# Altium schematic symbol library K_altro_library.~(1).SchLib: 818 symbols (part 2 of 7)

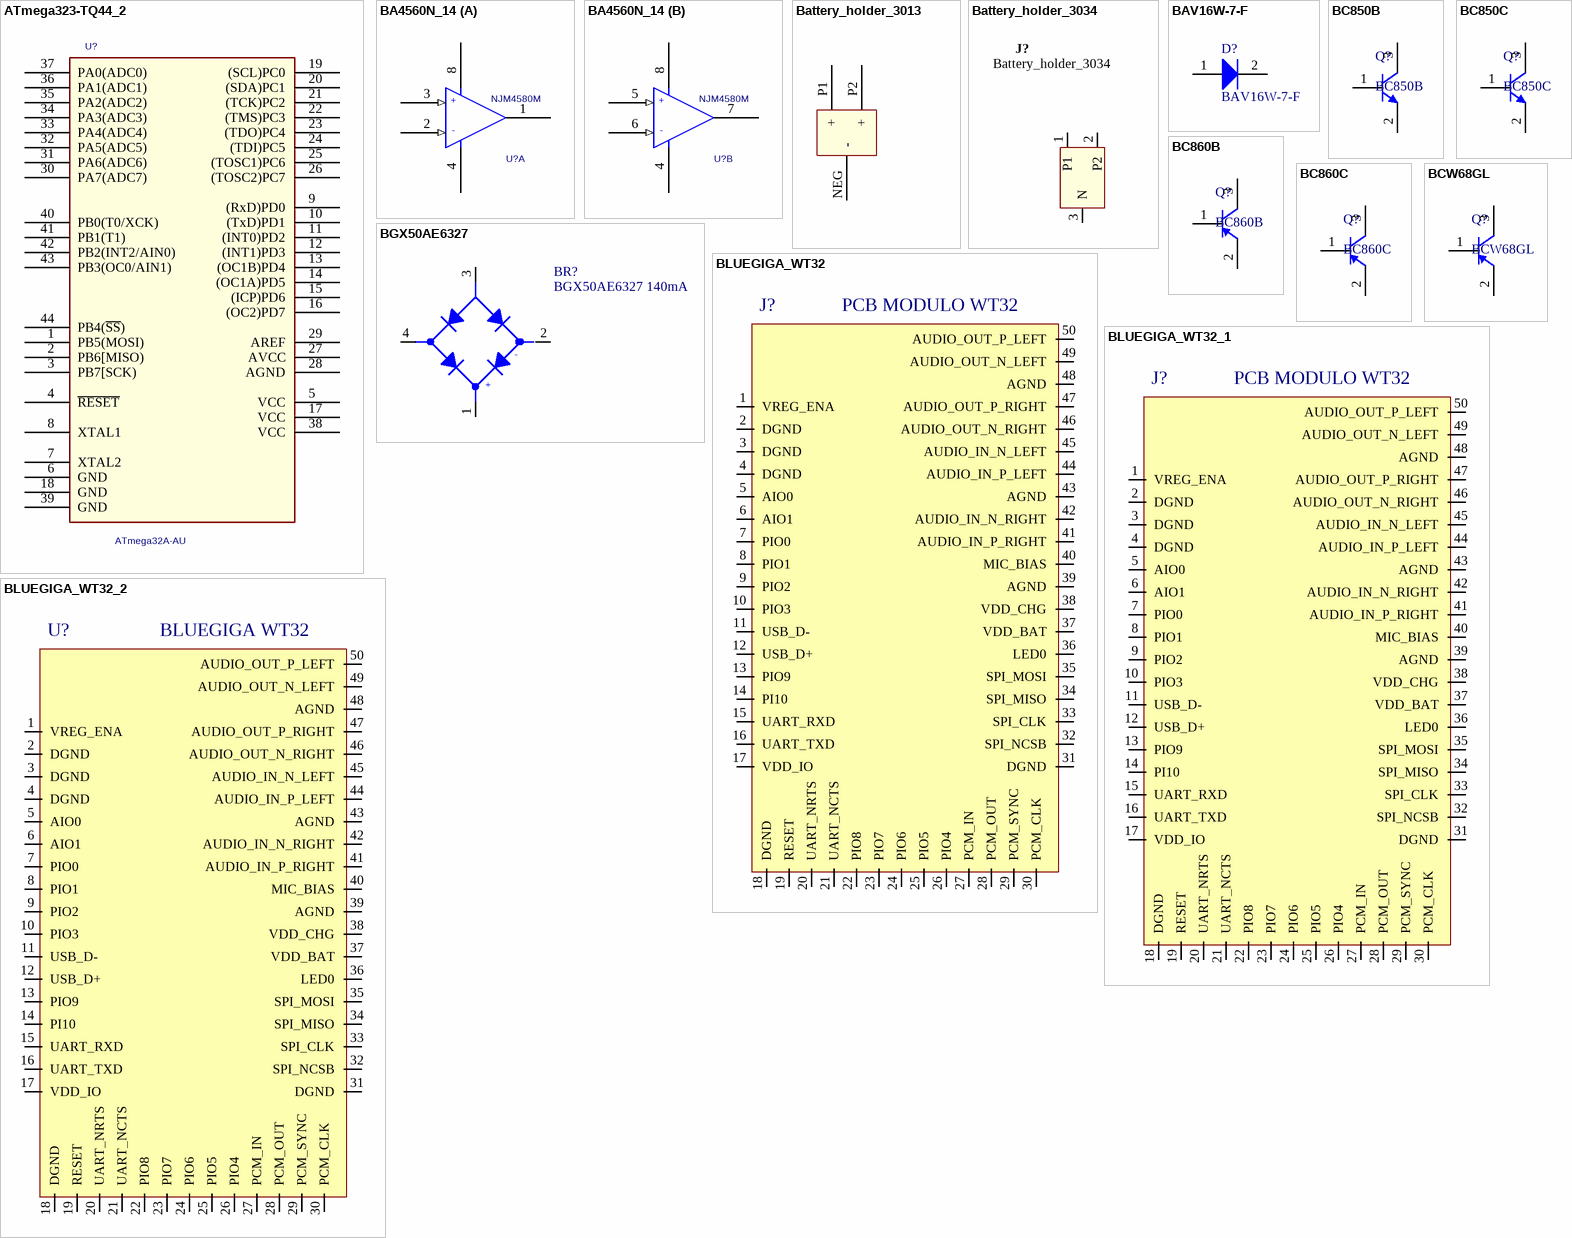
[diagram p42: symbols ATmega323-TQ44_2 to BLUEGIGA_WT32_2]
## Battery_holder_3034
designator J?
Aggiornato: s; Costo: 0,51; ContoLavoro: 0
footprint Battery_holder_Keystone_3034
pins: 1 P1, 2 P2, 3 N

## BAV16W-7-F
designator D?
Fast rectifier 100V, 300mA; Aggiornato: s; Costo: 0,178; ContoLavoro: 0
footprint SOD123
pins: 1 A, 2 k

## BC850B
designator Q?
BC850B General Purpose Transistor, NPN Silicon, 3-Pin SOT-23; MPN: BC850BLT1G; Costo: 0,037; Aggiornato: S; ContoLavoro: 0
footprint SOT-23_UP
simulation model QBC850B (BC850B)
pins: 1 B, 2 E, 3 C

## BC850C
designator Q?
BC850C General Purpose Transistor, NPN Silicon, 3-Pin SOT-23; Costo: 0,022; Aggiornato: S; ContoLavoro: 0
footprint SOT-23_UP
simulation model QBC850C (BC850C)
pins: 1 B, 2 E, 3 C

## BC860B
designator Q?
BC860B General Purpose Transistor, PNP Silicon, 3-Pin SOT-23; Costo: 0,016; Detail: (RS per >300pz); Aggiornato: S; ContoLavoro: 0
footprint SOT-23_UP
simulation model BC860B
pins: 1 B, 2 E, 3 C

## BC860C
designator Q?
BC860C General Purpose Transistor, PNP Silicon, 3-Pin SOT-23; Costo: 0,022; Aggiornato: S; ContoLavoro: 0
footprint SOT-23_UP
simulation model QBC860C (BC860C)
pins: 1 B, 2 E, 3 C

## BCW68GL
designator Q?
BCW68GL General Purpose Transistor, PNP Silicon, 3-Pin SOT-23; Costo: 0,037 €; Detail: 0,037 € 1000 pz MOUSER; Aggiornato: S; ContoLavoro: 0
footprint SOT23 -BCW68GL ((CASE-318 STYLE-6))
pins: 1 B, 2 E, 3 C

## BGX50AE6327
designator BR?, comment BGX50AE6327 140mA
BRIDGE DIODE 70V 140mA SOT143; Costo: 0,13772; Aggiornato: s; ContoLavoro: 0
footprint SOT143 - BGX50AE6327
pins: 1 AC1, 2 -DC, 3 AC2, 4 +DC

## BLUEGIGA_WT32
designator J?, comment PCB MODULO WT32
Aggiornato: NO; Costo: 0
footprint MODULO WT32
pins: 1 VREG_ENA, 2 DGND, 3 DGND, 4 DGND, 5 AIO0, 6 AIO1, 7 PIO0, 8 PIO1, 9 PIO2, 10 PIO3, 11 USB_D-, 12 USB_D+, 13 PIO9, 14 PI10, 15 UART_RXD, 16 UART_TXD, 17 VDD_IO, 18 DGND, 19 RESET, 20 UART_NRTS, 21 UART_NCTS, 22 PIO8, 23 PIO7, 24 PIO6, 25 PIO5, 26 PIO4, 27 PCM_IN, 28 PCM_OUT, 29 PCM_SYNC, 30 PCM_CLK, 31 DGND, 32 SPI_NCSB, 33 SPI_CLK, 34 SPI_MISO, 35 SPI_MOSI, 36 LED0, 37 VDD_BAT, 38 VDD_CHG, 39 AGND, 40 MIC_BIAS, 41 AUDIO_IN_P_RIGHT, 42 AUDIO_IN_N_RIGHT, 43 AGND, 44 AUDIO_IN_P_LEFT, 45 AUDIO_IN_N_LEFT, 46 AUDIO_OUT_N_RIGHT, 47 AUDIO_OUT_P_RIGHT, 48 AGND, 49 AUDIO_OUT_N_LEFT, 50 AUDIO_OUT_P_LEFT

## BLUEGIGA_WT32_1
designator J?, comment PCB MODULO WT32
Aggiornato: NO; Costo: 0
footprint MODULO WT32_MALE
pins: 1 VREG_ENA, 2 DGND, 3 DGND, 4 DGND, 5 AIO0, 6 AIO1, 7 PIO0, 8 PIO1, 9 PIO2, 10 PIO3, 11 USB_D-, 12 USB_D+, 13 PIO9, 14 PI10, 15 UART_RXD, 16 UART_TXD, 17 VDD_IO, 18 DGND, 19 RESET, 20 UART_NRTS, 21 UART_NCTS, 22 PIO8, 23 PIO7, 24 PIO6, 25 PIO5, 26 PIO4, 27 PCM_IN, 28 PCM_OUT, 29 PCM_SYNC, 30 PCM_CLK, 31 DGND, 32 SPI_NCSB, 33 SPI_CLK, 34 SPI_MISO, 35 SPI_MOSI, 36 LED0, 37 VDD_BAT, 38 VDD_CHG, 39 AGND, 40 MIC_BIAS, 41 AUDIO_IN_P_RIGHT, 42 AUDIO_IN_N_RIGHT, 43 AGND, 44 AUDIO_IN_P_LEFT, 45 AUDIO_IN_N_LEFT, 46 AUDIO_OUT_N_RIGHT, 47 AUDIO_OUT_P_RIGHT, 48 AGND, 49 AUDIO_OUT_N_LEFT, 50 AUDIO_OUT_P_LEFT

## BLUEGIGA_WT32_2
designator U?, comment BLUEGIGA WT32
Aggiornato: NO; Costo: 0
footprint BLUEGIGA_WT32
pins: 1 VREG_ENA, 2 DGND, 3 DGND, 4 DGND, 5 AIO0, 6 AIO1, 7 PIO0, 8 PIO1, 9 PIO2, 10 PIO3, 11 USB_D-, 12 USB_D+, 13 PIO9, 14 PI10, 15 UART_RXD, 16 UART_TXD, 17 VDD_IO, 18 DGND, 19 RESET, 20 UART_NRTS, 21 UART_NCTS, 22 PIO8, 23 PIO7, 24 PIO6, 25 PIO5, 26 PIO4, 27 PCM_IN, 28 PCM_OUT, 29 PCM_SYNC, 30 PCM_CLK, 31 DGND, 32 SPI_NCSB, 33 SPI_CLK, 34 SPI_MISO, 35 SPI_MOSI, 36 LED0, 37 VDD_BAT, 38 VDD_CHG, 39 AGND, 40 MIC_BIAS, 41 AUDIO_IN_P_RIGHT, 42 AUDIO_IN_N_RIGHT, 43 AGND, 44 AUDIO_IN_P_LEFT, 45 AUDIO_IN_N_LEFT, 46 AUDIO_OUT_N_RIGHT, 47 AUDIO_OUT_P_RIGHT, 48 AGND, 49 AUDIO_OUT_N_LEFT, 50 AUDIO_OUT_P_LEFT


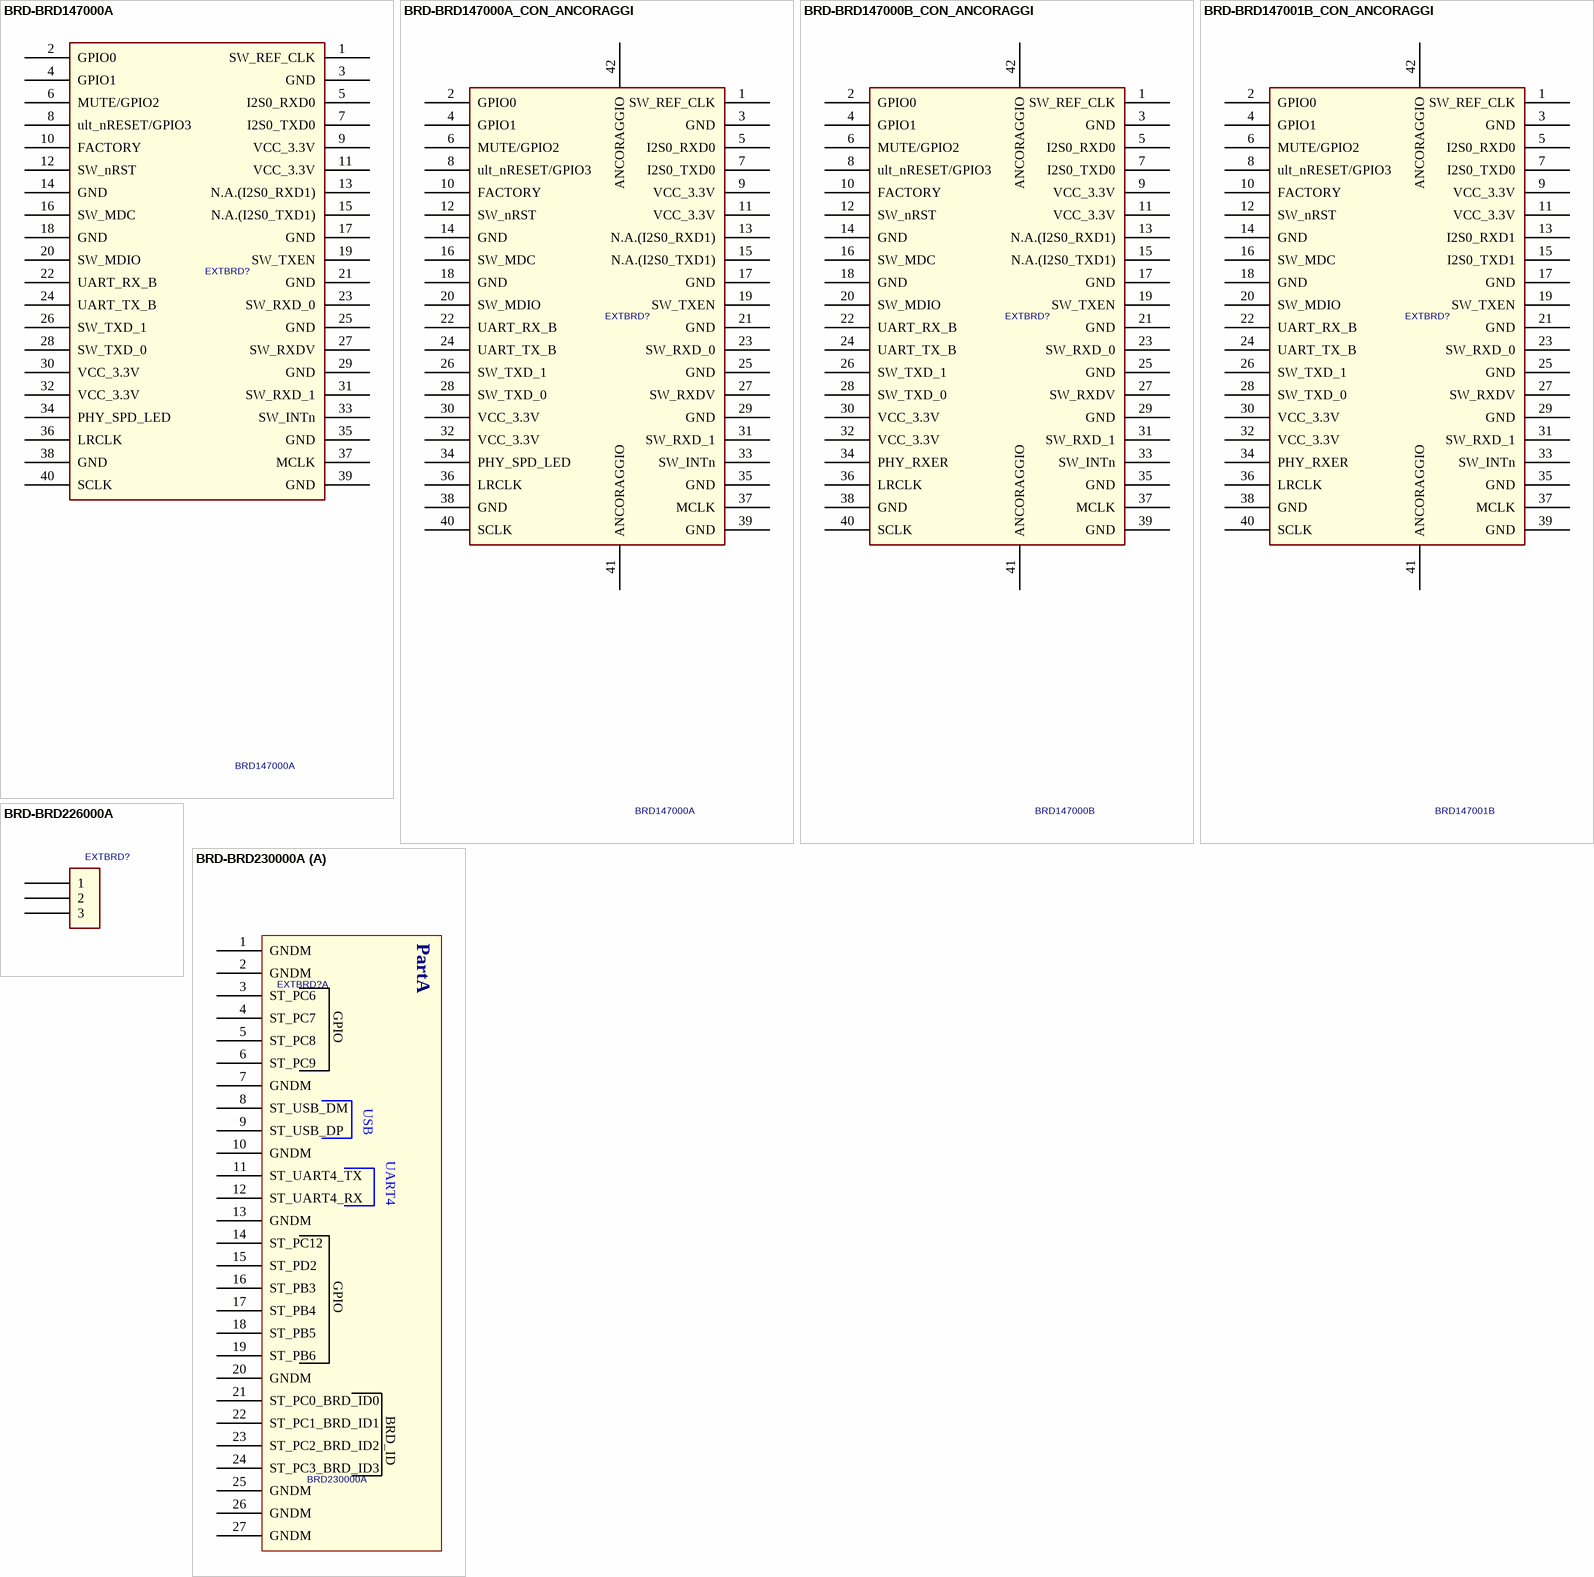
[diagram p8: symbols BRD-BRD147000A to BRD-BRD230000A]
## BRD-BRD147000A
designator EXTBRD?, comment BRD147000A  (no BOM)
BRD147000A Ultimo 2x2 module; Aggiornato: NO; Costo: 0
footprint BRD147000A_WITH_CONNECTOR (BRD147000A_Ultimo_2x2_module_vert)
pins: 1 SW_REF_CLK, 2 GPIO0, 3 GND, 4 GPIO1, 5 I2S0_RXD0, 6 MUTE/GPIO2, 7 I2S0_TXD0, 8 ult_nRESET/GPIO3, 9 VCC_3.3V, 10 FACTORY, 11 VCC_3.3V, 12 SW_nRST, 13 N.A.(I2S0_RXD1), 14 GND, 15 N.A.(I2S0_TXD1), 16 SW_MDC, 17 GND, 18 GND, 19 SW_TXEN, 20 SW_MDIO, 21 GND, 22 UART_RX_B, 23 SW_RXD_0, 24 UART_TX_B, 25 GND, 26 SW_TXD_1, 27 SW_RXDV, 28 SW_TXD_0, 29 GND, 30 VCC_3.3V, 31 SW_RXD_1, 32 VCC_3.3V, 33 SW_INTn, 34 PHY_SPD_LED, 35 GND, 36 LRCLK, 37 MCLK, 38 GND, 39 GND, 40 SCLK

## BRD-BRD147000A_CON_ANCORAGGI
designator EXTBRD?, comment BRD147000A  (no BOM)
BRD147000A Ultimo 2x2 module; Aggiornato: NO; Costo: 0
footprint BRD147000A_IBRID_CONN_VERT-CON_ANCORAGGI (BRD147000A_Ultimo_2x2_module_vert CON_ANCORAGGI)
pins: 1 SW_REF_CLK, 2 GPIO0, 3 GND, 4 GPIO1, 5 I2S0_RXD0, 6 MUTE/GPIO2, 7 I2S0_TXD0, 8 ult_nRESET/GPIO3, 9 VCC_3.3V, 10 FACTORY, 11 VCC_3.3V, 12 SW_nRST, 13 N.A.(I2S0_RXD1), 14 GND, 15 N.A.(I2S0_TXD1), 16 SW_MDC, 17 GND, 18 GND, 19 SW_TXEN, 20 SW_MDIO, 21 GND, 22 UART_RX_B, 23 SW_RXD_0, 24 UART_TX_B, 25 GND, 26 SW_TXD_1, 27 SW_RXDV, 28 SW_TXD_0, 29 GND, 30 VCC_3.3V, 31 SW_RXD_1, 32 VCC_3.3V, 33 SW_INTn, 34 PHY_SPD_LED, 35 GND, 36 LRCLK, 37 MCLK, 38 GND, 39 GND, 40 SCLK, 41 ANCORAGGIO, 42 ANCORAGGIO

## BRD-BRD147000B_CON_ANCORAGGI
designator EXTBRD?, comment BRD147000B  (no BOM)
BRD147000B Ultimo 2x2 module; Aggiornato: NO; Costo: 0
footprint BRD147000A_IBRID_CONN_VERT-CON_ANCORAGGI (BRD147000A_Ultimo_2x2_module_vert CON_ANCORAGGI)
pins: 1 SW_REF_CLK, 2 GPIO0, 3 GND, 4 GPIO1, 5 I2S0_RXD0, 6 MUTE/GPIO2, 7 I2S0_TXD0, 8 ult_nRESET/GPIO3, 9 VCC_3.3V, 10 FACTORY, 11 VCC_3.3V, 12 SW_nRST, 13 N.A.(I2S0_RXD1), 14 GND, 15 N.A.(I2S0_TXD1), 16 SW_MDC, 17 GND, 18 GND, 19 SW_TXEN, 20 SW_MDIO, 21 GND, 22 UART_RX_B, 23 SW_RXD_0, 24 UART_TX_B, 25 GND, 26 SW_TXD_1, 27 SW_RXDV, 28 SW_TXD_0, 29 GND, 30 VCC_3.3V, 31 SW_RXD_1, 32 VCC_3.3V, 33 SW_INTn, 34 PHY_RXER, 35 GND, 36 LRCLK, 37 MCLK, 38 GND, 39 GND, 40 SCLK, 41 ANCORAGGIO, 42 ANCORAGGIO

## BRD-BRD147001B_CON_ANCORAGGI
designator EXTBRD?, comment BRD147001B  (no BOM)
BRD147001B Ultimo 4x4 module; Aggiornato: NO; Costo: 0
footprint BRD147000A_IBRID_CONN_VERT-CON_ANCORAGGI (BRD147000A_Ultimo_2x2_module_vert CON_ANCORAGGI)
pins: 1 SW_REF_CLK, 2 GPIO0, 3 GND, 4 GPIO1, 5 I2S0_RXD0, 6 MUTE/GPIO2, 7 I2S0_TXD0, 8 ult_nRESET/GPIO3, 9 VCC_3.3V, 10 FACTORY, 11 VCC_3.3V, 12 SW_nRST, 13 I2S0_RXD1, 14 GND, 15 I2S0_TXD1, 16 SW_MDC, 17 GND, 18 GND, 19 SW_TXEN, 20 SW_MDIO, 21 GND, 22 UART_RX_B, 23 SW_RXD_0, 24 UART_TX_B, 25 GND, 26 SW_TXD_1, 27 SW_RXDV, 28 SW_TXD_0, 29 GND, 30 VCC_3.3V, 31 SW_RXD_1, 32 VCC_3.3V, 33 SW_INTn, 34 PHY_RXER, 35 GND, 36 LRCLK, 37 MCLK, 38 GND, 39 GND, 40 SCLK, 41 ANCORAGGIO, 42 ANCORAGGIO

## BRD-BRD226000A
designator EXTBRD?, comment BRD226000A  (no BOM)
Aggiornato: NO; Costo: 0
footprint BRD226000A (BRD147000A_Ultimo_2x2_module_vert)
pins: 1, 2, 3


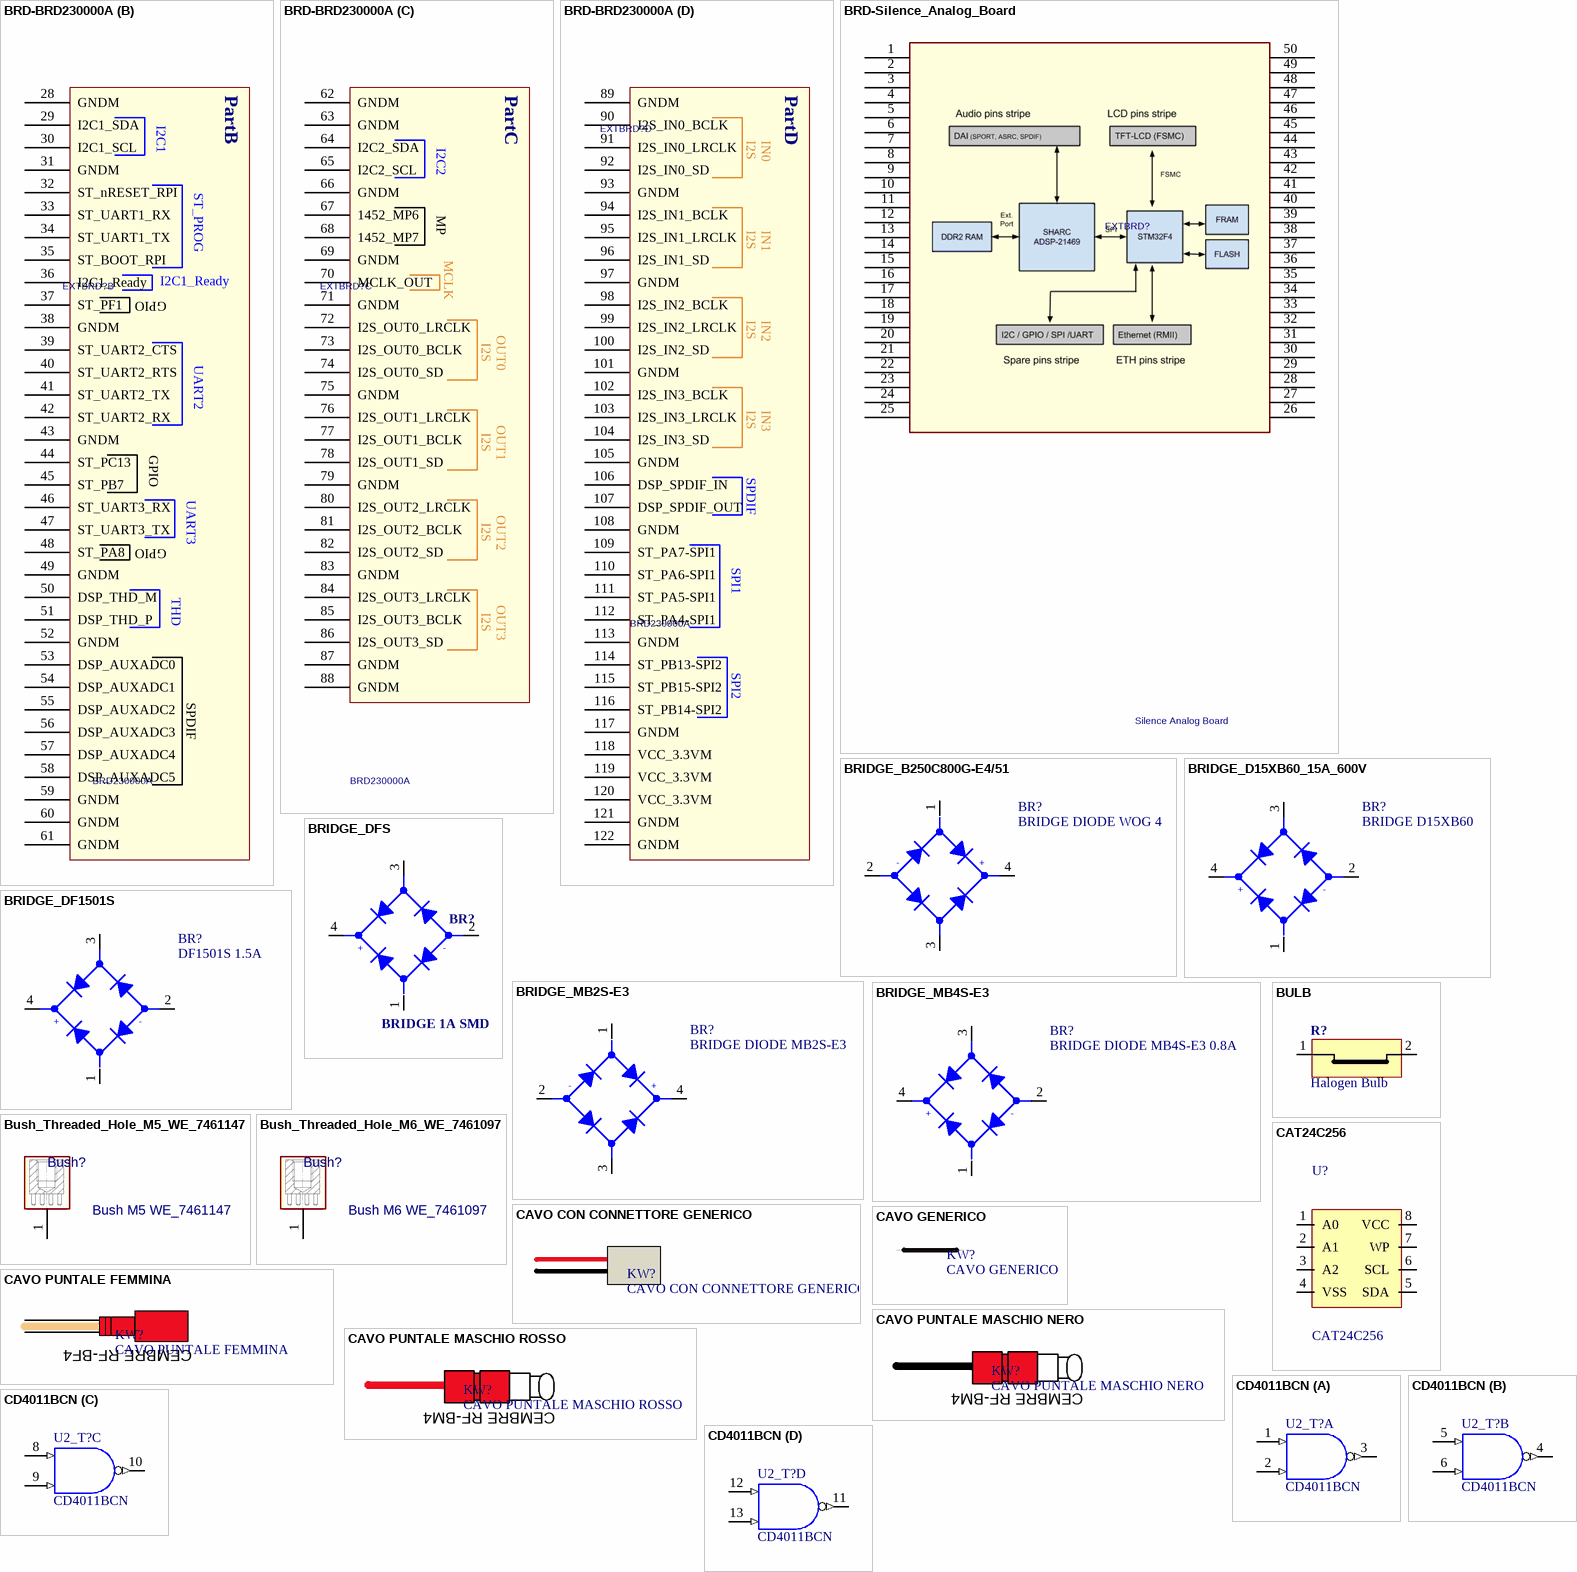
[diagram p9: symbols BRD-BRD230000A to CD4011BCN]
## BRD-BRD230000A
designator EXTBRD?, comment BRD230000A  (no BOM)
Aggiornato: NO; Costo: 0
footprint BRD230000A (Footprint not found)
footprint BRD230000A_with_RB_reference (BRD230000A with RB reference)
part A pins: 1 GNDM, 2 GNDM, 3 ST_PC6, 4 ST_PC7, 5 ST_PC8, 6 ST_PC9, 7 GNDM, 8 ST_USB_DM, 9 ST_USB_DP, 10 GNDM, 11 ST_UART4_TX, 12 ST_UART4_RX, 13 GNDM, 14 ST_PC12, 15 ST_PD2, 16 ST_PB3, 17 ST_PB4, 18 ST_PB5, 19 ST_PB6, 20 GNDM, 21 ST_PC0_BRD_ID0, 22 ST_PC1_BRD_ID1, 23 ST_PC2_BRD_ID2, 24 ST_PC3_BRD_ID3, 25 GNDM, 26 GNDM, 27 GNDM
part B pins: 28 GNDM, 29 I2C1_SDA, 30 I2C1_SCL, 31 GNDM, 32 ST_nRESET_RPI, 33 ST_UART1_RX, 34 ST_UART1_TX, 35 ST_BOOT_RPI, 36 I2C1_Ready, 37 ST_PF1, 38 GNDM, 39 ST_UART2_CTS, 40 ST_UART2_RTS, 41 ST_UART2_TX, 42 ST_UART2_RX, 43 GNDM, 44 ST_PC13, 45 ST_PB7, 46 ST_UART3_RX, 47 ST_UART3_TX, 48 ST_PA8, 49 GNDM, 50 DSP_THD_M, 51 DSP_THD_P, 52 GNDM, 53 DSP_AUXADC0, 54 DSP_AUXADC1, 55 DSP_AUXADC2, 56 DSP_AUXADC3, 57 DSP_AUXADC4, 58 DSP_AUXADC5, 59 GNDM, 60 GNDM, 61 GNDM
part C pins: 62 GNDM, 63 GNDM, 64 I2C2_SDA, 65 I2C2_SCL, 66 GNDM, 67 1452_MP6, 68 1452_MP7, 69 GNDM, 70 MCLK_OUT, 71 GNDM, 72 I2S_OUT0_LRCLK, 73 I2S_OUT0_BCLK, 74 I2S_OUT0_SD, 75 GNDM, 76 I2S_OUT1_LRCLK, 77 I2S_OUT1_BCLK, 78 I2S_OUT1_SD, 79 GNDM, 80 I2S_OUT2_LRCLK, 81 I2S_OUT2_BCLK, 82 I2S_OUT2_SD, 83 GNDM, 84 I2S_OUT3_LRCLK, 85 I2S_OUT3_BCLK, 86 I2S_OUT3_SD, 87 GNDM, 88 GNDM
part D pins: 89 GNDM, 90 I2S_IN0_BCLK, 91 I2S_IN0_LRCLK, 92 I2S_IN0_SD, 93 GNDM, 94 I2S_IN1_BCLK, 95 I2S_IN1_LRCLK, 96 I2S_IN1_SD, 97 GNDM, 98 I2S_IN2_BCLK, 99 I2S_IN2_LRCLK, 100 I2S_IN2_SD, 101 GNDM, 102 I2S_IN3_BCLK, 103 I2S_IN3_LRCLK, 104 I2S_IN3_SD, 105 GNDM, 106 DSP_SPDIF_IN, 107 DSP_SPDIF_OUT, 108 GNDM, 109 ST_PA7-SPI1, 110 ST_PA6-SPI1, 111 ST_PA5-SPI1, 112 ST_PA4-SPI1, 113 GNDM, 114 ST_PB13-SPI2, 115 ST_PB15-SPI2, 116 ST_PB14-SPI2, 117 GNDM, 118 VCC_3.3VM, 119 VCC_3.3VM, 120 VCC_3.3VM, 121 GNDM, 122 GNDM

## BRD-Silence_Analog_Board
designator EXTBRD?, comment Silence Analog Board
Aggiornato: NO; Costo: 0
footprint BRD_SILENCE_ANALOG_BOARD_SOCKET
pins: 1, 2, 3, 4, 5, 6, 7, 8, 9, 10, 11, 12, 13, 14, 15, 16, 17, 18, 19, 20, 21, 22, 23, 24, 25, 26, 27, 28, 29, 30, 31, 32, 33, 34, 35, 36, 37, 38, 39, 40, 41, 42, 43, 44, 45, 46, 47, 48, 49, 50

## BRIDGE_B250C800G-E4/51
designator BR?, comment BRIDGE DIODE WOG 4
MPN: B250C800G-E4/51; Costo: 0,434; Aggiornato: NO; ContoLavoro: 0
footprint TO-269AA
footprint BRIDGE AM106
pins: 1 AC1, 2 -DC, 3 AC2, 4 +DC

## BRIDGE_D15XB60_15A_600V
designator BR?, comment BRIDGE D15XB60
BRIDGE D15XB60 15A 600V; Costo: 0; Aggiornato: NO
pins: 1 AC1, 2 -DC, 3 AC2, 4 +DC

## BRIDGE_DF1501S
designator BR?, comment DF1501S 1.5A
BRIDGE DIODE DF1501S 100V 1.5A; MPN: DF1501S-E3/77; Costo: 0,3; Aggiornato: s; ContoLavoro: 0
footprint DFS_BRIDGE
pins: 1 AC1, 2 -DC, 3 AC2, 4 +DC

## BRIDGE_DFS
designator BR?, comment BRIDGE 1A SMD
Full Wave Diode Bridge; Aggiornato: NO; Costo: 0
footprint DFS_BRIDGE
pins: 1 AC1, 2 -DC, 3 AC2, 4 +DC

## BRIDGE_MB2S-E3
designator BR?, comment BRIDGE DIODE MB2S-E3
Aggiornato: NO; Costo: 0
footprint TO-269AA
pins: 1 AC1, 2 -DC, 3 AC2, 4 +DC

## BRIDGE_MB4S-E3
designator BR?, comment BRIDGE DIODE MB4S-E3 0.8A
Costo: 0,366; Aggiornato: NO; ContoLavoro: 0
footprint TO-269AA
pins: 1 AC1, 2 -DC, 3 AC2, 4 +DC

## BULB
designator R?, comment Halogen Bulb
Hpcode: HALOGENBULB01; Aggiornato: NO; Costo: 0
footprint Halogen Bulb SETCROSSOVER ZHAL_V2
footprint Halogen Bulb SETCROSSOVER ZHAL_V2
footprint Halogen Bulb SETCROSSOVER ZHAL_V3
footprint Halogen Bulb SETCROSSOVER ZHAL_V1
pins: 1 VSS, 2 VSS

## Bush_Threaded_Hole_M5_WE_7461147
designator Bush?, comment Bush M5 WE_7461147
Bush_Threaded_Hole_M5_WE_7461147; Detail: Costo da verificare.; Costo: 3€; Aggiornato: NO; ContoLavoro: 0
footprint WE-7461147
pins: 1 Bush

## Bush_Threaded_Hole_M6_WE_7461097
designator Bush?, comment Bush M6 WE_7461097
Bush_Threaded_Hole_M6_WE_7461097; Detail: Costo da verificare.; Costo: 3€; Aggiornato: NO; ContoLavoro: 0
footprint WE-7461097
pins: 1 Bush

## CAT24C256
designator U?
CAT24C256 Serial  EEPROM 256K; Costo: 0,29; Aggiornato: S; ContoLavoro: 0
footprint SO8
footprint SOIC150-8N
pins: 1 A0, 2 A1, 3 A2, 4 VSS, 5 SDA, 6 SCL, 7 WP, 8 VCC

## CAVO CON CONNETTORE GENERICO
designator KW?  (mechanical)
Aggiornato: SI; Costo: 0; ContoLavoro: 1

## CAVO GENERICO
designator KW?  (mechanical)
Aggiornato: SI; Costo: 0; ContoLavoro: 1

## CAVO PUNTALE FEMMINA
designator KW?
Aggiornato: SI; Costo: 0; ContoLavoro: 1

## CAVO PUNTALE MASCHIO NERO
designator KW?
Aggiornato: SI; Costo: 0; ContoLavoro: 1

## CAVO PUNTALE MASCHIO ROSSO
designator KW?
Aggiornato: SI; Costo: 0; ContoLavoro: 1

## CD4011BCN
designator U2_T?
Quad 2-Input NAND Buffered B series Gate, 14-Pin PDIP; Aggiornato: NO; Costo: 0
footprint N14A (DIP, 14-Leads, Row Spacing 7.62mm, Pitch 2.54mm, Body 19.18x6.35mm)
3D model N14A (DIP, 14-Pin, Row Spacing 7.62 mm, Pitch 2.54 mm)
simulation model FSC_4011 (SIMCODE)
pins on every part: 7 GND_T (power) hidden to GND, 14 +12V_T (power) hidden to VDD
part A pins: 1 A (in), 2 B (in), 3 J (out)
part B pins: 4 J (out), 5 A (in), 6 B (in)
part C pins: 8 A (in), 9 F (in), 10 J (out)
part D pins: 11 J (out), 12 A (in), 13 B (in)


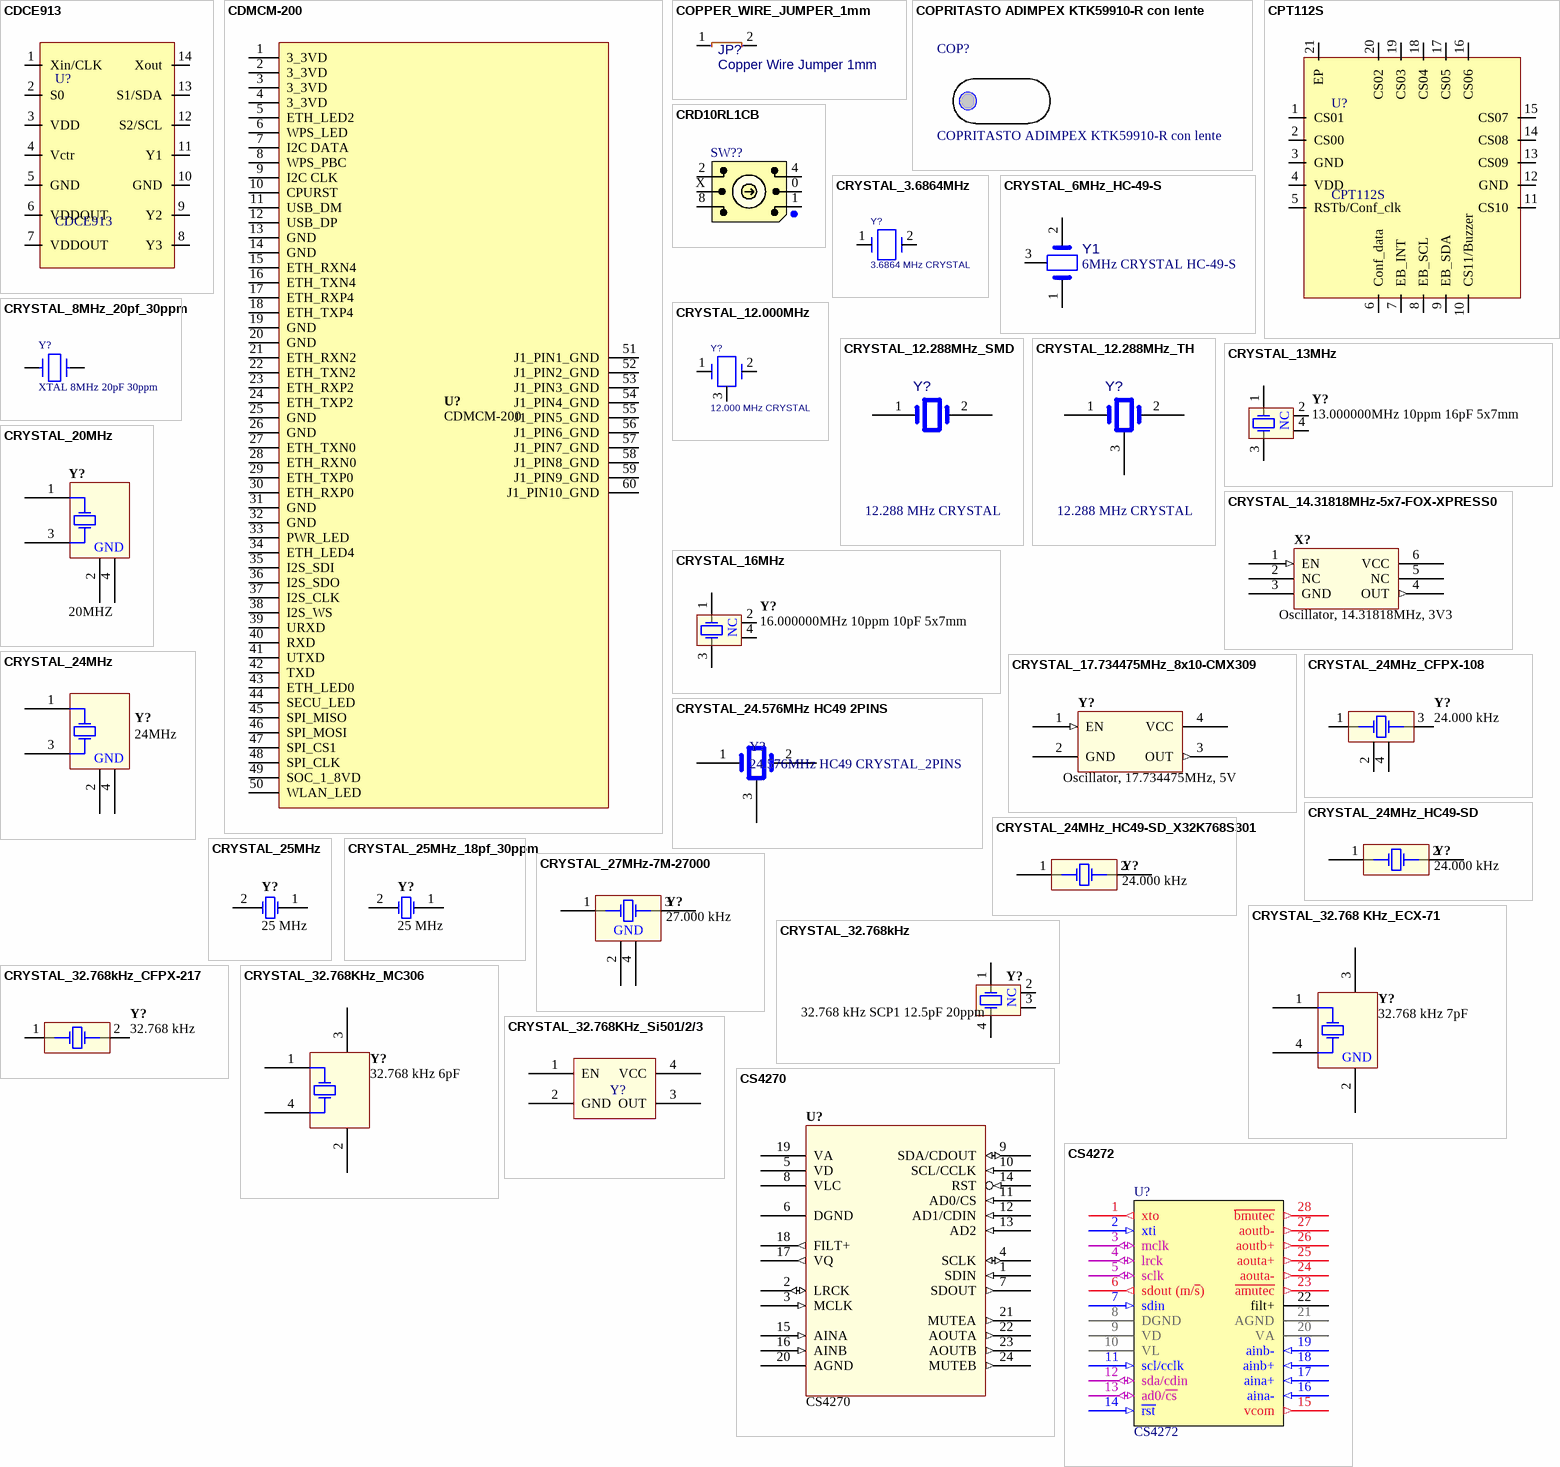
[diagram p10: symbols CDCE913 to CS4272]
## CDCE913
designator U?
Detail: 2,21€ >250pz Mouser 595-CDCE913PWR; Costo: 2,21€; Aggiornato: S; ContoLavoro: 0
footprint TSSOP14
pins: 1 Xin/CLK, 2 S0, 3 VDD, 4 Vctr, 5 GND, 6 VDDOUT, 7 VDDOUT, 8 Y3, 9 Y2, 10 GND, 11 Y1, 12 S2/SCL, 13 S1/SDA, 14 Xout

## CDMCM-200
designator U?
CDMCM-200 WI-FI Audio Module; Aggiornato: NO; Costo: 0
footprint CDMCM-200 (Footprint not found)
pins: 1 3_3VD, 2 3_3VD, 3 3_3VD, 4 3_3VD, 5 ETH_LED2, 6 WPS_LED, 7 I2C DATA, 8 WPS_PBC, 9 I2C CLK, 10 CPURST, 11 USB_DM, 12 USB_DP, 13 GND, 14 GND, 15 ETH_RXN4, 16 ETH_TXN4, 17 ETH_RXP4, 18 ETH_TXP4, 19 GND, 20 GND, 21 ETH_RXN2, 22 ETH_TXN2, 23 ETH_RXP2, 24 ETH_TXP2, 25 GND, 26 GND, 27 ETH_TXN0, 28 ETH_RXN0, 29 ETH_TXP0, 30 ETH_RXP0, 31 GND, 32 GND, 33 PWR_LED, 34 ETH_LED4, 35 I2S_SDI, 36 I2S_SDO, 37 I2S_CLK, 38 I2S_WS, 39 URXD, 40 RXD, 41 UTXD, 42 TXD, 43 ETH_LED0, 44 SECU_LED, 45 SPI_MISO, 46 SPI_MOSI, 47 SPI_CS1, 48 SPI_CLK, 49 SOC_1_8VD, 50 WLAN_LED, 51 J1_PIN1_GND, 52 J1_PIN2_GND, 53 J1_PIN3_GND, 54 J1_PIN4_GND, 55 J1_PIN5_GND, 56 J1_PIN6_GND, 57 J1_PIN7_GND, 58 J1_PIN8_GND, 59 J1_PIN9_GND, 60 J1_PIN10_GND

## COPPER_WIRE_JUMPER_1mm
designator JP?, comment Copper Wire Jumper 1mm
Copper Wire Jumper D=1mm; Hpcode: MMBLC061; Costo: 0,1; Value: 0; Aggiornato: S
footprint HARWIN_D3080-05 (HARWIN D3080-05)
simulation model Resistor
pins: 1, 2

## COPRITASTO ADIMPEX KTK59910-R con lente
designator COP?  (mechanical)
Costo: 0; Aggiornato: NO; Detail: 0,06€ 1000pz WE offerta A18IT013140.pdf
pins: 1 hidden
1 alternate drawing of the same symbol

## CPT112S
designator U?
Capacitive touch controller via I2C; Hpcode: ICCPT112S; Costo: 0; Aggiornato: n; ContoLavoro: 1
footprint QFN20_EP_CPT112S
pins: 1 CS01, 2 CS00, 3 GND, 4 VDD, 5 RSTb/Conf_clk, 6 Conf_data, 7 EB_INT, 8 EB_SCL, 9 EB_SDA, 10 CS11/Buzzer, 11 CS10, 12 GND, 13 CS09, 14 CS08, 15 CS07, 16 CS06, 17 CS05, 18 CS04, 19 CS03, 20 CS02, 21 EP

## CRD10RL1CB
designator SW??, comment 0.4VA  (value not drawn)
DIP-Coded Rotary Switch 10-Position BCD 0.4VA, DC20V Body (10x10)mm CRD Series; Voltage: 20V; Aggiornato: NO; Costo: 0
footprint CRD10R_itt-cannon
pins: 0, 1, 2, 4, 8, X
1 alternate drawing of the same symbol

## CRYSTAL_3.6864MHz
designator Y?, comment 3.6864 MHz CRYSTAL
Aggiornato: NO; Costo: 0
footprint CRYSTAL
pins: 1, 2

## CRYSTAL_6MHz_HC-49-S
designator Y1, comment 6MHz CRYSTAL HC-49-S
Crystal 6MHz HC-49-S; Detail: (RS per >500pz); Costo: 0,23; Aggiornato: s; ContoLavoro: 0
footprint CRYSTAL_3PINS
pins: 1, 2, 3

## CRYSTAL_8MHz_20pf_30ppm
designator Y?, comment XTAL 8MHz 20pF 30ppm
8MHz 20pF 30ppm; Aggiornato: Si; Costo: 0,2065; ContoLavoro: 0
footprint qz_sx_smd_hc49
pins: 1, 2
2 alternate drawings of the same symbol

## CRYSTAL_12.000MHz
designator Y?, comment 12.000 MHz CRYSTAL
Detail: ADIMPEX LQS12.000; Aggiornato: NO; Costo: 0
footprint CRISTAL
pins: 1, 2, 3

## CRYSTAL_12.288MHz_SMD
designator Y?, comment 12.288 MHz CRYSTAL
Costo: 0,3; Aggiornato: S; ContoLavoro: 0
footprint qz_sx_smd_hc49
pins: 1, 2

## CRYSTAL_12.288MHz_TH
designator Y?, comment 12.288 MHz CRYSTAL
Detail: Disrelec > 100pz; Costo: 0,58; Aggiornato: NO; ContoLavoro: 0
footprint CRYSTAL_3PINS
pins: 1, 2, 3

## CRYSTAL_13MHz
designator Y?, comment 13.000000MHz 10ppm 16pF 5x7mm
Crystal, 13.000000MHz, 5x7mm, 10ppm 10ppm 16pF; Nominal Fequency: 13 MHz; Nominal Operational Voltage: mV; Aggiornato: NO; Costo: 0
footprint XTAL-7X5
pins: 1 X1, 2 NC, 3 X2, 4 NC

## CRYSTAL_14.31818MHz-5x7-FOX-XPRESS0
designator X?, comment Oscillator, 14.31818MHz, 3V3
Crystal Oscillator, 14.31818MHz, 3V3, 5x7mm, 50ppm, Fox, FXO-HC735R-14.31818; Aggiornato: NO; Costo: 0
footprint OSCILLATOR-5x7-FOX-XPRESS0
pins: 1 EN (in), 2 NC, 3 GND (power), 4 OUT (out), 5 NC, 6 VCC (power)

## CRYSTAL_16MHz
designator Y?, comment 16.000000MHz 10ppm 10pF 5x7mm
Crystal, 16.000000MHz, 5x7mm, 10ppm 10ppm 10pF; Nominal Fequency: 16 MHz; Nominal Operational Voltage: mV; Aggiornato: NO; Costo: 0
footprint XTAL-7X5
pins: 1 X1, 2 NC, 3 X2, 4 NC

## CRYSTAL_17.734475MHz_8x10-CMX309
designator Y?, comment Oscillator, 17.734475MHz, 5V
Crystal Oscillator, 17.734475MHz, 50ppm, 5V, 8x10mm, SMD; Aggiornato: NO; Costo: 0
footprint OSCILLATOR-8x10-CMX309
pins: 1 EN (in), 2 GND (power), 3 OUT (out), 4 VCC (power)

## CRYSTAL_20MHz
designator Y?, comment 20MHZ
Crystal, SMD, 20.000000MHz Stab=30ppm 20.0pF; Frequency Stability: 30 ppm; Load Capacitance: 20 pF; Nominal Operational Voltage: mV; Aggiornato: NO; Costo: 0
footprint XTAL-200X126-4
pins: 1 X1, 2 GND, 3 X2, 4 GND

## CRYSTAL_24.576MHz HC49 2PINS
designator Y?, comment 24.576MHz HC49 CRYSTAL_2PINS
Detail: prezzo RS >500pz; Costo: 0,32; ContoLavoro: 0
footprint CRYSTAL_3PINS
pins: 1, 2, 3

## CRYSTAL_24MHz
designator Y?, comment 24MHz
Crystal, SMD, 24.000000MHz Stab=30ppm 20.0pF; Frequency Stability: 30 ppm; Load Capacitance: 20 pF; Nominal Operational Voltage: mV; Aggiornato: NO; Costo: 0
footprint XTAL-200X126-4
pins: 1 X1, 2 GND, 3 X2, 4 GND

## CRYSTAL_24MHz_CFPX-108
designator Y?, comment 24.000 kHz
Crystal, 24MHz CFPX-108; Aggiornato: s; Costo: 0,26; Detail: Offerta WE A21IT006030 0,26€ per1000pz 0,16 per 3000pz; ContoLavoro: 0
footprint CFPX-108 (Footprint not found)
pins: 1 X1, 2 GND, 3 X2, 4 GND

## CRYSTAL_24MHz_HC49-SD
designator Y?, comment 24.000 kHz
Crystal, 24MHz HC49-SD; Aggiornato: n; Costo: 0
footprint HC49-SD (Footprint not found)
pins: 1 X1, 2 X2

## CRYSTAL_24MHz_HC49-SD_X32K768S301
designator Y?, comment 24.000 kHz
Crystal, 24MHz HC49-SD; Aggiornato: n; Costo: 0
footprint HC49-SD (Footprint not found)
pins: 1 X1, 2 X2

## CRYSTAL_25MHz
designator Y?, comment 25 MHz
Crystal, 25 MHz  +/-30ppm 20pf HC49SMD; Frequency Stability: 30 ppm; Nominal Operational Voltage: mV; Aggiornato: NO; Costo: 0
footprint XTAL_HC49SMD
pins: 1 OSC1, 2 OSC2

## CRYSTAL_25MHz_18pf_30ppm
designator Y?, comment 25 MHz
CRYSTAL_25MHz_18pf_30ppm; Aggiornato: s; Costo: 0,40; ContoLavoro: 0
footprint qz_sx_smd_hc49
pins: 1 OSC1, 2 OSC2

## CRYSTAL_27MHz-7M-27000
designator Y?, comment 27.000 kHz
Crystal, 27MHz 7M-27.000 MEEQ-T; Aggiornato: s; Costo: 1,08; HPcode: QUARZ27MHZ; ContoLavoro: 1
footprint QZ_SMALL_SMD
pins: 1 X1, 2 GND, 3 X2, 4 GND

## CRYSTAL_32.768 KHz_ECX-71
designator Y?, comment 32.768 kHz 7pF
Crystal, 32.768 KHz Surface Mount; Aggiornato: NO; Costo: 0
footprint ECS-71
pins: 1 X1, 2 GND, 3 X2, 4 GND

## CRYSTAL_32.768kHz
designator Y?, comment 32.768 kHz SCP1 12.5pF 20ppm
Crystal, 32.768 kHz, Surface Mount SCP1, 12.5pF, 20ppm; Frequency Stability: parabolic ppm; Nominal Operational Voltage: mV; Aggiornato: NO; Costo: 0
footprint XTAL-SCP1
pins: 1 X1, 2 NC, 3 NC, 4 X2

## CRYSTAL_32.768kHz_CFPX-217
designator Y?, comment 32.768 kHz
Crystal 32.768 kHz CFPX-217; Aggiornato: s; Costo: 0,285; Detail: Offerta WE A21IT006030 0,285 € per 1000pz 0,175€ per 3000pz; ContoLavoro: 0
footprint CFPX-217 (Footprint not found)
pins: 1 X1, 2 X2

## CRYSTAL_32.768KHz_MC306
designator Y?, comment 32.768 kHz 6pF
Crystal, 32.768KHz MC306; Aggiornato: s; Costo: 1; ContoLavoro: 0
footprint QZ_MC306
pins: 1, 2, 3, 4

## CRYSTAL_32.768KHz_Si501/2/3
designator Y?
32.768kHz Oscillator (EPSON  X1B0002110001 SG-3030CM); Costo: 0; Aggiornato: N
footprint CRYSTAL_3.2X1.5MM_4P_SMD
pins: 1 EN, 2 GND, 3 OUT, 4 VCC

## CS4270
designator U?
CS4270; 24-Bit, 192 kHz Stereo Audio CODEC; Supply Voltage: mV; Aggiornato: NO; Costo: 0
footprint TSSOP-24
pins: 1 SDIN (in), 2 LRCK (io), 3 MCLK (in), 4 SCLK (io), 5 VD (power), 6 DGND (power), 7 SDOUT (out), 8 VLC (power), 9 SDA/CDOUT (io), 10 SCL/CCLK (in), 11 AD0/CS (in), 12 AD1/CDIN (in), 13 AD2 (in), 14 RST (in), 15 AINA (in), 16 AINB (in), 17 VQ (out), 18 FILT+ (out), 19 VA (power), 20 AGND (power), 21 MUTEA (out), 22 AOUTA (out), 23 AOUTB (out), 24 MUTEB (out)

## CS4272
designator U?
CODEC AUDIO CS4272; Costo: 2,62; Hpcode: ICCIRCS4272-CZZ; Aggiornato: S; ContoLavoro: 0
footprint SSOP_28
pins: 1 xto (out), 2 xti (in), 3 mclk (io), 4 lrck (io), 5 sclk (io), 6 sdout (m/~{s}) (out), 7 sdin (in), 8 DGND (power), 9 VD (power), 10 VL (power), 11 scl/cclk (in), 12 sda/cdin (io), 13 ad0/~{cs} (io), 14 ~{rst} (in), 15 vcom (out), 16 aina- (in), 17 aina+ (in), 18 ainb+ (in), 19 ainb- (in), 20 VA (power), 21 AGND (power), 22 filt+, 23 ~{amutec} (out), 24 aouta- (out), 25 aouta+ (out), 26 aoutb+ (out), 27 aoutb- (out), 28 ~{bmutec} (out)


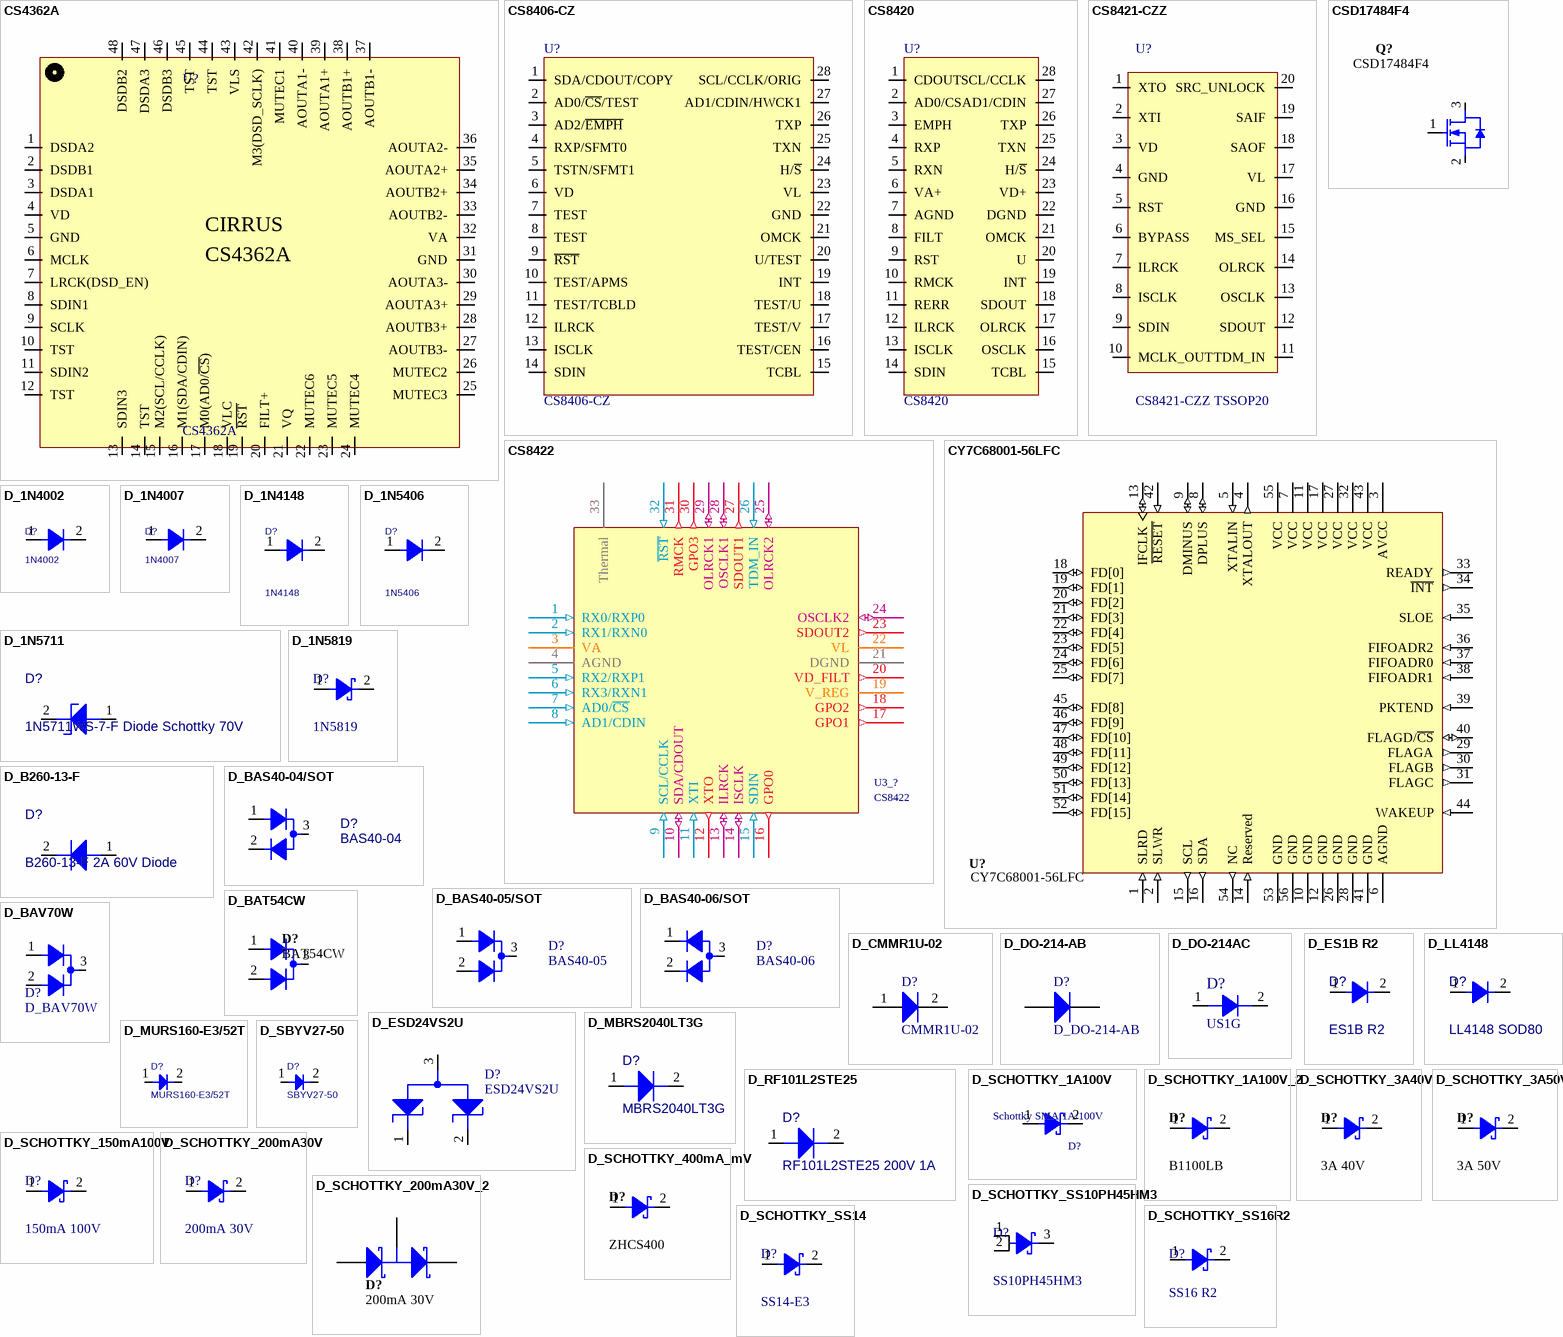
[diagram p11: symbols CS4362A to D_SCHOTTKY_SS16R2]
## CS4362A
designator U?
Costo: 2,8; Aggiornato: S; ContoLavoro: 0
footprint LQFP-48
pins: 1 DSDA2, 2 DSDB1, 3 DSDA1, 4 VD, 5 GND, 6 MCLK, 7 LRCK(DSD_EN), 8 SDIN1, 9 SCLK, 10 TST, 11 SDIN2, 12 TST, 13 SDIN3, 14 TST, 15 M2(SCL/CCLK), 16 M1(SDA/CDIN), 17 M0(AD0/~{CS}), 18 VLC, 19 ~{RST}, 20 FILT+, 21 VQ, 22 MUTEC6, 23 MUTEC5, 24 MUTEC4, 25 MUTEC3, 26 MUTEC2, 27 AOUTB3-, 28 AOUTB3+, 29 AOUTA3+, 30 AOUTA3-, 31 GND, 32 VA, 33 AOUTB2-, 34 AOUTB2+, 35 AOUTA2+, 36 AOUTA2-, 37 AOUTB1-, 38 AOUTB1+, 39 AOUTA1+, 40 AOUTA1-, 41 MUTEC1, 42 M3(DSD_SCLK), 43 VLS, 44 TST, 45 TST, 46 DSDB3, 47 DSDA3, 48 DSDB2

## CS8406-CZ
designator U?
Costo: 4; Aggiornato: s; ContoLavoro: 0
footprint tssop28_n (TSOP, 28-Leads, Body 9.7x4.4mm, Pitch 0.65mm, IPC Medium Density)
pins: 1 SDA/CDOUT/COPY, 2 AD0/~{CS}/TEST, 3 AD2/~{EMPH}, 4 RXP/SFMT0, 5 TSTN/SFMT1, 6 VD, 7 TEST, 8 TEST, 9 ~{RST}, 10 TEST/APMS, 11 TEST/TCBLD, 12 ILRCK, 13 ISCLK, 14 SDIN, 15 TCBL, 16 TEST/CEN, 17 TEST/V, 18 TEST/U, 19 INT, 20 U/TEST, 21 OMCK, 22 GND, 23 VL, 24 H/~{S}, 25 TXN, 26 TXP, 27 AD1/CDIN/HWCK1, 28 SCL/CCLK/ORIG

## CS8420
designator U?
Costo: 0; Aggiornato: NO
footprint SOJ.050/28/WB.300/L.700
pins: 1 CDOUT, 2 AD0/CS, 3 EMPH, 4 RXP, 5 RXN, 6 VA+, 7 AGND, 8 FILT, 9 RST, 10 RMCK, 11 RERR, 12 ILRCK, 13 ISCLK, 14 SDIN, 15 TCBL, 16 OSCLK, 17 OLRCK, 18 SDOUT, 19 INT, 20 U, 21 OMCK, 22 DGND, 23 VD+, 24 H/~{S}, 25 TXN, 26 TXP, 27 AD1/CDIN, 28 SCL/CCLK

## CS8421-CZZ
designator U?, comment CS8421-CZZ TSSOP20
Costo: 9,01; Aggiornato: SI; ContoLavoro: 0
footprint TSSOP20
pins: 1 XTO, 2 XTI, 3 VD, 4 GND, 5 RST, 6 BYPASS, 7 ILRCK, 8 ISCLK, 9 SDIN, 10 MCLK_OUT, 11 TDM_IN, 12 SDOUT, 13 OSCLK, 14 OLRCK, 15 MS_SEL, 16 GND, 17 VL, 18 SAOF, 19 SAIF, 20 SRC_UNLOCK

## CS8422
designator U3_?
24-bit, 192-kHz, Asynchronous Sample Rate Converter with  Integrated Digital Audio Interface Receiver; Aggiornato: NO; Costo: 0
footprint QFN32V4M (QFN, 32-Leads, Body 5x5mm, Pitch 0.5mm, IPC Low Density)
pins: 1 RX0/RXP0 (in), 2 RX1/RXN0 (in), 3 VA, 4 AGND, 5 RX2/RXP1 (in), 6 RX3/RXN1 (in), 7 AD0/~{CS} (in), 8 AD1/CDIN (in), 9 SCL/CCLK (in), 10 SDA/CDOUT (io), 11 XTI (in), 12 XTO (out), 13 ILRCK (io), 14 ISCLK (io), 15 SDIN (in), 16 GPO0 (out), 17 GPO1 (out), 18 GPO2 (out), 19 V_REG, 20 VD_FILT (out), 21 DGND, 22 VL, 23 SDOUT2 (out), 24 OSCLK2 (io), 25 OLRCK2 (io), 26 TDM_IN (in), 27 SDOUT1 (out), 28 OSCLK1 (io), 29 OLRCK1 (io), 30 GPO3 (out), 31 RMCK (out), 32 ~{RST} (in), 33 Thermal

## CSD17484F4
designator Q?
N-Channel FemtoFET 99-mΩ, 30-V Digi-Key Part Number (296-47319-2-ND - Tape & Reel) (296-47319-1-ND - Cut Tape) (296-47319-6-ND - Digi-Reel); Aggiornato: S; Costo: 0,124; ContoLavoro: 0
footprint 3-XFDFN-CSD17484F4
pins: 1 G, 2 S, 3 D

## CY7C68001-56LFC
designator U?
CY7C68001-56LFC, EZ-USB SX2 High-Speed USB Interface; Aggiornato: NO; Costo: 0
footprint QFN50P800X800_HS-57
pins: 1 SLRD (in), 2 SLWR (in), 3 AVCC (power), 4 XTALOUT (out), 5 XTALIN (in), 6 AGND (power), 7 VCC (power), 8 DPLUS (io), 9 DMINUS (io), 10 GND (power), 11 VCC (power), 12 GND (power), 13 IFCLK (io), 14 Reserved (in), 15 SCL (out), 16 SDA (out), 17 VCC (power), 18 FD[0] (io), 19 FD[1] (io), 20 FD[2] (io), 21 FD[3] (io), 22 FD[4] (io), 23 FD[5] (io), 24 FD[6] (io), 25 FD[7] (io), 26 GND (power), 27 VCC (power), 28 GND (power), 29 FLAGA (out), 30 FLAGB (out), 31 FLAGC (out), 32 VCC (power), 33 READY (out), 34 ~{INT} (out), 35 SLOE (in), 36 FIFOADR2 (in), 37 FIFOADR0 (in), 38 FIFOADR1 (in), 39 PKTEND (in), 40 FLAGD/~{CS} (io), 41 GND (power), 42 ~{RESET} (in), 43 VCC (power), 44 WAKEUP (in), 45 FD[8] (io), 46 FD[9] (io), 47 FD[10] (io), 48 FD[11] (io), 49 FD[12] (io), 50 FD[13] (io), 51 FD[14] (io), 52 FD[15] (io), 53 GND (power), 54 NC (out), 55 VCC (power), 56 GND (power)

## D_1N4002
designator D?, comment 1N4002
Hpcode: DID1N4002; Detail: ADIMPEX YBA10020; Costo: 0; Aggiornato: NO
footprint DIODO 1N4007
pins: 1, 2

## D_1N4007
designator D?, comment 1N4007
Costo: 0; Aggiornato: NO
footprint DIODO 1N4007
pins: 1, 2

## D_1N4148
designator D?, comment 1N4148
Detail: ADIMPEX YE200010; Hpcode: DID1N4148; Aggiornato: NO; Costo: 0
footprint DIODE 1N4148 (12)
simulation model 1n4148
pins: 1, 2

## D_1N5406
designator D?, comment 1N5406
1N5406 DIODE 3A 600V; Detail: ADIMPEX YE200010; Aggiornato: NO; Costo: 0
footprint DIODE 1N4148 (12)
pins: 1, 2

## D_1N5711
designator D?, comment 1N5711WS-7-F Diode Schottky 70V
Aggiornato: NO; Costo: 0,44; ContoLavoro: 0
footprint SOD_323
pins: 1 ANODE, 2 CATHODE

## D_1N5819
designator D?, comment 1N5819
Aggiornato: S; Costo: 0,05; ContoLavoro: 0
footprint DO41 (Footprint not found)
pins: 1, 2

## D_B260-13-F
designator D?, comment B260-13-F 2A 60V Diode
Aggiornato: SI; Costo: 0,085; ContoLavoro: 0
footprint DO214AA_21
pins: 1 ANODE, 2 CATHODE

## D_BAS40-04/SOT
designator D?, comment BAS40-04
Aggiornato: S; Costo: 0,037; ContoLavoro: 0
footprint SOT-23_UP
simulation model BAS40-04
footprint SOT-23_MINIMAL
pins: 1, 2, 3

## D_BAS40-05/SOT
designator D?, comment BAS40-05
Costo: 0,04; Aggiornato: S; ContoLavoro: 0
footprint SOT-23_UP
pins: 1, 2, 3

## D_BAS40-06/SOT
designator D?, comment BAS40-06
Costo: 0,033; Aggiornato: S; ContoLavoro: 0
footprint SOT-23_UP
pins: 1, 2, 3

## D_BAT54CW
designator D?, comment BAT54CW
BAT54CW, SOT-323 Plastic-Encapsulated Diode; Max Forward Current: 200mA; Rated Voltage: 30V; Aggiornato: s; Costo: 0,06; ContoLavoro: 0
footprint SOT-323
pins: 1, 2, 3

## D_BAV70W
designator D?
Silicon Switching Diode Array with Common Cathode for High-Speed Switching; Aggiornato: NO; Costo: 0
footprint SOT-323
pins: 1, 2, 3

## D_CMMR1U-02
designator D?, comment CMMR1U-02
ULTRA FAST RECTIFIER CMMR1U-02; Aggiornato: s; Costo: 0,33; ContoLavoro: 0
footprint SOD123
pins: 1 A, 2 k

## D_DO-214-AB
designator D?
Default Diode; Aggiornato: NO; Costo: 0
footprint SMC (DO-214-AB/SMC; 2 C-Bend Leads; Body 7.9 x 5.9 mm, inc. leads (LxW))
simulation model DIODE (Diode)
signal-integrity model Diode
pins: 1 A, 2 K

## D_DO-214AC
designator D?, comment US1G
Aggiornato: NO; Costo: 0
footprint DO214AC_21
pins: 1 A "1", 2 K "2"

## D_ES1B R2
designator D?, comment ES1B R2
Costo: 0,082; Aggiornato: S; ContoLavoro: 0
footprint SMA_D0214AC
footprint DO214AC_21
pins: 1, 2

## D_ESD24VS2U
designator D?, comment ESD24VS2U
ESD24VS2U CAN and LIN bus protection; Detail: 0,107€ RS>25pz; Costo: 0,107; Aggiornato: S; ContoLavoro: 0
footprint SOT-23_UP
pins: 1, 2, 3

## D_LL4148
designator D?, comment LL4148 SOD80
Costo: 0,00945; Aggiornato: SI; ContoLavoro: 0
footprint SOD80_UP
simulation model 1N4148
footprint SOD80_UP-MINIMAL
pins: 1, 2

## D_MBRS2040LT3G
designator D?, comment MBRS2040LT3G
Hpcode: DIDMBRS2040LT3G; Costo: 0,082; Aggiornato: S; ContoLavoro: 0
footprint DO214AA_21
pins: 1 ANODE, 2 CATHODE

## D_MURS160-E3/52T
designator D?, comment MURS160-E3/52T
Costo: 0; Aggiornato: NO
footprint DIODO_SMB
pins: 1 ANODE, 2 CATHODE

## D_RF101L2STE25
designator D?, comment RF101L2STE25 200V 1A
Aggiornato: NO; Costo: 0
footprint SOD106
pins: 1 ANODE, 2 CATHODE

## D_SBYV27-50
designator D?, comment SBYV27-50
Hpcode: DIDSBYV27-50; Costo: 0; Aggiornato: NO
footprint DIODO 1N4007
pins: 1 ANODE, 2 CATHODE

## D_SCHOTTKY_1A100V
designator D?, comment Schottky SMA 1A/100V
Costo: 0; Aggiornato: NO
footprint DIODE_SMA
footprint DIODE_SMB
footprint DIODE_SMC
footprint DO214AA
pins: 1, 2

## D_SCHOTTKY_1A100V_2
designator D?, comment B1100LB
Schottky Diode, 1A, 100V, SMB, B1100LB; Aggiornato: NO; Costo: 0
footprint DIOM8059
pins: 1, 2

## D_SCHOTTKY_3A40V
designator D?, comment 3A 40V
Schottky Diode, 3A 40V; Aggiornato: NO; Costo: 0
footprint DO214AA_21
pins: 1, 2

## D_SCHOTTKY_3A50V
designator D?, comment 3A 50V
Schottky Diode, 3A 50V / B350-13-F; Aggiornato: S; Costo: 0
footprint SM/DO214AB_21
pins: 1, 2

## D_SCHOTTKY_150mA100V
designator D?, comment 150mA 100V
Schottky Diode, BAT46W 100V 150mA; Aggiornato: s; Costo: 0,1; ContoLavoro: 0
footprint SOD123
pins: 1, 2

## D_SCHOTTKY_200mA30V
designator D?, comment 200mA 30V
Schottky Diode, BAT54 30V 200mA 30V SOT-23; Rated Voltage: 30 mV; Aggiornato: NO; Costo: 0
footprint SOT95P230-3C
pins: 1, 2 hidden, 2

## D_SCHOTTKY_200mA30V_2
designator D?, comment 200mA 30V
Schottky Diode, Dual-Serial, BAT54S 30V 200mA; Aggiornato: NO; Costo: 0
footprint SOT95P230-3C
pins: 1 A, 2 K, 3 C

## D_SCHOTTKY_400mA_mV
designator D?, comment ZHCS400
Schottky Diode, 400mA; Rated Voltage: mV; Aggiornato: NO; Costo: 0
footprint SOD323
pins: 1, 2

## D_SCHOTTKY_SS10PH45HM3
designator D?, comment SS10PH45HM3
Diode Schottky 45 V 10A Surface Mount TO-277A (SMPC); Aggiornato: S; Costo: 0,41610; ContoLavoro: 0
footprint TO-277A / SS10
pins: 1, 2, 3

## D_SCHOTTKY_SS14
designator D?, comment SS14-E3
Aggiornato: S; Costo: 0,05; ContoLavoro: 0
footprint DO214AC_21
footprint SMA_D0214AC
pins: 1, 2

## D_SCHOTTKY_SS16R2
designator D?, comment SS16 R2
Costo: 0,029; Detail: € RS>100; Aggiornato: S; ContoLavoro: 0
footprint DO214AC_21
footprint SMA_D0214AC
pins: 1, 2


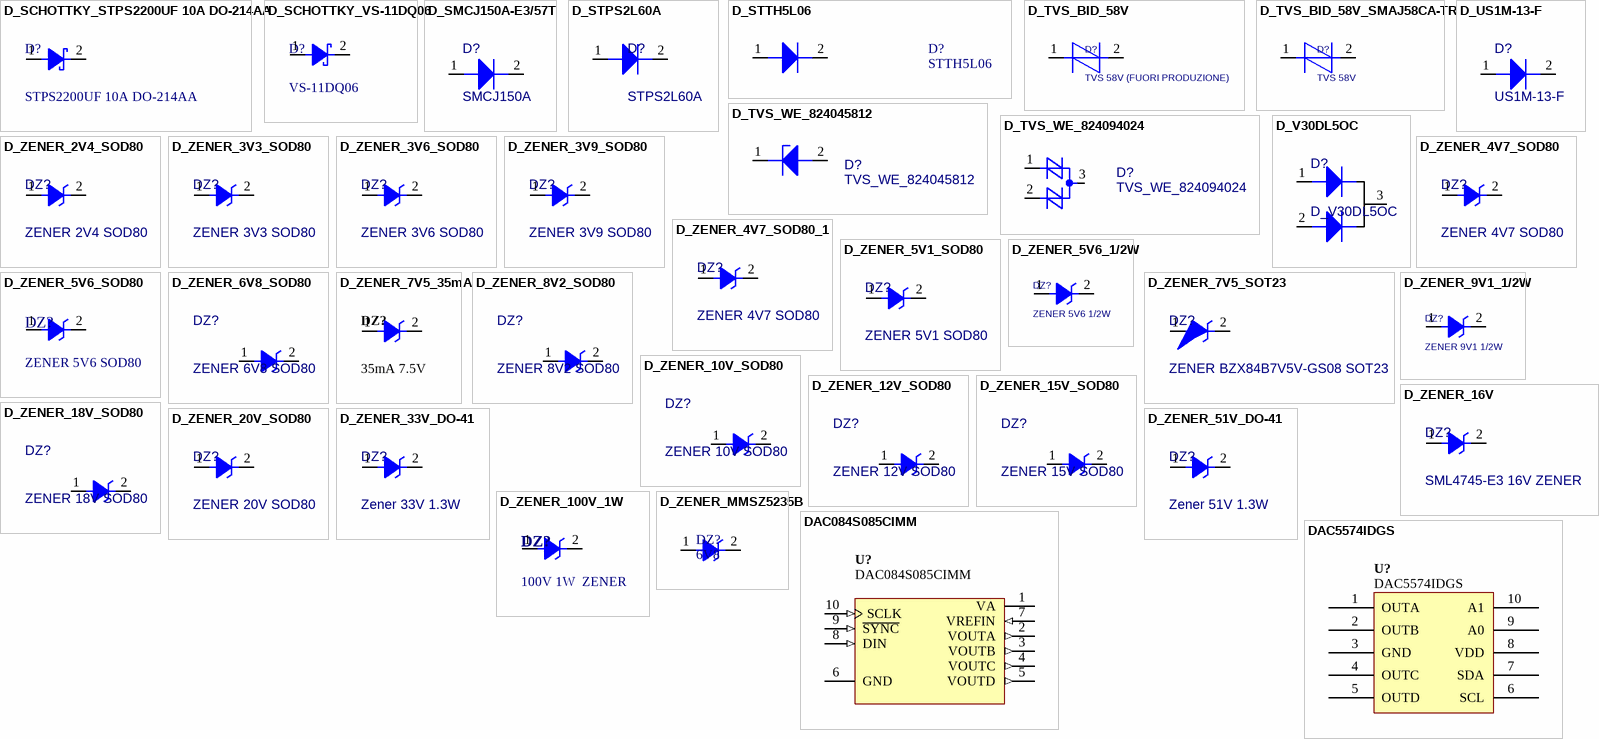
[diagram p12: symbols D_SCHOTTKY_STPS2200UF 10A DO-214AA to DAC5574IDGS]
## D_SCHOTTKY_STPS2200UF 10A DO-214AA
designator D?, comment STPS2200UF 10A DO-214AA
Detail: RS per >250pz; Aggiornato: SI; Costo: 0,51; ContoLavoro: 0
footprint DO214AA_21
footprint SMA_D0214AC
pins: 1, 2

## D_SCHOTTKY_VS-11DQ06
designator D?, comment VS-11DQ06
Costo: 0,222; Aggiornato: NO; ContoLavoro: 0
footprint DO15
pins: 1, 2

## D_SMCJ150A-E3/57T
designator D?, comment SMCJ150A
Aggiornato: NO; Costo: 0
footprint SM/DO214AB_21
pins: 1 ANODE, 2 CATHODE

## D_STPS2L60A
designator D?, comment STPS2L60A
Hpcode: DIDSTPS2L60A; Costo: 0,295; Aggiornato: NO; ContoLavoro: 0
footprint DO214AA_21
pins: 1 ANODE, 2 CATHODE

## D_STTH5L06
designator D?, comment STTH5L06
STTH5L06 5A 600V High voltage ultrafast rectifier; Costo: 0; Aggiornato: NO
pins: 1 ANODE, 2 CATHODE

## D_TVS_BID_58V
designator D?, comment TVS 58V (FUORI PRODUZIONE)
BIDIRECTIONAL THYRISTOR OVERVOLTAGE PROTECTOR 58V; Detail: (FUORI PRODUZIONE) nuovo codice SMAJ58CA-TR codice RS: 714-7121.; Costo: 0,25; Aggiornato: s; ContoLavoro: 0
footprint DO214AA_21
pins: 1 ANODE, 2 CATHODE

## D_TVS_BID_58V_SMAJ58CA-TR
designator D?, comment TVS 58V
BIDIRECTIONAL THYRISTOR OVERVOLTAGE PROTECTOR 58V; Detail: € RS<25; Costo: 0,10; Aggiornato: s; ContoLavoro: 0
footprint DO214AA_21
pins: 1 ANODE, 2 CATHODE

## D_TVS_WE_824045812
designator D?, comment TVS_WE_824045812
Detail: da quotare WE; Aggiornato: S; Costo: da quotare; ContoLavoro: 0
footprint WE-TVS_DFN1610-2L (TVS Diode, package DFN1610-2L)
pins: 1 VCC, 2 GND

## D_TVS_WE_824094024
designator D?, comment TVS_WE_824094024
Detail: da quotare WE; Aggiornato: S; Costo: da quotare; ContoLavoro: 0
footprint SOT-23_UP
footprint SOT-23_MINIMAL
pins: 1, 2, 3

## D_US1M-13-F
designator D?, comment US1M-13-F
Costo: 0,081; Aggiornato: NO; ContoLavoro: 0
footprint DO214AC_21
pins: 1 ANODE, 2 CATHODE

## D_V30DL5OC
designator D?
V30DL5OC; Detail: Costo RS <100; Costo: 0,596; Aggiornato: s; ContoLavoro: 0
footprint TO263AC
pins: 1 ANODE1, 2 ANODE2, 3 KATODE

## D_ZENER_2V4_SOD80
designator DZ?, comment ZENER 2V4 SOD80
ZENER 2V4 SOD80 BZT55C2V4; Costo: 0,024; Aggiornato: si; ContoLavoro: 0
footprint SOD80_UP
simulation model DI_BZT52C2V4
footprint SOD80_UP-MINIMAL
pins: 1, 2

## D_ZENER_3V3_SOD80
designator DZ?, comment ZENER 3V3 SOD80
Costo: 0,0154; Aggiornato: NO; ContoLavoro: 0
footprint SOD80_UP
pins: 1, 2

## D_ZENER_3V6_SOD80
designator DZ?, comment ZENER 3V6 SOD80
Costo: 0,024; Aggiornato: no; ContoLavoro: 0
footprint SOD80_UP
pins: 1, 2

## D_ZENER_3V9_SOD80
designator DZ?, comment ZENER 3V9 SOD80
Costo: 0; Aggiornato: no
footprint SOD80_UP
pins: 1, 2

## D_ZENER_4V7_SOD80
designator DZ?, comment ZENER 4V7 SOD80
Costo: 0,143; Aggiornato: si; ContoLavoro: 0
footprint SOD80_UP
footprint SOD80_UP-MINIMAL
pins: 1, 2

## D_ZENER_4V7_SOD80_1
designator DZ?, comment ZENER 4V7 SOD80
Costo: 0,143; Aggiornato: si; ContoLavoro: 0
footprint SOD80_UP
footprint SOD80_UP-MINIMAL
pins: 1, 2

## D_ZENER_5V1_SOD80
designator DZ?, comment ZENER 5V1 SOD80
Costo: 0,0154; Aggiornato: si; ContoLavoro: 0
footprint SOD80_UP
footprint SOD80_UP-MINIMAL
pins: 1, 2

## D_ZENER_5V6_1/2W
designator DZ?, comment ZENER 5V6 1/2W
Detail: ADIMPEX YE040056; Hpcode: DIZ5V61/2; Costo: 0; Aggiornato: NO
footprint DIODE 1N4148 (12)
pins: 1, 2

## D_ZENER_5V6_SOD80
designator DZ?, comment ZENER 5V6 SOD80
Detail: (RS per >200pz); Aggiornato: NO; Costo: 0,023; ContoLavoro: 0
footprint SOD80_UP
footprint SOD80_UP-MINIMAL
pins: 1, 2

## D_ZENER_6V8_SOD80
designator DZ?, comment ZENER 6V8 SOD80
Costo: 0,024; Aggiornato: NO; ContoLavoro: 0
footprint SOD80_UP
pins: 1, 2

## D_ZENER_7V5_35mA
designator DZ?, comment 35mA 7.5V
Zener Diode, 7.5V 35mA; Aggiornato: NO; Costo: 0
footprint SOT95P230-3D
pins: 1, 2

## D_ZENER_7V5_SOT23
designator DZ?, comment ZENER BZX84B7V5V-GS08 SOT23
Aggiornato: NO; Costo: 0
footprint SOT-23_UP
pins: 1, 2

## D_ZENER_8V2_SOD80
designator DZ?, comment ZENER 8V2 SOD80
Costo: 0,024; Aggiornato: NO; ContoLavoro: 0
footprint SOD80_UP
simulation model DI_BZT52C8V2
pins: 1, 2

## D_ZENER_9V1_1/2W
designator DZ?, comment ZENER 9V1 1/2W
Hpcode: DIZ9V11/2; Costo: 0; Aggiornato: NO
footprint DIODE 1N4148 (12)
pins: 1, 2

## D_ZENER_10V_SOD80
designator DZ?, comment ZENER 10V SOD80
Costo: 0,024; Aggiornato: NO; ContoLavoro: 0
footprint SOD80_UP
pins: 1, 2

## D_ZENER_12V_SOD80
designator DZ?, comment ZENER 12V SOD80
Hpcode: DIZ12SOD80; Detail: ADIMPEX; Aggiornato: SI; Costo: 0,053; ContoLavoro: 0
footprint SOD80_UP
pins: 1, 2

## D_ZENER_15V_SOD80
designator DZ?, comment ZENER 15V SOD80
Aggiornato: SI; Costo: 0,115; ContoLavoro: 0
footprint SOD80_UP
pins: 1, 2

## D_ZENER_16V
designator DZ?, comment SML4745-E3 16V ZENER
Aggiornato: si; Costo: 0,2; ContoLavoro: 0
footprint DO214AC_21
pins: 1, 2

## D_ZENER_18V_SOD80
designator DZ?, comment ZENER 18V SOD80
Detail: 62,10€ per 2500pz; Aggiornato: SI; Costo: 0,053; ContoLavoro: 0
footprint SOD80_UP
pins: 1, 2

## D_ZENER_20V_SOD80
designator DZ?, comment ZENER 20V SOD80
DIO_ZENER_20V_SOD80; Detail: RS>500pz; Aggiornato: SI; Costo: 0,053; ContoLavoro: 0
footprint SOD80_UP
pins: 1, 2

## D_ZENER_33V_DO-41
designator DZ?, comment Zener 33V 1.3W
Zener Diode 33V 1.3W; Aggiornato: s; Costo: 0,04; ContoLavoro: 0
footprint DO41
pins: 1, 2

## D_ZENER_51V_DO-41
designator DZ?, comment Zener 51V 1.3W
Zener Diode 51V 1.3W; Aggiornato: s; Costo: 0,04; ContoLavoro: 0
footprint DO41
pins: 1, 2

## D_ZENER_100V_1W
designator DZ?, comment 100V 1W  ZENER
Aggiornato: NO; Costo: 0
footprint ZENER_1W
pins: 1, 2

## D_ZENER_MMSZ5235B
designator DZ?, comment 6V8
6.8 VZ MMSZ5235B SOD123; Pd: 0W5; Aggiornato: NO; Costo: 0
footprint SOD-123_diodes (SOD-123 Body (Bx H max) 1.7 x 2.85mm  Height=1.35 max)
pins: 1, 2
1 alternate drawing of the same symbol

## DAC084S085CIMM
designator U?
DAC084S085CIMM, Quad 8-bit, Single 2.7V to 5.5V rail-to-rail output; Bit Width: 8 Bits; Digital Interface: SPI; Max Sample Frequency: 3 us Settling Time Hz; Supply Voltage: 2.7V to 5.5V mV; Aggiornato: NO; Costo: 0
footprint TSSOP50P490-10AN
pins: 1 VA (power), 2 VOUTA (out), 3 VOUTB (out), 4 VOUTC (out), 5 VOUTD (out), 6 GND (power), 7 VREFIN (in), 8 DIN (in), 9 ~{SYNC} (in), 10 SCLK (in)

## DAC5574IDGS
designator U?
DAC5574, 8-Bit, Quad Digital-to-Analog Converter, I2C interface; Supply Voltage: 2.7 - 5.5; Aggiornato: SI; Costo: 0
footprint VSSOP10
pins: 1 OUTA "DAC Output", 2 OUTB "DAC Output", 3 GND, 4 OUTC "DAC Output", 5 OUTD "DAC Output", 6 SCL "I2C Clock", 7 SDA "I2C Data", 8 VDD "Positive Supply 2.7V to 5.5V", 9 A0 "Address", 10 A1 "Address"


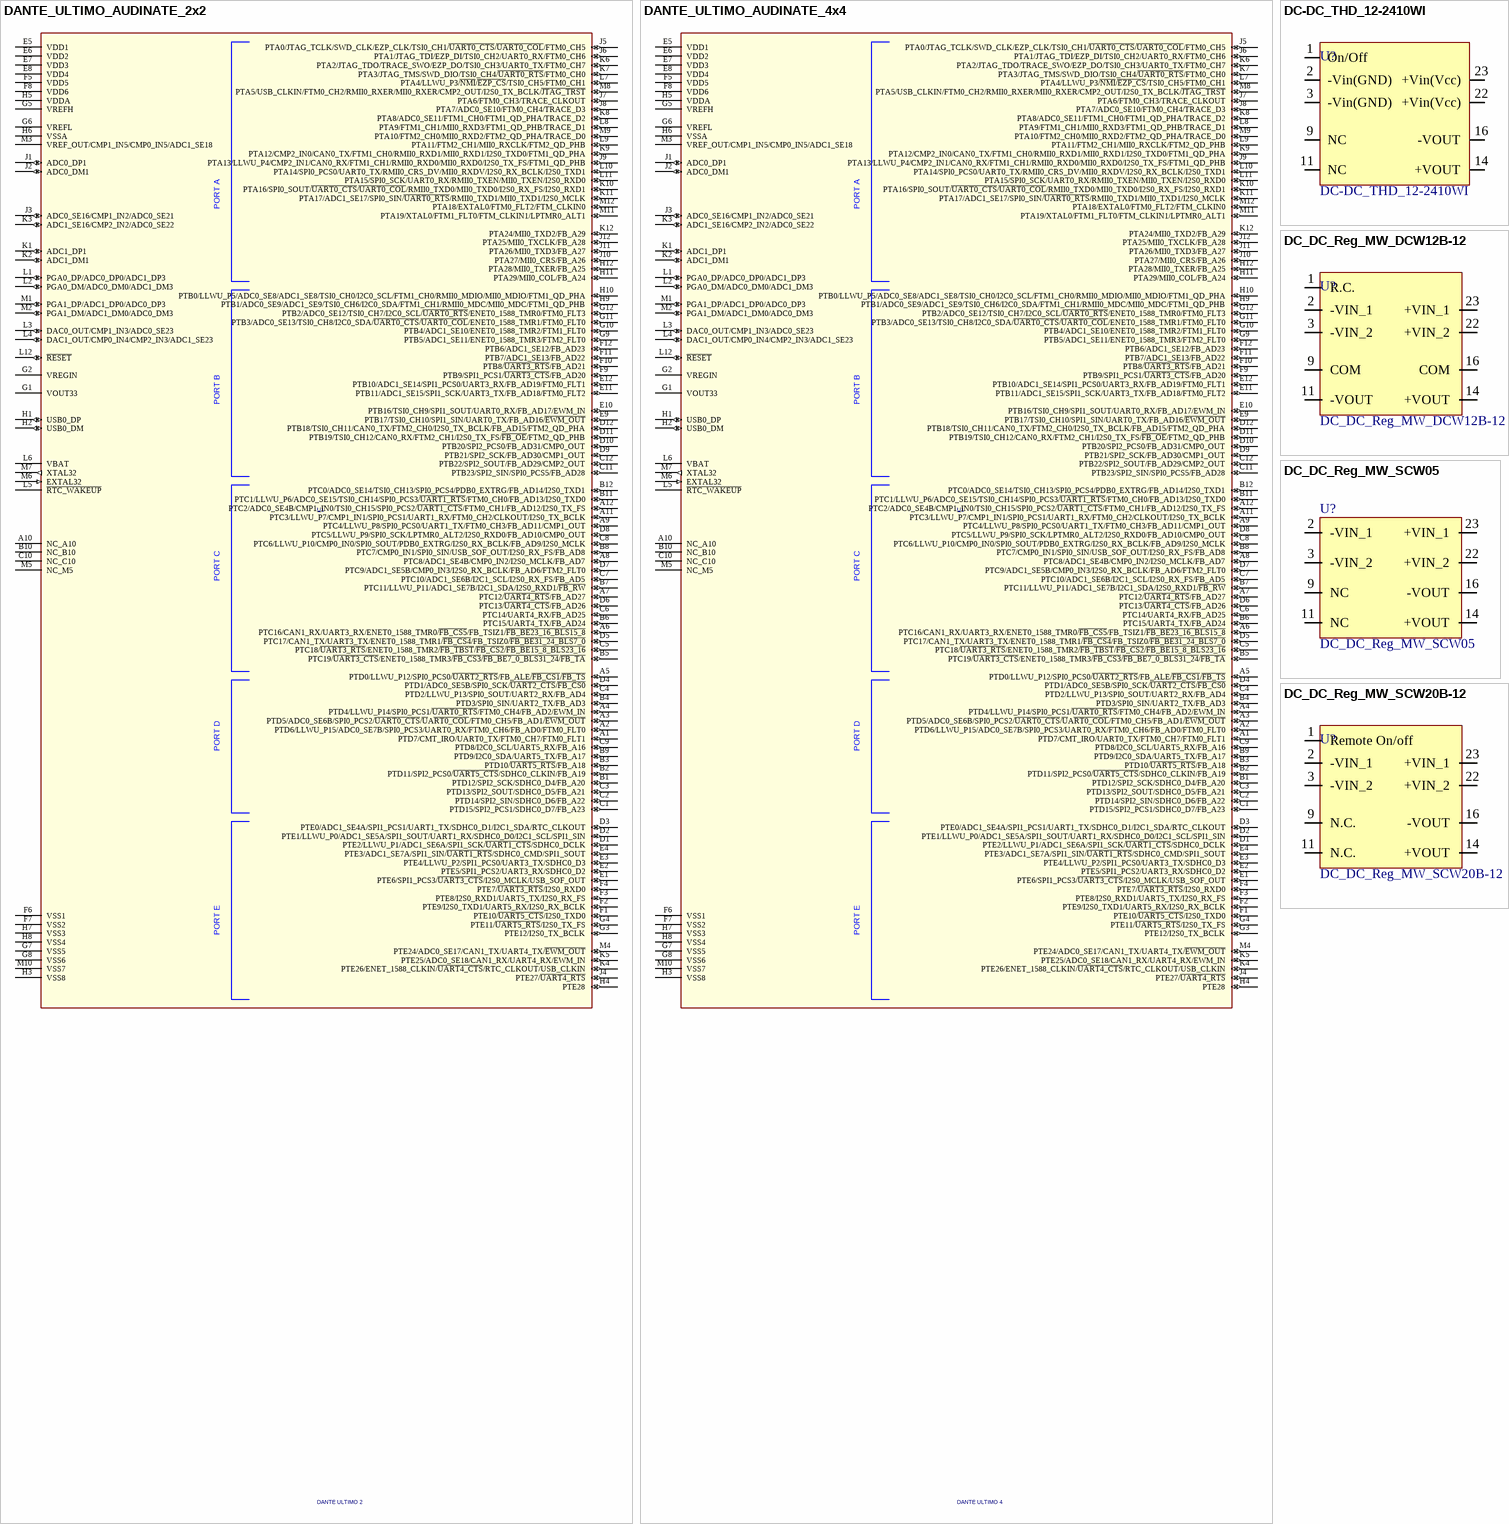
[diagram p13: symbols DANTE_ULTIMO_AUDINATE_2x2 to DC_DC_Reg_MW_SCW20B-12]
## DANTE_ULTIMO_AUDINATE_2x2
designator U1, comment DANTE ULTIMO 2
AUDINATE DANTE ULTIMO 2; Costo: 16; HPcode: 'ICULTIMO2x2; Aggiornato: S; ContoLavoro: 1
footprint FBGA144_mod (144-Ball FineLine Ball Grid Array (FBGA144))
pins: A1 PTD7/CMT_IRO/UART0_TX/FTM0_CH7/FTM0_FLT1 (io), A2 PTD6/LLWU_P15/ADC0_SE7B/SPI0_PCS3/UART0_RX/FTM0_CH6/FB_AD0/FTM0_FLT0 (io), A3 PTD5/ADC0_SE6B/SPI0_PCS2/~{UART0_CTS}/~{U}A~{RT0_COL}/FTM0_CH5/FB_AD1/~{EWM_OUT} (io), A4 PTD4/LLWU_P14/SPI0_PCS1/~{UART0_RTS}/FTM0_CH4/FB_AD2/EWM_IN (io), A5 PTD0/LLWU_P12/SPI0_PCS0/~{UART2_RTS}/FB_ALE/~{FB_CS1}/~{FB_TS} (io), A6 PTC16/CAN1_RX/UART3_RX/ENET0_1588_TMR0/~{FB_CS5}/FB_TSIZ1/~{FB_BE23_16_BLS15_8} (io), A7 PTC12/~{UART4_RTS}/FB_AD27 (io), A8 PTC8/ADC1_SE4B/CMP0_IN2/I2S0_MCLK/FB_AD7 (io), A9 PTC4/LLWU_P8/SPI0_PCS0/UART1_TX/FTM0_CH3/FB_AD11/CMP1_OUT (io), A10 NC_A10, A11 PTC3/LLWU_P7/CMP1_IN1/SPI0_PCS1/UART1_RX/FTM0_CH2/CLKOUT/I2S0_TX_BCLK (io), A12 PTC2/ADC0_SE4B/CMP1_IN0/TSI0_CH15/SPI0_PCS2/~{UART1_CTS}/FTM0_CH1/FB_AD12/I2S0_TX_FS (io), B1 PTD12/SPI2_SCK/SDHC0_D4/FB_A20 (io), B2 PTD11/SPI2_PCS0/~{UART5_CTS}/SDHC0_CLKIN/FB_A19 (io), B3 PTD10/~{UART5_RTS}/FB_A18 (io), B4 PTD3/SPI0_SIN/UART2_TX/FB_AD3 (io), B5 PTC19/~{UART3_CTS}/ENET0_1588_TMR3/~{FB_CS3}/~{FB_BE7_0_BLS31_24}/~{FB_TA} (io), B6 PTC15/UART4_TX/FB_AD24 (io), B7 PTC11/LLWU_P11/ADC1_SE7B/I2C1_SDA/I2S0_RXD1/~{FB_RW} (io), B8 PTC7/CMP0_IN1/SPI0_SIN/USB_SOF_OUT/I2S0_RX_FS/FB_AD8 (io), B9 PTD9/I2C0_SDA/UART5_TX/FB_A17 (io), B10 NC_B10, B11 PTC1/LLWU_P6/ADC0_SE15/TSI0_CH14/SPI0_PCS3/~{UART1_RTS}/FTM0_CH0/FB_AD13/I2S0_TXD0 (io), B12 PTC0/ADC0_SE14/TSI0_CH13/SPI0_PCS4/PDB0_EXTRG/FB_AD14/I2S0_TXD1 (io), C1 PTD15/SPI2_PCS1/SDHC0_D7/FB_A23 (io), C2 PTD14/SPI2_SIN/SDHC0_D6/FB_A22 (io), C3 PTD13/SPI2_SOUT/SDHC0_D5/FB_A21 (io), C4 PTD2/LLWU_P13/SPI0_SOUT/UART2_RX/FB_AD4 (io), C5 PTC18/~{UART3_RTS}/ENET0_1588_TMR2/~{FB_TBST}/~{FB_CS2}/~{FB_BE15_8_BLS23_16} (io), C6 PTC14/UART4_RX/FB_AD25 (io), C7 PTC10/ADC1_SE6B/I2C1_SCL/I2S0_RX_FS/FB_AD5 (io), C8 PTC6/LLWU_P10/CMP0_IN0/SPI0_SOUT/PDB0_EXTRG/I2S0_RX_BCLK/FB_AD9/I2S0_MCLK (io), C9 PTD8/I2C0_SCL/UART5_RX/FB_A16 (io), C10 NC_C10, C11 PTB23/SPI2_SIN/SPI0_PCS5/FB_AD28 (io), C12 PTB22/SPI2_SOUT/FB_AD29/CMP2_OUT (io), D1 PTE2/LLWU_P1/ADC1_SE6A/SPI1_SCK/~{UART1_CTS}/SDHC0_DCLK (io), D2 PTE1/LLWU_P0/ADC1_SE5A/SPI1_SOUT/UART1_RX/SDHC0_D0/I2C1_SCL/SPI1_SIN (io), D3 PTE0/ADC1_SE4A/SPI1_PCS1/UART1_TX/SDHC0_D1/I2C1_SDA/RTC_CLKOUT (io), D4 PTD1/ADC0_SE5B/SPI0_SCK/~{UART2_CTS}/~{FB_CS0} (io), D5 PTC17/CAN1_TX/UART3_TX/ENET0_1588_TMR1/~{FB_CS4}/FB_TSIZ0/~{FB_BE31_24_BLS7_0} (io), D6 PTC13/~{UART4_CTS}/FB_AD26 (io), D7 PTC9/ADC1_SE5B/CMP0_IN3/I2S0_RX_BCLK/FB_AD6/FTM2_FLT0 (io), D8 PTC5/LLWU_P9/SPI0_SCK/LPTMR0_ALT2/I2S0_RXD0/FB_AD10/CMP0_OUT (io), D9 PTB21/SPI2_SCK/FB_AD30/CMP1_OUT (io), D10 PTB20/SPI2_PCS0/FB_AD31/CMP0_OUT (io), D11 PTB19/TSI0_CH12/CAN0_RX/FTM2_CH1/I2S0_TX_FS/~{FB_OE}/FTM2_QD_PHB (io), D12 PTB18/TSI0_CH11/CAN0_TX/FTM2_CH0/I2S0_TX_BCLK/FB_AD15/FTM2_QD_PHA (io), E1 PTE6/SPI1_PCS3/~{UART3_CTS}/I2S0_MCLK/USB_SOF_OUT (io), E2 PTE5/SPI1_PCS2/UART3_RX/SDHC0_D2 (io), E3 PTE4/LLWU_P2/SPI1_PCS0/UART3_TX/SDHC0_D3 (io), E4 PTE3/ADC1_SE7A/SPI1_SIN/~{UART1_RTS}/SDHC0_CMD/SPI1_SOUT (io), E5 VDD1 (power), E6 VDD2 (power), E7 VDD3 (power), E8 VDD4 (power), E9 PTB17/TSI0_CH10/SPI1_SIN/UART0_TX/FB_AD16/~{EWM_OUT} (io), E10 PTB16/TSI0_CH9/SPI1_SOUT/UART0_RX/FB_AD17/EWM_IN (io), E11 PTB11/ADC1_SE15/SPI1_SCK/UART3_TX/FB_AD18/FTM0_FLT2 (io), E12 PTB10/ADC1_SE14/SPI1_PCS0/UART3_RX/FB_AD19/FTM0_FLT1 (io), F1 PTE10/~{UART5_CTS}/I2S0_TXD0 (io), F2 PTE9/I2S0_TXD1/UART5_RX/I2S0_RX_BCLK (io), F3 PTE8/I2S0_RXD1/UART5_TX/I2S0_RX_FS (io), F4 PTE7/~{UART3_RTS}/I2S0_RXD0 (io), F5 VDD5 (power), F6 VSS1 (power), F7 VSS2 (power), F8 VDD6 (power), F9 PTB9/SPI1_PCS1/~{UART3_CTS}/FB_AD20 (io), F10 PTB8/~{UART3_RTS}/FB_AD21 (io), F11 PTB7/ADC1_SE13/FB_AD22 (io), F12 PTB6/ADC1_SE12/FB_AD23 (io), G1 VOUT33 (power), G2 VREGIN (power), G3 PTE12/I2S0_TX_BCLK (io), G4 PTE11/~{UART5_RTS}/I2S0_TX_FS (io), G5 VREFH (power), G6 VREFL (power), G7 VSS5 (power), G8 VSS6 (power), G9 PTB5/ADC1_SE11/ENET0_1588_TMR3/FTM2_FLT0 (io), G10 PTB4/ADC1_SE10/ENET0_1588_TMR2/FTM1_FLT0 (io), G11 PTB3/ADC0_SE13/TSI0_CH8/I2C0_SDA/~{UART0_CTS}/~{UART0_COL}/ENET0_1588_TMR1/FTM0_FLT0 (io), G12 PTB2/ADC0_SE12/TSI0_CH7/I2C0_SCL/~{UART0_RTS}/ENET0_1588_TMR0/FTM0_FLT3 (io), H1 USB0_DP (io), H2 USB0_DM (io), H3 VSS8 (power), H4 PTE28 (io), H5 VDDA (power), H6 VSSA (power), H7 VSS3 (power), H8 VSS4 (power), H9 PTB1/ADC0_SE9/ADC1_SE9/TSI0_CH6/I2C0_SDA/FTM1_CH1/RMII0_MDC/MII0_MDC/FTM1_QD_PHB (io), H10 PTB0/LLWU_P5/ADC0_SE8/ADC1_SE8/TSI0_CH0/I2C0_SCL/FTM1_CH0/RMII0_MDIO/MII0_MDIO/FTM1_QD_PHA (io), H11 PTA29/MII0_COL/FB_A24 (io), H12 PTA28/MII0_TXER/FB_A25 (io), J1 ADC0_DP1 (io), J2 ADC0_DM1 (io), J3 ADC0_SE16/CMP1_IN2/ADC0_SE21 (io), J4 PTE27/~{UART4_RTS} (io), J5 PTA0/JTAG_TCLK/SWD_CLK/EZP_CLK/TSI0_CH1/~{UART0_CTS}/~{UART0_COL}/FTM0_CH5 (io), J6 PTA1/JTAG_TDI/EZP_DI/TSI0_CH2/UART0_RX/FTM0_CH6 (io), J7 PTA6/FTM0_CH3/TRACE_CLKOUT (io), J8 PTA7/ADC0_SE10/FTM0_CH4/TRACE_D3 (io), J9 PTA13/LLWU_P4/CMP2_IN1/CAN0_RX/FTM1_CH1/RMII0_RXD0/MII0_RXD0/I2S0_TX_FS/FTM1_QD_PHB (io), J10 PTA27/MII0_CRS/FB_A26 (io), J11 PTA26/MII0_TXD3/FB_A27 (io), J12 PTA25/MII0_TXCLK/FB_A28 (io), K1 ADC1_DP1 (io), K2 ADC1_DM1 (io), K3 ADC1_SE16/CMP2_IN2/ADC0_SE22 (io), K4 PTE26/ENET_1588_CLKIN/~{UART4_CTS}/RTC_CLKOUT/USB_CLKIN (io), K5 PTE25/ADC0_SE18/CAN1_RX/UART4_RX/EWM_IN (io), K6 PTA2/JTAG_TDO/TRACE_SWO/EZP_DO/TSI0_CH3/UART0_TX/FTM0_CH7 (io), K7 PTA3/JTAG_TMS/SWD_DIO/TSI0_CH4/~{UART0_RTS}/FTM0_CH0 (io), K8 PTA8/ADC0_SE11/FTM1_CH0/FTM1_QD_PHA/TRACE_D2 (io), K9 PTA12/CMP2_IN0/CAN0_TX/FTM1_CH0/RMII0_RXD1/MII0_RXD1/I2S0_TXD0/FTM1_QD_PHA (io), K10 PTA16/SPI0_SOUT/~{UART0_CTS}/~{UART0_COL}/RMII0_TXD0/MII0_TXD0/I2S0_RX_FS/I2S0_RXD1 (io), K11 PTA17/ADC1_SE17/SPI0_SIN/~{UART0_RTS}/RMII0_TXD1/MII0_TXD1/I2S0_MCLK (io), K12 PTA24/MII0_TXD2/FB_A29 (io), L1 PGA0_DP/ADC0_DP0/ADC1_DP3 (io), L2 PGA0_DM/ADC0_DM0/ADC1_DM3 (io), L3 DAC0_OUT/CMP1_IN3/ADC0_SE23 (io), L4 DAC1_OUT/CMP0_IN4/CMP2_IN3/ADC1_SE23 (io), L5 ~{RTC_WAKEUP}, L6 VBAT (power), L7 PTA4/LLWU_P3/~{NMI}/~{EZP_CS}/TSI0_CH5/FTM0_CH1 (io), L8 PTA9/FTM1_CH1/MII0_RXD3/FTM1_QD_PHB/TRACE_D1 (io), L9 PTA11/FTM2_CH1/MII0_RXCLK/FTM2_QD_PHB (io), L10 PTA14/SPI0_PCS0/UART0_TX/RMII0_CRS_DV/MII0_RXDV/I2S0_RX_BCLK/I2S0_TXD1 (io), L11 PTA15/SPI0_SCK/UART0_RX/RMII0_TXEN/MII0_TXEN/I2S0_RXD0 (io), L12 ~{RESET} (io), M1 PGA1_DP/ADC1_DP0/ADC0_DP3 (io), M2 PGA1_DM/ADC1_DM0/ADC0_DM3 (io), M3 VREF_OUT/CMP1_IN5/CMP0_IN5/ADC1_SE18 (power), M4 PTE24/ADC0_SE17/CAN1_TX/UART4_TX/~{EWM_OUT} (io), M5 NC_M5, M6 EXTAL32 (in), M7 XTAL32 (out), M8 PTA5/USB_CLKIN/FTM0_CH2/RMII0_RXER/MII0_RXER/CMP2_OUT/I2S0_TX_BCLK/~{JTAG_TRST} (io), M9 PTA10/FTM2_CH0/MII0_RXD2/FTM2_QD_PHA/TRACE_D0 (io), M10 VSS7 (power), M11 PTA19/XTAL0/FTM1_FLT0/FTM_CLKIN1/LPTMR0_ALT1 (io), M12 PTA18/EXTAL0/FTM0_FLT2/FTM_CLKIN0 (io)

## DANTE_ULTIMO_AUDINATE_4x4
designator U1, comment DANTE ULTIMO 4
AUDINATE DANTE ULTIMO 4; Costo: 17; HPcode: 'ICULTIMO4x4 da codificare!; Aggiornato: S; ContoLavoro: 1
footprint FBGA144_mod (144-Ball FineLine Ball Grid Array (FBGA144))
pins: A1 PTD7/CMT_IRO/UART0_TX/FTM0_CH7/FTM0_FLT1 (io), A2 PTD6/LLWU_P15/ADC0_SE7B/SPI0_PCS3/UART0_RX/FTM0_CH6/FB_AD0/FTM0_FLT0 (io), A3 PTD5/ADC0_SE6B/SPI0_PCS2/~{UART0_CTS}/~{U}A~{RT0_COL}/FTM0_CH5/FB_AD1/~{EWM_OUT} (io), A4 PTD4/LLWU_P14/SPI0_PCS1/~{UART0_RTS}/FTM0_CH4/FB_AD2/EWM_IN (io), A5 PTD0/LLWU_P12/SPI0_PCS0/~{UART2_RTS}/FB_ALE/~{FB_CS1}/~{FB_TS} (io), A6 PTC16/CAN1_RX/UART3_RX/ENET0_1588_TMR0/~{FB_CS5}/FB_TSIZ1/~{FB_BE23_16_BLS15_8} (io), A7 PTC12/~{UART4_RTS}/FB_AD27 (io), A8 PTC8/ADC1_SE4B/CMP0_IN2/I2S0_MCLK/FB_AD7 (io), A9 PTC4/LLWU_P8/SPI0_PCS0/UART1_TX/FTM0_CH3/FB_AD11/CMP1_OUT (io), A10 NC_A10, A11 PTC3/LLWU_P7/CMP1_IN1/SPI0_PCS1/UART1_RX/FTM0_CH2/CLKOUT/I2S0_TX_BCLK (io), A12 PTC2/ADC0_SE4B/CMP1_IN0/TSI0_CH15/SPI0_PCS2/~{UART1_CTS}/FTM0_CH1/FB_AD12/I2S0_TX_FS (io), B1 PTD12/SPI2_SCK/SDHC0_D4/FB_A20 (io), B2 PTD11/SPI2_PCS0/~{UART5_CTS}/SDHC0_CLKIN/FB_A19 (io), B3 PTD10/~{UART5_RTS}/FB_A18 (io), B4 PTD3/SPI0_SIN/UART2_TX/FB_AD3 (io), B5 PTC19/~{UART3_CTS}/ENET0_1588_TMR3/~{FB_CS3}/~{FB_BE7_0_BLS31_24}/~{FB_TA} (io), B6 PTC15/UART4_TX/FB_AD24 (io), B7 PTC11/LLWU_P11/ADC1_SE7B/I2C1_SDA/I2S0_RXD1/~{FB_RW} (io), B8 PTC7/CMP0_IN1/SPI0_SIN/USB_SOF_OUT/I2S0_RX_FS/FB_AD8 (io), B9 PTD9/I2C0_SDA/UART5_TX/FB_A17 (io), B10 NC_B10, B11 PTC1/LLWU_P6/ADC0_SE15/TSI0_CH14/SPI0_PCS3/~{UART1_RTS}/FTM0_CH0/FB_AD13/I2S0_TXD0 (io), B12 PTC0/ADC0_SE14/TSI0_CH13/SPI0_PCS4/PDB0_EXTRG/FB_AD14/I2S0_TXD1 (io), C1 PTD15/SPI2_PCS1/SDHC0_D7/FB_A23 (io), C2 PTD14/SPI2_SIN/SDHC0_D6/FB_A22 (io), C3 PTD13/SPI2_SOUT/SDHC0_D5/FB_A21 (io), C4 PTD2/LLWU_P13/SPI0_SOUT/UART2_RX/FB_AD4 (io), C5 PTC18/~{UART3_RTS}/ENET0_1588_TMR2/~{FB_TBST}/~{FB_CS2}/~{FB_BE15_8_BLS23_16} (io), C6 PTC14/UART4_RX/FB_AD25 (io), C7 PTC10/ADC1_SE6B/I2C1_SCL/I2S0_RX_FS/FB_AD5 (io), C8 PTC6/LLWU_P10/CMP0_IN0/SPI0_SOUT/PDB0_EXTRG/I2S0_RX_BCLK/FB_AD9/I2S0_MCLK (io), C9 PTD8/I2C0_SCL/UART5_RX/FB_A16 (io), C10 NC_C10, C11 PTB23/SPI2_SIN/SPI0_PCS5/FB_AD28 (io), C12 PTB22/SPI2_SOUT/FB_AD29/CMP2_OUT (io), D1 PTE2/LLWU_P1/ADC1_SE6A/SPI1_SCK/~{UART1_CTS}/SDHC0_DCLK (io), D2 PTE1/LLWU_P0/ADC1_SE5A/SPI1_SOUT/UART1_RX/SDHC0_D0/I2C1_SCL/SPI1_SIN (io), D3 PTE0/ADC1_SE4A/SPI1_PCS1/UART1_TX/SDHC0_D1/I2C1_SDA/RTC_CLKOUT (io), D4 PTD1/ADC0_SE5B/SPI0_SCK/~{UART2_CTS}/~{FB_CS0} (io), D5 PTC17/CAN1_TX/UART3_TX/ENET0_1588_TMR1/~{FB_CS4}/FB_TSIZ0/~{FB_BE31_24_BLS7_0} (io), D6 PTC13/~{UART4_CTS}/FB_AD26 (io), D7 PTC9/ADC1_SE5B/CMP0_IN3/I2S0_RX_BCLK/FB_AD6/FTM2_FLT0 (io), D8 PTC5/LLWU_P9/SPI0_SCK/LPTMR0_ALT2/I2S0_RXD0/FB_AD10/CMP0_OUT (io), D9 PTB21/SPI2_SCK/FB_AD30/CMP1_OUT (io), D10 PTB20/SPI2_PCS0/FB_AD31/CMP0_OUT (io), D11 PTB19/TSI0_CH12/CAN0_RX/FTM2_CH1/I2S0_TX_FS/~{FB_OE}/FTM2_QD_PHB (io), D12 PTB18/TSI0_CH11/CAN0_TX/FTM2_CH0/I2S0_TX_BCLK/FB_AD15/FTM2_QD_PHA (io), E1 PTE6/SPI1_PCS3/~{UART3_CTS}/I2S0_MCLK/USB_SOF_OUT (io), E2 PTE5/SPI1_PCS2/UART3_RX/SDHC0_D2 (io), E3 PTE4/LLWU_P2/SPI1_PCS0/UART3_TX/SDHC0_D3 (io), E4 PTE3/ADC1_SE7A/SPI1_SIN/~{UART1_RTS}/SDHC0_CMD/SPI1_SOUT (io), E5 VDD1 (power), E6 VDD2 (power), E7 VDD3 (power), E8 VDD4 (power), E9 PTB17/TSI0_CH10/SPI1_SIN/UART0_TX/FB_AD16/~{EWM_OUT} (io), E10 PTB16/TSI0_CH9/SPI1_SOUT/UART0_RX/FB_AD17/EWM_IN (io), E11 PTB11/ADC1_SE15/SPI1_SCK/UART3_TX/FB_AD18/FTM0_FLT2 (io), E12 PTB10/ADC1_SE14/SPI1_PCS0/UART3_RX/FB_AD19/FTM0_FLT1 (io), F1 PTE10/~{UART5_CTS}/I2S0_TXD0 (io), F2 PTE9/I2S0_TXD1/UART5_RX/I2S0_RX_BCLK (io), F3 PTE8/I2S0_RXD1/UART5_TX/I2S0_RX_FS (io), F4 PTE7/~{UART3_RTS}/I2S0_RXD0 (io), F5 VDD5 (power), F6 VSS1 (power), F7 VSS2 (power), F8 VDD6 (power), F9 PTB9/SPI1_PCS1/~{UART3_CTS}/FB_AD20 (io), F10 PTB8/~{UART3_RTS}/FB_AD21 (io), F11 PTB7/ADC1_SE13/FB_AD22 (io), F12 PTB6/ADC1_SE12/FB_AD23 (io), G1 VOUT33 (power), G2 VREGIN (power), G3 PTE12/I2S0_TX_BCLK (io), G4 PTE11/~{UART5_RTS}/I2S0_TX_FS (io), G5 VREFH (power), G6 VREFL (power), G7 VSS5 (power), G8 VSS6 (power), G9 PTB5/ADC1_SE11/ENET0_1588_TMR3/FTM2_FLT0 (io), G10 PTB4/ADC1_SE10/ENET0_1588_TMR2/FTM1_FLT0 (io), G11 PTB3/ADC0_SE13/TSI0_CH8/I2C0_SDA/~{UART0_CTS}/~{UART0_COL}/ENET0_1588_TMR1/FTM0_FLT0 (io), G12 PTB2/ADC0_SE12/TSI0_CH7/I2C0_SCL/~{UART0_RTS}/ENET0_1588_TMR0/FTM0_FLT3 (io), H1 USB0_DP (io), H2 USB0_DM (io), H3 VSS8 (power), H4 PTE28 (io), H5 VDDA (power), H6 VSSA (power), H7 VSS3 (power), H8 VSS4 (power), H9 PTB1/ADC0_SE9/ADC1_SE9/TSI0_CH6/I2C0_SDA/FTM1_CH1/RMII0_MDC/MII0_MDC/FTM1_QD_PHB (io), H10 PTB0/LLWU_P5/ADC0_SE8/ADC1_SE8/TSI0_CH0/I2C0_SCL/FTM1_CH0/RMII0_MDIO/MII0_MDIO/FTM1_QD_PHA (io), H11 PTA29/MII0_COL/FB_A24 (io), H12 PTA28/MII0_TXER/FB_A25 (io), J1 ADC0_DP1 (io), J2 ADC0_DM1 (io), J3 ADC0_SE16/CMP1_IN2/ADC0_SE21 (io), J4 PTE27/~{UART4_RTS} (io), J5 PTA0/JTAG_TCLK/SWD_CLK/EZP_CLK/TSI0_CH1/~{UART0_CTS}/~{UART0_COL}/FTM0_CH5 (io), J6 PTA1/JTAG_TDI/EZP_DI/TSI0_CH2/UART0_RX/FTM0_CH6 (io), J7 PTA6/FTM0_CH3/TRACE_CLKOUT (io), J8 PTA7/ADC0_SE10/FTM0_CH4/TRACE_D3 (io), J9 PTA13/LLWU_P4/CMP2_IN1/CAN0_RX/FTM1_CH1/RMII0_RXD0/MII0_RXD0/I2S0_TX_FS/FTM1_QD_PHB (io), J10 PTA27/MII0_CRS/FB_A26 (io), J11 PTA26/MII0_TXD3/FB_A27 (io), J12 PTA25/MII0_TXCLK/FB_A28 (io), K1 ADC1_DP1 (io), K2 ADC1_DM1 (io), K3 ADC1_SE16/CMP2_IN2/ADC0_SE22 (io), K4 PTE26/ENET_1588_CLKIN/~{UART4_CTS}/RTC_CLKOUT/USB_CLKIN (io), K5 PTE25/ADC0_SE18/CAN1_RX/UART4_RX/EWM_IN (io), K6 PTA2/JTAG_TDO/TRACE_SWO/EZP_DO/TSI0_CH3/UART0_TX/FTM0_CH7 (io), K7 PTA3/JTAG_TMS/SWD_DIO/TSI0_CH4/~{UART0_RTS}/FTM0_CH0 (io), K8 PTA8/ADC0_SE11/FTM1_CH0/FTM1_QD_PHA/TRACE_D2 (io), K9 PTA12/CMP2_IN0/CAN0_TX/FTM1_CH0/RMII0_RXD1/MII0_RXD1/I2S0_TXD0/FTM1_QD_PHA (io), K10 PTA16/SPI0_SOUT/~{UART0_CTS}/~{UART0_COL}/RMII0_TXD0/MII0_TXD0/I2S0_RX_FS/I2S0_RXD1 (io), K11 PTA17/ADC1_SE17/SPI0_SIN/~{UART0_RTS}/RMII0_TXD1/MII0_TXD1/I2S0_MCLK (io), K12 PTA24/MII0_TXD2/FB_A29 (io), L1 PGA0_DP/ADC0_DP0/ADC1_DP3 (io), L2 PGA0_DM/ADC0_DM0/ADC1_DM3 (io), L3 DAC0_OUT/CMP1_IN3/ADC0_SE23 (io), L4 DAC1_OUT/CMP0_IN4/CMP2_IN3/ADC1_SE23 (io), L5 ~{RTC_WAKEUP}, L6 VBAT (power), L7 PTA4/LLWU_P3/~{NMI}/~{EZP_CS}/TSI0_CH5/FTM0_CH1 (io), L8 PTA9/FTM1_CH1/MII0_RXD3/FTM1_QD_PHB/TRACE_D1 (io), L9 PTA11/FTM2_CH1/MII0_RXCLK/FTM2_QD_PHB (io), L10 PTA14/SPI0_PCS0/UART0_TX/RMII0_CRS_DV/MII0_RXDV/I2S0_RX_BCLK/I2S0_TXD1 (io), L11 PTA15/SPI0_SCK/UART0_RX/RMII0_TXEN/MII0_TXEN/I2S0_RXD0 (io), L12 ~{RESET} (io), M1 PGA1_DP/ADC1_DP0/ADC0_DP3 (io), M2 PGA1_DM/ADC1_DM0/ADC0_DM3 (io), M3 VREF_OUT/CMP1_IN5/CMP0_IN5/ADC1_SE18 (power), M4 PTE24/ADC0_SE17/CAN1_TX/UART4_TX/~{EWM_OUT} (io), M5 NC_M5, M6 EXTAL32 (in), M7 XTAL32 (out), M8 PTA5/USB_CLKIN/FTM0_CH2/RMII0_RXER/MII0_RXER/CMP2_OUT/I2S0_TX_BCLK/~{JTAG_TRST} (io), M9 PTA10/FTM2_CH0/MII0_RXD2/FTM2_QD_PHA/TRACE_D0 (io), M10 VSS7 (power), M11 PTA19/XTAL0/FTM1_FLT0/FTM_CLKIN1/LPTMR0_ALT1 (io), M12 PTA18/EXTAL0/FTM0_FLT2/FTM_CLKIN0 (io)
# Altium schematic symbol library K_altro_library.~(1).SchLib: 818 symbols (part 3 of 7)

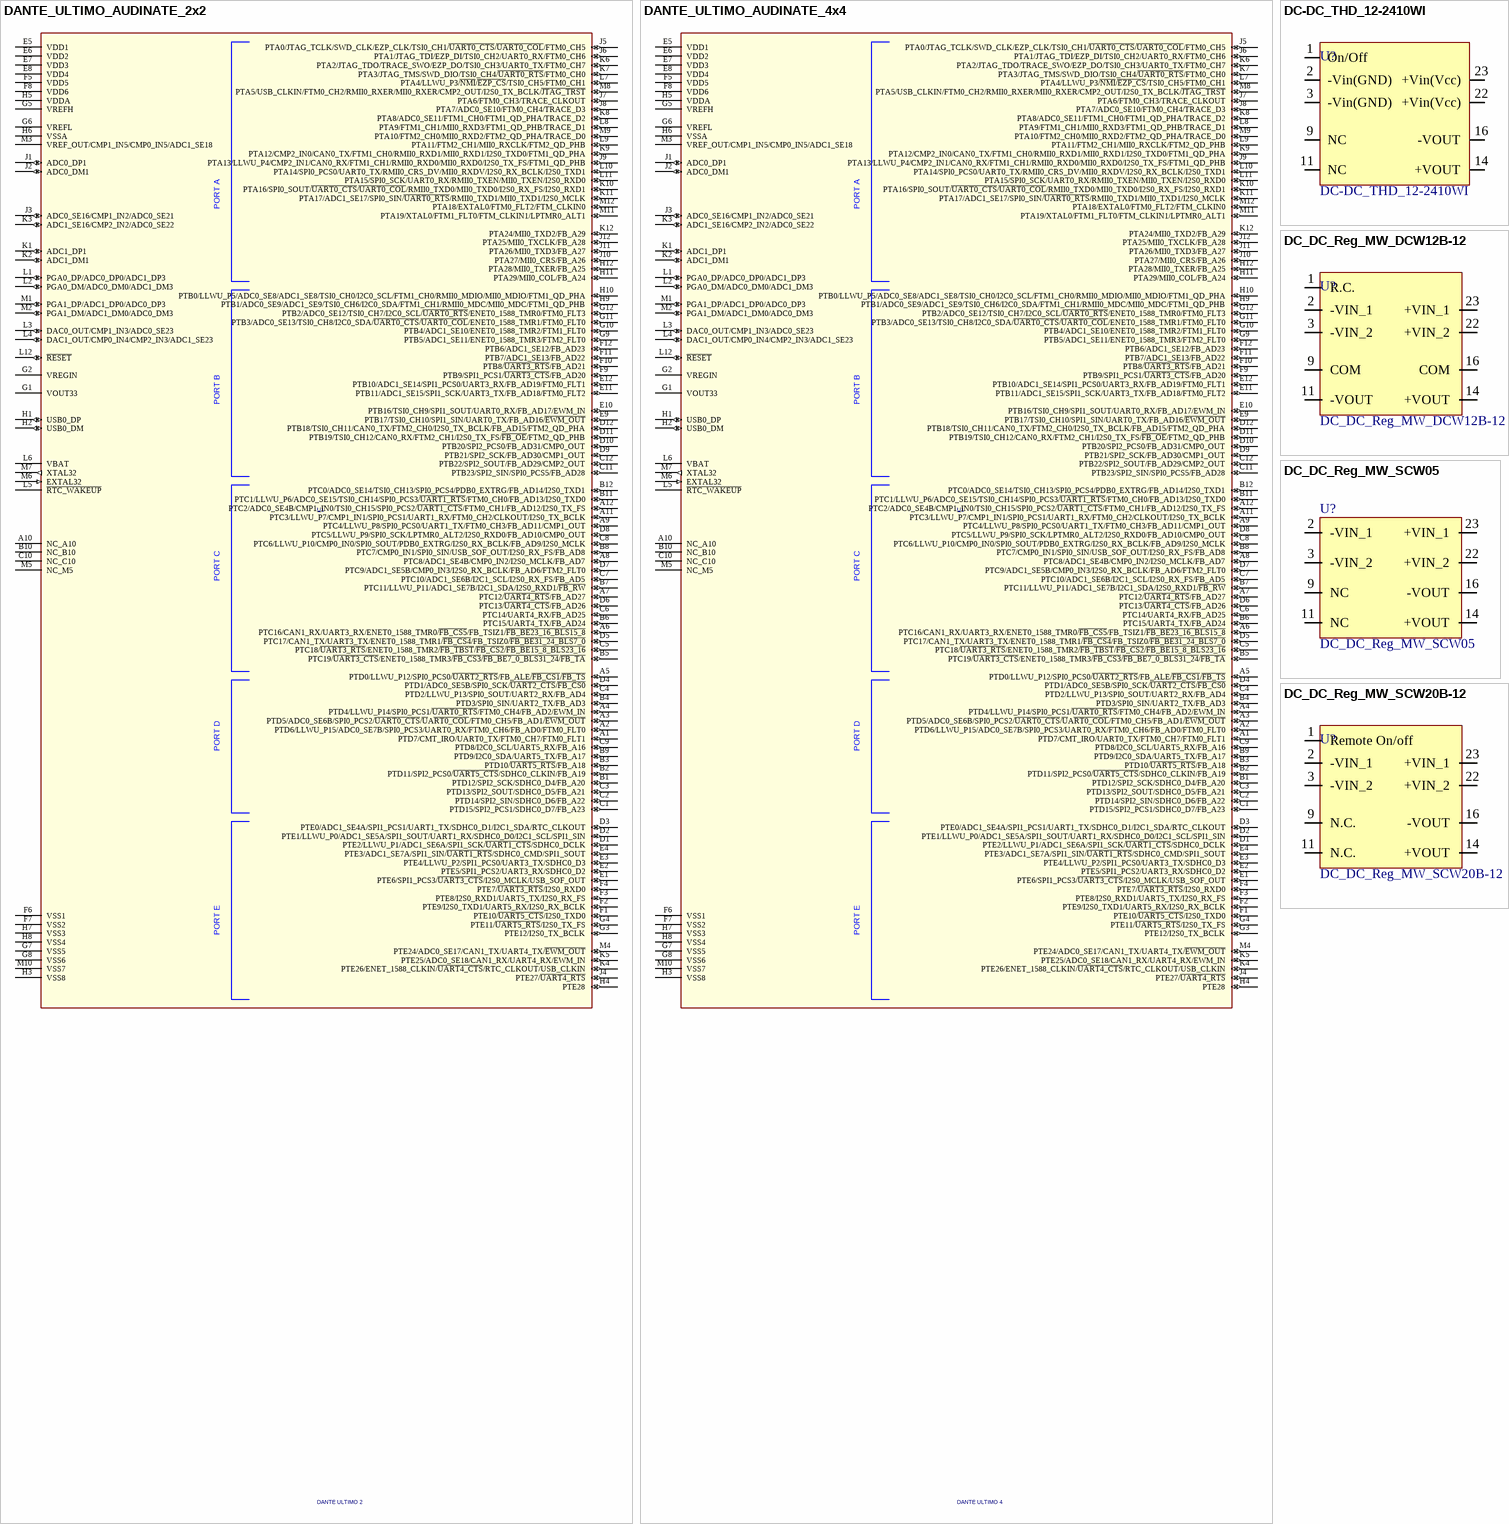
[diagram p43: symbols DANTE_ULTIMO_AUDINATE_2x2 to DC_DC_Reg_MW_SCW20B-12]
## DC-DC_THD_12-2410WI
designator U?
Costo: 0; Aggiornato: NO
footprint DC-DC_THD_12-2410WI (Footprint not found)
pins: 1 On/Off, 2 -Vin(GND), 3 -Vin(GND), 9 NC, 11 NC, 14 +VOUT, 16 -VOUT, 22 +Vin(Vcc), 23 +Vin(Vcc)

## DC_DC_Reg_MW_DCW12B-12
designator U?
Costo: 0; Aggiornato: NO
footprint DC_DC_Reg_MW_SCW20_DCW12
pins: 1 R.C., 2 -VIN_1, 3 -VIN_2, 9 COM, 11 -VOUT, 14 +VOUT, 16 COM, 22 +VIN_2, 23 +VIN_1

## DC_DC_Reg_MW_SCW05
designator U?
HPcode: ALISCW05B12; Costo: 0; Aggiornato: NO
footprint DC_DC_Reg_MW_SCW05
pins: 2 -VIN_1, 3 -VIN_2, 9 NC, 11 NC, 14 +VOUT, 16 -VOUT, 22 +VIN_2, 23 +VIN_1

## DC_DC_Reg_MW_SCW20B-12
designator U?
Costo: 0; Aggiornato: NO
footprint DC_DC_Reg_MW_SCW20_DCW12
pins: 1 Remote On/off, 2 -VIN_1, 3 -VIN_2, 9 N.C., 11 N.C., 14 +VOUT, 16 -VOUT, 22 +VIN_2, 23 +VIN_1


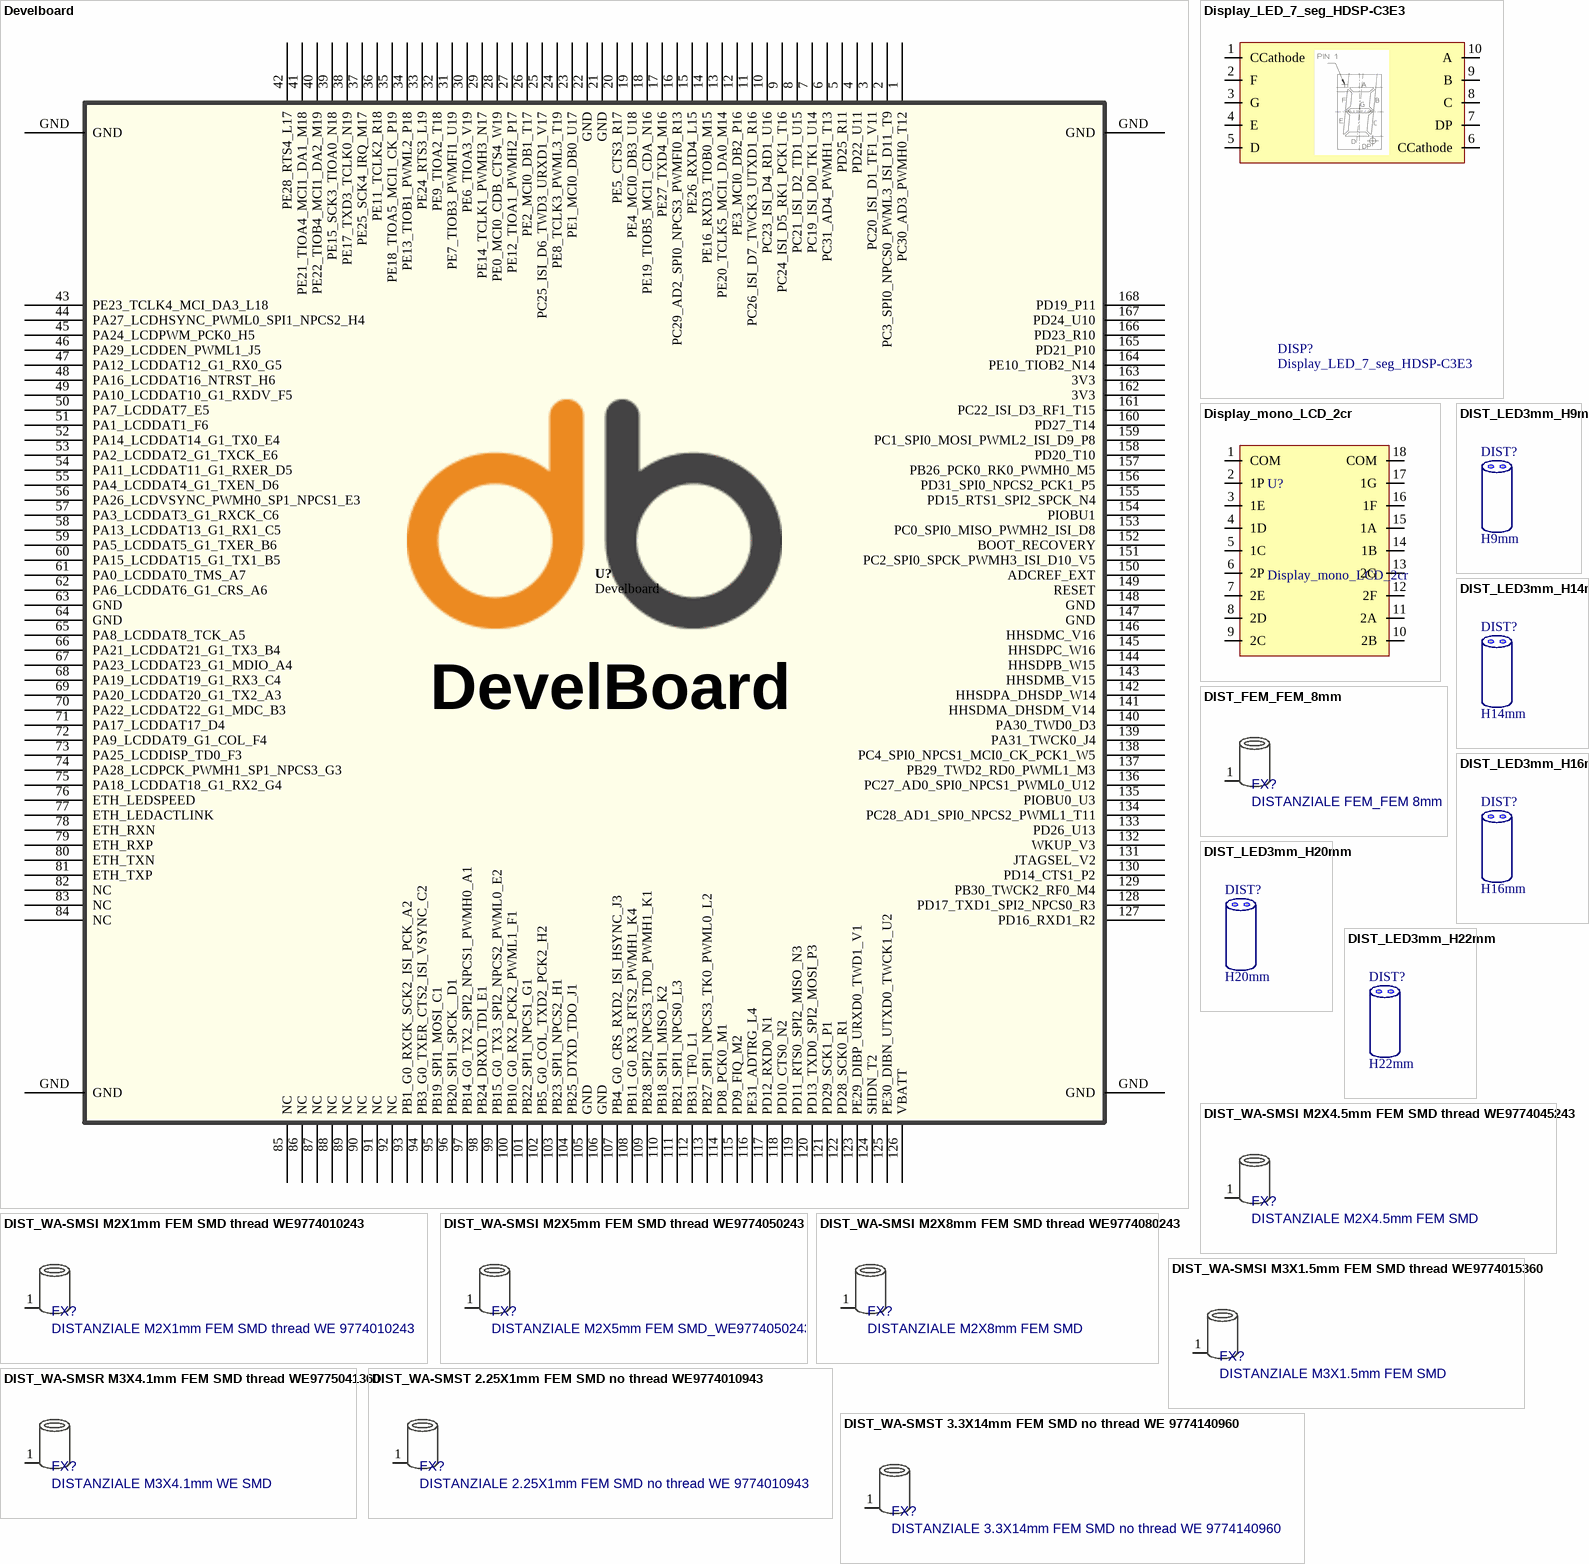
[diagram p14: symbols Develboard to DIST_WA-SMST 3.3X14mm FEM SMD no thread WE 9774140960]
## Develboard
designator U?
Aggiornato: NO; Costo: 0
footprint develboard_footprint
pins: 1 PC30_AD3_PWMH0_T12, 2 PC3_SPI0_NPCS0_PWML3_ISI_D11_T9, 3 PC20_ISI_D1_TF1_V11, 4 PD22_U11, 5 PD25_R11, 6 PC31_AD4_PWMH1_T13, 7 PC19_ISI_D0_TK1_U14, 8 PC21_ISI_D2_TD1_U15, 9 PC24_ISI_D5_RK1_PCK1_T16, 10 PC23_ISI_D4_RD1_U16, 11 PC26_ISI_D7_TWCK3_UTXD1_R16, 12 PE3_MCI0_DB2_P16, 13 PE20_TCLK5_MCI1_DA0_M14, 14 PE16_RXD3_TIOB0_M15, 15 PE26_RXD4_L15, 16 PC29_AD2_SPI0_NPCS3_PWMFI0_R13, 17 PE27_TXD4_M16, 18 PE19_TIOB5_MCI1_CDA_N16, 19 PE4_MCI0_DB3_U18, 20 PE5_CTS3_R17, 21 GND, 22 GND, 23 PE1_MCI0_DB0_U17, 24 PE8_TCLK3_PWML3_T19, 25 PC25_ISI_D6_TWD3_URXD1_V17, 26 PE2_MCI0_DB1_T17, 27 PE12_TIOA1_PWMH2_P17, 28 PE0_MCI0_CDB_CTS4_W19, 29 PE14_TCLK1_PWMH3_N17, 30 PE6_TIOA3_V19, 31 PE7_TIOB3_PWMFI1_U19, 32 PE9_TIOA2_T18, 33 PE24_RTS3_L19, 34 PE13_TIOB1_PWML2_P18, 35 PE18_TIOA5_MCI1_CK_P19, 36 PE11_TCLK2_R18, 37 PE25_SCK4_IRQ_M17, 38 PE17_TXD3_TCLK0_N19, 39 PE15_SCK3_TIOA0_N18, 40 PE22_TIOB4_MCI1_DA2_M19, 41 PE21_TIOA4_MCI1_DA1_M18, 42 PE28_RTS4_L17, 43 PE23_TCLK4_MCI_DA3_L18, 44 PA27_LCDHSYNC_PWML0_SPI1_NPCS2_H4, 45 PA24_LCDPWM_PCK0_H5, 46 PA29_LCDDEN_PWML1_J5, 47 PA12_LCDDAT12_G1_RX0_G5, 48 PA16_LCDDAT16_NTRST_H6, 49 PA10_LCDDAT10_G1_RXDV_F5, 50 PA7_LCDDAT7_E5, 51 PA1_LCDDAT1_F6, 52 PA14_LCDDAT14_G1_TX0_E4, 53 PA2_LCDDAT2_G1_TXCK_E6, 54 PA11_LCDDAT11_G1_RXER_D5, 55 PA4_LCDDAT4_G1_TXEN_D6, 56 PA26_LCDVSYNC_PWMH0_SP1_NPCS1_E3, 57 PA3_LCDDAT3_G1_RXCK_C6, 58 PA13_LCDDAT13_G1_RX1_C5, 59 PA5_LCDDAT5_G1_TXER_B6, 60 PA15_LCDDAT15_G1_TX1_B5, 61 PA0_LCDDAT0_TMS_A7, 62 PA6_LCDDAT6_G1_CRS_A6, 63 GND, 64 GND, 65 PA8_LCDDAT8_TCK_A5, 66 PA21_LCDDAT21_G1_TX3_B4, 67 PA23_LCDDAT23_G1_MDIO_A4, 68 PA19_LCDDAT19_G1_RX3_C4, 69 PA20_LCDDAT20_G1_TX2_A3, 70 PA22_LCDDAT22_G1_MDC_B3, 71 PA17_LCDDAT17_D4, 72 PA9_LCDDAT9_G1_COL_F4, 73 PA25_LCDDISP_TD0_F3, 74 PA28_LCDPCK_PWMH1_SP1_NPCS3_G3, 75 PA18_LCDDAT18_G1_RX2_G4, 76 ETH_LEDSPEED, 77 ETH_LEDACTLINK, 78 ETH_RXN, 79 ETH_RXP, 80 ETH_TXN, 81 ETH_TXP, 82 NC, 83 NC, 84 NC, 85 NC, 86 NC, 87 NC, 88 NC, 89 NC, 90 NC, 91 NC, 92 NC, 93 PB1_G0_RXCK_SCK2_ISI_PCK_A2, 94 PB3_G0_TXER_CTS2_ISI_VSYNC_C2, 95 PB19_SPI1_MOSI_C1, 96 PB20_SPI1_SPCK__D1, 97 PB14_G0_TX2_SPI2_NPCS1_PWMH0_A1, 98 PB24_DRXD_TDI_E1, 99 PB15_G0_TX3_SPI2_NPCS2_PWML0_E2, 100 PB10_G0_RX2_PCK2_PWML1_F1, 101 PB22_SPI1_NPCS1_G1, 102 PB5_G0_COL_TXD2_PCK2_H2, 103 PB23_SPI1_NPCS2_H1, 104 PB25_DTXD_TDO_J1, 105 GND, 106 GND, 107 PB4_G0_CRS_RXD2_ISI_HSYNC_J3, 108 PB11_G0_RX3_RTS2_PWMH1_K4, 109 PB28_SPI2_NPCS3_TD0_PWMH1_K1, 110 PB18_SPI1_MISO_K2, 111 PB21_SPI1_NPCS0_L3, 112 PB31_TF0_L1, 113 PB27_SPI1_NPCS3_TK0_PWML0_L2, 114 PD8_PCK0_M1, 115 PD9_FIQ_M2, 116 PE31_ADTRG_L4, 117 PD12_RXD0_N1, 118 PD10_CTS0_N2, 119 PD11_RTS0_SPI2_MISO_N3, 120 PD13_TXD0_SPI2_MOSI_P3, 121 PD29_SCK1_P1, 122 PD28_SCK0_R1, 123 PE29_DIBP_URXD0_TWD1_V1, 124 SHDN_T2, 125 PE30_DIBN_UTXD0_TWCK1_U2, 126 VBATT, 127 PD16_RXD1_R2, 128 PD17_TXD1_SPI2_NPCS0_R3, 129 PB30_TWCK2_RF0_M4, 130 PD14_CTS1_P2, 131 JTAGSEL_V2, 132 WKUP_V3, 133 PD26_U13, 134 PC28_AD1_SPI0_NPCS2_PWML1_T11, 135 PIOBU0_U3, 136 PC27_AD0_SPI0_NPCS1_PWML0_U12, 137 PB29_TWD2_RD0_PWML1_M3, 138 PC4_SPI0_NPCS1_MCI0_CK_PCK1_W5, 139 PA31_TWCK0_J4, 140 PA30_TWD0_D3, 141 HHSDMA_DHSDM_V14, 142 HHSDPA_DHSDP_W14, 143 HHSDMB_V15, 144 HHSDPB_W15, 145 HHSDPC_W16, 146 HHSDMC_V16, 147 GND, 148 GND, 149 RESET, 150 ADCREF_EXT, 151 PC2_SPI0_SPCK_PWMH3_ISI_D10_V5, 152 BOOT_RECOVERY, 153 PC0_SPI0_MISO_PWMH2_ISI_D8, 154 PIOBU1, 155 PD15_RTS1_SPI2_SPCK_N4, 156 PD31_SPI0_NPCS2_PCK1_P5, 157 PB26_PCK0_RK0_PWMH0_M5, 158 PD20_T10, 159 PC1_SPI0_MOSI_PWML2_ISI_D9_P8, 160 PD27_T14, 161 PC22_ISI_D3_RF1_T15, 162 3V3, 163 3V3, 164 PE10_TIOB2_N14, 165 PD21_P10, 166 PD23_R10, 167 PD24_U10, 168 PD19_P11, GND, GND, GND, GND

## Display_LED_7_seg_HDSP-C3E3
designator DISP?
Aggiornato: n; Costo: 0
footprint Display_LED_7_seg_HDSP-C3E3 (Display_LED_7_seg HDSP-C3E3)
pins: 1 CCathode "Common Cathode", 2 F, 3 G, 4 E, 5 D, 6 CCathode "Common Cathode", 7 DP, 8 C, 9 B, 10 A

## Display_mono_LCD_2cr
designator U?
Costo: 5; Aggiornato: n; ContoLavoro: 0
footprint DISPLAY_LCD_RS215-6442
pins: 1 COM, 2 1P, 3 1E, 4 1D, 5 1C, 6 2P, 7 2E, 8 2D, 9 2C, 10 2B, 11 2A, 12 2F, 13 2G, 14 1B, 15 1A, 16 1F, 17 1G, 18 COM

## DIST_FEM_FEM_8mm
designator FX?, comment DISTANZIALE FEM_FEM 8mm
Hpcode: DISTFFM3H08; Costo: 0,06; Aggiornato: S; ContoLavoro: 1
footprint SCREW_M3_ELECTRIC
pins: 1

## DIST_LED3mm_H9mm
designator DIST?, comment H9mm  (mechanical)
DISTANZIALE PER LED 2PIN 3mm H9mm; Costo: 0,05; Aggiornato: s; Detail: COSTO IPOTIZZATO; ContoLavoro: 0
pins: 1 hidden
1 alternate drawing of the same symbol

## DIST_LED3mm_H14mm
designator DIST?, comment H14mm  (mechanical)
DISTANZIALE PER LED 2PIN 3mm H14mm; Costo: 0,05; Aggiornato: s; Detail: COSTO IPOTIZZATO; ContoLavoro: 0
pins: 1 hidden
1 alternate drawing of the same symbol

## DIST_LED3mm_H16mm
designator DIST?, comment H16mm  (mechanical)
DISTANZIALE PER LED 2PIN 3mm H16mm; Costo: 0,05; Aggiornato: NO; Detail: COSTO IPOTIZZATO; ContoLavoro: 0
pins: 1 hidden
1 alternate drawing of the same symbol

## DIST_LED3mm_H20mm
designator DIST?, comment H20mm  (mechanical)
DISTANZIALE PER LED 2PIN 3mm H20mm; Costo: 0,05; Aggiornato: NO; Detail: COSTO IPOTIZZATO; ContoLavoro: 0
pins: 1 hidden
1 alternate drawing of the same symbol

## DIST_LED3mm_H22mm
designator DIST?, comment H22mm  (mechanical)
DISTANZIALE PER LED 2PIN 3mm H22mm; Costo: 0,05; Aggiornato: NO; Detail: COSTO IPOTIZZATO; ContoLavoro: 0
pins: 1 hidden
1 alternate drawing of the same symbol

## DIST_WA-SMSI M2X1mm FEM SMD thread WE9774010243
designator FX?, comment DISTANZIALE M2X1mm FEM SMD thread WE 9774010243
Detail: 0,06€ 1000pz WE offerta A18IT013140.pdf; Costo: 0,06; Aggiornato: S; ContoLavoro: 0
footprint Distanziale 2.25x1mm WE9774010943
pins: 1

## DIST_WA-SMSI M2X4.5mm FEM SMD thread WE9774045243
designator FX?, comment DISTANZIALE M2X4.5mm FEM SMD
Detail: 0; Aggiornato: NO
footprint Distanziale M2x4.5mm WE9774045243
pins: 1

## DIST_WA-SMSI M2X5mm FEM SMD thread WE9774050243
designator FX?, comment DISTANZIALE M2X5mm FEM SMD_WE9774050243
DISTANZIALE M2X5mm FEM SMD; Detail: € Wurth Pz> 100; Hpcode: DISTF2X5SMD; Costo: 0,15; Aggiornato: S; ContoLavoro: 0
footprint Distanziale M2x5mm WE9774050243
pins: 1

## DIST_WA-SMSI M2X8mm FEM SMD thread WE9774080243
designator FX?, comment DISTANZIALE M2X8mm FEM SMD
Detail: € Wurth Pz> 100; Costo: 0; Aggiornato: N
footprint Distanziale M2x8mm WE9774080243
pins: 1

## DIST_WA-SMSI M3X1.5mm FEM SMD thread WE9774015360
designator FX?, comment DISTANZIALE M3X1.5mm FEM SMD
Detail: 9774015360 0,115€ Wurth Pz3000 , 9774015360R 0,190 Wurth Pz3600; Costo: 0,19; Aggiornato: S; ContoLavoro: 0
footprint Distanziale M3x1.5mm WE9774015360
pins: 1

## DIST_WA-SMSR M3X4.1mm FEM SMD thread WE9775041360
designator FX?, comment DISTANZIALE M3X4.1mm WE SMD
DISTANZIALE SMD M3X4.1mm internal thread WE; Detail: € Wurth Pz> 100; Hpcode: DISTF2X5SMD; Costo: 0,15; Aggiornato: S; ContoLavoro: 0
footprint DISTANZIALE SMD M3x4.1 WE 9775041360
pins: 1

## DIST_WA-SMST 2.25X1mm FEM SMD no thread WE9774010943
designator FX?, comment DISTANZIALE 2.25X1mm FEM SMD no thread WE 9774010943
DISTANZIALE 2.25X1mm FEM SMD; Costo: 0; Aggiornato: N
footprint Distanziale 2.25x1mm WE9774010943
pins: 1

## DIST_WA-SMST 3.3X14mm FEM SMD no thread WE 9774140960
designator FX?, comment DISTANZIALE 3.3X14mm FEM SMD no thread WE 9774140960
DISTANZIALE 3.3X14mm FEM SMD; Detail: da quotare credo 0,195 indicativo; Costo: 0,195; Aggiornato: S; ContoLavoro: 0
footprint Distanziale 3.3x14mm WE9774140960
pins: 1


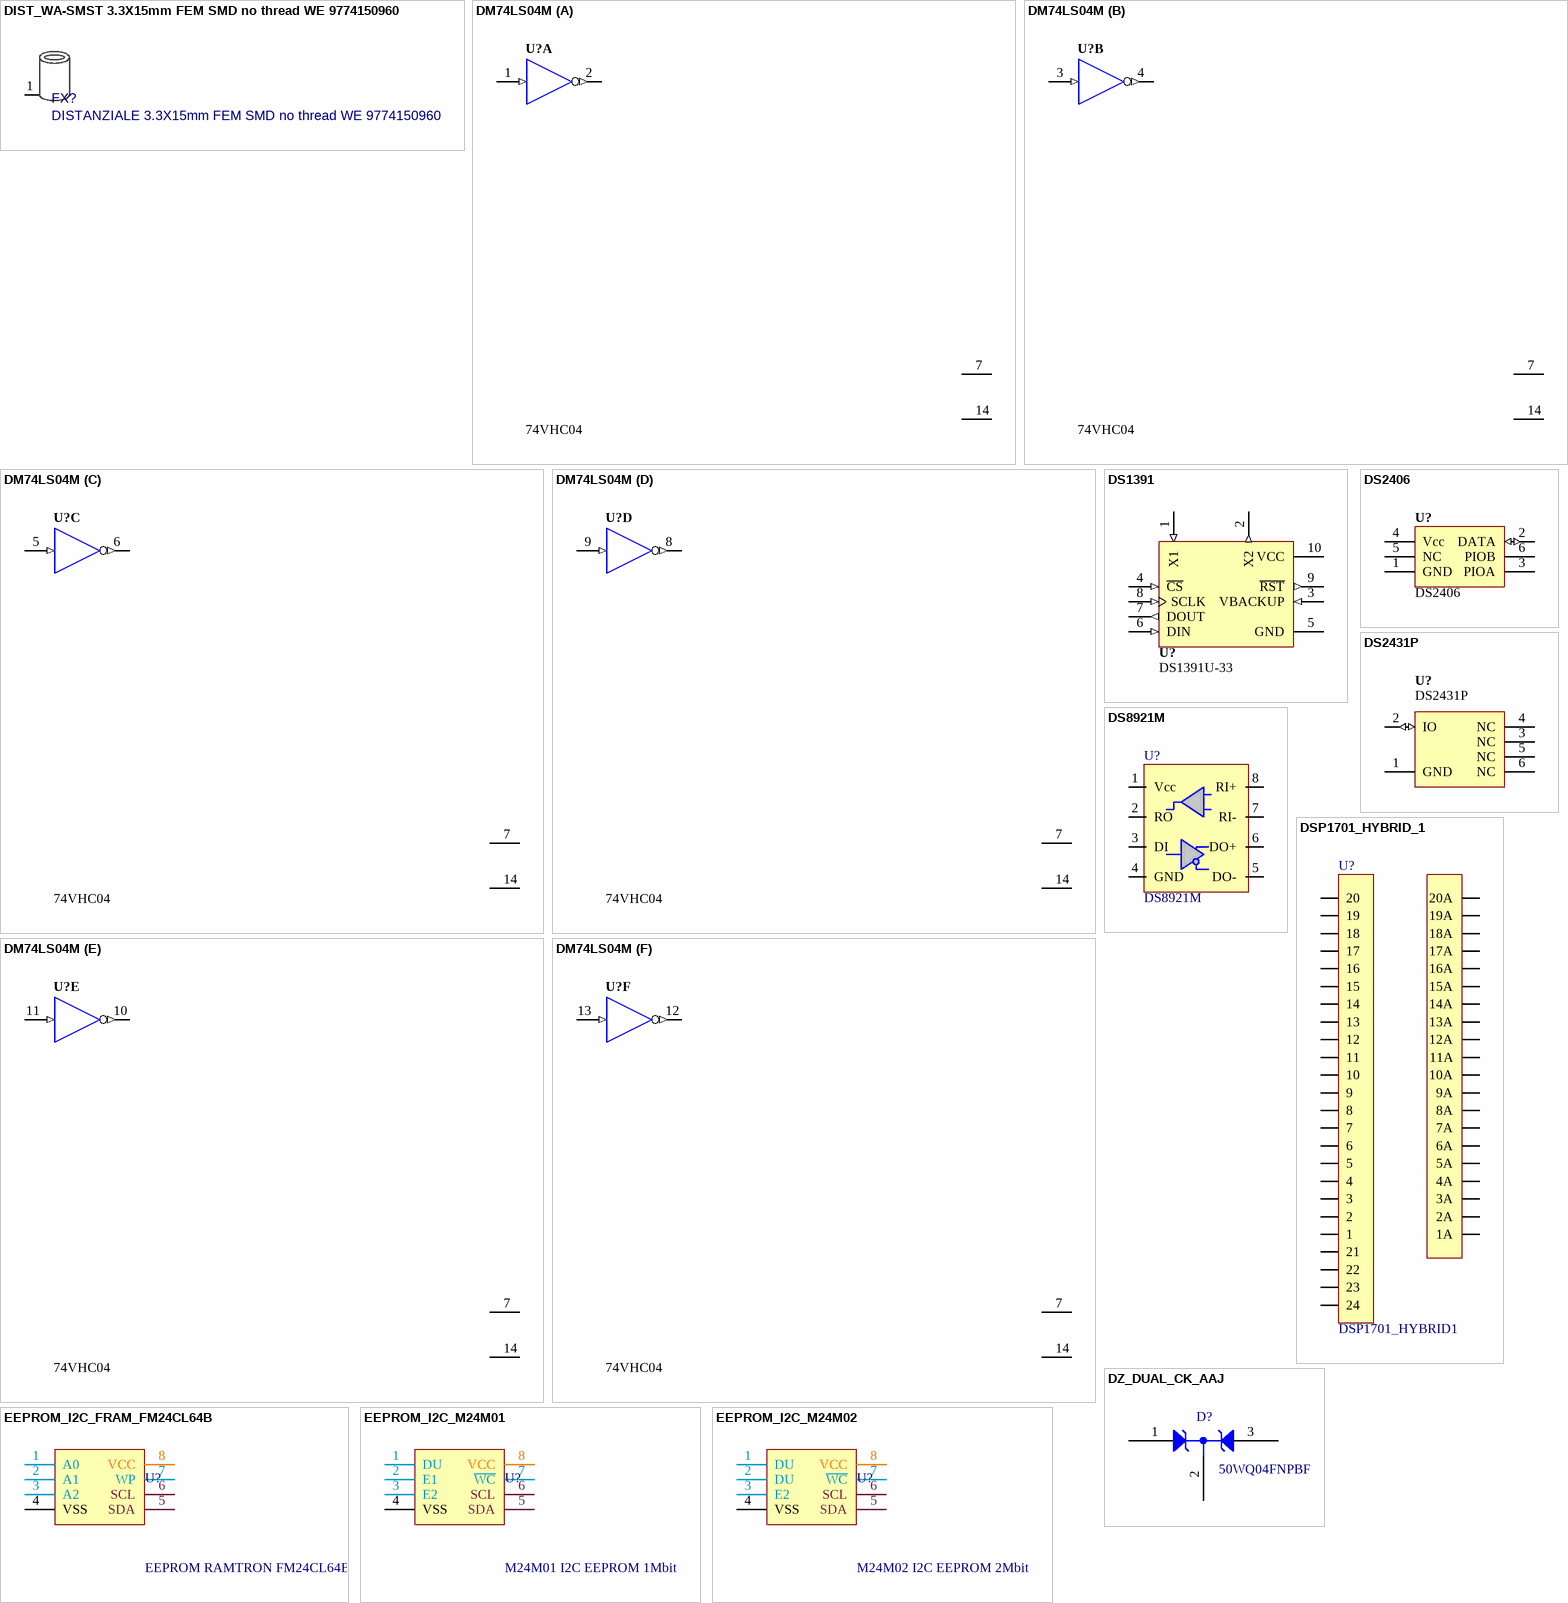
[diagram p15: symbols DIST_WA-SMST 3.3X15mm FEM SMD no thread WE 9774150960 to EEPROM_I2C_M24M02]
## DIST_WA-SMST 3.3X15mm FEM SMD no thread WE 9774150960
designator FX?, comment DISTANZIALE 3.3X15mm FEM SMD no thread WE 9774150960
DISTANZIALE 3.3X15mm FEM SMD; Detail: 0,195€ WE Pz>3000 Offerta A19IT023595; Costo: 0,195; Aggiornato: S; ContoLavoro: 0
footprint Distanziale 3.3x15mm WE9774150960
pins: 1

## DM74LS04M
designator U?, comment 74VHC04
HEX Inverter; Aggiornato: NO; Costo: 0
footprint TSSOP14
pins on every part: 7 GND (power), 14 VCC (power)
part A pins: 1 A (in), 2 Y (out)
part B pins: 3 A (in), 4 Y (out)
part C pins: 5 A (in), 6 Y (out)
part D pins: 8 Y (out), 9 A (in)
part E pins: 10 Y (out), 11 A (in)
part F pins: 12 Y (out), 13 A (in)

## DS1391
designator U?, comment DS1391U-33
DS1391U-33, SPI Real-Time Clock with Trickle Charger, 3.3V, 10-Pin uMax/uSOP; Aggiornato: NO; Costo: 0
footprint SSOP50P490-10
pins: 1 X1 (in) "Internal Oscillator Input. Or connection to external 32.768kHz oscillator.", 2 X2 (out) "Internal Oscillator Output. Float if external oscillator connected to pin X1.", 3 VBACKUP (in) "DC Backup Power Input for Primary Cell.", 4 ~{CS} (in) "SPI Chip-Select Input. Used to select or deselect the device.", 5 GND (power) "Ground", 6 DIN (in) "SPI Data Input. Used to shift address and data into the device.", 7 DOUT (out) "SPI Data Output. Data is output when the device is in read mode.", 8 SCLK (in) "Serial Clock Input. Used to control the timing of data in and out.", 9 ~{RST} (out) "Reset", 10 VCC (power) "DC Power Pin for Primary Power Supply."

## DS2406
designator U?
Dual Addressable Switch Plus 1KB Memory; Bit Width: Bits; Supply Voltage: mV; Aggiornato: NO; Costo: 0
footprint TSOC6
pins: 1 GND (power), 2 DATA (io), 3 PIOA (oc), 4 Vcc, 5 NC, 6 PIOB

## DS2431P
designator U?
EEPROM, 1-wire, 1024-bit, Surface Mount; Bit Width: Bits; Supply Voltage: 2.8 to 5.25V; Aggiornato: NO; Costo: 0
footprint DSO-C6-D4
pins: 1 GND (power), 2 IO (io), 3 NC, 4 NC, 5 NC, 6 NC

## DS8921M
designator U?
Detail: $0,549 >1000pz TI; Costo: 0,7; Aggiornato: S; ContoLavoro: 0
footprint SO8
pins: 1 Vcc, 2 RO, 3 DI, 4 GND, 5 DO-, 6 DO+, 7 RI-, 8 RI+

## DSP1701_HYBRID_1
designator U?, comment DSP1701_HYBRID1
Aggiornato: NO; Costo: 0
footprint DSP1701_HYBRID1 (Footprint not found)
pins: 1, 1A, 2, 2A, 3, 3A, 4, 4A, 5, 5A, 6, 6A, 7, 7A, 8, 8A, 9, 9A, 10, 10A, 11, 11A, 12, 12A, 13, 13A, 14, 14A, 15, 15A, 16, 16A, 17, 17A, 18, 18A, 19, 19A, 20, 20A, 21, 22, 23, 24

## DZ_DUAL_CK_AAJ
designator D?, comment 50WQ04FNPBF
Costo: 0,626; Aggiornato: NO; ContoLavoro: 0
footprint DPACK_TO252
pins: 0 hidden, 1, 2, 3

## EEPROM_I2C_FRAM_FM24CL64B
designator U?, comment EEPROM RAMTRON FM24CL64B
I2C EEPROM 256KBIT 400KHZ  8SOIC; HPcode: ICFM24CL64BG; Aggiornato: S; Costo: 0,59; ContoLavoro: 1
footprint SO8
pins: 1 A0, 2 A1, 3 A2, 4 VSS, 5 SDA, 6 SCL, 7 WP, 8 VCC

## EEPROM_I2C_M24M01
designator U?, comment M24M01 I2C EEPROM 1Mbit
Detail: 0,635€ RS pz>126; HPcode: ICM24M01; Aggiornato: S; Costo: 0,635; ContoLavoro: 0
footprint SO8
pins: 1 DU, 2 E1, 3 E2, 4 VSS, 5 SDA, 6 SCL, 7 ~{WC}, 8 VCC

## EEPROM_I2C_M24M02
designator U?, comment M24M02 I2C EEPROM 2Mbit
Detail: 1,79€ RS pz>500, 0,96€ Avnet pz>2500; HPcode: ICM24M02; Aggiornato: S; Costo: 0,96; ContoLavoro: 1
footprint SO8
pins: 1 DU, 2 DU, 3 E2, 4 VSS, 5 SDA, 6 SCL, 7 ~{WC}, 8 VCC


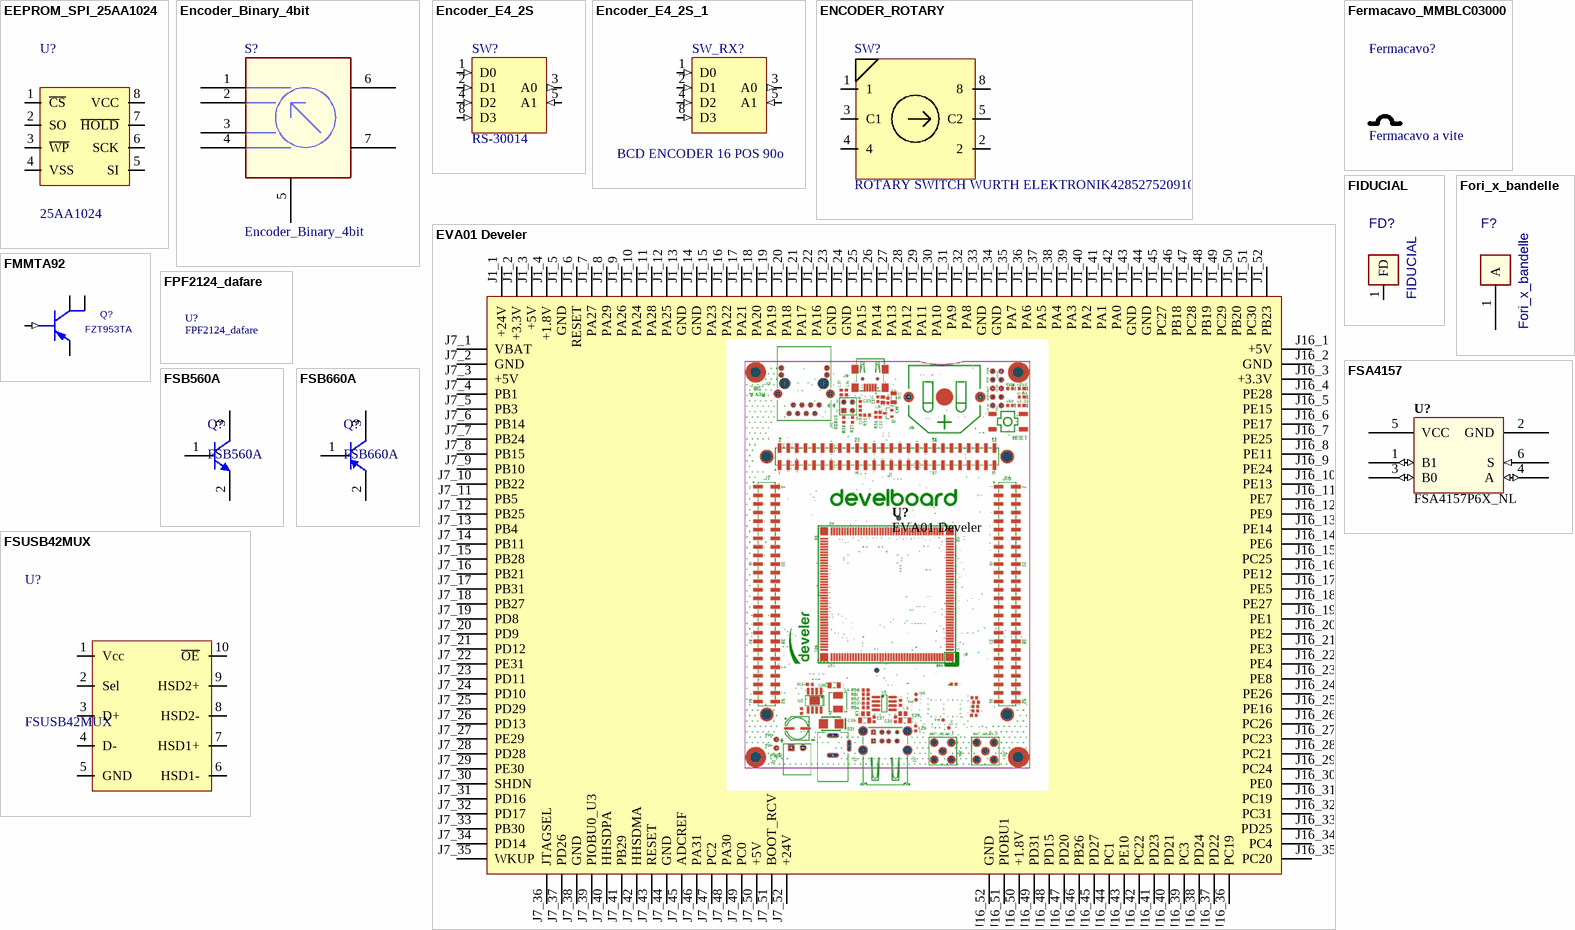
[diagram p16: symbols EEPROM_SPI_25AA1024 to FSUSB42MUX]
## EEPROM_SPI_25AA1024
designator U?, comment 25AA1024
25AA1024 1 Mbit SPI Bus Serial EEPROM; Costo: 0,39; Detail: € RS pz>40; Aggiornato: S; ContoLavoro: 0
footprint SOIJ8_25AA1024_SM
pins: 1 ~{CS}, 2 SO, 3 ~{WP}, 4 VSS, 5 SI, 6 SCK, 7 ~{HOLD}, 8 VCC

## Encoder_Binary_4bit
designator S?
Hpcode: ENCRBIN5CVA20; Aggiornato: NO; Costo: 0
footprint ENCODER REB161PVB_NOBLE
footprint ENCODER4BIT_RE200F
pins: 1, 2, 3 4, 4 8, 5 COM, 6 COM1, 7 COM2

## Encoder_E4_2S
designator SW?, comment RS-30014
4- to 2-Bit Priority Encoder, Single Pin Version; Aggiornato: NO; Costo: 0
footprint ENCODER_RS3XX
pins: 1 D0 (in), 2 D1 (in), 3 A0 (out), 4 D2 (in), 5 A1 (in), 8 D3 (in)

## Encoder_E4_2S_1
designator SW_RX?, comment BCD ENCODER 16 POS 90o
4- to 2-Bit Priority Encoder, Single Pin Version; Aggiornato: NO; Costo: 0
footprint ENCODER_RR3XX
pins: 1 D0 (in), 2 D1 (in), 3 A0 (out), 4 D2 (in), 5 A1 (in), 8 D3 (in)

## ENCODER_ROTARY
designator SW?, comment ROTARY SWITCH WURTH ELEKTRONIK428527520910
Costo: 1,90; Aggiornato: NO; ContoLavoro: 0
footprint ENCODER_RS3XX
pins: 1, 2, 3 C1, 4, 5 C2, 8

## EVA01 Develer
designator U?
Aggiornato: NO; Costo: 0
footprint EVA01_DevelerBoard
pins: J1_1 +24V, J1_2 +3.3V, J1_3 +5V, J1_4 +1.8V, J1_5 GND, J1_6 RESET, J1_7 PA27, J1_8 PA29, J1_9 PA26, J1_10 PA24, J1_11 PA28, J1_12 PA25, J1_13 GND, J1_14 GND, J1_15 PA23, J1_16 PA22, J1_17 PA21, J1_18 PA20, J1_19 PA19, J1_20 PA18, J1_21 PA17, J1_22 PA16, J1_23 GND, J1_24 GND, J1_25 PA15, J1_26 PA14, J1_27 PA13, J1_28 PA12, J1_29 PA11, J1_30 PA10, J1_31 PA9, J1_32 PA8, J1_33 GND, J1_34 GND, J1_35 PA7, J1_36 PA6, J1_37 PA5, J1_38 PA4, J1_39 PA3, J1_40 PA2, J1_41 PA1, J1_42 PA0, J1_43 GND, J1_44 GND, J1_45 PC27, J1_46 PB18, J1_47 PC28, J1_48 PB19, J1_49 PC29, J1_50 PB20, J1_51 PC30, J1_52 PB23, J7_1 VBAT, J7_2 GND, J7_3 +5V, J7_4 PB1, J7_5 PB3, J7_6 PB14, J7_7 PB24, J7_8 PB15, J7_9 PB10, J7_10 PB22, J7_11 PB5, J7_12 PB25, J7_13 PB4, J7_14 PB11, J7_15 PB28, J7_16 PB21, J7_17 PB31, J7_18 PB27, J7_19 PD8, J7_20 PD9, J7_21 PD12, J7_22 PE31, J7_23 PD11, J7_24 PD10, J7_25 PD29, J7_26 PD13, J7_27 PE29, J7_28 PD28, J7_29 PE30, J7_30 SHDN, J7_31 PD16, J7_32 PD17, J7_33 PB30, J7_34 PD14, J7_35 WKUP, J7_36 JTAGSEL, J7_37 PD26, J7_38 GND, J7_39 PIOBU0_U3, J7_40 HHSDPA, J7_41 PB29, J7_42 HHSDMA, J7_43 RESET, J7_44 GND, J7_45 ADCREF, J7_46 PA31, J7_47 PC2, J7_48 PA30, J7_49 PC0, J7_50 +5V, J7_51 BOOT_RCV, J7_52 +24V, J16_1 +5V, J16_2 GND, J16_3 +3.3V, J16_4 PE28, J16_5 PE15, J16_6 PE17, J16_7 PE25, J16_8 PE11, J16_9 PE24, J16_10 PE13, J16_11 PE7, J16_12 PE9, J16_13 PE14, J16_14 PE6, J16_15 PC25, J16_16 PE12, J16_17 PE5, J16_18 PE27, J16_19 PE1, J16_20 PE2, J16_21 PE3, J16_22 PE4, J16_23 PE8, J16_24 PE26, J16_25 PE16, J16_26 PC26, J16_27 PC23, J16_28 PC21, J16_29 PC24, J16_30 PE0, J16_31 PC19, J16_32 PC31, J16_33 PD25, J16_34 PC4, J16_35 PC20, J16_36 PC19, J16_37 PD22, J16_38 PD24, J16_39 PC3, J16_40 PD21, J16_41 PD23, J16_42 PC22, J16_43 PE10, J16_44 PC1, J16_45 PD27, J16_46 PB26, J16_47 PD20, J16_48 PD15, J16_49 PD31, J16_50 +1.8V, J16_51 PIOBU1, J16_52 GND

## Fermacavo_MMBLC03000
designator Fermacavo?, comment Fermacavo a vite  (mechanical)
Fermacavo MMBLC03000; Costo: 0,0666; Aggiornato: s; ContoLavoro: 1
pins: 1 hidden
1 alternate drawing of the same symbol

## FIDUCIAL
designator FD?
FIDUCIAL, REFERENCE POINT; Aggiornato: S; Costo: 0
footprint ZP_FIDUCIAL
footprint ZP_FIDUCIAL_SMALL
footprint fiducial
pins: 1 FD

## FMMTA92
designator Q?, comment FZT953TA
Aggiornato: NO; Costo: 0
footprint SOT223
pins: 1, 2, 3 (in), 4

## Fori_x_bandelle
designator F?  (no BOM)
Aggiornato: NO; Costo: 0
footprint Fori_x_bandelle
pins: 1 A

## FPF2124_dafare
designator U?
Power Load Switch FPF2124; Aggiornato: SI; Costo: 0,162; Detail: (Rs per >1000pz); ContoLavoro: 0
2 alternate drawings of the same symbol

## FSA4157
designator U?, comment FSA4157P6X_NL
Low Voltage 1R  SPDT Analog Switch, SC70-6, 1.65-5.5v; Aggiornato: NO; Costo: 0
footprint SC70_6L
pins: 1 B1 (io), 2 GND (power), 3 B0 (io), 4 A (io), 5 VCC (power), 6 S (in)

## FSB560A
designator Q?
Costo: 0115; Aggiornato: S; ContoLavoro: 0
footprint SOT-23_UP
pins: 1 B, 2 E, 3 C

## FSB660A
designator Q?
Costo: 0,064; Aggiornato: S; ContoLavoro: 0
footprint SOT-23_UP
pins: 1 B, 2 E, 3 C

## FSUSB42MUX
designator U?
Costo: 0,4; Aggiornato: s; ContoLavoro: 0
footprint MSOP_10 (MSOP 10)
pins: 1 Vcc, 2 Sel, 3 D+, 4 D-, 5 GND, 6 HSD1-, 7 HSD1+, 8 HSD2-, 9 HSD2+, 10 ~{OE}


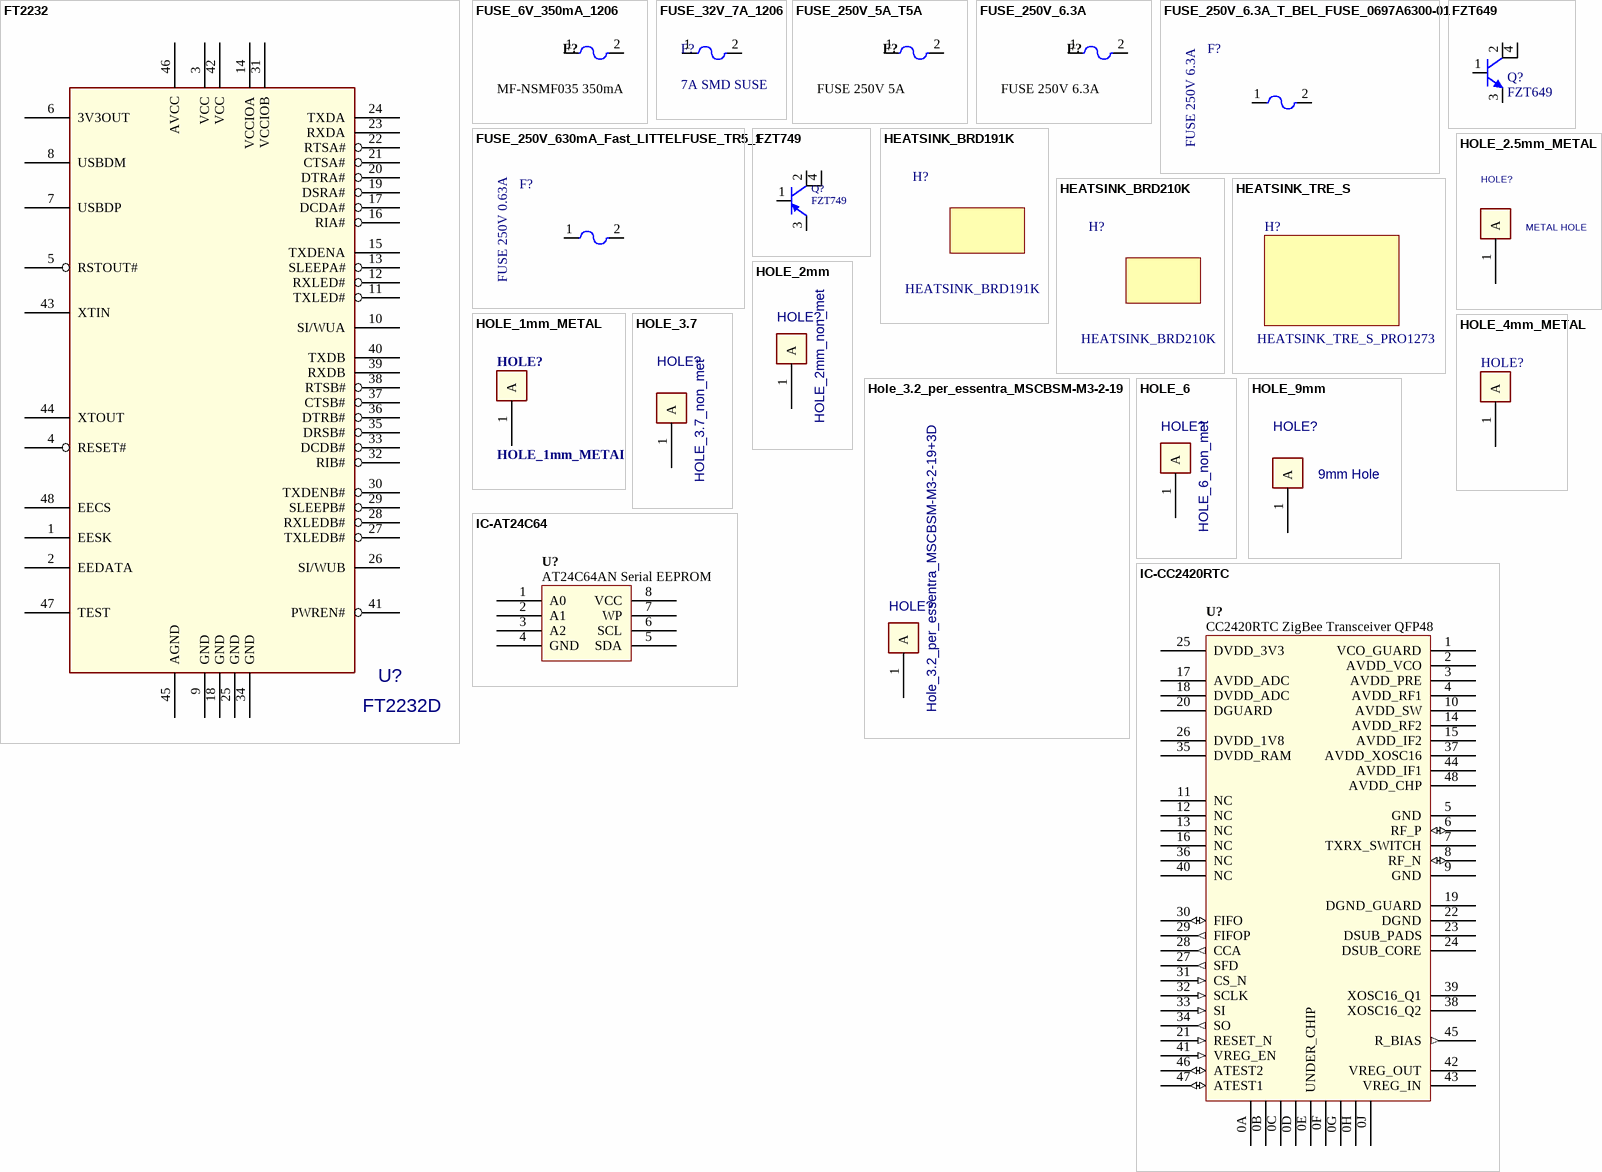
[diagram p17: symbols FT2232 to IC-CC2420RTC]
## FT2232
designator U?, comment FT2232D
Hpcode: ICFT2232D; Costo: 3,5; Aggiornato: s; ContoLavoro: 1
footprint LQFP-48
pins: 1 EESK, 2 EEDATA, 3 VCC, 4 RESET#, 5 RSTOUT#, 6 3V3OUT, 7 USBDP, 8 USBDM, 9 GND, 10 SI/WUA, 11 TXLED#, 12 RXLED#, 13 SLEEPA#, 14 VCCIOA, 15 TXDENA, 16 RIA#, 17 DCDA#, 18 GND, 19 DSRA#, 20 DTRA#, 21 CTSA#, 22 RTSA#, 23 RXDA, 24 TXDA, 25 GND, 26 SI/WUB, 27 TXLEDB#, 28 RXLEDB#, 29 SLEEPB#, 30 TXDENB#, 31 VCCIOB, 32 RIB#, 33 DCDB#, 34 GND, 35 DRSB#, 36 DTRB#, 37 CTSB#, 38 RTSB#, 39 RXDB, 40 TXDB, 41 PWREN#, 42 VCC, 43 XTIN, 44 XTOUT, 45 AGND, 46 AVCC, 47 TEST, 48 EECS

## FUSE_6V_350mA_1206
designator F?, comment MF-NSMF035 350mA
Multifuse, SMD 1206, 350mA; Rated Voltage: 6 V; Aggiornato: NO; Costo: 0
footprint RESC3216
pins: 1, 2

## FUSE_32V_7A_1206
designator F?, comment 7A SMD SUSE
Fuse; Aggiornato: NO; Costo: 0
footprint 1206_UP
pins: 1, 2

## FUSE_250V_5A_T5A
designator F?, comment FUSE 250V 5A
FUSE 250V 5A FUSE T5A TIME DELAY; Costo: 0; Aggiornato: NO
pins: 1, 2

## FUSE_250V_6.3A
designator F?, comment FUSE 250V 6.3A
Costo: 0; Aggiornato: NO
pins: 1, 2

## FUSE_250V_6.3A_T_BEL_FUSE_0697A6300-01
designator F?, comment FUSE 250V 6.3A
FUSE 250Vac 6.3A Time Delay BEL FUSE 0697A6300-01; Costo: 0,26; Aggiornato: S; ContoLavoro: 0
footprint BEL_FUSE_0697A6300-01 (Footprint not found)
pins: 1, 2

## FUSE_250V_630mA_Fast_LITTELFUSE_TR5_1
designator F?, comment FUSE 250V 0.63A
FUSE 250V 0.63A Fast LITTELFUSE TR5; Costo: 0,33; Hpcode: FUSF063A00TE5 da verificare se esiste; Aggiornato: N; ContoLavoro: 0
footprint MICROFUSE 8.5 p5
pins: 1, 2

## FZT649
designator Q?
ZETEX FZT649; Aggiornato: SI; Costo: 0,144; Detail: (Rs per >1000pz); ContoLavoro: 0
simulation model 2N3904 (NPN)
signal-integrity model 2N3904
footprint SOT223
pins: 1 B, 2 C, 3 E, 4 C2

## FZT749
designator Q?
ZETEX FZT749; Aggiornato: SI; Costo: 0,162; Detail: (Rs per >1000pz); ContoLavoro: 0
footprint SOT223
pins: 1 B, 2 C, 3 E, 4 C2
2 alternate drawings of the same symbol

## HEATSINK_BRD191K
designator H?  (mechanical)
Hpcode: MCP115A03ABK; Detail: 1,30€ Costo standard esolver 2018; Aggiornato: S; Costo: 1,30; ContoLavoro: 1
footprint HEATSINK_BRD191K 50x40mm (Footprint not found)

## HEATSINK_BRD210K
designator H?  (mechanical)
Hpcode: MCP123A03; Aggiornato: NO; Costo: 0; ContoLavoro: 1
footprint HEATSINK_BRD210K_MCP123A03_01 (Footprint not found)

## HEATSINK_TRE_S
designator H?, comment HEATSINK_TRE_S_PRO1273
Aggiornato: NO; Costo: 0
footprint HEATSINK_TRES_1273_80mm

## HOLE_1mm_METAL
designator HOLE?  (no BOM)
Aggiornato: NO; Costo: 0
footprint HOLE 1MM
pins: 1 A

## HOLE_2.5mm_METAL
designator HOLE?, comment METAL HOLE
Aggiornato: NO; Costo: 0
footprint HOLE 2.5MM
pins: 1 A

## HOLE_2mm
designator HOLE?, comment HOLE_2mm_non_met  (no BOM)
Aggiornato: NO; Costo: 0
footprint 2MM_HOLE
pins: 1 A

## Hole_3.2_per_essentra_MSCBSM-M3-2-19
designator HOLE?, comment Hole_3.2_per_essentra_MSCBSM-M3-2-19+3D  (no BOM)
Aggiornato: NO; Costo: 0
footprint Hole_3.2_per_essentra_MSCBSM-M3-2-19+3D
footprint Hole_3.2_per_essentra_MSCBSM-M3-2-19
footprint Hole_3.2_per_essentra_MSCBSM-M3-2-19+3D_METALLIZATO
footprint Hole_3.2_per_essentra_MSCBSM-M3-2-19_metallizzato
pins: 1 A

## HOLE_3.7
designator HOLE?, comment HOLE_3.7_non_met  (no BOM)
Aggiornato: NO; Costo: 0
footprint HOLE_3.7_non_met
pins: 1 A

## HOLE_4mm_METAL
designator HOLE?  (no BOM)
Costo: 0; Aggiornato: NO
footprint MTHOLE 4MM
pins: 1 A

## HOLE_6
designator HOLE?, comment HOLE_6_non_met  (no BOM)
Aggiornato: NO; Costo: 0
footprint HOLE_6_non_met
pins: 1 A

## HOLE_9mm
designator HOLE?, comment 9mm Hole  (no BOM)
Aggiornato: NO; Costo: 0
footprint HOLE_9MM
pins: 1 A

## IC-AT24C64
designator U?, comment AT24C64AN Serial EEPROM
AT24C64AN Two-Wire Serial EEPROM 2.7-5.5V SOIC-8 (JEDEC); Bit Width: 1 Bits; Supply Voltage: 2.7 to 5.5 V; Aggiornato: NO; Costo: 0
footprint SOIC8-150-BODY
pins: 1 A0, 2 A1, 3 A2, 4 GND, 5 SDA, 6 SCL, 7 WP, 8 VCC

## IC-CC2420RTC
designator U?, comment CC2420RTC ZigBee Transceiver QFP48
CC2420RTC, 2.45GHz IEEE 802.15.4 (Zigbee) RF Transceiver QFP48; Aggiornato: NO; Costo: 0
footprint SQFP50P700X700-48
pins: 0A, 0B, 0C, 0D, 0E UNDER_CHIP, 0F, 0G, 0H, 0J, 1 VCO_GUARD, 2 AVDD_VCO, 3 AVDD_PRE, 4 AVDD_RF1, 5 GND, 6 RF_P (io), 7 TXRX_SWITCH, 8 RF_N (io), 9 GND, 10 AVDD_SW, 11 NC, 12 NC, 13 NC, 14 AVDD_RF2, 15 AVDD_IF2, 16 NC, 17 AVDD_ADC, 18 DVDD_ADC, 19 DGND_GUARD, 20 DGUARD, 21 RESET_N (in), 22 DGND, 23 DSUB_PADS, 24 DSUB_CORE, 25 DVDD_3V3, 26 DVDD_1V8, 27 SFD (out), 28 CCA (out), 29 FIFOP (out), 30 FIFO (io), 31 CS_N (in), 32 SCLK (in), 33 SI (in), 34 SO (out), 35 DVDD_RAM, 36 NC, 37 AVDD_XOSC16, 38 XOSC16_Q2, 39 XOSC16_Q1, 40 NC, 41 VREG_EN (in), 42 VREG_OUT, 43 VREG_IN, 44 AVDD_IF1, 45 R_BIAS (out), 46 ATEST2 (io), 47 ATEST1 (io), 48 AVDD_CHP


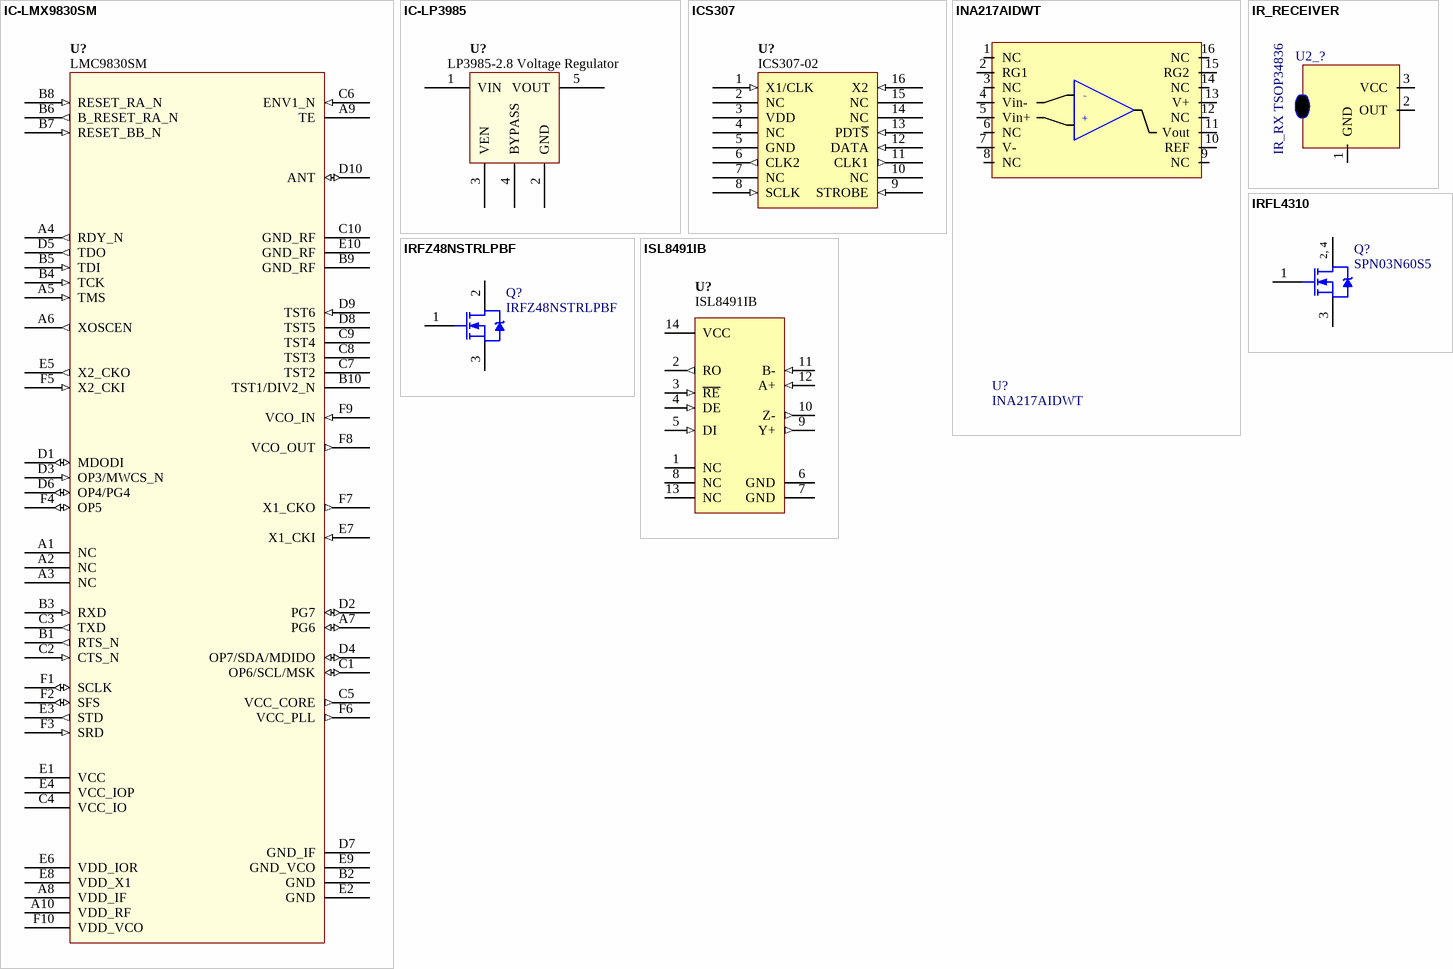
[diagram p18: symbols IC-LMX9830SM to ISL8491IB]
## IC-LMX9830SM
designator U?, comment LMC9830SM
LMC9830SM, 2.45GHz Bluetooth Serial Port Module, BGA60; Aggiornato: NO; Costo: 0
footprint BGA80P9X6-60
pins: A1 NC, A2 NC, A3 NC, A4 RDY_N (out), A5 TMS (in), A6 XOSCEN (out), A7 PG6 (io), A8 VDD_IF, A9 TE, A10 VDD_RF, B1 RTS_N (out), B2 GND (power), B3 RXD (in), B4 TCK (in), B5 TDI (in), B6 B_RESET_RA_N (out), B7 RESET_BB_N (in), B8 RESET_RA_N (in), B9 GND_RF (power), B10 TST1/DIV2_N, C1 OP6/SCL/MSK (io), C2 CTS_N (in), C3 TXD (out), C4 VCC_IO (power), C5 VCC_CORE (out), C6 ENV1_N (in), C7 TST2, C8 TST3, C9 TST4, C10 GND_RF (power), D1 MDODI (io), D2 PG7 (io), D3 OP3/MWCS_N (in), D4 OP7/SDA/MDIDO (io), D5 TDO (out), D6 OP4/PG4 (io), D7 GND_IF (power), D8 TST5, D9 TST6 (in), D10 ANT (io), E1 VCC (power), E2 GND (power), E3 STD (out), E4 VCC_IOP (power), E5 X2_CKO (out), E6 VDD_IOR, E7 X1_CKI (in), E8 VDD_X1, E9 GND_VCO (power), E10 GND_RF (power), F1 SCLK (io), F2 SFS (io), F3 SRD (in), F4 OP5 (io), F5 X2_CKI (in), F6 VCC_PLL (out), F7 X1_CKO (out), F8 VCO_OUT (out), F9 VCO_IN (in), F10 VDD_VCO

## IC-LP3985
designator U?, comment LP3985-2.8 Voltage Regulator
LP3985IM5-2.8, 2V8 Voltage Regulator, Low-Noise Ultra Low-Dropout, 150mA, SOT-23-5; Max Input Voltage: 6 V; Max Output Voltage: 2.803 V; Min Input Voltage: 3.3 V; Min Output Voltage: 2.797 V; Supply Voltage: mV; Aggiornato: NO; Costo: 0
footprint SOT-23-5
pins: 1 VIN, 2 GND, 3 VEN, 4 BYPASS, 5 VOUT

## ICS307
designator U?, comment ICS307-02
ICS307-02, SPI Programmable Clock Generator; Aggiornato: NO; Costo: 0
footprint SOIC127P600-16
pins: 1 X1/CLK (in) "Reference Word Devider Input", 2 NC "Reference Word Devider Input", 3 VDD (power) "Positive Supply, 3V3 or 5V", 4 NC, 5 GND (power), 6 CLK2 (out) "Fixed Clock Ref", 7 NC "Crystal connection", 8 SCLK (in) "Serial Programming Clock", 9 STROBE (in) "Serial Programming Strobe", 10 NC, 11 CLK1 (out) "Variable Clock Output", 12 DATA (in) "Serial Programming Data", 13 PDT~{S} (in) "Low = TriState CLK1 and CLK2 and Power Down", 14 NC, 15 NC, 16 X2 (in) "Crystal Terminal"

## INA217AIDWT
designator U?
Detail: 5,17€ RS >3pz; Aggiornato: s; Costo: 5,17; ContoLavoro: 1
footprint SOIC DW 16
pins: 1 NC, 2 RG1, 3 NC, 4 Vin-, 5 Vin+, 6 NC, 7 V-, 8 NC, 9 NC, 10 REF, 11 Vout, 12 NC, 13 V+, 14 NC, 15 RG2, 16 NC

## IR_RECEIVER
designator U2_?, comment IR_RX TSOP34836
Aggiornato: NO; Costo: 0
footprint IR_RECEIVER_3PIN
pins: 1 GND, 2 OUT, 3 VCC

## IRFL4310
designator Q?, comment SPN03N60S5
HEXFET Power MOSFET; Aggiornato: NO; Costo: 0
footprint SOT-223 (SOT-223/SC-73; 4 Leads; Body 6.7 x 7.3 mm, inc. leads (LxW max))
footprint SOT223
pins: 1 G, 2 D, 3 S, 4 D

## IRFZ48NSTRLPBF
designator Q?
HEXFET MOSFET 55V 64A 14mOhm Codice Mouser: 942-IRFZ48NSTRLPBF; Detail: 1,09 € PER ORDINI MULTIPLI DI 800 PEZZI; Aggiornato: SI; Costo: 1,09 €; ContoLavoro: 0
footprint D2PAK3
pins: 1 G, 2 D, 3 S

## ISL8491IB
designator U?
ISL8491IB, RS-485/RS-422 Transceivers; Aggiornato: NO; Costo: 0
footprint SOIC127P600-14N
pins: 1 NC, 2 RO (out), 3 ~{RE} (in), 4 DE (in), 5 DI (in), 6 GND (power), 7 GND (power), 8 NC, 9 Y+ (out), 10 Z- (out), 11 B- (in), 12 A+ (in), 13 NC, 14 VCC (power)


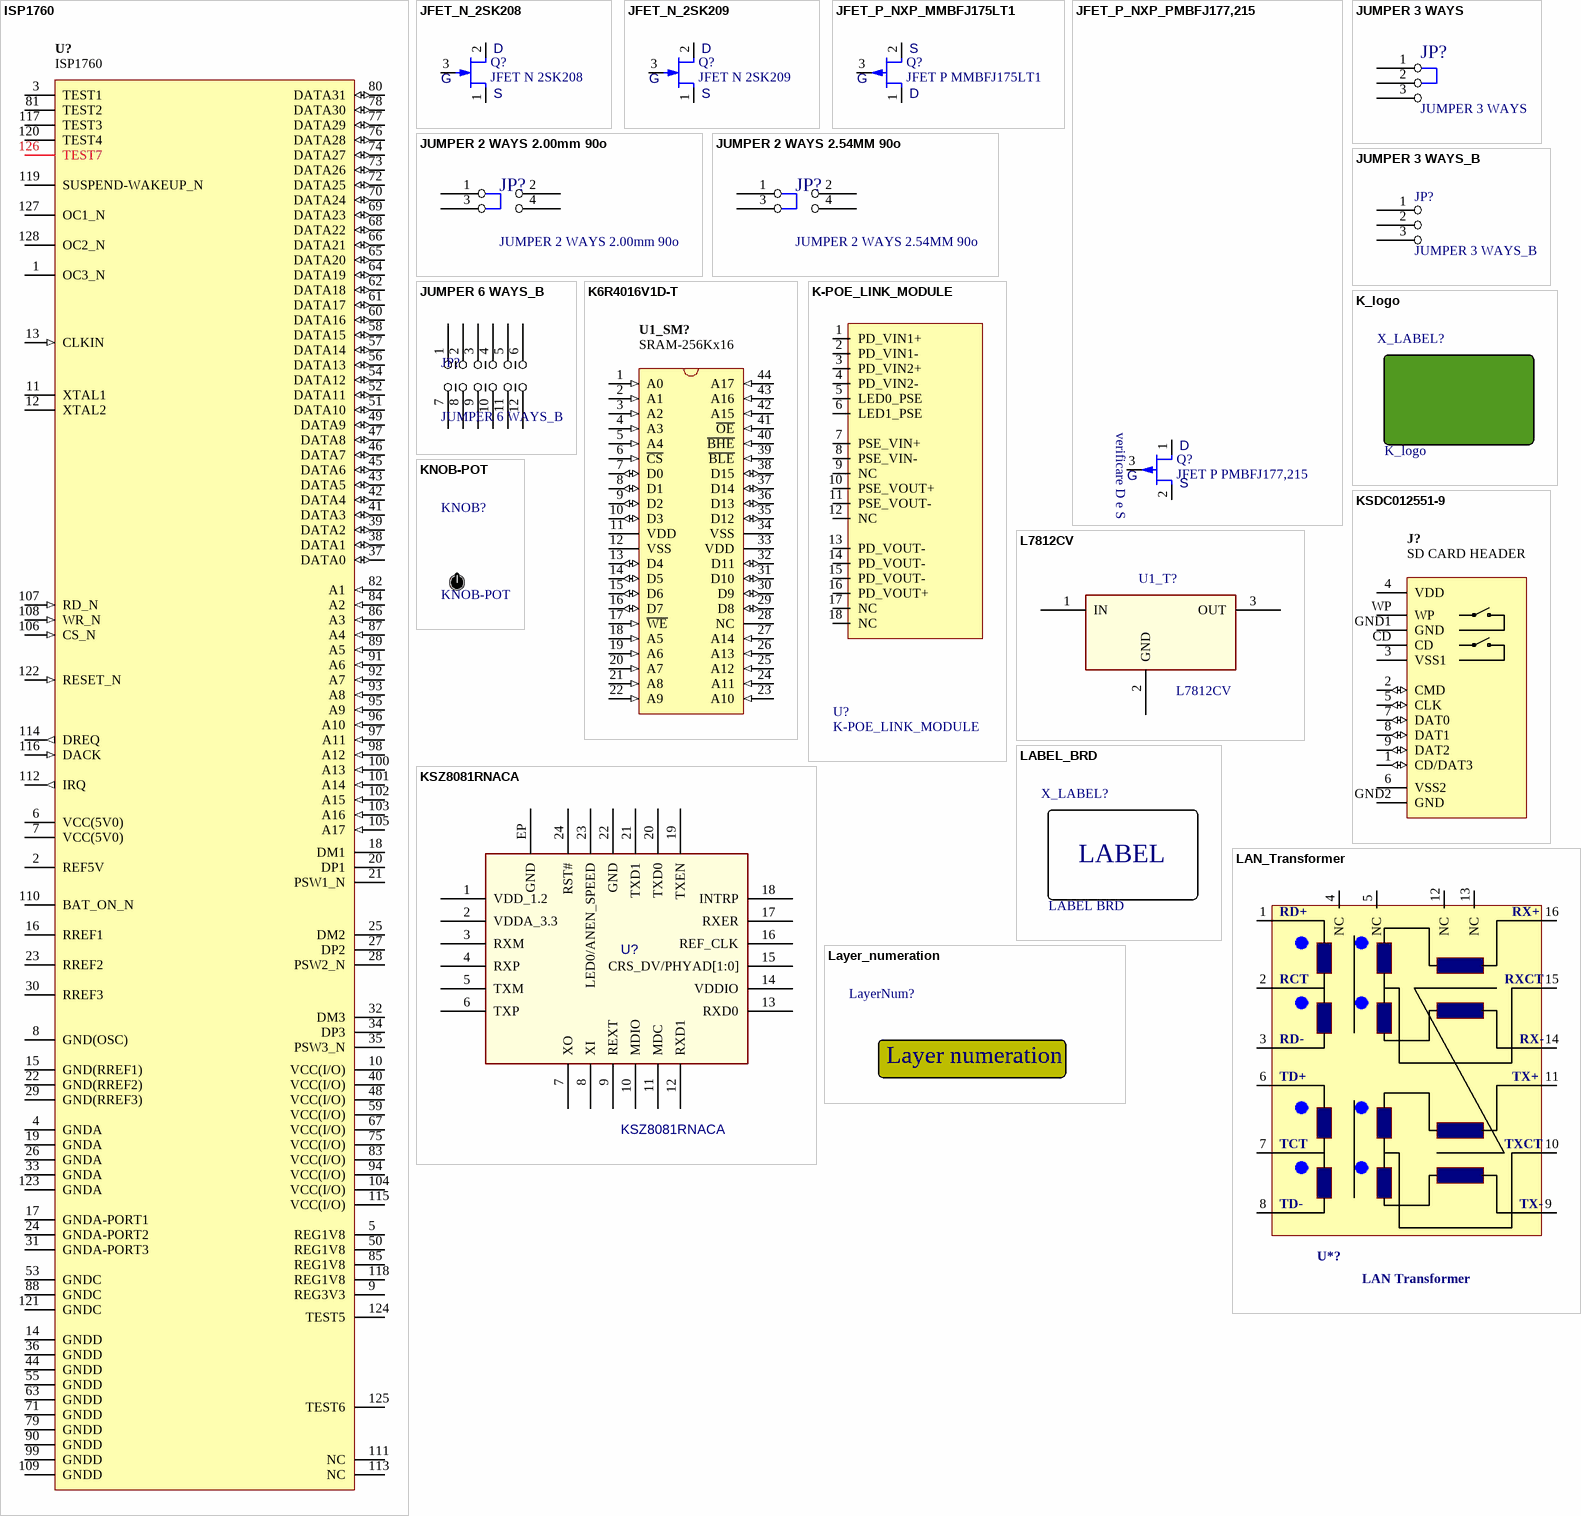
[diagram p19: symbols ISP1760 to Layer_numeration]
## ISP1760
designator U?
Hi-Speed Universal Serial Bus host controller; Aggiornato: NO; Costo: 0
footprint SOT425-1
pins: 1 OC3_N "wake-up input; when not in use, connect this pin to ground through a 10 k resistor; input pad; TTL; 5 V tolerant", 2 REF5V "wake-up input; when not in use, connect this pin to ground through a 10 k resistor; input pad; TTL; 5 V tolerant", 3 TEST1 "wake-up input; when not in use, connect this pin to ground through a 10 k resistor; input pad; TTL; 5 V tolerant", 4 GNDA (power) "digital ground", 5 REG1V8 (power) "supply voltage (3.3 V ?0.3 V); this pin supplies the internal voltage regulator and the analog circuit", 6 VCC(5V0) (power) "supply voltage; used to supply voltage to the I/O pads", 7 VCC(5V0) (power) "supply voltage; used to supply voltage to the I/O pads", 8 GND(OSC) (power) "digital ground", 9 REG3V3 (power) "supply voltage (3.3 V ?0.3 V); this pin supplies the internal voltage regulator and the analog circuit", 10 VCC(I/O) (power) "supply voltage; used to supply voltage to the I/O pads", 11 XTAL1 "wake-up input; when not in use, connect this pin to ground through a 10 k resistor; input pad; TTL; 5 V tolerant", 12 XTAL2 "wake-up input; when not in use, connect this pin to ground through a 10 k resistor; input pad; TTL; 5 V tolerant", 13 CLKIN (in) "DMA write strobe input (programmable polarity); when not in use, connect this pin to VCC(I/O) through a 10 k resistor; TTL; 5 V tolerant", 14 GNDD (power) "digital ground", 15 GND(RREF1) (power) "digital ground", 16 RREF1 "wake-up input; when not in use, connect this pin to ground through a 10 k resistor; input pad; TTL; 5 V tolerant", 17 GNDA-PORT1 (power) "digital ground", 18 DM1, 19 GNDA (power) "digital ground", 20 DP1, 21 PSW1_N "wake-up input; when not in use, connect this pin to ground through a 10 k resistor; input pad; TTL; 5 V tolerant", 22 GND(RREF2) (power) "digital ground", 23 RREF2 "wake-up input; when not in use, connect this pin to ground through a 10 k resistor; input pad; TTL; 5 V tolerant", 24 GNDA-PORT2 (power) "digital ground", 25 DM2, 26 GNDA (power) "digital ground", 27 DP2, 28 PSW2_N "wake-up input; when not in use, connect this pin to ground through a 10 k resistor; input pad; TTL; 5 V tolerant", 29 GND(RREF3) (power) "digital ground", 30 RREF3 "wake-up input; when not in use, connect this pin to ground through a 10 k resistor; input pad; TTL; 5 V tolerant", 31 GNDA-PORT3 (power) "digital ground", 32 DM3, 33 GNDA (power) "digital ground", 34 DP3, 35 PSW3_N "wake-up input; when not in use, connect this pin to ground through a 10 k resistor; input pad; TTL; 5 V tolerant", 36 GNDD (power) "digital ground", 37 DATA0 (io), 38 DATA1 (io), 39 DATA2 (io), 40 VCC(I/O) (power) "regulator output voltage (1.8 V ?0.15 V); decouple this pin using a 0.1 mF capacitor", 41 DATA3 (io), 42 DATA4 (io), 43 DATA5 (io), 44 GNDD (power) "digital ground", 45 DATA6 (io), 46 DATA7 (io), 47 DATA8 (io), 48 VCC(I/O) (power) "regulator output voltage (1.8 V ?0.15 V); decouple this pin using 4.7 mF and 0.1 mF capacitors", 49 DATA9 (io), 50 REG1V8 (power) "supply voltage (3.3 V ?0.3 V); this pin supplies the internal voltage regulator and the analog circuit", 51 DATA10 (io), 52 DATA11 (io), 53 GNDC (power) "digital ground", 54 DATA12 (io), 55 GNDD (power) "digital ground", 56 DATA13 (io), 57 DATA14 (io), 58 DATA15 (io), 59 VCC(I/O) (power) "supply voltage (3.3 V ?0.3 V); this pin supplies the internal voltage regulator and the analog circuit", 60 DATA16 (io), 61 DATA17 (io), 62 DATA18 (io), 63 GNDD (power) "digital ground", 64 DATA19 (io), 65 DATA20 (io), 66 DATA21 (io), 67 VCC(I/O) (power) "supply voltage (3.3 V ?0.3 V); this pin supplies the internal voltage regulator and the analog circuit", 68 DATA22 (io), 69 DATA23 (io), 70 DATA24 (io), 71 GNDD (power) "digital ground", 72 DATA25 (io), 73 DATA26 (io), 74 DATA27 (io), 75 VCC(I/O) (power) "supply voltage; used to supply voltage to the I/O pads", 76 DATA28 (io), 77 DATA29 (io), 78 DATA30 (io), 79 GNDD (power) "digital ground", 80 DATA31 (io), 81 TEST2 "wake-up input; when not in use, connect this pin to ground through a 10 k resistor; input pad; TTL; 5 V tolerant", 82 A1 (in) "bit 0 of the address bus; input pad; TTL; 5 V tolerant", 83 VCC(I/O) (power) "supply voltage; used to supply voltage to the I/O pads", 84 A2 (in) "bit 1 of the address bus; input pad; TTL; 5 V tolerant", 85 REG1V8 (power) "regulator output voltage (1.8 V ?0.15 V); decouple this pin using 4.7 mF and 0.1 mF capacitors", 86 A3 (in) "bit 2 of the address bus; input pad; TTL; 5 V tolerant", 87 A4 (in) "bit 3 of the address bus; input pad; TTL; 5 V tolerant", 88 GNDC (power) "digital ground", 89 A5 (in) "bit 4 of the address bus; input pad; TTL; 5 V tolerant", 90 GNDD (power) "digital ground", 91 A6 (in) "bit 5 of the address bus; input pad; TTL; 5 V tolerant", 92 A7 (in) "bit 6 of the address bus; input pad; TTL; 5 V tolerant", 93 A8 (in) "bit 7 of the address bus; input pad; TTL; 5 V tolerant", 94 VCC(I/O) (power) "supply voltage; used to supply voltage to the I/O pads", 95 A9 (in) "bit 0 of the address bus; input pad; TTL; 5 V tolerant", 96 A10 (in) "bit 1 of the address bus; input pad; TTL; 5 V tolerant", 97 A11 (in) "bit 2 of the address bus; input pad; TTL; 5 V tolerant", 98 A12 (in) "bit 3 of the address bus; input pad; TTL; 5 V tolerant", 99 GNDD (power) "digital ground", 100 A13 (in) "bit 4 of the address bus; input pad; TTL; 5 V tolerant", 101 A14 (in) "bit 5 of the address bus; input pad; TTL; 5 V tolerant", 102 A15 (in) "bit 6 of the address bus; input pad; TTL; 5 V tolerant", 103 A16 (in) "bit 7 of the address bus; input pad; TTL; 5 V tolerant", 104 VCC(I/O) (power) "regulator output voltage (1.8 V ?0.15 V); decouple this pin using a 0.1 mF capacitor", 105 A17 (in) "bit 5 of the address bus; input pad; TTL; 5 V tolerant", 106 CS_N (in) "DMA write strobe input (programmable polarity); when not in use, connect this pin to VCC(I/O) through a 10 k resistor; TTL; 5 V tolerant", 107 RD_N (in) "DMA write strobe input (programmable polarity); when not in use, connect this pin to VCC(I/O) through a 10 k resistor; TTL; 5 V tolerant", 108 WR_N (in) "DMA write strobe input (programmable polarity); when not in use, connect this pin to VCC(I/O) through a 10 k resistor; TTL; 5 V tolerant", 109 GNDD (power) "digital ground", 110 BAT_ON_N "wake-up input; when not in use, connect this pin to ground through a 10 k resistor; input pad; TTL; 5 V tolerant", 111 NC "wake-up input; when not in use, connect this pin to ground through a 10 k resistor; input pad; TTL; 5 V tolerant", 112 IRQ (out) "DMA request (programmable polarity) output; when not in use, connect this pin to ground through a 10 k resistor", 113 NC "wake-up input; when not in use, connect this pin to ground through a 10 k resistor; input pad; TTL; 5 V tolerant", 114 DREQ (out) "DMA request (programmable polarity) output; when not in use, connect this pin to ground through a 10 k resistor", 115 VCC(I/O) (power) "regulator output voltage (1.8 V ?0.15 V); decouple this pin using 4.7 mF and 0.1 mF capacitors", 116 DACK (in) "DMA write strobe input (programmable polarity); when not in use, connect this pin to VCC(I/O) through a 10 k resistor; TTL; 5 V tolerant", 117 TEST3 "wake-up input; when not in use, connect this pin to ground through a 10 k resistor; input pad; TTL; 5 V tolerant", 118 REG1V8 (power) "supply voltage (3.3 V ?0.3 V); this pin supplies the internal voltage regulator and the analog circuit", 119 SUSPEND-WAKEUP_N "wake-up input; when not in use, connect this pin to ground through a 10 k resistor; input pad; TTL; 5 V tolerant", 120 TEST4 "wake-up input; when not in use, connect this pin to ground through a 10 k resistor; input pad; TTL; 5 V tolerant", 121 GNDC (power) "digital ground", 122 RESET_N (in) "DMA write strobe input (programmable polarity); when not in use, connect this pin to VCC(I/O) through a 10 k resistor; TTL; 5 V tolerant", 123 GNDA (power) "digital ground", 124 TEST5 "wake-up input; when not in use, connect this pin to ground through a 10 k resistor; input pad; TTL; 5 V tolerant", 125 TEST6 "wake-up input; when not in use, connect this pin to ground through a 10 k resistor; input pad; TTL; 5 V tolerant", 126 TEST7 "wake-up input; when not in use, connect this pin to ground through a 10 k resistor; input pad; TTL; 5 V tolerant", 127 OC1_N "wake-up input; when not in use, connect this pin to ground through a 10 k resistor; input pad; TTL; 5 V tolerant", 128 OC2_N "wake-up input; when not in use, connect this pin to ground through a 10 k resistor; input pad; TTL; 5 V tolerant"

## JFET_N_2SK208
designator Q?, comment JFET N 2SK208
JFET N channel 2SK208; Costo: 0,32; ContoLavoro: 0; Aggiornato: s
footprint SOT-23_UP
footprint SOT-23_MINIMAL
pins: 1 SOURCE, 2 DRAIN, 3 GATE

## JFET_N_2SK209
designator Q?, comment JFET N 2SK209
JFET N channel 2SK209; Costo: 0,34; ContoLavoro: 0; Aggiornato: s
footprint SOT-23_UP
footprint SOT-23_MINIMAL
pins: 1 SOURCE, 2 DRAIN, 3 GATE

## JFET_P_NXP_MMBFJ175LT1
designator Q?, comment JFET P MMBFJ175LT1
JFET p channel NXP MMBFJ175LT1; Costo: 0,15; ContoLavoro: 0
footprint SOT-23_UP
footprint SOT-23_MINIMAL (SOT-23_MINIMAL Corretto e verificato)
pins: 1 DRAIN, 2 SOURCE, 3 GATE

## JFET_P_NXP_PMBFJ177,215
designator Q?, comment JFET P PMBFJ177,215
JFET p channel NXP PMBFJ177,215; Costo: 0,148; ContoLavoro: 0
footprint SOT-23_UP
footprint SOT-23_MINIMAL (SOT-23_MINIMAL Corretto e verificato)
pins: 1 DRAIN, 2 SOURCE, 3 GATE

## JUMPER 2 WAYS 2.00mm 90o
designator JP?
Detail: 1/12 0,43€ (RS PER >250pz) DEL CONNETTORE DA 36 PIN; Aggiornato: SI; Costo: 0,036 da verificare; ContoLavoro: 0
footprint 2X2X2mm_PIN STRIPES 90o
pins: 1, 2, 3, 4

## JUMPER 2 WAYS 2.54MM 90o
designator JP?
Detail: 1/12 0,43€ (RS PER >250pz) DEL CONNETTORE DA 36 PIN; Aggiornato: SI; Costo: 0,036 da verificare; ContoLavoro: 0
footprint 2X2X2.54_PIN STRIPES 90o
pins: 1, 2, 3, 4

## JUMPER 3 WAYS
designator JP?
Detail: 1/12 0,43€ (RS PER >250pz) DEL CONNETTORE DA 36 PIN; Aggiornato: SI; Costo: 0,036; ContoLavoro: 0
footprint JUMPER 2.54\3
pins: 1, 2, 3

## JUMPER 3 WAYS_B
designator JP?
Costo: 0; Aggiornato: NO
footprint JUMPER 2.54\3
pins: 1, 2, 3

## JUMPER 6 WAYS_B
designator JP?
Costo: 0; Aggiornato: NO
footprint JUMPER 12X2.54
pins: 1, 2, 3, 4, 5, 6, 7, 8, 9, 10, 11, 12

## K6R4016V1D-T
designator U1_SM?, comment SRAM-256Kx16
K6R4016V1D-TC10T, 256K x 16-Bit SRAM, TSOP44; Bit Width: 16 Bits; Supply Voltage: 3.3 V; Aggiornato: NO; Costo: 0
footprint TSOP80P1176-44
pins: 1 A0 (in), 2 A1 (in), 3 A2 (in), 4 A3 (in), 5 A4 (in), 6 ~{CS} (in), 7 D0 (io), 8 D1 (io), 9 D2 (io), 10 D3 (io), 11 VDD (power), 12 VSS (power), 13 D4 (io), 14 D5 (io), 15 D6 (io), 16 D7 (io), 17 ~{WE} (in), 18 A5 (in), 19 A6 (in), 20 A7 (in), 21 A8 (in), 22 A9 (in), 23 A10 (in), 24 A11 (in), 25 A12 (in), 26 A13 (in), 27 A14 (in), 28 NC, 29 D8 (io), 30 D9 (io), 31 D10 (io), 32 D11 (io), 33 VDD (power), 34 VSS (power), 35 D12 (io), 36 D13 (io), 37 D14 (io), 38 D15 (io), 39 ~{BLE} (in), 40 ~{BHE} (in), 41 ~{OE} (in), 42 A15 (in), 43 A16 (in), 44 A17 (in)
1 alternate drawing of the same symbol

## K-POE_LINK_MODULE
designator U?
Aggiornato: n; Costo: 30; ContoLavoro: 0
footprint K-POE_LINK_MODULE (POE-LINK-beta)
footprint K-POE_COMPATIBILE_SILVERTEL (POE-LINK-beta)
pins: 1 PD_VIN1+, 2 PD_VIN1-, 3 PD_VIN2+, 4 PD_VIN2-, 5 LED0_PSE, 6 LED1_PSE, 7 PSE_VIN+, 8 PSE_VIN-, 9 NC, 10 PSE_VOUT+, 11 PSE_VOUT-, 12 NC, 13 PD_VOUT-, 14 PD_VOUT-, 15 PD_VOUT-, 16 PD_VOUT+, 17 NC, 18 NC

## K_logo
designator X_LABEL?
Costo: 0; Aggiornato: NO
footprint K_logo_1mmx1mm (LOGO K-array 1mmx1mm)
footprint K_logo_7mmx5mm (LOGO K-array 7mmx5mm)
footprint K_logo_10mmx7mm (LOGO K-array 10mmx7mm)
footprint K_logo_12mmx9mm (LOGO K-array 12mmx9mm)
footprint K_logo_25mmx18mm (LOGO K-array 25mmx18mm)

## KNOB-POT
designator KNOB?  (mechanical)
Manopola potenziometro KNOB-POT; Costo: 0,04; Aggiornato: s; ContoLavoro: 1
pins: 1 hidden
1 alternate drawing of the same symbol

## KSDC012551-9
designator J?, comment SD CARD HEADER
Secure Digital Card Socket; Max Current: mA; Aggiornato: NO; Costo: 0
footprint KSDC012551
pins: 1 CD/DAT3 (io), 2 CMD (io), 3 VSS1 (power), 4 VDD (power), 5 CLK (io), 6 VSS2 (power), 7 DAT0 (io), 8 DAT1 (io), 9 DAT2 (io), CD (oc), GND1 GND (power), GND2 GND (power), WP (oc)

## KSZ8081RNACA
designator U?
KSZ8081RNACA PHY; Aggiornato: NO; Costo: 1; ContoLavoro: 0
footprint QFN-25_KSZ8081RN
pins: 1 VDD_1.2, 2 VDDA_3.3, 3 RXM, 4 RXP, 5 TXM, 6 TXP, 7 XO, 8 XI, 9 REXT, 10 MDIO, 11 MDC, 12 RXD1, 13 RXD0, 14 VDDIO, 15 CRS_DV/PHYAD[1:0], 16 REF_CLK, 17 RXER, 18 INTRP, 19 TXEN, 20 TXD0, 21 TXD1, 22 GND, 23 LED0/ANEN_SPEED, 24 RST#, EP GND

## L7812CV
designator U1_T?
Costo: 0; DeviceFunction: Voltage Regulator; Aggiornato: NO
footprint TO220_123
pins: 1 IN, 2 GND, 3 OUT

## LABEL_BRD
designator X_LABEL?, comment LABEL BRD
Costo: 0,01; HPcode: Bxxxxxfannn; Aggiornato: s; ContoLavoro: 2
footprint LABEL 25X8
footprint LABEL_25X8+LayerNum+StackStripes_4layers
footprint LABEL_25X8+LayerNum_4layers
footprint LABEL 30X10
footprint LABEL 25X6
footprint LABEL 25X5

## LAN_Transformer
designator U*?, comment LAN Transformer
Aggiornato: NO; Costo: 0
footprint Model Name (Footprint not found)
pins: 1, 2, 3, 4 NC, 5 NC, 6, 7, 8, 9, 10, 11, 12 NC, 13 NC, 14, 15, 16

## Layer_numeration
designator LayerNum?  (value not drawn)  (no BOM)
Costo: 0; Aggiornato: s
footprint Layer_numeration_4layers


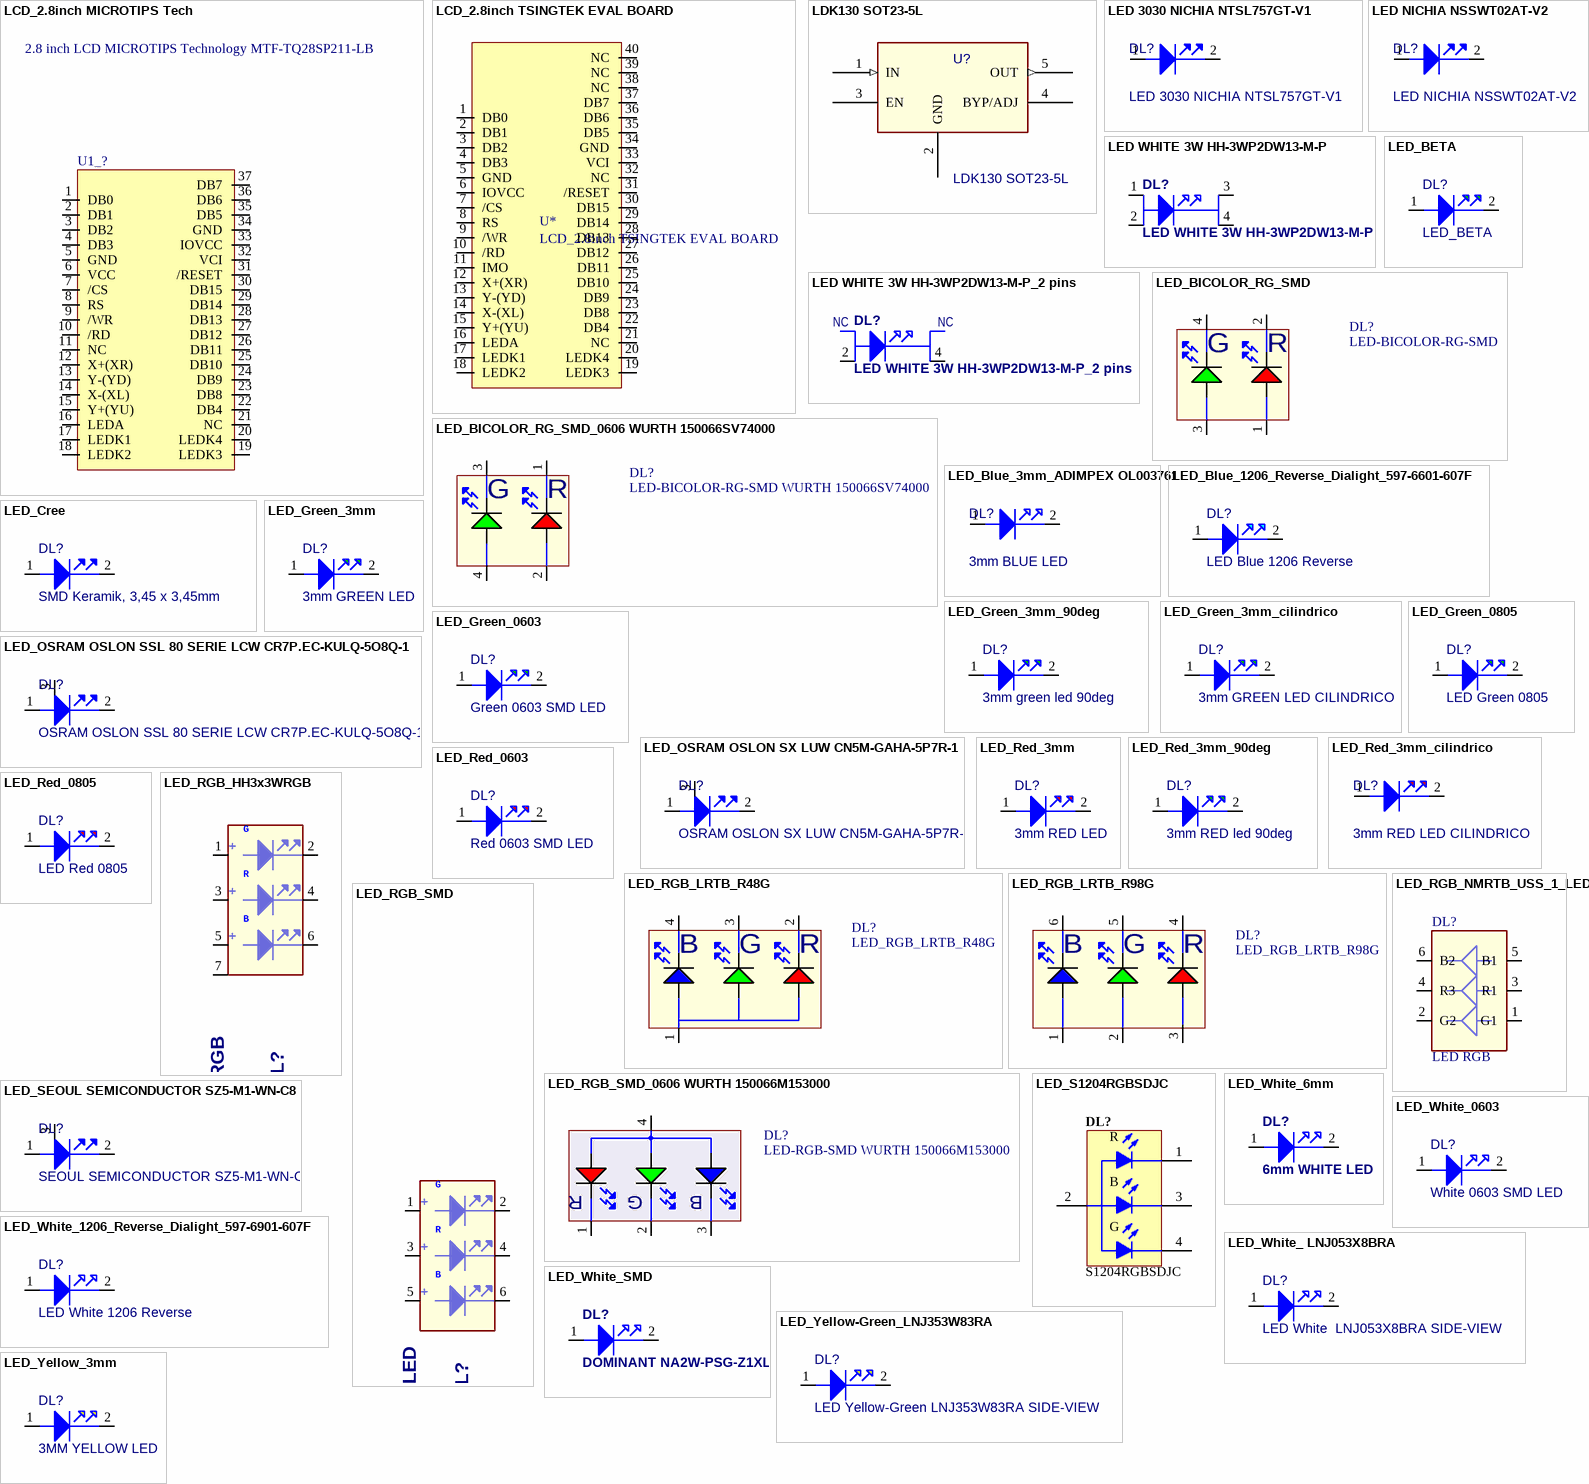
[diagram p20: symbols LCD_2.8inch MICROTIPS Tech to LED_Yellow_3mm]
## LCD_2.8inch MICROTIPS Tech
designator U1_?, comment 2.8 inch LCD MICROTIPS Technology MTF-TQ28SP211-LB
Aggiornato: NO; Costo: 0
footprint TFT MICROTIPS MTF-TQ28SP211-LB
pins: 1 DB0, 2 DB1, 3 DB2, 4 DB3, 5 GND, 6 VCC, 7 /CS, 8 RS, 9 /WR, 10 /RD, 11 NC, 12 X+(XR), 13 Y-(YD), 14 X-(XL), 15 Y+(YU), 16 LEDA, 17 LEDK1, 18 LEDK2, 19 LEDK3, 20 LEDK4, 21 NC, 22 DB4, 23 DB8, 24 DB9, 25 DB10, 26 DB11, 27 DB12, 28 DB13, 29 DB14, 30 DB15, 31 /RESET, 32 VCI, 33 IOVCC, 34 GND, 35 DB5, 36 DB6, 37 DB7

## LCD_2.8inch TSINGTEK EVAL BOARD
designator U*
Costo: 0
footprint Model Name (Footprint not found)
footprint HEADER PBD-40 2X20_FEMALE
pins: 1 DB0, 2 DB1, 3 DB2, 4 DB3, 5 GND, 6 IOVCC, 7 /CS, 8 RS, 9 /WR, 10 /RD, 11 IMO, 12 X+(XR), 13 Y-(YD), 14 X-(XL), 15 Y+(YU), 16 LEDA, 17 LEDK1, 18 LEDK2, 19 LEDK3, 20 LEDK4, 21 NC, 22 DB4, 23 DB8, 24 DB9, 25 DB10, 26 DB11, 27 DB12, 28 DB13, 29 DB14, 30 DB15, 31 /RESET, 32 NC, 33 VCI, 34 GND, 35 DB5, 36 DB6, 37 DB7, 38 NC, 39 NC, 40 NC

## LDK130 SOT23-5L
designator U?
Costo: 0; DeviceFunction: Voltage Regulator; Aggiornato: NO
footprint SOT-23 5PIN
pins: 1 IN (in), 2 GND, 3 EN, 4 BYP/ADJ, 5 OUT (out)

## LED 3030 NICHIA NTSL757GT-V1
designator DL?
NICHIA NTSL757GT-V1; Detail: Morandi Welt Electronic; Costo: 0,060; Aggiornato: si; ContoLavoro: 1
footprint LED_3030_NICHIA NTSL757GT-V1
pins: 1 ANODE, 2 CATHODE

## LED NICHIA NSSWT02AT-V2
designator DL?
Detail: Morandi Welt Electronic; Costo: 0,060; Aggiornato: si; ContoLavoro: 1
footprint LED_NICHIA_NSSWT02AT-V2 (Footprint led Nichia NSSWT02AT-V2)
pins: 1 ANODE, 2 CATHODE

## LED WHITE 3W HH-3WP2DW13-M-P
designator DL?
Costo: 0; Aggiornato: SI
footprint LED WHITE HH-3WP2DW13-M-P DISSIP
pins: 1 ANODE, 2 ANODE, 3 CATHODE, 4 CATHODE

## LED WHITE 3W HH-3WP2DW13-M-P_2 pins
designator DL?
Costo: 0; Aggiornato: SI
footprint LED WHITE HH-3WP2DW13-M-P DISSIP_2pins
pins: 2 ANODE, 4 CATHODE

## LED_BETA
designator DL?
SizeCode: 1206; Aggiornato: n; ContoLavoro: 0
footprint 1206_REVERSE_LED_Dialight
pins: 1 ANODE, 2 CATHODE

## LED_BICOLOR_RG_SMD
designator DL?, comment LED-BICOLOR-RG-SMD
KPTB-1615ESGC; Aggiornato: NO; ContoLavoro: 0
footprint LED_RG_1615 (LED BICOLOR R/G 1.6x1.5)
pins: 1 AN, 2 R_CAT, 3 G_CAT, 4 B_CAT

## LED_BICOLOR_RG_SMD_0606 WURTH 150066SV74000
designator DL?, comment LED-BICOLOR-RG-SMD WURTH 150066SV74000
Costo: 0,065; Aggiornato: S; ContoLavoro: 0
footprint LED_RG_0606 (LED BICOLOR R/G 1.6x1.6)
pins: 1 AN, 2 R_CAT, 3 G_CAT, 4 B_CAT

## LED_Blue_3mm_ADIMPEX OL003761
designator DL?, comment 3mm BLUE LED
LED 3mm BLUE LED; Costo: 0; SizeCode: Dia. 3mm; Aggiornato: s
footprint 3MM LED
footprint 3mm LED-DIST16mm (Footprint not found)
footprint 3mm LED-DIST22mm (Footprint not found)
pins: 1 ANODE, 2 CATHODE

## LED_Blue_1206_Reverse_Dialight_597-6601-607F
designator DL?, comment LED Blue 1206 Reverse
LED 597-6601-607F; Detail: € Farnell Pz>100; Costo: 0,34; SizeCode: 1206; Aggiornato: n; ContoLavoro: 0
footprint 1206_REVERSE_LED_Dialight_Blue (Footprint not found)
pins: 1 ANODE, 2 CATHODE

## LED_Cree
designator DL?, comment SMD Keramik, 3,45 x 3,45mm
LED Cree; Costo: 0; Aggiornato: NO
footprint Cree XP-G R4
pins: 1 ANODE, 2 CATHODE

## LED_Green_3mm
designator DL?, comment 3mm GREEN LED
LED Green 3mm; Costo: 0,10; SizeCode: Dia. 3mm; Aggiornato: s; ContoLavoro: 0
footprint 3MM LED
footprint 3mm LED-DIST16mm (Footprint not found)
footprint 3mm LED-DIST22mm (Footprint not found)
pins: 1 ANODE, 2 CATHODE

## LED_Green_3mm_90deg
designator DL?, comment 3mm green led 90deg
LED Green 3mm 90deg; Costo: 0,3; Aggiornato: s; ContoLavoro: 0
footprint 3MM GRN LED 90deg H5
pins: 1 ANODE, 2 CATHODE

## LED_Green_3mm_cilindrico
designator DL?, comment 3mm GREEN LED CILINDRICO
LED Green 3mm CILINDRICO; Hpcode: LED3GRE001; Costo: 0,10; SizeCode: Dia. 3mm; Aggiornato: s; ContoLavoro: 0
footprint 3MM CILINDRIC GRN LED-DIST14mm
footprint 3MM CILINDRIC GRN LED-DIST20mm
footprint 3MM CILINDRIC GRN LED
pins: 1 ANODE, 2 CATHODE

## LED_Green_0603
designator DL?, comment Green 0603 SMD LED
LED Green 0603; Costo: 0,08; SizeCode: 0603; Aggiornato: S; ContoLavoro: 0
footprint 0603N_LED
pins: 1 ANODE, 2 CATHODE

## LED_Green_0805
designator DL?, comment LED Green 0805
Costo: 0,06; Aggiornato: S; ContoLavoro: 0
footprint LED_0805
pins: 1 ANODE, 2 CATHODE

## LED_OSRAM OSLON SSL 80 SERIE LCW CR7P.EC-KULQ-5O8Q-1
designator DL?, comment OSRAM OSLON SSL 80 SERIE LCW CR7P.EC-KULQ-5O8Q-1
Costo: 0,702; Aggiornato: si; ContoLavoro: 1
footprint LED_OSRAM OSLON SSL 80
pins: 1 ANODE, 2 CATHODE, 3 HEATER

## LED_OSRAM OSLON SX LUW CN5M-GAHA-5P7R-1
designator DL?, comment OSRAM OSLON SX LUW CN5M-GAHA-5P7R-1
Costo: 0,875; Aggiornato: si; ContoLavoro: 0
footprint LED_OSRAM OSLON SX LUW CN5M
pins: 1 ANODE, 2 CATHODE, 3 HEATER

## LED_Red_3mm
designator DL?, comment 3mm RED LED
LED Red 3mm; Costo: 0,10; SizeCode: Dia. 3mm; Aggiornato: s; ContoLavoro: 0
footprint 3MM LED
footprint 3mm LED-DIST16mm (Footprint not found)
footprint 3mm LED-DIST22mm (Footprint not found)
pins: 1 ANODE, 2 CATHODE

## LED_Red_3mm_90deg
designator DL?, comment 3mm RED led 90deg
LED Red 3mm 90deg; Costo: 0,3; Aggiornato: s; ContoLavoro: 0
footprint 3MM RED LED 90deg H5 (Footprint not found)
pins: 1 ANODE, 2 CATHODE

## LED_Red_3mm_cilindrico
designator DL?, comment 3mm RED LED CILINDRICO
LED Red 3mm CILINDRICO; Costo: 0,10; SizeCode: Dia. 3mm; Aggiornato: s; ContoLavoro: 0
footprint 3MM CILINDRIC RED LED-DIST14mm
footprint 3MM CILINDRIC RED LED-DIST20mm
footprint 3MM CILINDRIC RED LED
pins: 1 ANODE, 2 CATHODE

## LED_Red_0603
designator DL?, comment Red 0603 SMD LED
LED Red 0603; Costo: 0; SizeCode: 0603; Aggiornato: NO
footprint 0603N_LED
pins: 1 ANODE, 2 CATHODE

## LED_Red_0805
designator DL?, comment LED Red 0805
Costo: 0,09; SizeCode: 0805; Aggiornato: S; ContoLavoro: 0
footprint LED_0805
pins: 1 ANODE, 2 CATHODE

## LED_RGB_HH3x3WRGB
designator DL?, comment RGB SMD LED HH3x3WRGB
LED RGB; Hpcode: LED0RGB001; Costo: 0,9; Aggiornato: NO; ContoLavoro: 0
footprint RGB_NMRTB_USS_1_LED
footprint RGB_NMRTB_USS_1_LED_new
footprint LED_HH3x3WRGB
pins: 1 ANODE1, 2 CATHODE1, 3 ANODE2, 4 CATHODE2, 5 ANODE3, 6 CATHODE3, 7 DIS

## LED_RGB_LRTB_R48G
designator DL?
LED RGB LRTB_R48G; Detail: € RS Pz>25; Costo: 0,148; Aggiornato: NO; ContoLavoro: 0
footprint LED_LRTB_R48G (Footprint not found)
pins: 1 AN, 2 R_CAT, 3 G_CAT, 4 B_CAT

## LED_RGB_LRTB_R98G
designator DL?
LED RGB LRTB_R98G; Detail: € RS Pz>50; Costo: 0,259; Aggiornato: NO; ContoLavoro: 0
footprint LED_LRTB_R98G
pins: 1 B_AN, 2 G_AN, 3 R_AN, 4 R_CAT, 5 G_CAT, 6 B_CAT

## LED_RGB_NMRTB_USS_1_LED
designator DL?, comment LED RGB
Costo: 0; Aggiornato: NO
footprint RGB_NMRTB_USS_1_LED
pins: 1 G1, 2 G2, 3 R1, 4 R3, 5 B1, 6 B2

## LED_RGB_SMD
designator DL?, comment DOMINANT NMRTB-WSG-AAB+ABD+X2Y-1 RGB LED
LED RGB SMD; Costo: 0; Aggiornato: NO
footprint RGB_NMRTB_USS_1_LED
footprint RGB_NMRTB_USS_1_LED_new
pins: 1 ANODE1, 2 CATHODE1, 3 ANODE2, 4 CATHODE2, 5 ANODE3, 6 CATHODE3

## LED_RGB_SMD_0606 WURTH 150066M153000
designator DL?, comment LED-RGB-SMD WURTH 150066M153000
Detail: 0,075€ 4000pcs offerta A20IT011754; Costo: 0,075; Aggiornato: S; ContoLavoro: 0
footprint LED_RGB_0606_WE_150066M153000 (LED RGB 1.6x1.6)
pins: 1 AN, 2 R_CAT, 3 G_CAT, 4 B_CAT

## LED_S1204RGBSDJC
designator DL?, comment S1204RGBSDJC
SASEN LED, RGB, SMD; Aggiornato: NO; Costo: 0
footprint S1204RGBSDJC
pins: 1 R, 2 A2, 3 B, 4 G

## LED_SEOUL SEMICONDUCTOR SZ5-M1-WN-C8
designator DL?, comment SEOUL SEMICONDUCTOR SZ5-M1-WN-C8
Detail: MATELICI ELNA; Aggiornato: si; ContoLavoro: 1
footprint LED_SEOUL SEMICONDUCTOR SZ5-M1-WN-C8 (Footprint not found)
pins: 1 ANODE, 2 CATHODE, 3 HEATER

## LED_White_6mm
designator DL?, comment 6mm WHITE LED
LED White 6mm; Hpcode: DIL6MMWHT; SizeCode: Dia. 6mm; Costo: 0; Aggiornato: NO
footprint 6MM LED (Footprint not found)
footprint 6mm_LED
pins: 1 ANODE, 2 CATHODE

## LED_White_0603
designator DL?, comment White 0603 SMD LED
LED White 0603; Detail: prezzo RS >50pz; Costo: 0,134; SizeCode: 0603; Aggiornato: n; ContoLavoro: 0
footprint 0603N_LED
pins: 1 ANODE, 2 CATHODE

## LED_White_1206_Reverse_Dialight_597-6901-607F
designator DL?, comment LED White 1206 Reverse
LED 597-6901-607F; Detail: € RS Pz>250; Costo: 0,25; SizeCode: 1206; Aggiornato: n; ContoLavoro: 0
footprint 1206_REVERSE_LED_Dialight_White (Footprint not found)
pins: 1 ANODE, 2 CATHODE

## LED_White_ LNJ053X8BRA
designator DL?, comment LED White  LNJ053X8BRA SIDE-VIEW
Detail: € Rs Pz>50; Costo: 0,274; SizeCode: KLTFSN2K5300; Aggiornato: s; ContoLavoro: 0
footprint LED_KLTFSN2K5300
simulation model DLED_GEN
pins: 1 ANODE, 2 CATHODE

## LED_White_SMD
designator DL?, comment DOMINANT NA2W-PSG-Z1XL
LED White SMD; Hpcode: LED0WHT001; Costo: 0; Aggiornato: NO
footprint 6MM LED (Footprint not found)
footprint DOMINANT_NA2WPSG
pins: 1 ANODE, 2 CATHODE

## LED_Yellow-Green_LNJ353W83RA
designator DL?, comment LED Yellow-Green LNJ353W83RA SIDE-VIEW
Detail: € Rs Pz>50; Costo: 0,235; SizeCode: KLTFSN2K5300; Aggiornato: s; ContoLavoro: 0
footprint LED_KLTFSN2K5300
simulation model DLED_GEN
pins: 1 ANODE, 2 CATHODE

## LED_Yellow_3mm
designator DL?, comment 3MM YELLOW LED
LED Yellow 3mm; Hpcode: DIL3MMYEL; SizeCode: Dia. 3mm; Costo: 0,10; Aggiornato: s; ContoLavoro: 0
footprint 3MM LED
simulation model DLED_GEN
footprint 3mm LED-DIST16mm (Footprint not found)
footprint 3mm LED-DIST22mm (Footprint not found)
pins: 1 ANODE, 2 CATHODE


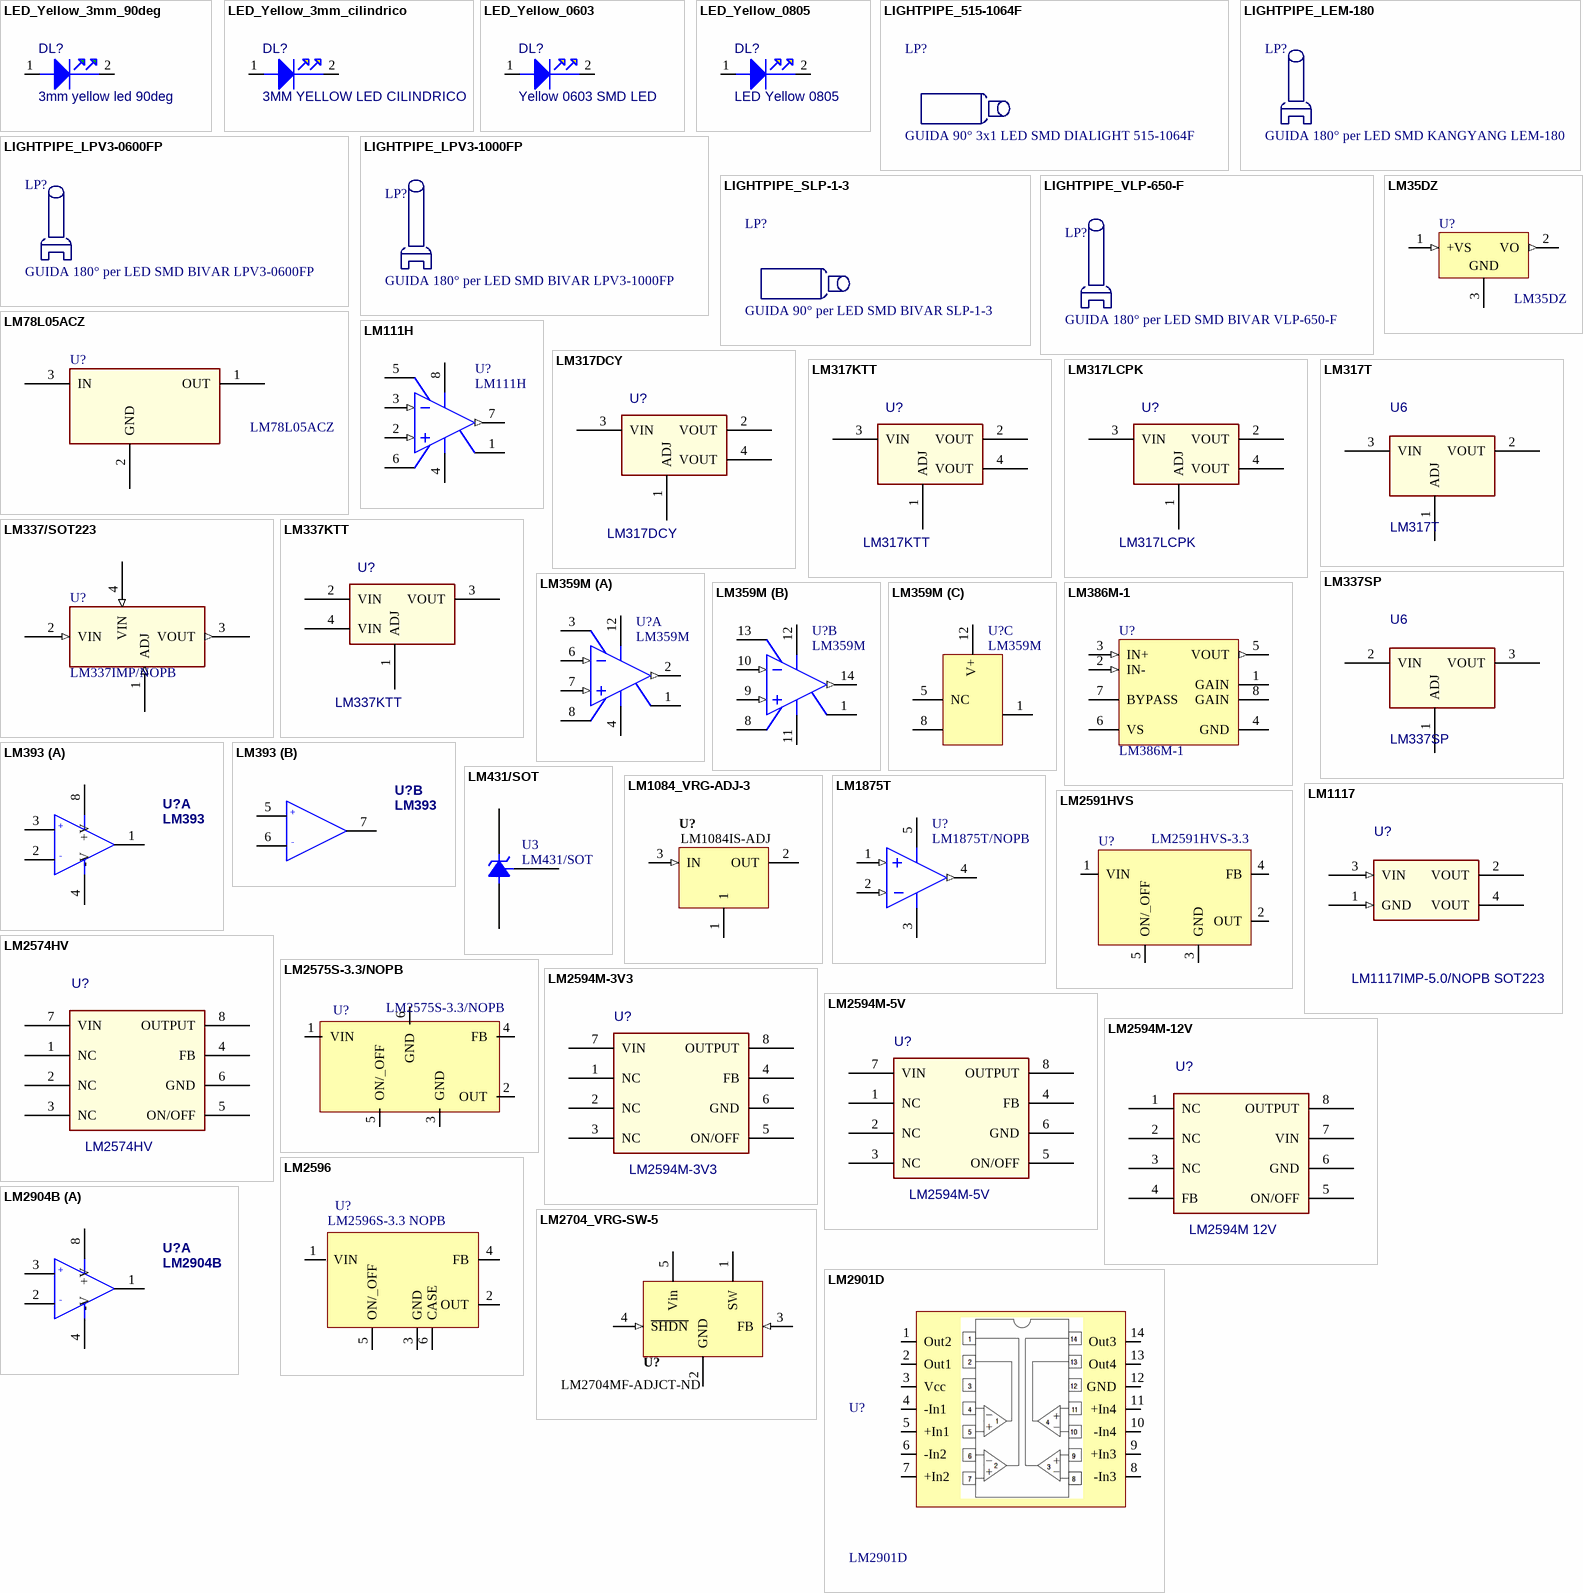
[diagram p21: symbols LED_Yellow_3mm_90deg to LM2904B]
## LED_Yellow_3mm_90deg
designator DL?, comment 3mm yellow led 90deg
LED Yellow 3mm 90deg; Costo: 1,8; Aggiornato: s; ContoLavoro: 0
footprint 3MM YEL LED 90deg H5 (Footprint not found)
simulation model DLED_GEN
pins: 1 ANODE, 2 CATHODE

## LED_Yellow_3mm_cilindrico
designator DL?, comment 3MM YELLOW LED CILINDRICO
LED Yellow 3mm CILINDRICO; SizeCode: Dia. 3mm; Costo: 0,10; Aggiornato: s; ContoLavoro: 0
footprint 3MM CILINDRIC YEL LED-DIST14mm
footprint 3MM CILINDRIC YEL LED-DIST20mm
footprint 3MM CILINDRIC YEL LED
simulation model DLED_GEN
pins: 1 ANODE, 2 CATHODE

## LED_Yellow_0603
designator DL?, comment Yellow 0603 SMD LED
LED Yellow 0603; Costo: 0; SizeCode: 0603; Aggiornato: NO
footprint 0603N_LED
pins: 1 ANODE, 2 CATHODE

## LED_Yellow_0805
designator DL?, comment LED Yellow 0805
Costo: 0,09; SizeCode: 0805; Aggiornato: s; ContoLavoro: 0
footprint LED_0805
simulation model DLED_GEN
pins: 1 ANODE, 2 CATHODE

## LIGHTPIPE_515-1064F
designator LP?, comment GUIDA 90° 3x1 LED SMD DIALIGHT 515-1064F  (no BOM)
Costo: 1; Hpcode: MMBLC153; Aggiornato: S; Detail: Parte meccanica non parte della scheda
footprint Lightpipe 3x1 (Dialight 515-1064F)
1 alternate drawing of the same symbol

## LIGHTPIPE_LEM-180
designator LP?, comment GUIDA 180° per LED SMD KANGYANG LEM-180
Costo: 0,075; Hpcode: MMBLC100; Aggiornato: S; Detail: Quotazione Orlandi HTcompo LEM-180 € 75,00/1000pcs Lead time: 2WK; ContoLavoro: 1
footprint GUIDA KANGYANG 180° LEM-180 per LED SMD (Footprint not found)
footprint GUIDA KANGYANG 180° LEM per LED SMD-IBRID_LPV_e_VLP_MONTATO_LEM-180 (Footprint not found)
1 alternate drawing of the same symbol

## LIGHTPIPE_LPV3-0600FP
designator LP?, comment GUIDA 180° per LED SMD BIVAR LPV3-0600FP
Costo: 0; Aggiornato: S; ContoLavoro: 1
footprint GUIDA BIVAR 180° LPV3-0600FP per LED SMD (Footprint not found)
footprint GUIDA BIVAR 180° VLP per LED SMD-IBRID_LPV_MONTATO_LPV3-0600FP
1 alternate drawing of the same symbol

## LIGHTPIPE_LPV3-1000FP
designator LP?, comment GUIDA 180° per LED SMD BIVAR LPV3-1000FP
Costo: 0; Aggiornato: S; ContoLavoro: 1
footprint GUIDA BIVAR 180° LPV3-1000FP per LED SMD
footprint GUIDA BIVAR 180° VLP per LED SMD-IBRID_LPV_MONTATO_LPV3-1000FP
1 alternate drawing of the same symbol

## LIGHTPIPE_SLP-1-3
designator LP?, comment GUIDA 90° per LED SMD BIVAR SLP-1-3  (no BOM)
Costo: 0,5; Hpcode: MMBLC094; Aggiornato: S; Detail: Parte meccanica non parte della scheda; ContoLavoro: 1
footprint GUIDA_BIVAR_90°_SLP-1-3 (Guida 90° per led SMD)
1 alternate drawing of the same symbol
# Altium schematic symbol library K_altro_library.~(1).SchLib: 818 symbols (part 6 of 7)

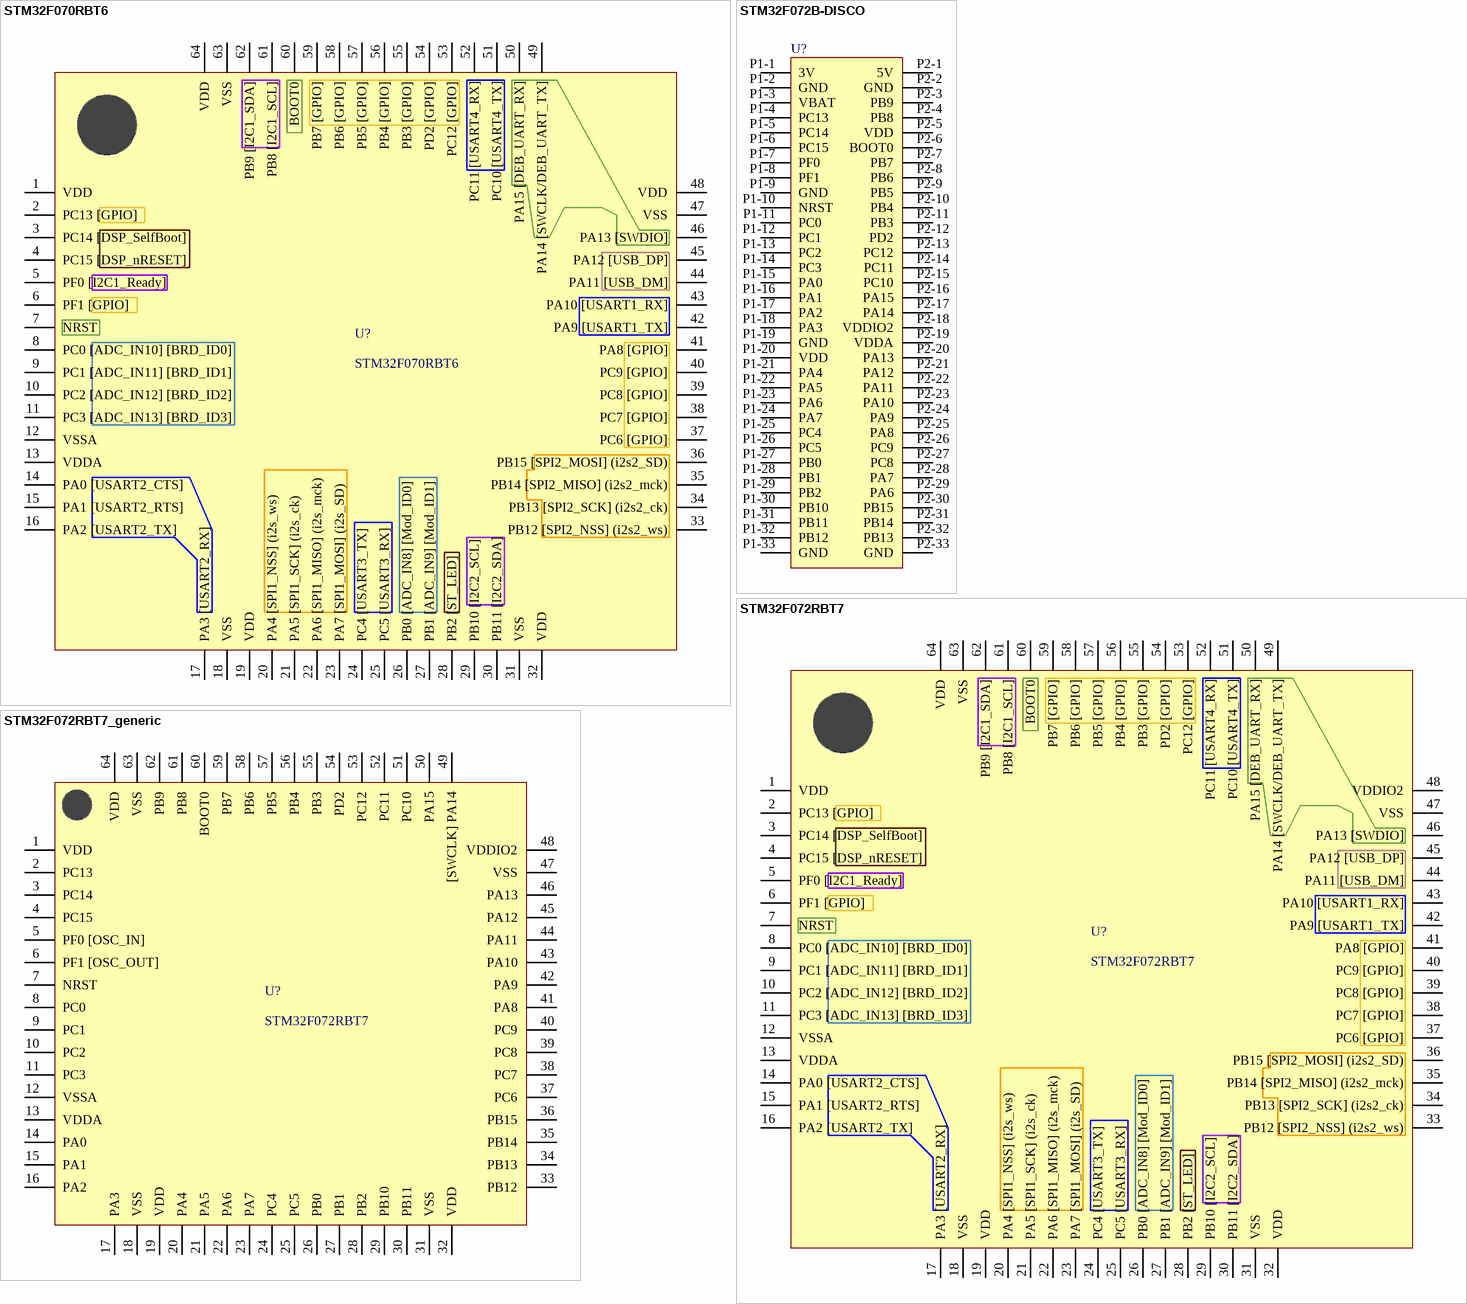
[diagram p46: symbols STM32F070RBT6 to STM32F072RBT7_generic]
## STM32F070RBT6
designator U?
Aggiornato: S; Core: ARM Cortex-M0; FLASH Size (Prog) (kB): 128; I/Os (High Current): 51; Internal RAM Size (kB): 16; Operating Frequency(F) (Processor speed) (MHz): 48; Costo: 0,93; ContoLavoro: 0; Detail: 1,756€ RS pz>160, 0,925€ Avnet pz>160
footprint STM-LQFP64
pins: 1 VDD (power), 2 PC13 [GPIO], 3 PC14 [DSP_SelfBoot], 4 PC15 [DSP_nRESET], 5 PF0 [I2C1_Ready], 6 PF1 [GPIO], 7 NRST, 8 PC0 [ADC_IN10] [BRD_ID0], 9 PC1 [ADC_IN11] [BRD_ID1], 10 PC2 [ADC_IN12] [BRD_ID2], 11 PC3 [ADC_IN13] [BRD_ID3], 12 VSSA (power), 13 VDDA (power), 14 PA0 [USART2_CTS], 15 PA1 [USART2_RTS], 16 PA2 [USART2_TX], 17 PA3 [USART2_RX], 18 VSS (power), 19 VDD (power), 20 PA4 [SPI1_NSS] (i2s_ws), 21 PA5 [SPI1_SCK] (i2s_ck), 22 PA6 [SPI1_MISO] (i2s_mck), 23 PA7 [SPI1_MOSI] (i2s_SD), 24 PC4 [USART3_TX], 25 PC5 [USART3_RX], 26 PB0 [ADC_IN8] [Mod_ID0], 27 PB1 [ADC_IN9] [Mod_ID1], 28 PB2 [ST_LED], 29 PB10 [I2C2_SCL], 30 PB11 [I2C2_SDA], 31 VSS (power), 32 VDD (power), 33 PB12 [SPI2_NSS] (i2s2_ws), 34 PB13 [SPI2_SCK] (i2s2_ck), 35 PB14 [SPI2_MISO] (i2s2_mck), 36 PB15 [SPI2_MOSI] (i2s2_SD), 37 PC6 [GPIO], 38 PC7 [GPIO], 39 PC8 [GPIO], 40 PC9 [GPIO], 41 PA8 [GPIO], 42 PA9 [USART1_TX], 43 PA10 [USART1_RX], 44 PA11 [USB_DM], 45 PA12 [USB_DP], 46 PA13 [SWDIO], 47 VSS (power), 48 VDD (power), 49 PA14 [SWCLK/DEB_UART_TX], 50 PA15 [DEB_UART_RX], 51 PC10 [USART4_TX], 52 PC11 [USART4_RX], 53 PC12 [GPIO], 54 PD2 [GPIO], 55 PB3 [GPIO], 56 PB4 [GPIO], 57 PB5 [GPIO], 58 PB6 [GPIO], 59 PB7 [GPIO], 60 BOOT0, 61 PB8 [I2C1_SCL], 62 PB9 [I2C1_SDA], 63 VSS (power), 64 VDD (power)

## STM32F072B-DISCO
designator U?
STM32F072 Discovery Board; Aggiornato: NO; Costo: 0
pins: P1-1 3V, P1-2 GND, P1-3 VBAT, P1-4 PC13, P1-5 PC14, P1-6 PC15, P1-7 PF0, P1-8 PF1, P1-9 GND, P1-10 NRST, P1-11 PC0, P1-12 PC1, P1-13 PC2, P1-14 PC3, P1-15 PA0, P1-16 PA1, P1-17 PA2, P1-18 PA3, P1-19 GND, P1-20 VDD, P1-21 PA4, P1-22 PA5, P1-23 PA6, P1-24 PA7, P1-25 PC4, P1-26 PC5, P1-27 PB0, P1-28 PB1, P1-29 PB2, P1-30 PB10, P1-31 PB11, P1-32 PB12, P1-33 GND, P2-1 5V, P2-2 GND, P2-3 PB9, P2-4 PB8, P2-5 VDD, P2-6 BOOT0, P2-7 PB7, P2-8 PB6, P2-9 PB5, P2-10 PB4, P2-11 PB3, P2-12 PD2, P2-13 PC12, P2-14 PC11, P2-15 PC10, P2-16 PA15, P2-17 PA14, P2-18 VDDIO2, P2-19 VDDA, P2-20 PA13, P2-21 PA12, P2-22 PA11, P2-23 PA10, P2-24 PA9, P2-25 PA8, P2-26 PC9, P2-27 PC8, P2-28 PA7, P2-29 PA6, P2-30 PB15, P2-31 PB14, P2-32 PB13, P2-33 GND

## STM32F072RBT7
designator U?
Aggiornato: S; Core: ARM Cortex-M0; FLASH Size (Prog) (kB): 128; I/Os (High Current): 51; Internal RAM Size (kB): 16; Operating Frequency(F) (Processor speed) (MHz): 48; HPcode: ICSTM32F072RBT7; Costo: 1,45; ContoLavoro: 1; Detail: 2,595€ RS pz>160, STM32F072RBT7TR 1,45€ Avnet pz>1000,
footprint STM-LQFP64
pins: 1 VDD (power), 2 PC13 [GPIO], 3 PC14 [DSP_SelfBoot], 4 PC15 [DSP_nRESET], 5 PF0 [I2C1_Ready], 6 PF1 [GPIO], 7 NRST, 8 PC0 [ADC_IN10] [BRD_ID0], 9 PC1 [ADC_IN11] [BRD_ID1], 10 PC2 [ADC_IN12] [BRD_ID2], 11 PC3 [ADC_IN13] [BRD_ID3], 12 VSSA (power), 13 VDDA (power), 14 PA0 [USART2_CTS], 15 PA1 [USART2_RTS], 16 PA2 [USART2_TX], 17 PA3 [USART2_RX], 18 VSS (power), 19 VDD (power), 20 PA4 [SPI1_NSS] (i2s_ws), 21 PA5 [SPI1_SCK] (i2s_ck), 22 PA6 [SPI1_MISO] (i2s_mck), 23 PA7 [SPI1_MOSI] (i2s_SD), 24 PC4 [USART3_TX], 25 PC5 [USART3_RX], 26 PB0 [ADC_IN8] [Mod_ID0], 27 PB1 [ADC_IN9] [Mod_ID1], 28 PB2 [ST_LED], 29 PB10 [I2C2_SCL], 30 PB11 [I2C2_SDA], 31 VSS (power), 32 VDD (power), 33 PB12 [SPI2_NSS] (i2s2_ws), 34 PB13 [SPI2_SCK] (i2s2_ck), 35 PB14 [SPI2_MISO] (i2s2_mck), 36 PB15 [SPI2_MOSI] (i2s2_SD), 37 PC6 [GPIO], 38 PC7 [GPIO], 39 PC8 [GPIO], 40 PC9 [GPIO], 41 PA8 [GPIO], 42 PA9 [USART1_TX], 43 PA10 [USART1_RX], 44 PA11 [USB_DM], 45 PA12 [USB_DP], 46 PA13 [SWDIO], 47 VSS (power), 48 VDDIO2 (power), 49 PA14 [SWCLK/DEB_UART_TX], 50 PA15 [DEB_UART_RX], 51 PC10 [USART4_TX], 52 PC11 [USART4_RX], 53 PC12 [GPIO], 54 PD2 [GPIO], 55 PB3 [GPIO], 56 PB4 [GPIO], 57 PB5 [GPIO], 58 PB6 [GPIO], 59 PB7 [GPIO], 60 BOOT0, 61 PB8 [I2C1_SCL], 62 PB9 [I2C1_SDA], 63 VSS (power), 64 VDD (power)

## STM32F072RBT7_generic
designator U?, comment STM32F072RBT7
Aggiornato: S; Core: ARM Cortex-M0; FLASH Size (Prog) (kB): 128; I/Os (High Current): 51; Internal RAM Size (kB): 16; Operating Frequency(F) (Processor speed) (MHz): 48; HPcode: ICSTM32F072RBT7; Costo: 1,45; ContoLavoro: 1; Detail: 2,595€ RS pz>160, STM32F072RBT7TR 1,45€ Avnet pz>1000,
footprint STM-LQFP64
pins: 1 VDD (power), 2 PC13, 3 PC14, 4 PC15, 5 PF0 [OSC_IN], 6 PF1 [OSC_OUT], 7 NRST, 8 PC0, 9 PC1, 10 PC2, 11 PC3, 12 VSSA (power), 13 VDDA (power), 14 PA0, 15 PA1, 16 PA2, 17 PA3, 18 VSS (power), 19 VDD (power), 20 PA4, 21 PA5, 22 PA6, 23 PA7, 24 PC4, 25 PC5, 26 PB0, 27 PB1, 28 PB2, 29 PB10, 30 PB11, 31 VSS (power), 32 VDD (power), 33 PB12, 34 PB13, 35 PB14, 36 PB15, 37 PC6, 38 PC7, 39 PC8, 40 PC9, 41 PA8, 42 PA9, 43 PA10, 44 PA11, 45 PA12, 46 PA13, 47 VSS (power), 48 VDDIO2 (power), 49 [SWCLK] PA14, 50 PA15, 51 PC10, 52 PC11, 53 PC12, 54 PD2, 55 PB3, 56 PB4, 57 PB5, 58 PB6, 59 PB7, 60 BOOT0, 61 PB8, 62 PB9, 63 VSS (power), 64 VDD (power)


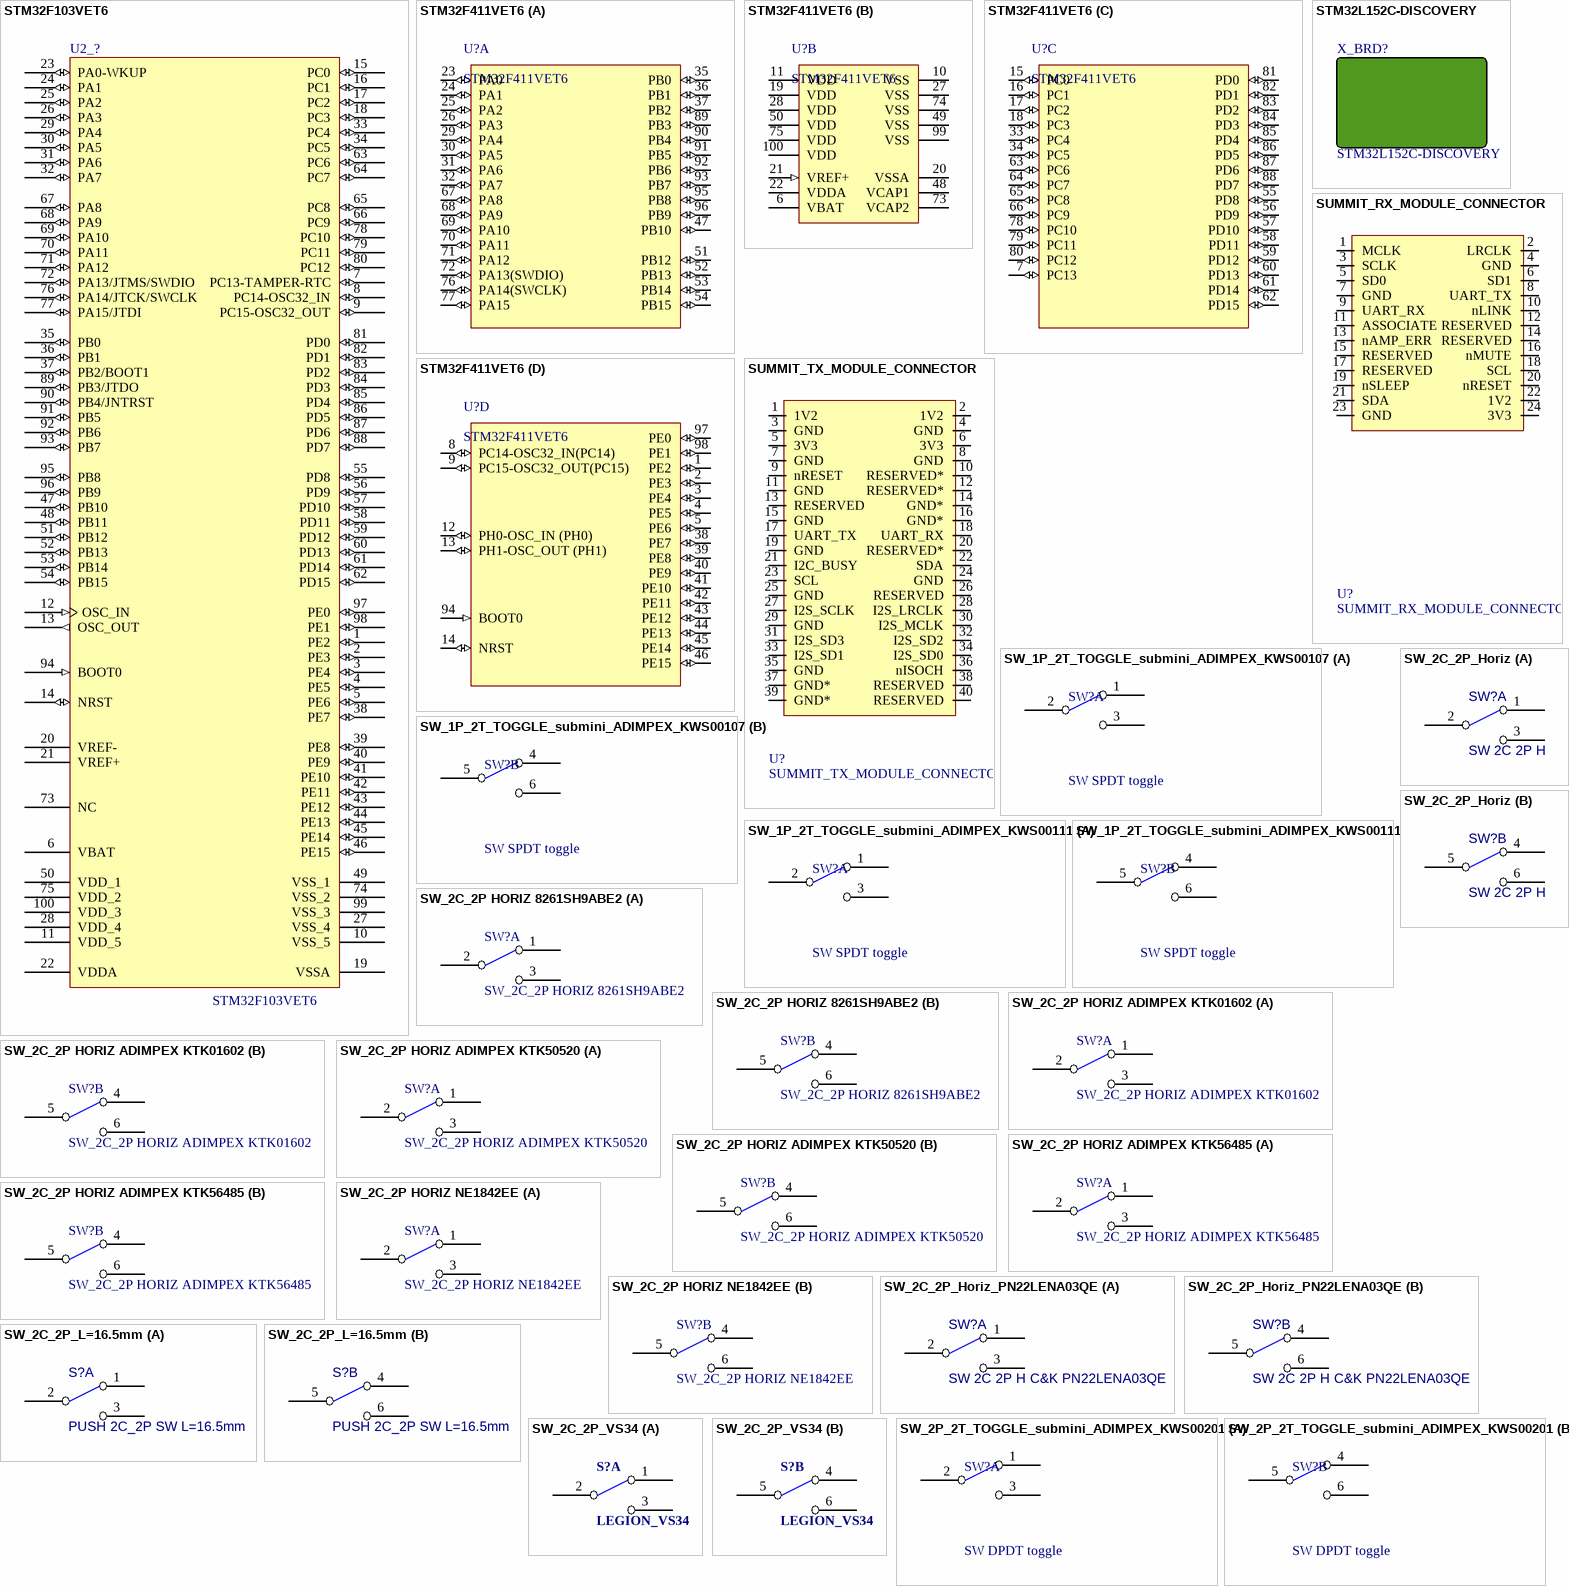
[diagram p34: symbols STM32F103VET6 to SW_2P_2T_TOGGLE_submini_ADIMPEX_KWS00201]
## STM32F103VET6
designator U2_?
STM32 ARM-based 32-bit MCU with 64 Kbytes Flash, 100-pin LQFP, Industrial Temperature; Aggiornato: NO; Costo: 4,27; HPcode: ICSTM32F103; ContoLavoro: 0
footprint LQFP100_N (Thin QFP, 100-Leads, Body 14x14mm, Pitch 0.5mm, IPC Medium Density)
footprint LQFP100_L (Thin QFP, 100-Leads, Body 14x14mm, Pitch 0.5mm, IPC High Density)
footprint LQFP100_M (Thin QFP, 100-Leads, Body 14x14mm, Pitch 0.5mm, IPC Low Density)
footprint LTQFP100_EP
pins: 1 PE2 (io), 2 PE3 (io), 3 PE4 (io), 4 PE5 (io), 5 PE6 (io), 6 VBAT (power), 7 PC13-TAMPER-RTC (io), 8 PC14-OSC32_IN (io), 9 PC15-OSC32_OUT (io), 10 VSS_5 (power), 11 VDD_5 (power), 12 OSC_IN (in), 13 OSC_OUT (out), 14 NRST (io), 15 PC0 (io), 16 PC1 (io), 17 PC2 (io), 18 PC3 (io), 19 VSSA (power), 20 VREF- (power), 21 VREF+ (power), 22 VDDA (power), 23 PA0-WKUP (io), 24 PA1 (io), 25 PA2 (io), 26 PA3 (io), 27 VSS_4 (power), 28 VDD_4 (power), 29 PA4 (io), 30 PA5 (io), 31 PA6 (io), 32 PA7 (io), 33 PC4 (io), 34 PC5 (io), 35 PB0 (io), 36 PB1 (io), 37 PB2/BOOT1 (io), 38 PE7 (io), 39 PE8 (io), 40 PE9 (io), 41 PE10 (io), 42 PE11 (io), 43 PE12 (io), 44 PE13 (io), 45 PE14 (io), 46 PE15 (io), 47 PB10 (io), 48 PB11 (io), 49 VSS_1 (power), 50 VDD_1 (power), 51 PB12 (io), 52 PB13 (io), 53 PB14 (io), 54 PB15 (io), 55 PD8 (io), 56 PD9 (io), 57 PD10 (io), 58 PD11 (io), 59 PD12 (io), 60 PD13 (io), 61 PD14 (io), 62 PD15 (io), 63 PC6 (io), 64 PC7 (io), 65 PC8 (io), 66 PC9 (io), 67 PA8 (io), 68 PA9 (io), 69 PA10 (io), 70 PA11 (io), 71 PA12 (io), 72 PA13/JTMS/SWDIO (io), 73 NC, 74 VSS_2 (power), 75 VDD_2 (power), 76 PA14/JTCK/SWCLK (io), 77 PA15/JTDI (io), 78 PC10 (io), 79 PC11 (io), 80 PC12 (io), 81 PD0 (io), 82 PD1 (io), 83 PD2 (io), 84 PD3 (io), 85 PD4 (io), 86 PD5 (io), 87 PD6 (io), 88 PD7 (io), 89 PB3/JTDO (io), 90 PB4/JNTRST (io), 91 PB5 (io), 92 PB6 (io), 93 PB7 (io), 94 BOOT0 (in), 95 PB8 (io), 96 PB9 (io), 97 PE0 (io), 98 PE1 (io), 99 VSS_3 (power), 100 VDD_3 (power)

## STM32F411VET6
designator U?
Aggiornato: s; Core: ARM Cortex-M4; FLASH Size (Prog) (kB): 64; I/Os (High Current): 39; Internal RAM Size (kB): 8; Operating Frequency(F) (Processor speed) (MHz): 48; HPcode: ICSTM32F030C8T6; Costo: 0,8; ContoLavoro: 1
footprint LTQFP100_N
part A pins: 23 PA0 (io), 24 PA1 (io), 25 PA2 (io), 26 PA3 (io), 29 PA4 (io), 30 PA5 (io), 31 PA6 (io), 32 PA7 (io), 35 PB0 (io), 36 PB1 (io), 37 PB2 (io), 47 PB10 (io), 51 PB12 (io), 52 PB13 (io), 53 PB14 (io), 54 PB15 (io), 67 PA8 (io), 68 PA9 (io), 69 PA10 (io), 70 PA11 (io), 71 PA12 (io), 72 PA13(SWDIO) (io), 76 PA14(SWCLK) (io), 77 PA15 (io), 89 PB3 (io), 90 PB4 (io), 91 PB5 (io), 92 PB6 (io), 93 PB7 (io), 95 PB8 (io), 96 PB9 (io)
part B pins: 6 VBAT (power) "Battery power supply", 10 VSS (power) "Ground", 11 VDD (power) "Digital power supply", 19 VDD (power) "Digital power supply", 20 VSSA (power) "Analog ground", 21 VREF+ (in) "Analog reference voltage", 22 VDDA (power) "Analog power supply", 27 VSS (power) "Ground", 28 VDD (power) "Digital power supply", 48 VCAP1 "Internal regulator bypass", 49 VSS (power) "Ground", 50 VDD (power) "Digital power supply", 73 VCAP2 "Internal regulator bypass", 74 VSS (power) "Ground", 75 VDD (power) "Digital power supply", 99 VSS (power) "Ground", 100 VDD (power) "Digital power supply"
part C pins: 7 PC13 (io), 15 PC0 (io), 16 PC1 (io), 17 PC2 (io), 18 PC3 (io), 33 PC4 (io), 34 PC5 (io), 55 PD8 (io), 56 PD9 (io), 57 PD10 (io), 58 PD11 (io), 59 PD12 (io), 60 PD13 (io), 61 PD14 (io), 62 PD15 (io), 63 PC6 (io), 64 PC7 (io), 65 PC8 (io), 66 PC9 (io), 78 PC10 (io), 79 PC11 (io), 80 PC12 (io), 81 PD0 (io), 82 PD1 (io), 83 PD2 (io), 84 PD3 (io), 85 PD4 (io), 86 PD5 (io), 87 PD6 (io), 88 PD7 (io)
part D pins: 1 PE2 (io), 2 PE3 (io), 3 PE4 (io), 4 PE5 (io) "PB5", 5 PE6 (io), 8 PC14-OSC32_IN(PC14) (io) "PC14-OSC32_IN(PC14)/OSC32_IN", 9 PC15-OSC32_OUT(PC15) (io) "PC15-OSC32_OUT(PC15)/OSC32_OUT", 12 PH0-OSC_IN (PH0) (io) "PH0-OSC_IN(PH0)/OSC_IN", 13 PH1-OSC_OUT (PH1) (io) "PH1-OSC_OUT(PH1)/OSC_OUT", 14 NRST (io) "Device reset input / internal reset output (active low)", 38 PE7 (io) "PB7", 39 PE8 (io) "PB8", 40 PE9 (io) "PB9", 41 PE10 (io), 42 PE11 (io) "PB11", 43 PE12 (io) "PB12", 44 PE13 (io) "PB13", 45 PE14 (io) "PB14", 46 PE15 (io), 94 BOOT0 (in) "Boot memory selection", 97 PE0 (io), 98 PE1 (io)

## STM32L152C-DISCOVERY
designator X_BRD?  (mechanical)
Costo: 10,00; Aggiornato: s; ContoLavoro: 0

## SUMMIT_RX_MODULE_CONNECTOR
designator U?
Aggiornato: n; Costo: 0
footprint SUMMIT_RX_MODULE_CONNECTOR
footprint HEADER 2X12_MALE
pins: 1 MCLK, 2 LRCLK, 3 SCLK, 4 GND, 5 SD0, 6 SD1, 7 GND, 8 UART_TX, 9 UART_RX, 10 nLINK, 11 ASSOCIATE, 12 RESERVED, 13 nAMP_ERR, 14 RESERVED, 15 RESERVED, 16 nMUTE, 17 RESERVED, 18 SCL, 19 nSLEEP, 20 nRESET, 21 SDA, 22 1V2, 23 GND, 24 3V3

## SUMMIT_TX_MODULE_CONNECTOR
designator U?
Aggiornato: n; Costo: 0
footprint SUMMIT_TX_MODULE_CONNECTOR
footprint HEADER 2X20_MALE
pins: 1 1V2, 2 1V2, 3 GND, 4 GND, 5 3V3, 6 3V3, 7 GND, 8 GND, 9 nRESET, 10 RESERVED*, 11 GND, 12 RESERVED*, 13 RESERVED, 14 GND*, 15 GND, 16 GND*, 17 UART_TX, 18 UART_RX, 19 GND, 20 RESERVED*, 21 I2C_BUSY, 22 SDA, 23 SCL, 24 GND, 25 GND, 26 RESERVED, 27 I2S_SCLK, 28 I2S_LRCLK, 29 GND, 30 I2S_MCLK, 31 I2S_SD3, 32 I2S_SD2, 33 I2S_SD1, 34 I2S_SD0, 35 GND, 36 nISOCH, 37 GND*, 38 RESERVED, 39 GND*, 40 RESERVED

## SW_1P_2T_TOGGLE_submini_ADIMPEX_KWS00107
designator SW?, comment SW SPDT toggle
SW_1P_2T_TOGGLE_submini_ADIMPEX_KWS00107; Costo: 1,92; Detail: € RS Pz>25; ContoLavoro: 0
footprint SW_1P_2T_TOGGLE_submini_ADIMPEX_SERIE_WT113-P
part A pins: 1 NC, 2 COMMON, 3 NO, 11 hidden, 12 hidden
part B pins: 4 NC, 5 COMMON, 6 NO

## SW_1P_2T_TOGGLE_submini_ADIMPEX_KWS00111
designator SW?, comment SW SPDT toggle
SW_1P_2T_TOGGLE_submini_ADIMPEX_KWS00111; Costo: 1,87; Detail: € RS  pz>50; ContoLavoro: 0
footprint SW_1P_2T_TOGGLE_submini_ADIMPEX_SERIE_WT113-P
part A pins: 1 NC, 2 COMMON, 3 NO, 11 hidden, 12 hidden
part B pins: 4 NC, 5 COMMON, 6 NO

## SW_2C_2P HORIZ 8261SH9ABE2
designator SW?
Costo: 4,5; Detail: 4,5€ Costo standard Esolver 2018; HPcode: MMBLC039; ContoLavoro: 1
footprint SWITCH 2P_2T_C&K_8261SH9ABE2 (SWITCH 2P_2T_PUSH_BOTTON_C&K_SERIE_8060)
part A pins: 1 NC, 2 COMMON, 3 NO
part B pins: 4 NC, 5 COMMON, 6 NO

## SW_2C_2P HORIZ ADIMPEX KTK01602
designator SW?
SWITCH 2C_2P HORIZ ADIMPEX KTK01602; Costo: 0; HPcode: SWIPH2C2P244 da ricreare; ContoLavoro: 1
footprint SWITCH 2P KTK01602
part A pins: 1 NC, 2 COMMON, 3 NO
part B pins: 4 NC, 5 COMMON, 6 NO

## SW_2C_2P HORIZ ADIMPEX KTK50520
designator SW?
SWITCH 2C_2P HORIZ ADIMPEX KTK50520; Costo: 0; HPcode: SWIPH2C2P143 da ricreare; ContoLavoro: 1
footprint SWITCH2P_2C ADIMPEX KTK50520
part A pins: 1 NC, 2 COMMON, 3 NO
part B pins: 4 NC, 5 COMMON, 6 NO

## SW_2C_2P HORIZ ADIMPEX KTK56485
designator SW?
Costo: 0; Detail: ADIMPEX KTK56485 SOLO PER AC NO DC!; ContoLavoro: 1
footprint SWITCH 2P KTK56485
part A pins: 1 NC, 2 COMMON, 3 NO
part B pins: 4 NC, 5 COMMON, 6 NO

## SW_2C_2P HORIZ NE1842EE
designator SW?
Costo: 4,5; Detail: 4,5€ Costo standard Esolver 2018; HPcode: MMBLC039; ContoLavoro: 1
footprint SWITCH 2P NE1842EE
footprint SWITCH 2P NE1842EE-cappuccio
part A pins: 1 NC, 2 COMMON, 3 NO
part B pins: 4 NC, 5 COMMON, 6 NO

## SW_2C_2P_Horiz
designator SW?, comment SW 2C 2P H
SW 2C 2P horiz; Costo: 0; Aggiornato: NO
footprint SWITCH_2C_2P_KTK50520-r
part A pins: 1 NC, 2 COMMON, 3 NO
part B pins: 4 NC, 5 COMMON, 6 NO

## SW_2C_2P_Horiz_PN22LENA03QE
designator SW?, comment SW 2C 2P H C&K PN22LENA03QE
Costo: 1,38; Aggiornato: S; ContoLavoro: 0
footprint SWITCH_2C_2P_PN22LENA03QE (PN22LENA03QE)
part A pins: 1 NC, 2 COMMON, 3 NO
part B pins: 4 NC, 5 COMMON, 6 NO

## SW_2C_2P_L=16.5mm
designator S?, comment PUSH 2C_2P SW L=16.5mm
Hpcode: SW8.5X8.5H165; Costo: 0,315; Aggiornato: NO; ContoLavoro: 0
footprint SWITCH2W_2P BEH
footprint SWITCH2W_2P BEH-cappuccioH
footprint SWITCH2W_2P BEH-cappuccioV
part A pins: 1 NC, 2 COMMON, 3 NO
part B pins: 4 NC, 5 COMMON, 6 NO

## SW_2C_2P_VS34
designator S?, comment LEGION_VS34
Hpcode: POWC/TENSIONE; Costo: 0,70; Aggiornato: S; ContoLavoro: 1
footprint SWITCH_VS34
footprint SWITCH_VS34_REV2
footprint SWITCH_VS34_REV3 (Footprint not found)
part A pins: 1 NC, 2 COMMON, 3 NO
part B pins: 4 NC, 5 COMMON, 6 NO

## SW_2P_2T_TOGGLE_submini_ADIMPEX_KWS00201
designator SW?, comment SW DPDT toggle
SW_2P_2T_TOGGLE_submini_ADIMPEX_KWS00201; Costo: 1,25; Detail: € Pz>25; ContoLavoro: 0
footprint SW_2P_2T_TOGGLE_submini_ADIMPEX_SERIE_WT116-P
part A pins: 1 NC, 2 COMMON, 3 NO, 11 hidden, 12 hidden
part B pins: 4 NC, 5 COMMON, 6 NO


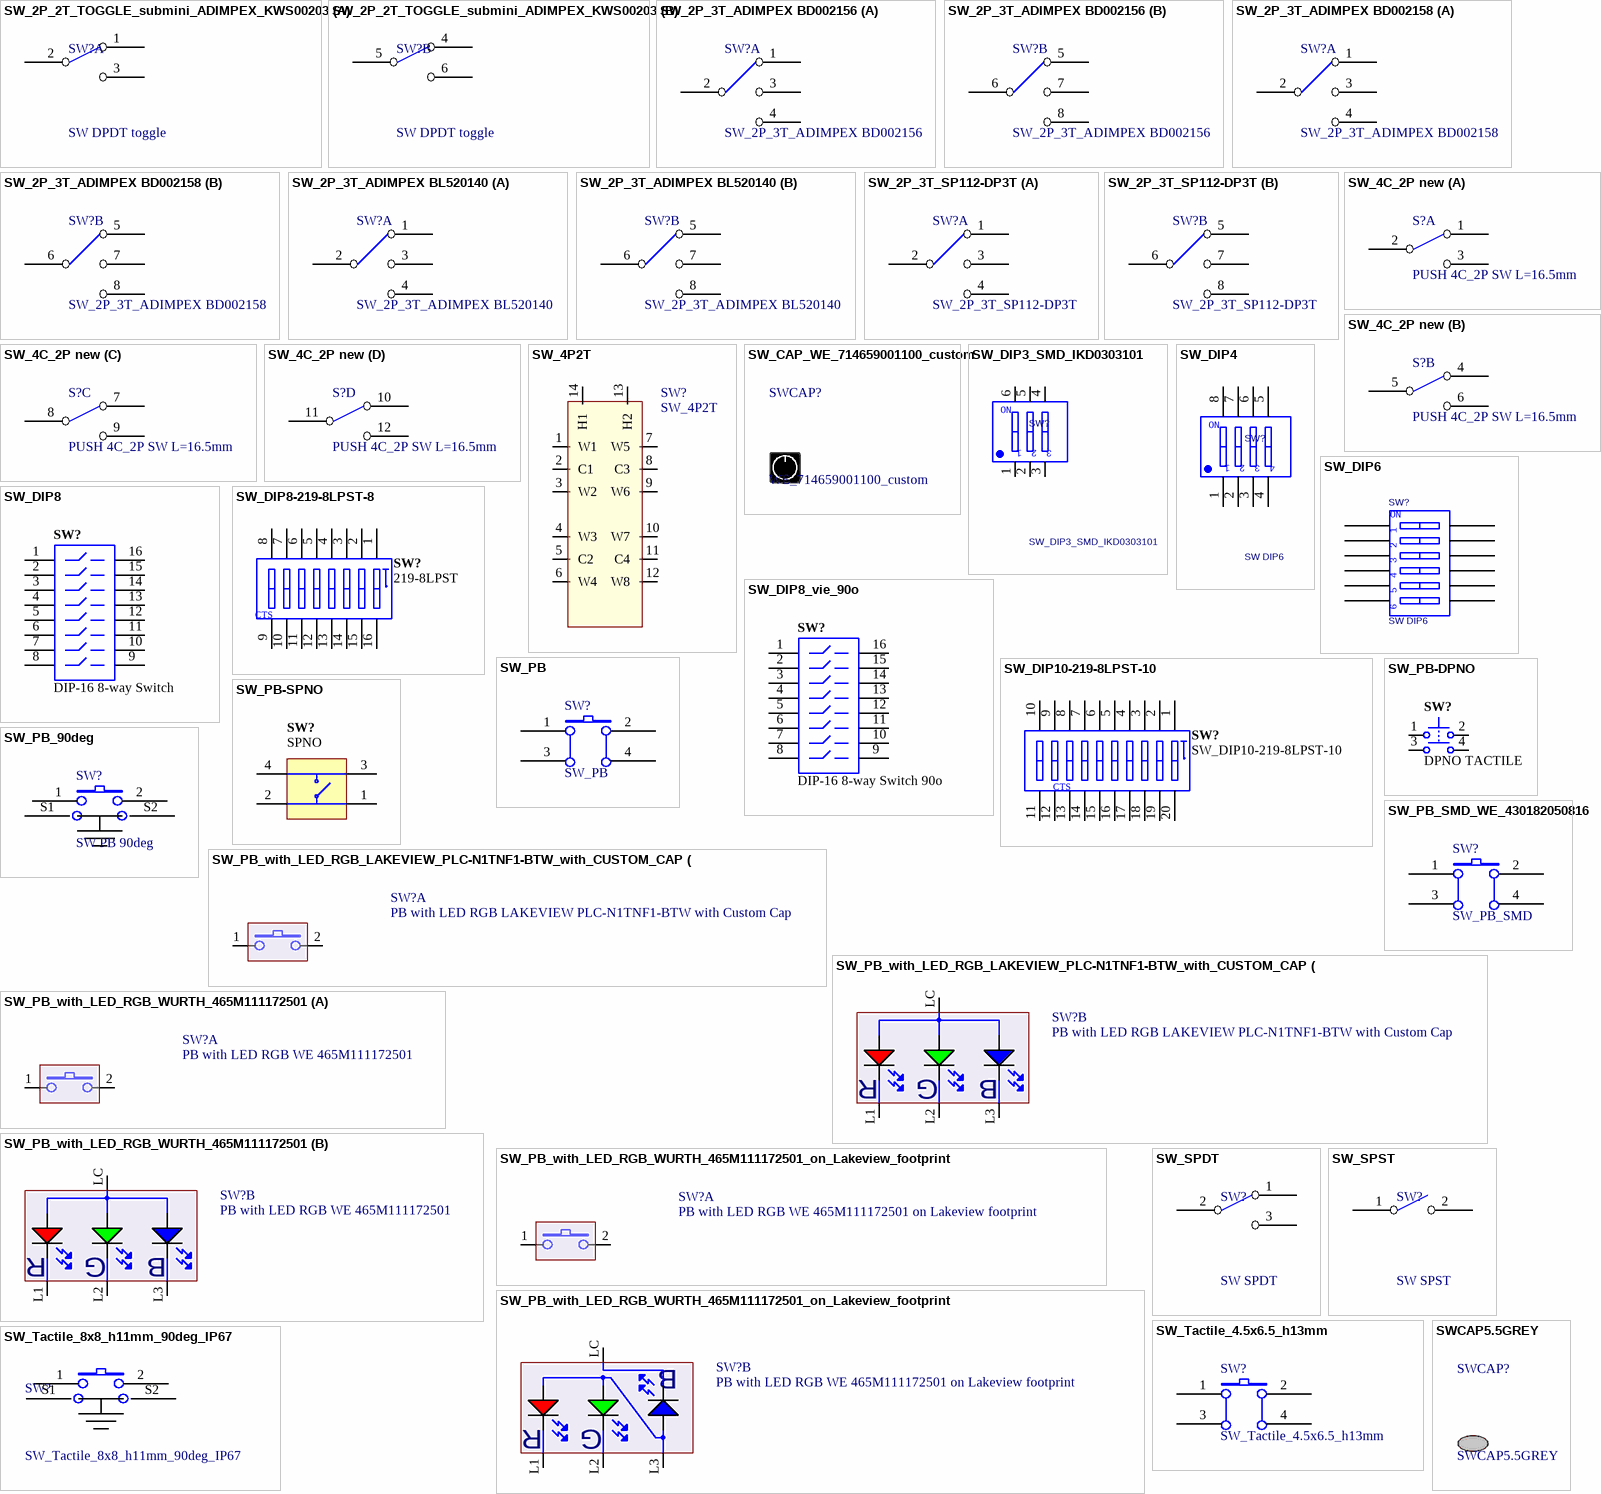
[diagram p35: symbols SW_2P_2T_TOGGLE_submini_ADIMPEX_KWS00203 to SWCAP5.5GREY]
## SW_2P_2T_TOGGLE_submini_ADIMPEX_KWS00203
designator SW?, comment SW DPDT toggle
SW_2P_2T_TOGGLE_submini_ADIMPEX_KWS00203; Costo: 1,59; Detail: € RS Pz>25; ContoLavoro: 0
footprint SW_2P_2T_TOGGLE_submini_ADIMPEX_SERIE_WT116-P
part A pins: 1 NC, 2 COMMON, 3 NO, 11 hidden, 12 hidden
part B pins: 4 NC, 5 COMMON, 6 NO

## SW_2P_3T_ADIMPEX BD002156
designator SW?
SWITCH 2P_3T_ADIMPEX BD002156; Costo: 0; ContoLavoro: 1
footprint SWITCH 2P_3T_ADIMPEX BD002156 (Footprint not found)
part A pins: 1 NC, 2 COMMON, 3 NO, 4 NO2, 11 hidden, 12 hidden
part B pins: 5 NC, 6 COMMON, 7 NO, 8 NO2

## SW_2P_3T_ADIMPEX BD002158
designator SW?
SWITCH 2P_3T_ADIMPEX BD002158; Costo: 0; ContoLavoro: 1
footprint SWITCH 2P_3T_ADIMPEX BD002158 (Footprint not found)
part A pins: 1 NC, 2 COMMON, 3 NO, 4 NO2, 11 hidden, 12 hidden
part B pins: 5 NC, 6 COMMON, 7 NO, 8 NO2

## SW_2P_3T_ADIMPEX BL520140
designator SW?
SWITCH 2P_3T_ADIMPEX BL520140; Costo: 0,419; HPcode: SW3P2TA; ContoLavoro: 1
footprint SWITCH 2P_3T_ADIMPEX BL520140
part A pins: 1 NC, 2 COMMON, 3 NO, 4 NO2, 11 hidden, 12 hidden
part B pins: 5 NC, 6 COMMON, 7 NO, 8 NO2

## SW_2P_3T_SP112-DP3T
designator SW?
SWITCH 2P_3T_SP112-DP3T; Costo: 1,98; Detail: Costo RS >250; ContoLavoro: 0
footprint SWITCH 2P_3T_SP112-DP3T
part A pins: 1 NC, 2 COMMON, 3 NO, 4 NO2, 11 hidden, 12 hidden
part B pins: 5 NC, 6 COMMON, 7 NO, 8 NO2

## SW_4C_2P new
designator S?, comment PUSH 4C_2P SW L=16.5mm
Hpcode: PUSH??; Costo: 0; Aggiornato: NO
footprint SWITCH2P_4C_serie_MPV
part A pins: 1 NC, 2 COMMON, 3 NO
part B pins: 4 NC, 5 COMMON, 6 NO
part C pins: 7 NC, 8 COMMON, 9 NO
part D pins: 10 NC, 11 COMMON, 12 NO
1 alternate drawing of the same symbol

## SW_4P2T
designator SW?
Costo: 0; Aggiornato: NO
footprint RP_SK-42D01_SWITCH
footprint SS009-03P-42 (Footprint not found)
pins: 1 W1, 2 C1, 3 W2, 4 W3, 5 C2, 6 W4, 7 W5, 8 C3, 9 W6, 10 W7, 11 C4, 12 W8, 13 H2, 14 H1

## SW_CAP_WE_714659001100_custom
designator SWCAP?, comment WE_714659001100_custom  (mechanical)
SW CAP WE 714659001100 custom; Costo: 0,60; Aggiornato: s; Detail: prezzo indicativo 1080 pcs a 0,60€ cad; ContoLavoro: 1
pins: 1 hidden
1 alternate drawing of the same symbol

## SW_DIP3_SMD_IKD0303101
designator SW?
SW_DIP3_SMD; Costo: 1,845; Aggiornato: si; ContoLavoro: 0
footprint DIP SW 3P_I (DIP SW 3P_IDK Serie)
pins: 1, 2, 3, 4, 5, 6

## SW_DIP4
designator SW?, comment SW DIP6
Costo: 0; Aggiornato: NO
footprint 4DIPSWITCH
pins: 1, 2, 3, 4, 5, 6, 7, 8

## SW_DIP6
designator SW?, comment SW DIP6
Costo: 0; Aggiornato: NO
footprint 6DIPSWITCH
pins: 1 A1, 2 A2, 3 A3, 4 A4, 5 A5, 6 A6, 7 B6, 8 B5, 9 B4, 10 B3, 11 B2, 12 B1

## SW_DIP8
designator SW?, comment DIP-16 8-way Switch
Switch, DIP Black 8-Way 300mil x 100mil; Rated Voltage: mV; Switch Type: SPDT; Costo: 0; Aggiornato: NO
footprint DIP-16-KEY
3D model switch_unit
pins: 1, 2, 3, 4, 5, 6, 7, 8, 9, 10, 11, 12, 13, 14, 15, 16

## SW_DIP8-219-8LPST-8
designator SW?, comment 219-8LPST
Switch, SPST, Surface Mount DIP, 8-way; Rated Voltage: 50 V; Switch Type: Dual In Line; Aggiornato: NO; Costo: 0
footprint 219-8LPST
pins: 1 A1, 2 A2, 3 A3, 4 A4, 5 A5, 6 A6, 7 A7, 8 A8, 9 B8, 10 B7, 11 B6, 12 B5, 13 B4, 14 B3, 15 B2, 16 B1

## SW_DIP8_vie_90o
designator SW?, comment DIP-16 8-way Switch 90o
Rated Voltage: mV; Switch Type: SPDT; Costo: 0; Aggiornato: SI
3D model switch_unit
footprint 8DIPSWITCH_90o
pins: 1, 2, 3, 4, 5, 6, 7, 8, 9, 10, 11, 12, 13, 14, 15, 16

## SW_DIP10-219-8LPST-10
designator SW?
Aggiornato: si; Costo: 1,484; ContoLavoro: 0
footprint 20DIPSWITCH
pins: 1 A1, 2 A2, 3 A3, 4 A4, 5 A5, 6 A6, 7 A7, 8 A8, 9 B8, 10 B7, 11 B6, 12 B5, 13 B4, 14 B3, 15 B2, 16 B1, 17 B4, 18 B3, 19 B2, 20 B1

## SW_PB
designator SW?
Costo: 0; Aggiornato: s
footprint TACTSW
pins: 1, 2, 3, 4

## SW_PB-DPNO
designator SW?, comment DPNO TACTILE
Switch, DPNO Push Button Through-Hole; Costo: 0; Aggiornato: NO
footprint IT-2175
3D model IT2175
footprint SW_DTSM-61NT/R (Footprint not found)
pins: 1, 2, 3, 4

## SW_PB-SPNO
designator SW?, comment SPNO
Switch, SPNO Push Button SMD; Rated Voltage: mV; Switch Type: SPDT; Costo: 0; Aggiornato: NO
footprint SW_DTSM-61NT/R
3D model SPNA
pins: 1, 2, 3, 4

## SW_PB_90deg
designator SW?, comment SW PB 90deg
Costo: 0,10; Aggiornato: s; ContoLavoro: 0
footprint TACTSW_90deg
pins: 1, 2, S1, S2

## SW_PB_SMD_WE_430182050816
designator SW?, comment SW_PB_SMD
Costo: 0,075; Aggiornato: s; Detail: offerta WE A21IT001066.PDF  3000pcs/y 0,075€; ContoLavoro: 0
footprint TACTSW_WE_430182050816
pins: 1, 2, 3, 4

## SW_PB_with_LED_RGB_LAKEVIEW_PLC-N1TNF1-BTW_with_CUSTOM_CAP
designator SW?, comment PB with LED RGB LAKEVIEW PLC-N1TNF1-BTW with Custom Cap
15x15mm THT Push Button Switch with integrated LED RGB with Custom CAP; Detail: 2€ PZ > 1000; Hpcode: SWRGBWITHCAP; Costo: 2; Aggiornato: S; ContoLavoro: 1
footprint SW_PB_LED_RGB_LAKEVIEW_PLC-N1TNF1-BTW_with_Custom_Cap (Footprint not found)
part A pins: 1, 2
part B pins: L1 R_Cat, L2 G_Cat, L3 B_Cat, LC Anode

## SW_PB_with_LED_RGB_WURTH_465M111172501
designator SW?, comment PB with LED RGB WE 465M111172501
15x15mm THT Push Button Switch with integrated LED RGB WS-PBTL WE 465M111172501; Detail: 3,90€ PZ > 800 offerta A19IT021326; Costo: 3,90; Aggiornato: S; ContoLavoro: 1
footprint SW_PB_LED_RGB_WE_465M111172501
footprint SW_PB_LED_RGB_WE_465M111172501 _con_capp_71465900110
part A pins: 1, 2
part B pins: L1 R_Cat, L2 G_Cat, L3 B_Cat, LC Anode

## SW_PB_with_LED_RGB_WURTH_465M111172501_on_Lakeview_footprint
designator SW?, comment PB with LED RGB WE 465M111172501 on Lakeview footprint
15x15mm THT Push Button Switch with integrated LED RGB WS-PBTL WE 465M111172501 on Lakeview footprint NOTA CAPPUCCIO NON INCLUSO nel codice; Detail: 3,90€ PZ > 800 offerta A19IT021326; Costo: 3,90; Aggiornato: S; ContoLavoro: 1
footprint SW_PB_LED_RGB_LAKEVIEW_PLC-N1TNF1-BTW_with_Custom_Cap
part A pins: 1, 2
part B pins: L1 R_Cat, L2 G_Cat, L3 B_Cat, LC Anode

## SW_SPDT
designator SW?, comment SW SPDT
Costo: 1,92; Detail: € RS Pz>25; ContoLavoro: 0
footprint SW_1P_2T_TOGGLE_submini_ADIMPEX_SERIE_WT113-P
pins: 1 NC, 2 COMMON, 3 NO

## SW_SPST
designator SW?, comment SW SPST
Costo: 1,12; Detail: € RS Pz>25; ContoLavoro: 0
footprint DIP 1via C&K SDA01H0SBR
pins: 1 NC, 2 COMMON

## SW_Tactile_4.5x6.5_h13mm
designator SW?
TACTILE SWITCH 4.5X6.5mm H=13.0mm; Costo: 0,038; Detail: ADIMPEX KTH00212; HPcode: SWTACT6X6L13; ContoLavoro: 0
footprint TACTSW_4.5x6.5 H13
pins: 1, 2, 3, 4

## SW_Tactile_8x8_h11mm_90deg_IP67
designator SW?
SW Tactile 8x8 IP67 90deg H_11mm; Costo: 0; Aggiornato: s
footprint TACTSW_8x8 IP67 90deg H_11mm
pins: 1, 2, S1, S2

## SWCAP5.5GREY
designator SWCAP?  (mechanical)
SWCAP5.5GREY Cappuccio per Switch; Costo: 0,02; Aggiornato: s; ContoLavoro: 1
pins: 1 hidden
1 alternate drawing of the same symbol


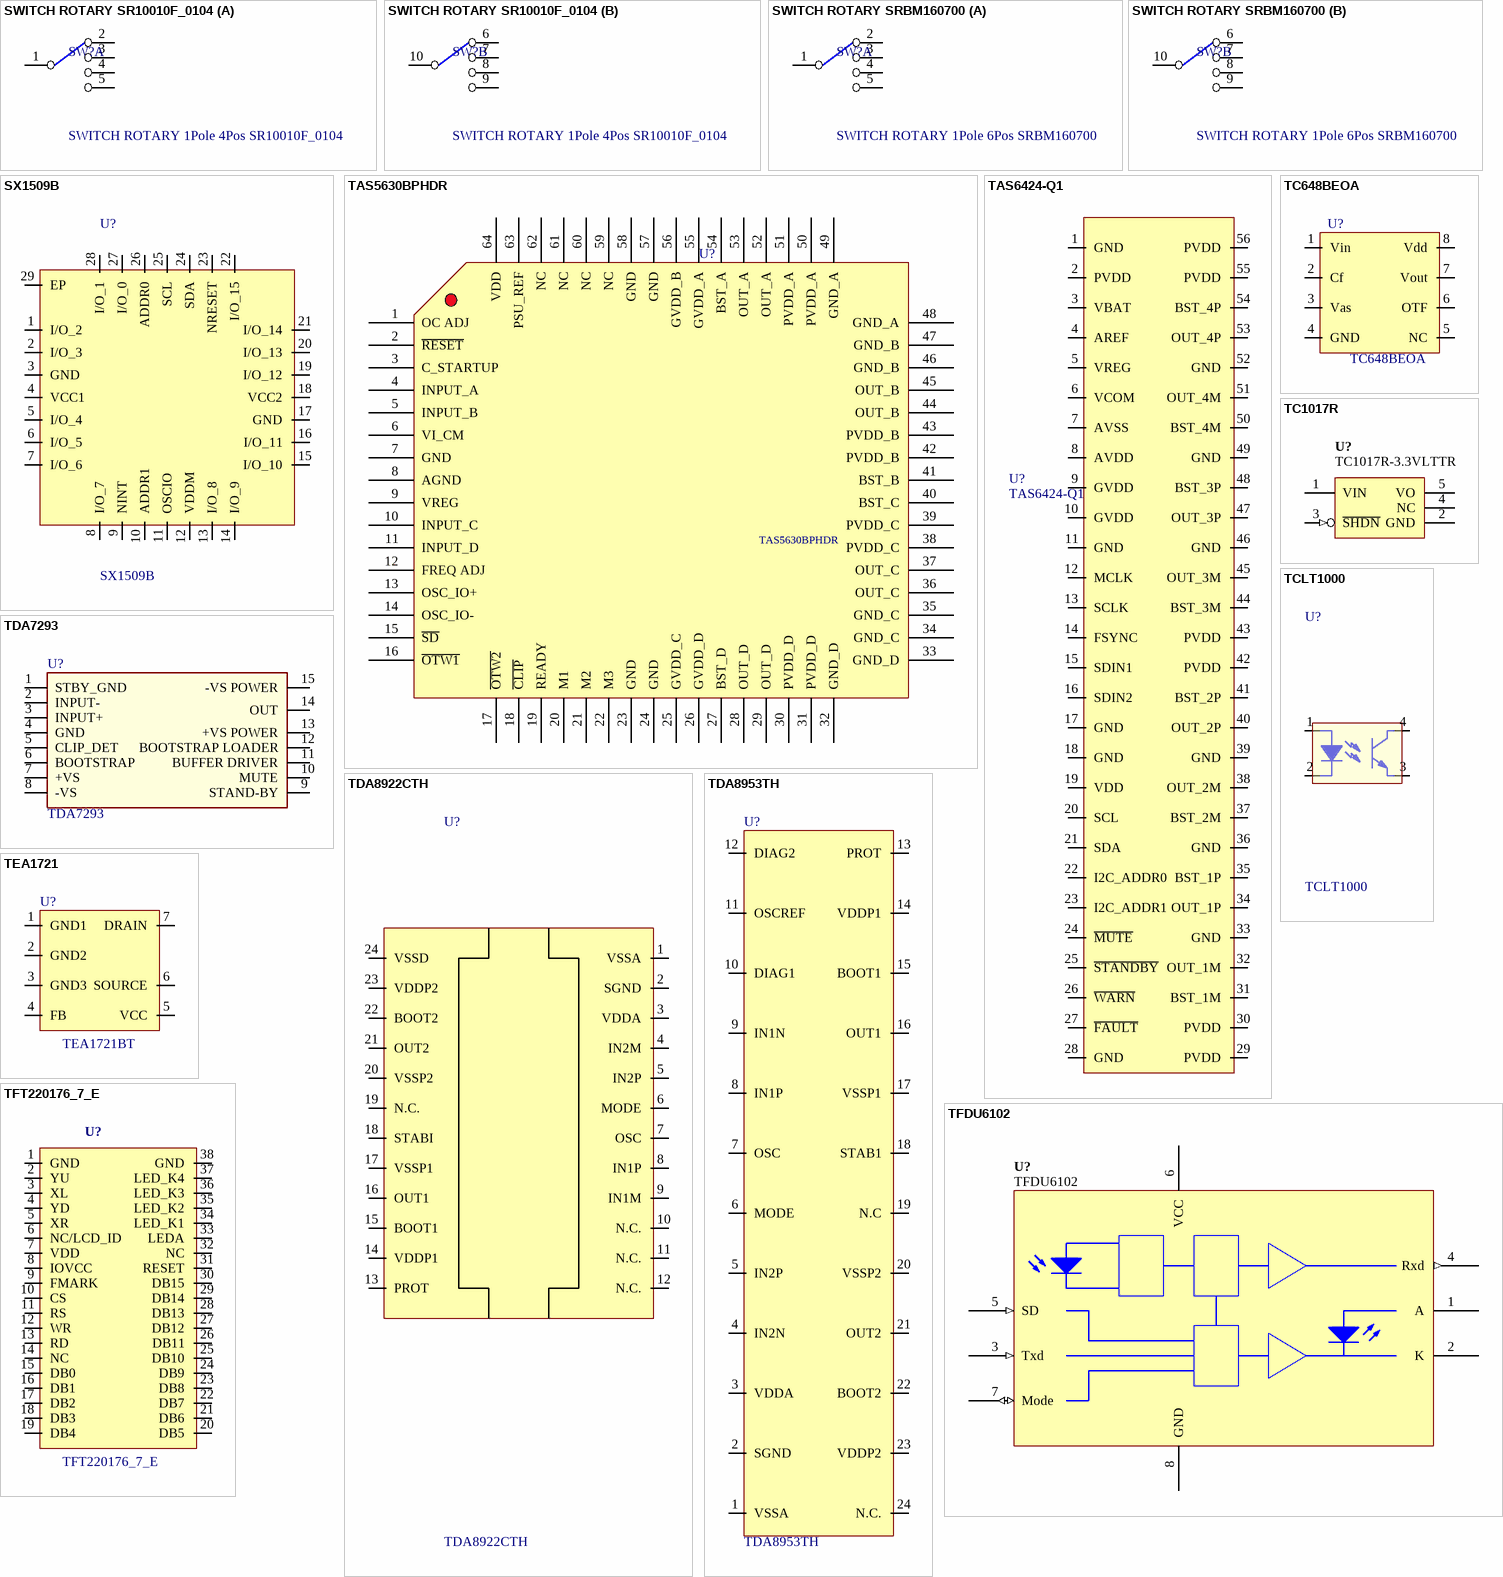
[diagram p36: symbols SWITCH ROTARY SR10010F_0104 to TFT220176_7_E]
## SWITCH ROTARY SR10010F_0104
designator SW?, comment SWITCH ROTARY 1Pole 4Pos SR10010F_0104
Costo: 9,30; Detail: € Mouser Pz>25; ContoLavoro: 0
footprint ROTARY SWITCH_1POLE_6POS (SRBM160700)
part A pins: 1 F1, 2 NC, 3 NC, 4 NC, 5 NC
part B pins: 6 R1, 7 R2, 8 R3, 9 R4, 10 R5

## SWITCH ROTARY SRBM160700
designator SW?, comment SWITCH ROTARY 1Pole 6Pos SRBM160700
Costo: 9,30; Detail: € Mouser Pz>25; ContoLavoro: 0
footprint ROTARY SWITCH_1POLE_6POS (SRBM160700)
part A pins: 1 F1, 2 NC, 3 NC, 4 F5, 5 F6
part B pins: 6 R1, 7 R2, 8 R3, 9 R4, 10 R5

## SX1509B
designator U?
Detail: €1,89 Mouser PZ>10; Costo: 1,89; Aggiornato: S; ContoLavoro: 0
footprint QFN28_EP_QFN-UP-28_SX1509B (QFN20_EP QFN-UP-28 SX1509B)
pins: 1 I/O_2, 2 I/O_3, 3 GND, 4 VCC1, 5 I/O_4, 6 I/O_5, 7 I/O_6, 8 I/O_7, 9 NINT, 10 ADDR1, 11 OSCIO, 12 VDDM, 13 I/O_8, 14 I/O_9, 15 I/O_10, 16 I/O_11, 17 GND, 18 VCC2, 19 I/O_12, 20 I/O_13, 21 I/O_14, 22 I/O_15, 23 NRESET, 24 SDA, 25 SCL, 26 ADDR0, 27 I/O_0, 28 I/O_1, 29 EP

## TAS5630BPHDR
designator U?
Detail: prezzo RS >10pz; Costo: 8,41; Aggiornato: SI; ContoLavoro: 1
footprint PQFP-64_08 pitch
pins: 1 OC ADJ, 2 ~{RESET}, 3 C_STARTUP, 4 INPUT_A, 5 INPUT_B, 6 VI_CM, 7 GND, 8 AGND, 9 VREG, 10 INPUT_C, 11 INPUT_D, 12 FREQ ADJ, 13 OSC_IO+, 14 OSC_IO-, 15 ~{SD}, 16 ~{OTW1}, 17 ~{OTW2}, 18 ~{CLIP}, 19 READY, 20 M1, 21 M2, 22 M3, 23 GND, 24 GND, 25 GVDD_C, 26 GVDD_D, 27 BST_D, 28 OUT_D, 29 OUT_D, 30 PVDD_D, 31 PVDD_D, 32 GND_D, 33 GND_D, 34 GND_C, 35 GND_C, 36 OUT_C, 37 OUT_C, 38 PVDD_C, 39 PVDD_C, 40 BST_C, 41 BST_B, 42 PVDD_B, 43 PVDD_B, 44 OUT_B, 45 OUT_B, 46 GND_B, 47 GND_B, 48 GND_A, 49 GND_A, 50 PVDD_A, 51 PVDD_A, 52 OUT_A, 53 OUT_A, 54 BST_A, 55 GVDD_A, 56 GVDD_B, 57 GND, 58 GND, 59 NC, 60 NC, 61 NC, 62 NC, 63 PSU_REF, 64 VDD

## TAS6424-Q1
designator U?
Detail: 4,96€ Costo standard Esolver 2018; HPcode: ICTAS6424-Q1; Aggiornato: SI; Costo: 4,96; ContoLavoro: 1
footprint HTSSOP_56
footprint HTSSOP_56
pins: 1 GND, 2 PVDD, 3 VBAT, 4 AREF, 5 VREG, 6 VCOM, 7 AVSS, 8 AVDD, 9 GVDD, 10 GVDD, 11 GND, 12 MCLK, 13 SCLK, 14 FSYNC, 15 SDIN1, 16 SDIN2, 17 GND, 18 GND, 19 VDD, 20 SCL, 21 SDA, 22 I2C_ADDR0, 23 I2C_ADDR1, 24 ~{MUTE}, 25 ~{STANDBY}, 26 ~{WARN}, 27 ~{FAULT} , 28 GND, 29 PVDD, 30 PVDD, 31 BST_1M, 32 OUT_1M, 33 GND, 34 OUT_1P, 35 BST_1P, 36 GND, 37 BST_2M, 38 OUT_2M, 39 GND, 40 OUT_2P, 41 BST_2P, 42 PVDD, 43 PVDD, 44 BST_3M, 45 OUT_3M, 46 GND, 47 OUT_3P, 48 BST_3P, 49 GND, 50 BST_4M, 51 OUT_4M, 52 GND, 53 OUT_4P, 54 BST_4P, 55 PVDD, 56 PVDD

## TC648BEOA
designator U?
Regolatore PWM; Costo: 0,757; Aggiornato: s; ContoLavoro: 0
footprint SO8
pins: 1 Vin, 2 Cf, 3 Vas, 4 GND, 5 NC, 6 OTF, 7 Vout, 8 Vdd

## TC1017R
designator U?, comment TC1017R-3.3VLTTR
TC1017R-3.3VLTTR, 3.3V Micropower Low Dropout Regulator, 5-Pin SC70-5; Max Input Voltage: 5.5 V; Max Output Current: 150 mA; Min Input Voltage: mV; Supply Voltage: V; Aggiornato: NO; Costo: 0
footprint SOT65P210X80-5N
pins: 1 VIN (power), 2 GND (power), 3 ~{SHDN} (in), 4 NC, 5 VO (power)

## TCLT1000
designator U?
Phototransistor optically / coupled to a gallium arsenide infrared-emitting diode in a / 4 lead SOP4L package; Costo: 0,376; ContoLavoro: 0
footprint SOP-4L_TC
pins: 1, 2, 3, 4

## TDA7293
designator U?
Costo: 0; Aggiornato: NO
footprint MULTIWATT15V
pins: 1 STBY_GND, 2 INPUT-, 3 INPUT+, 4 GND, 5 CLIP_DET, 6 BOOTSTRAP, 7 +VS, 8 -VS, 9 STAND-BY, 10 MUTE, 11 BUFFER DRIVER, 12 BOOTSTRAP LOADER, 13 +VS POWER, 14 OUT, 15 -VS POWER

## TDA8922CTH
designator U?
Detail: quota NXP da Balzi Avnet per 500pz 14wks; Hpcode: ICTDA8922CTH; Aggiornato: NO; Costo: 1,55; ContoLavoro: 1
footprint HSOP24
pins: 1 VSSA, 2 SGND, 3 VDDA, 4 IN2M, 5 IN2P, 6 MODE, 7 OSC, 8 IN1P, 9 IN1M, 10 N.C., 11 N.C., 12 N.C., 13 PROT, 14 VDDP1, 15 BOOT1, 16 OUT1, 17 VSSP1, 18 STABI, 19 N.C., 20 VSSP2, 21 OUT2, 22 BOOT2, 23 VDDP2, 24 VSSD

## TDA8953TH
designator U?
Aggiornato: NO; Costo: 0
footprint HSOP24
pins: 1 VSSA, 2 SGND, 3 VDDA, 4 IN2N, 5 IN2P, 6 MODE, 7 OSC, 8 IN1P, 9 IN1N, 10 DIAG1, 11 OSCREF, 12 DIAG2, 13 PROT, 14 VDDP1, 15 BOOT1, 16 OUT1, 17 VSSP1, 18 STAB1, 19 N.C, 20 VSSP2, 21 OUT2, 22 BOOT2, 23 VDDP2, 24 N.C.

## TEA1721
designator U?, comment TEA1721BT
Costo: 0,24; Aggiornato: NO; ContoLavoro: 0
footprint SO8
footprint SO7
pins: 1 GND1, 2 GND2, 3 GND3, 4 FB, 5 VCC, 6 SOURCE, 7 DRAIN

## TFDU6102
designator U?
LED, TFDU6102 Infrared Transceiver up to 4Mbits/s; Aggiornato: NO; Costo: 0
footprint TFDU6102
pins: 1 A (power) "IRED Anode, should be externally connected to VCC2 through a current control resistor", 2 K "IRED Cathode, internally connected to driver transistor", 3 Txd (in) "Transmit Data Input", 4 Rxd (out) "Received Data Output, Open Collector. No external pull-up or pull-down resistor required. Output data invalid during transmission.", 5 SD (in) "Shut Down", 6 VCC (power) "Supply Voltage", 7 Mode (io) "Speed Mode", 8 GND (power) "Ground"

## TFT220176_7_E
designator U?
Aggiornato: NO; Costo: 0
footprint TFT220176_7_E
pins: 1 GND, 2 YU, 3 XL, 4 YD, 5 XR, 6 NC/LCD_ID, 7 VDD, 8 IOVCC, 9 FMARK, 10 CS, 11 RS, 12 WR, 13 RD, 14 NC, 15 DB0, 16 DB1, 17 DB2, 18 DB3, 19 DB4, 20 DB5, 21 DB6, 22 DB7, 23 DB8, 24 DB9, 25 DB10, 26 DB11, 27 DB12, 28 DB13, 29 DB14, 30 DB15, 31 RESET, 32 NC, 33 LEDA, 34 LED_K1, 35 LED_K2, 36 LED_K3, 37 LED_K4, 38 GND


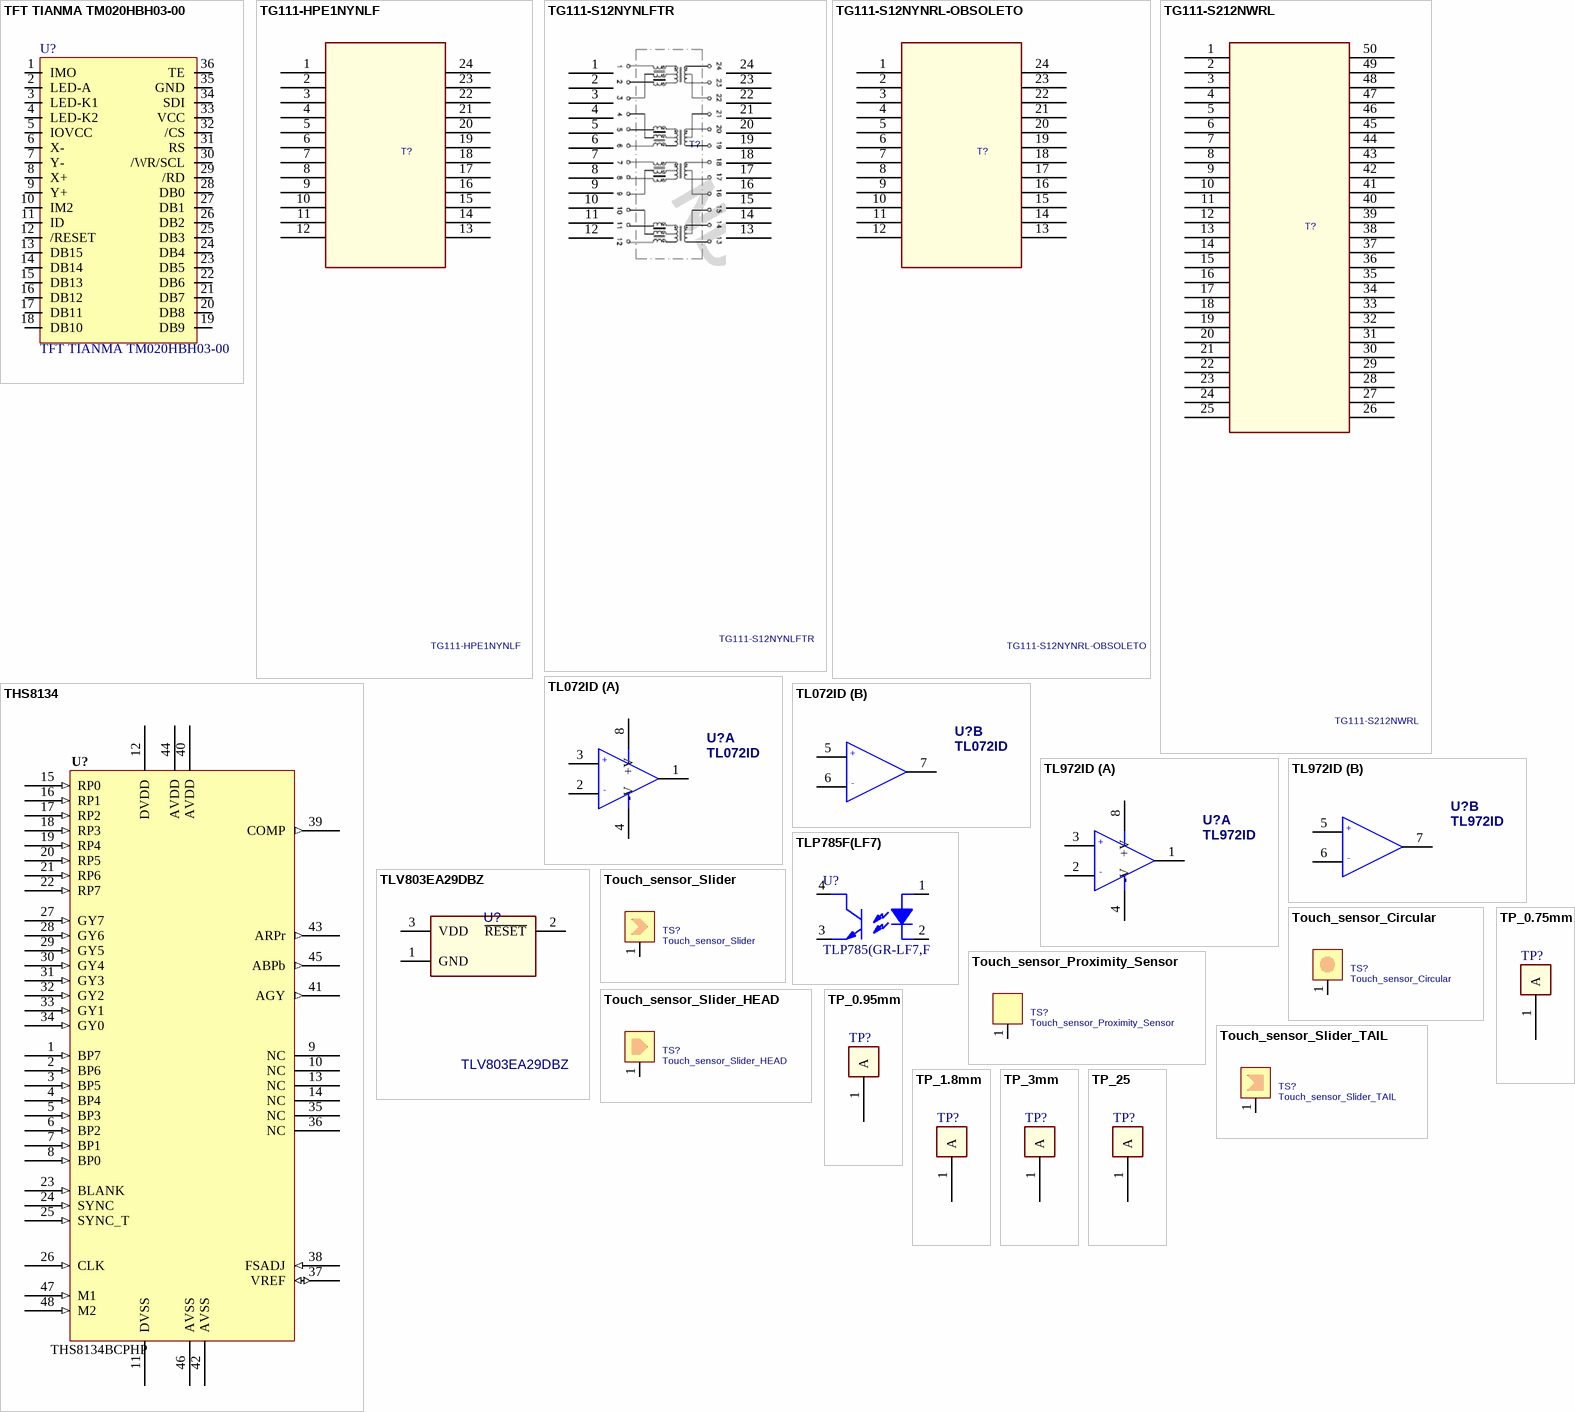
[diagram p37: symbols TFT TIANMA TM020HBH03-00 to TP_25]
## TFT TIANMA TM020HBH03-00
designator U?
Hpcode: LCD0200001; Aggiornato: NO; Costo: 0
footprint TFT TIANMA TM020HBH03-00 (Footprint not found)
pins: 1 IMO, 2 LED-A, 3 LED-K1, 4 LED-K2, 5 IOVCC, 6 X-, 7 Y-, 8 X+, 9 Y+, 10 IM2, 11 ID, 12 /RESET, 13 DB15, 14 DB14, 15 DB13, 16 DB12, 17 DB11, 18 DB10, 19 DB9, 20 DB8, 21 DB7, 22 DB6, 23 DB5, 24 DB4, 25 DB3, 26 DB2, 27 DB1, 28 DB0, 29 /RD, 30 /WR/SCL, 31 RS, 32 /CS, 33 VCC, 34 SDI, 35 GND, 36 TE

## TG111-HPE1NYNLF
designator T?
Aggiornato: NO; Costo: 0
footprint TG111-24pin
pins: 1 RD1+, 2 RCT1, 3 RD1-, 4 TD1+, 5 TCT1, 6 TD1-, 7 TD2+, 8 TCT2, 9 TD2-, 10 RD2+, 11 RCT2, 12 RD2-, 13 RX2-, 14 RXCT2, 15 RX2+, 16 TX2-, 17 TXCT2, 18 TX2+, 19 TX1-, 20 TXCT1, 21 TX1+, 22 RX1-, 23 RXCT1, 24 RX1+

## TG111-S12NYNLFTR
designator T?
Hpcode: ICTG111S12NYNLFTR; Aggiornato: NO; Costo: 2,1; ContoLavoro: 1
footprint TG111-24pin
pins: 1 RD1+, 2 RCT1, 3 RD1-, 4 TD1+, 5 TCT1, 6 TD1-, 7 TD2+, 8 TCT2, 9 TD2-, 10 RD2+, 11 RCT2, 12 RD2-, 13 RX2-, 14 RXCT2, 15 RX2+, 16 TX2-, 17 TXCT2, 18 TX2+, 19 TX1-, 20 TXCT1, 21 TX1+, 22 RX1-, 23 RXCT1, 24 RX1+

## TG111-S12NYNRL-OBSOLETO
designator T?
TG111-S12NYNRL; Aggiornato: NO; Costo: 0; Detail: OBSOLETO sostituito da TG111-S12NYNLFTR
footprint TG111-24pin
pins: 1 RD1+, 2 RCT1, 3 RD1-, 4 TD1+, 5 TCT1, 6 TD1-, 7 TD2+, 8 TCT2, 9 TD2-, 10 RD2+, 11 RCT2, 12 RD2-, 13 RX2-, 14 RXCT2, 15 RX2+, 16 TX2-, 17 TXCT2, 18 TX2+, 19 TX1-, 20 TXCT1, 21 TX1+, 22 RX1-, 23 RXCT1, 24 RX1+

## TG111-S212NWRL
designator T?
Aggiornato: NO; Costo: 0
footprint TG111-S212NWRL (Footprint not found)
pins: 1, 2, 3, 4, 5, 6, 7, 8, 9, 10, 11, 12, 13, 14, 15, 16, 17, 18, 19, 20, 21, 22, 23, 24, 25, 26, 27, 28, 29, 30, 31, 32, 33, 34, 35, 36, 37, 38, 39, 40, 41, 42, 43, 44, 45, 46, 47, 48, 49, 50

## THS8134
designator U?, comment THS8134BCPHP
THS8134BCPHP, Triple 8-Bit, 80 MSPS Video DAC with Tri-Level Sync Generation; Aggiornato: NO; Costo: 0
footprint TSQFP50P900X900_HS-48
pins: 1 BP7 (in), 2 BP6 (in), 3 BP5 (in), 4 BP4 (in), 5 BP3 (in), 6 BP2 (in), 7 BP1 (in), 8 BP0 (in), 9 NC, 10 NC, 11 DVSS (power), 12 DVDD (power), 13 NC, 14 NC, 15 RP0 (in), 16 RP1 (in), 17 RP2 (in), 18 RP3 (in), 19 RP4 (in), 20 RP5 (in), 21 RP6 (in), 22 RP7 (in), 23 BLANK (in), 24 SYNC (in), 25 SYNC_T (in), 26 CLK (in), 27 GY7 (in), 28 GY6 (in), 29 GY5 (in), 30 GY4 (in), 31 GY3 (in), 32 GY2 (in), 33 GY1 (in), 34 GY0 (in), 35 NC, 36 NC, 37 VREF (io), 38 FSADJ (in), 39 COMP (out), 40 AVDD (power), 41 AGY (out), 42 AVSS (power), 43 ARPr (out), 44 AVDD (power), 45 ABPb (out), 46 AVSS (power), 47 M1 (in), 48 M2 (in)

## TL072ID
designator U?
Costo: 0,15; Aggiornato: S; ContoLavoro: 0
footprint SO8
simulation model TL072
footprint SOIC150-8N
part A pins: 1 OUT, 2 -IN, 3 +IN, 4 -V, 8 +V
part B pins: 5 +IN, 6 -IN, 7 OUT

## TL972ID
designator U?
TL972ID SMD DUAL OP AMP; Detail: € RS>100pz; Costo: 0,316; Aggiornato: N; ContoLavoro: 0
footprint SO8
simulation model TL072
footprint SOIC150-8N
part A pins: 1 OUT, 2 -IN, 3 +IN, 4 -V (power), 8 +V (power)
part B pins: 5 +IN, 6 -IN, 7 OUT

## TLP785F(LF7)
designator U?, comment TLP785(GR-LF7,F
TLP785(GR-LF7,F 4 pin smd; Costo: 0,109; Aggiornato: Si; Detail: Costo RS per 100 pz.; ContoLavoro: 0
footprint Toshiba 11-5L107 (Footprint per TLP785F(LF7))
pins: 1, 2, 3, 4

## TLV803EA29DBZ
designator U?
MPN: 595-TLV803EA29DBZR; Detail: 0,22€ Mouser Pz>100; Costo: 0,22; DeviceFunction: Supply Voltage Supervisor ( reset IC ); Aggiornato: S; ContoLavoro: 0
footprint SOT-23_UP
pins: 1 GND, 2 ~{RESET}, 3 VDD

## Touch_sensor_Circular
designator TS?  (no BOM)
Costo: 0; Aggiornato: NO
footprint Touch_sensor_Circular_D11mm
footprint Touch_sensor_Circular_D15mm
footprint Touch_sensor_Circular_D20mm
pins: 1

## Touch_sensor_Proximity_Sensor
designator TS?  (no BOM)
Costo: 0; Aggiornato: NO
footprint Touch_sensor_Proximity_Sensor
pins: 1

## Touch_sensor_Slider
designator TS?  (no BOM)
Costo: 0; Aggiornato: NO
footprint Touch_sensor_Slider_H15mm_L30mm
pins: 1

## Touch_sensor_Slider_HEAD
designator TS?  (no BOM)
Costo: 0; Aggiornato: NO
footprint Touch_sensor_Slider_H15mm_L30mm_HEAD
pins: 1

## Touch_sensor_Slider_TAIL
designator TS?  (no BOM)
Costo: 0; Aggiornato: NO
footprint Touch_sensor_Slider_H15mm_L30mm_TAIL
pins: 1

## TP_0.75mm
designator TP?  (no BOM)
Costo: 0; Aggiornato: NO
footprint TEST_POINT_0.75MM ROUND
pins: 1 A

## TP_0.95mm
designator TP?  (no BOM)
Costo: 0; Aggiornato: NO
footprint TEST_POINT_0.95MM ROUND
pins: 1 A

## TP_1.8mm
designator TP?  (no BOM)
Costo: 0; Aggiornato: NO
footprint TEST_POINT_1.8MM
pins: 1 A

## TP_3mm
designator TP?  (no BOM)
Costo: 0; Aggiornato: NO
footprint TEST_POINT_3MM
pins: 1 A

## TP_25
designator TP?  (no BOM)
Costo: 0; Aggiornato: NO
footprint TESTPOINT_25
pins: 1 A


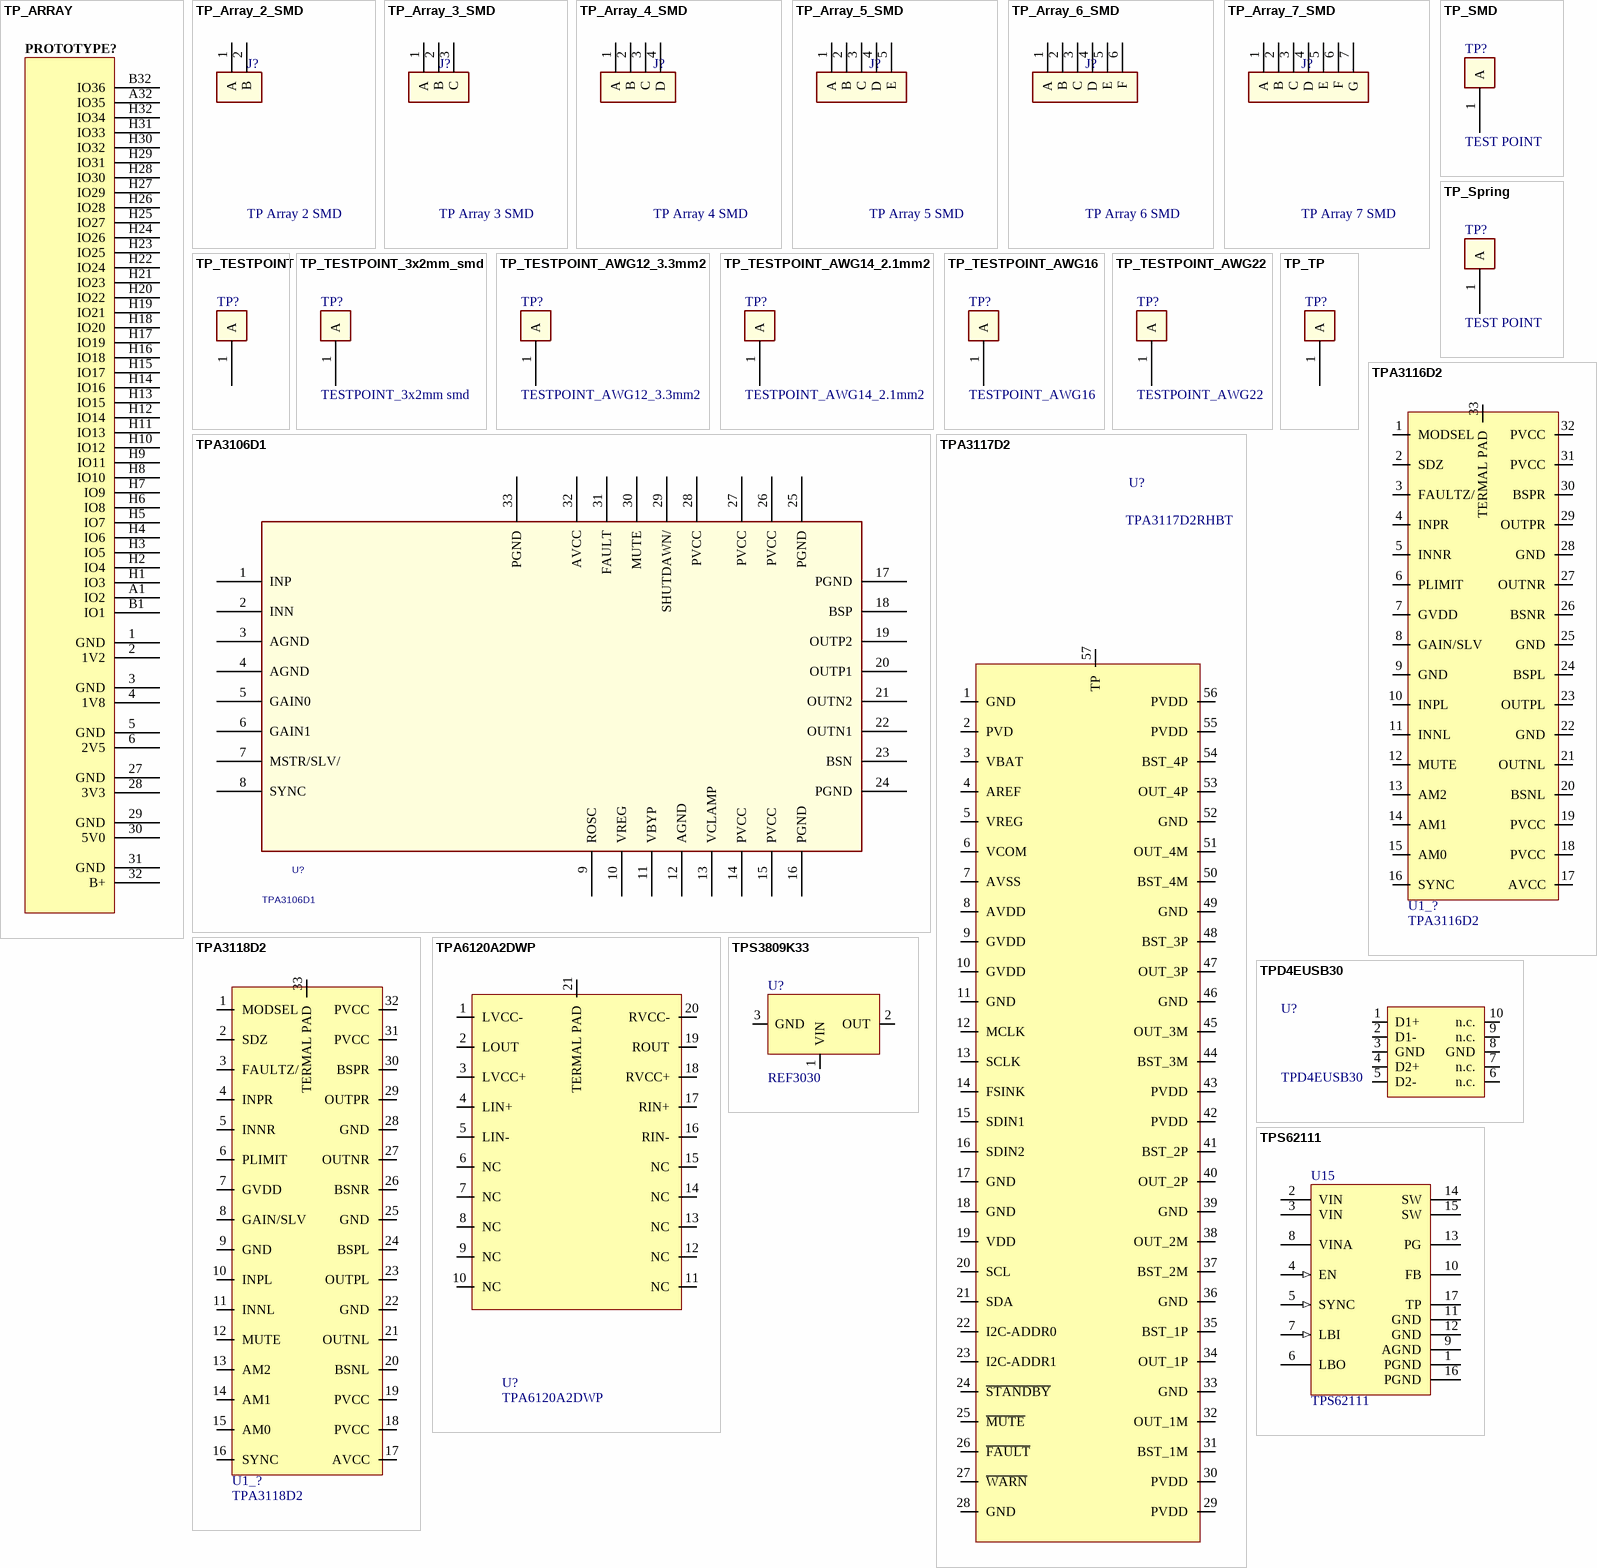
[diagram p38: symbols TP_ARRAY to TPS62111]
## TP_ARRAY
designator PROTOTYPE?  (no BOM)
Test Point Array; Aggiornato: NO; Costo: 0
footprint TESTPOINT_ARRAY (Footprint not found)
pins: 1 GND (power), 2 1V2 (power), 3 GND (power), 4 1V8 (power), 5 GND (power), 6 2V5 (power), 27 GND (power), 28 3V3 (power), 29 GND (power), 30 5V0 (power), 31 GND (power), 32 B+ (power), A1 IO2, A32 IO35, B1 IO1, B32 IO36, H1 IO3, H2 IO4, H3 IO5, H4 IO6, H5 IO7, H6 IO8, H7 IO9, H8 IO10, H9 IO11, H10 IO12, H11 IO13, H12 IO14, H13 IO15, H14 IO16, H15 IO17, H16 IO18, H17 IO19, H18 IO20, H19 IO21, H20 IO22, H21 IO23, H22 IO24, H23 IO25, H24 IO26, H25 IO27, H26 IO28, H27 IO29, H28 IO30, H29 IO31, H30 IO32, H31 IO33, H32 IO34

## TP_Array_2_SMD
designator J?, comment TP Array 2 SMD
Aggiornato: NO; Costo: 0
footprint TP_Array_2_SMD_2mm
pins: 1 A, 2 B

## TP_Array_3_SMD
designator J?, comment TP Array 3 SMD
Aggiornato: NO; Costo: 0
footprint TP_Array_3_SMD_2mm (Footprint not found)
pins: 1 A, 2 B, 3 C

## TP_Array_4_SMD
designator J?, comment TP Array 4 SMD
Aggiornato: NO; Costo: 0
footprint TP_Array_4_SMD_2mm (Footprint not found)
pins: 1 A, 2 B, 3 C, 4 D

## TP_Array_5_SMD
designator J?, comment TP Array 5 SMD
Aggiornato: NO; Costo: 0
footprint TP_Array_5_SMD_2mm (Footprint not found)
pins: 1 A, 2 B, 3 C, 4 D, 5 E

## TP_Array_6_SMD
designator J?, comment TP Array 6 SMD
Aggiornato: NO; Costo: 0
footprint TP_Array_6_SMD_2mm
pins: 1 A, 2 B, 3 C, 4 D, 5 E, 6 F

## TP_Array_7_SMD
designator J?, comment TP Array 7 SMD
Aggiornato: NO; Costo: 0
footprint TP_Array_7_SMD_2mm (Footprint not found)
pins: 1 A, 2 B, 3 C, 4 D, 5 E, 6 F, 7 G

## TP_SMD
designator TP?, comment TEST POINT  (no BOM)
TEST POINT SMD; Costo: 0; Aggiornato: s
footprint TESTPOINT_SMD_1mmx1mm
footprint TESTPOINT_SMD_1mm_round
footprint TESTPOINT_SMD_2mmx1.5mm
footprint TESTPOINT_SMD_2.5mmx1.5mm
footprint TESTPOINT_SMD_3mmx3mm
footprint TESTPOINT_SMD_DW
pins: 1 A

## TP_Spring
designator TP?, comment TEST POINT  (no BOM)
TEST POINT Spring; Costo: 0; Aggiornato: s
footprint TESTPOINT_spring
pins: 1 A

## TP_TESTPOINT
designator TP?  (no BOM)
Costo: 0; Aggiornato: NO
footprint TESTPOINT
pins: 1 A

## TP_TESTPOINT_3x2mm_smd
designator TP?, comment TESTPOINT_3x2mm smd  (no BOM)
Costo: 0; Aggiornato: NO
footprint TESTPOINT_SMD_3mmx2mm
pins: 1 A

## TP_TESTPOINT_AWG12_3.3mm2
designator TP?, comment TESTPOINT_AWG12_3.3mm2  (no BOM)
Costo: 0; Aggiornato: SI
footprint TEST_POINT_AWG12
pins: 1 A

## TP_TESTPOINT_AWG14_2.1mm2
designator TP?, comment TESTPOINT_AWG14_2.1mm2  (no BOM)
Costo: 0; Aggiornato: SI
footprint TEST_POINT_AWG14 (Footprint not found)
pins: 1 A

## TP_TESTPOINT_AWG16
designator TP?, comment TESTPOINT_AWG16  (no BOM)
Costo: 0; Aggiornato: SI
footprint TEST_POINT_AWG16
pins: 1 A

## TP_TESTPOINT_AWG22
designator TP?, comment TESTPOINT_AWG22  (no BOM)
Costo: 0; Aggiornato: SI
footprint TEST_POINT_AWG22 (Footprint not found)
pins: 1 A

## TP_TP
designator TP?  (no BOM)
Costo: 0; Aggiornato: NO
footprint TP
pins: 1 A

## TPA3106D1
designator U?
Aggiornato: NO; Costo: 0
footprint LQFP-32
pins: 1 INP, 2 INN, 3 AGND, 4 AGND, 5 GAIN0, 6 GAIN1, 7 MSTR/SLV/, 8 SYNC, 9 ROSC, 10 VREG, 11 VBYP, 12 AGND, 13 VCLAMP, 14 PVCC, 15 PVCC, 16 PGND, 17 PGND, 18 BSP, 19 OUTP2, 20 OUTP1, 21 OUTN2, 22 OUTN1, 23 BSN, 24 PGND, 25 PGND, 26 PVCC, 27 PVCC, 28 PVCC, 29 SHUTDAWN/, 30 MUTE, 31 FAULT, 32 AVCC, 33 PGND

## TPA3116D2
designator U1_?
Detail: prezzo Avnet balzi per 2000pz, 2,05 per 46pz; Aggiornato: SI; Costo: 1,67; ContoLavoro: 1
footprint PDSO_G32
pins: 1 MODSEL, 2 SDZ, 3 FAULTZ/, 4 INPR, 5 INNR, 6 PLIMIT, 7 GVDD, 8 GAIN/SLV, 9 GND, 10 INPL, 11 INNL, 12 MUTE, 13 AM2, 14 AM1, 15 AM0, 16 SYNC, 17 AVCC, 18 PVCC, 19 PVCC, 20 BSNL, 21 OUTNL, 22 GND, 23 OUTPL, 24 BSPL, 25 GND, 26 BSNR, 27 OUTNR, 28 GND, 29 OUTPR, 30 BSPR, 31 PVCC, 32 PVCC, 33 TERMAL PAD

## TPA3117D2
designator U?, comment TPA3117D2RHBT
Aggiornato: NO; Costo: 1,50; ContoLavoro: 0
footprint S-PVQFN-N32
pins: 1 GND, 2 PVD, 3 VBAT, 4 AREF, 5 VREG, 6 VCOM, 7 AVSS, 8 AVDD, 9 GVDD, 10 GVDD, 11 GND, 12 MCLK, 13 SCLK, 14 FSINK, 15 SDIN1, 16 SDIN2, 17 GND, 18 GND, 19 VDD, 20 SCL, 21 SDA, 22 I2C-ADDR0, 23 I2C-ADDR1, 24 ~{STANDBY}, 25 ~{MUTE}, 26 ~{FAULT}, 27 ~{WARN}, 28 GND, 29 PVDD, 30 PVDD, 31 BST_1M, 32 OUT_1M, 33 GND, 34 OUT_1P, 35 BST_1P, 36 GND, 37 BST_2M, 38 OUT_2M, 39 GND, 40 OUT_2P, 41 BST_2P, 42 PVDD, 43 PVDD, 44 BST_3M, 45 OUT_3M, 46 GND, 47 OUT_3P, 48 BST_3P, 49 GND, 50 BST_4M, 51 OUT_4M, 52 GND, 53 OUT_4P, 54 BST_4P, 55 PVDD, 56 PVDD, 57 TP

## TPA3118D2
designator U1_?
Detail: prezzo Avnet balzi per 2000pz, 2,05 per 46pz; Aggiornato: SI; Costo: 1,67; ContoLavoro: 1
footprint PDSO_G32
pins: 1 MODSEL, 2 SDZ, 3 FAULTZ/, 4 INPR, 5 INNR, 6 PLIMIT, 7 GVDD, 8 GAIN/SLV, 9 GND, 10 INPL, 11 INNL, 12 MUTE, 13 AM2, 14 AM1, 15 AM0, 16 SYNC, 17 AVCC, 18 PVCC, 19 PVCC, 20 BSNL, 21 OUTNL, 22 GND, 23 OUTPL, 24 BSPL, 25 GND, 26 BSNR, 27 OUTNR, 28 GND, 29 OUTPR, 30 BSPR, 31 PVCC, 32 PVCC, 33 TERMAL PAD

## TPA6120A2DWP
designator U?
Aggiornato: N; Costo: 0
footprint HSOP20_THERMALPAD (HSOP20_ThermalPad TPA6120A2DWP)
pins: 1 LVCC-, 2 LOUT, 3 LVCC+, 4 LIN+, 5 LIN-, 6 NC, 7 NC, 8 NC, 9 NC, 10 NC, 11 NC, 12 NC, 13 NC, 14 NC, 15 NC, 16 RIN-, 17 RIN+, 18 RVCC+, 19 ROUT, 20 RVCC-, 21 TERMAL PAD

## TPD4EUSB30
designator U?
Costo: 0,4; Aggiornato: s; ContoLavoro: 0
footprint USON10_TPD4EUSB30 (Footprint not found)
pins: 1 D1+, 2 D1-, 3 GND, 4 D2+, 5 D2-, 6 n.c., 7 n.c., 8 GND, 9 n.c., 10 n.c.

## TPS3809K33
designator U?, comment REF3030
Aggiornato: NO; Costo: 0
footprint SOT-23_UP
pins: 1 VIN, 2 OUT, 3 GND

## TPS62111
designator U15
TPS62111 Switching Regulator 16-Pin QFN; Aggiornato: S; Costo: 0
footprint RSA16-2700X2700TP (QFN, 16-Leads, Body 4x4mm, Pitch 0.65mm, Thermal Pad 2.7x2.7mm, TI Recommended)
pins: 1 PGND (power) "Power ground. Connect all power grounds to this pin.", 2 VIN (power) "Supply voltage input (power stage).", 3 VIN (power) "Supply voltage input (power stage).", 4 EN (in) "Enable. A logic high enables the converter; logic low forces the device into shutdown mode reducing the supply current to less than 2 µ A.", 5 SYNC (in) "Input for synchronization to external clock signal. Synchronizes the converter switching frequency to anexternal clock signal with CMOS level: SYNC = HIGH: Low-noise mode enabled, fixed frequency PWM operation is forced. (See Datasheet)", 6 LBO (hiz) "Open-drain, low-battery output. This pin is pulled low if LBI is below its threshold.", 7 LBI (in) "Low-battery input.", 8 VINA (power) "Supply voltage input (support circuits).", 9 AGND (power) "Analog ground, connect to GND and PGND.", 10 FB "Feedback pin for the fixed output voltage option. For the adjustable version, an external resistive divider is connected to this pin. The internal voltage divider is disabled for the adjustable version.", 11 GND (power) "Ground.", 12 GND (power) "Ground.", 13 PG (oc) "Power good comparator output. This is an open-drain output. A pullup resistor should be connected between PG and VOUT. The output goes active high when the output voltage is greater than 98.4% of the nominal value.", 14 SW (power) "Connect the inductor to this pin. This pin is the switch pin and connected to the drain of the internal power MOSFETS.", 15 SW (power) "Connect the inductor to this pin. This pin is the switch pin and connected to the drain of the internal power MOSFETS.", 16 PGND (power) "Power ground. Connect all power grounds to this pin.", 17 TP (power) "Connect to AGND."


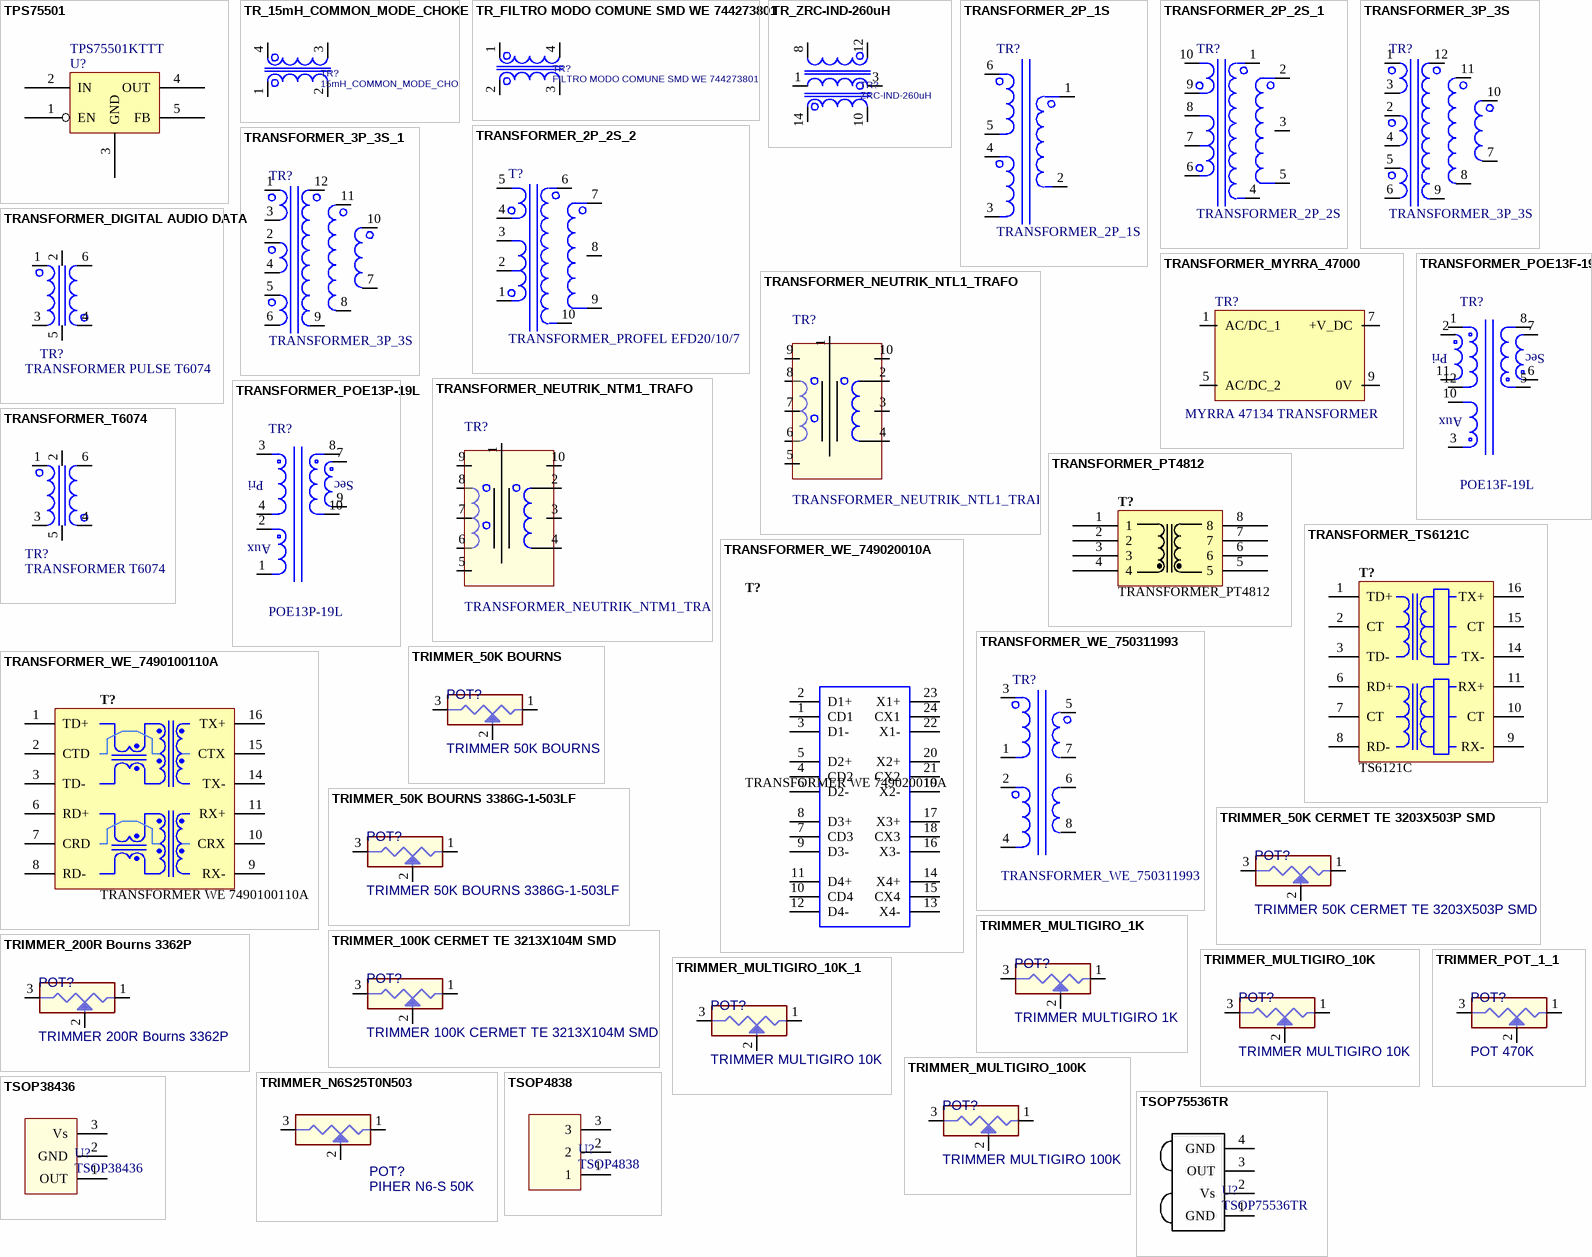
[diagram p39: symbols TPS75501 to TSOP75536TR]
## TPS75501
designator U?, comment TPS75501KTTT
TPS75501KTTT, 5A, Low Dropout, Adjustable, Linear Voltage Regulator, TO-263; Max Input Voltage: 6 V; Max Output Voltage: 5.5 V; Min Input Voltage: 1 V; Supply Voltage: mV; Aggiornato: NO; Costo: 0
footprint TO-263
pins: 1 EN, 2 IN, 3 GND, 4 OUT, 5 FB

## TR_15mH_COMMON_MODE_CHOKE
designator TR?, comment 15mH_COMMON_MODE_CHOKE
TRA_15mH_COMMON_MODE_CHOKE; Costo: 0; Inductance: 15mH; Value: 15mH; Aggiornato: NO
pins: 1, 2, 3, 4

## TR_FILTRO MODO COMUNE SMD WE 744273801
designator TR?, comment FILTRO MODO COMUNE SMD WE 744273801
Costo: 3,08; Inductance: 15uH; Value: 9uH; Aggiornato: SI; Detail: prezzo RS >10pz; ContoLavoro: 0
footprint FILTRO MODO COMUNE SMD WE 744273801
pins: 1, 2, 3, 4

## TR_ZRC-IND-260uH
designator TR?, comment ZRC-IND-260uH
TR_ZRC-IND-260uH INDUCTOR TWO SLOT BOBBIN; Costo: 0; Inductance: 260uH; Value: 260uH; Aggiornato: NO
pins: 1, 3, 8, 10, 12, 14

## TRANSFORMER_2P_1S
designator TR?
Costo: 0; Aggiornato: NO
footprint TRANSFORMER_BLOCK_VC 5/2/24
pins: 1 IN1, 2 IN2, 3 OUT1, 4 OUT2, 5 OUT3, 6 OUT4

## TRANSFORMER_2P_2S_1
designator TR?, comment TRANSFORMER_2P_2S
Aggiornato: NO; Costo: 0
footprint TRANSFORMER_EFD15_10PIN
pins: 1 OUT12, 2 OUT11, 3 OUT10, 4 OUT9, 5 OUT8, 6 IN5, 7 IN4, 8 IN2, 9 IN3, 10 IN1

## TRANSFORMER_2P_2S_2
designator T?, comment TRANSFORMER_PROFEL EFD20/10/7
Aggiornato: NO; Costo: 0
footprint TRANSFORMER_EFD20/10/7
pins: 1 IN1_1, 2 IN1_2, 3 IN1_3, 4 IN2_1, 5 IN2_2, 6 OUT1_2, 7 OUT2_3, 8 OUT2_2, 9 OUT2_1, 10 OUT1_1

## TRANSFORMER_3P_3S
designator TR?
Aggiornato: NO; Costo: 0
footprint TRANSFORMER_WE_750311715
pins: 1 IN1, 2 IN2, 3 IN3, 4 IN4, 5 IN5, 6 IN6, 7 OUT7, 8 OUT8, 9 OUT9, 10 OUT10, 11 OUT11, 12 OUT12

## TRANSFORMER_3P_3S_1
designator TR?, comment TRANSFORMER_3P_3S
Aggiornato: NO; Costo: 0
footprint TRANSFORMER_EFD15
pins: 1 IN1, 2 IN2, 3 IN3, 4 IN4, 5 IN5, 6 IN6, 7 OUT7, 8 OUT8, 9 OUT9, 10 OUT10, 11 OUT11, 12 OUT12

## TRANSFORMER_DIGITAL AUDIO DATA
designator TR?, comment TRANSFORMER PULSE T6074
Hpcode: AVH1102; Costo: 0; Aggiornato: NO
footprint TRANSFORMER DIGAUDIO
pins: 1 IN1, 2 IN2, 3 IN3, 4 OUT3, 5 OUT2, 6 OUT1

## TRANSFORMER_MYRRA_47000
designator TR?, comment MYRRA 47134 TRANSFORMER
Costo: 3,2; HPcode: TRANSF0002; Aggiornato: NO; ContoLavoro: 0
footprint MYRRA_47000
pins: 1 AC/DC_1, 5 AC/DC_2, 7 +V_DC, 9 0V

## TRANSFORMER_NEUTRIK_NTL1_TRAFO
designator TR?
Costo: 41,77; Detail: Leading Technology NENTL1; HPcode: TRANSF0004; Aggiornato: SI; ContoLavoro: 1
footprint TRANSFORMER NEUTRIK
pins: 1, 2, 3, 4, 5, 6, 7, 8, 9, 10

## TRANSFORMER_NEUTRIK_NTM1_TRAFO
designator TR?
Costo: 41,77; Detail: Leading Technology NENTM1; HPcode: da codificare; Aggiornato: SI; ContoLavoro: 1
footprint TRANSFORMER NEUTRIK
pins: 1, 2, 3, 4, 5, 6, 7, 8, 9, 10

## TRANSFORMER_POE13F-19L
designator TR?, comment POE13F-19L
TRANSFORMER POE13F-19L; Costo: 3; Aggiornato: NO; ContoLavoro: 0
footprint TRANSFORMER_POE13F_xxL
pins: 1, 2, 3, 5, 6, 7, 8, 10, 11, 12

## TRANSFORMER_POE13P-19L
designator TR?, comment POE13P-19L
TRANSFORMER POE13P-19L; Costo: 3; Aggiornato: NO; ContoLavoro: 0
footprint TRANSFORMER_POE13p_xxL (TRANSFORMER_POE13P_xxL)
pins: 1, 2, 3, 4, 7, 8, 9, 10

## TRANSFORMER_PT4812
designator T?
Transformer, 1:1, SMD, 0 to 70 deg C,  1 to 7 Mbps, 500Vrms min; Aggiornato: NO; Costo: 0
footprint PT4812
pins: 1, 2, 3, 4, 5, 6, 7, 8

## TRANSFORMER_T6074
designator TR?, comment TRANSFORMER T6074
Hpcode: AVH1102; Costo: 1,05; ContoLavoro: 1
footprint TRANSFORMER DIGAUDIO
pins: 1 IN1, 2 IN2, 3 IN3, 4 OUT3, 5 OUT2, 6 OUT1

## TRANSFORMER_TS6121C
designator T?, comment TS6121C
Transformer, TS6121C Ethernet 10/100; Aggiornato: NO; Costo: 0
footprint SOIC127P910-16-TX
pins: 1 TD+, 2 CT, 3 TD-, 6 RD+, 7 CT, 8 RD-, 9 RX-, 10 CT, 11 RX+, 14 TX-, 15 CT, 16 TX+

## TRANSFORMER_WE_749020010A
designator T?, comment TRANSFORMER WE 749020010A
TRANSFORMER WE 749020010A 1 Gbit; Aggiornato: S; Costo: 0,68; Detail: 0,68€ offerta WE A19IT013327; ContoLavoro: 0
footprint TrasformatoreWE_749020010A
pins: 1 CD1, 2 D1+, 3 D1-, 4 CD2, 5 D2+, 6 D2-, 7 CD3, 8 D3+, 9 D3-, 10 CD4, 11 D4+, 12 D4-, 13 X4-, 14 X4+, 15 CX4, 16 X3-, 17 X3+, 18 CX3, 19 X2-, 20 X2+, 21 CX2, 22 X1-, 23 X1+, 24 CX1

## TRANSFORMER_WE_750311993
designator TR?
HPcode: TRANSF0001; Costo: 1,5; Aggiornato: NO; ContoLavoro: 0
footprint TRANSFORMER_WE_750311993
pins: 1 IN1, 2 IN2, 3 IN3, 4 IN4, 5 OUT5, 6 OUT6, 7 OUT7, 8 OUT8

## TRANSFORMER_WE_7490100110A
designator T?, comment TRANSFORMER WE 7490100110A
Aggiornato: S; Costo: 0,68; Detail: 0,68€ offerta WE A19IT013327; ContoLavoro: 0
footprint TrasformatoreWE_7490100110A
pins: 1 TD+, 2 CTD, 3 TD-, 6 RD+, 7 CRD, 8 RD-, 9 RX-, 10 CRX, 11 RX+, 14 TX-, 15 CTX, 16 TX+

## TRIMMER_50K BOURNS
designator POT?, comment TRIMMER 50K BOURNS
Detail: (RS per >1000pz); Costo: 0,56; Aggiornato: NO; ContoLavoro: 0
footprint TRIMMER ORIZ
pins: 1 A, 2 B, 3 C

## TRIMMER_50K BOURNS 3386G-1-503LF
designator POT?, comment TRIMMER 50K BOURNS 3386G-1-503LF
Detail: (RS per >1000pz); Costo: 0,56; Aggiornato: NO; ContoLavoro: 0
footprint TRIMMER 50K BOURNS 3386G-1-503LF
pins: 1 A, 2 B, 3 C

## TRIMMER_50K CERMET TE 3203X503P SMD
designator POT?, comment TRIMMER 50K CERMET TE 3203X503P SMD
Detail: (RS per >10pz); Costo: 0,85; Aggiornato: NO; ContoLavoro: 0
footprint TRIMMER_CERMET 3203 SERIE
pins: 1 A, 2 B, 3 C

## TRIMMER_100K CERMET TE 3213X104M SMD
designator POT?, comment TRIMMER 100K CERMET TE 3213X104M SMD
Detail: (RS per >5pz); Costo: 0,98; Aggiornato: NO; ContoLavoro: 0
footprint TRIMMER_ALPS_RH03A3A
pins: 1 A, 2 B, 3 C

## TRIMMER_200R Bourns 3362P
designator POT?, comment TRIMMER 200R Bourns 3362P
Detail: (RS per >10pz); Value: 200; Costo: 0,70; Aggiornato: NO; ContoLavoro: 0
footprint TRIMMER_Bourns_3362P (Footprint not found)
pins: 1 A, 2 B, 3 C

## TRIMMER_MULTIGIRO_1K
designator POT?, comment TRIMMER MULTIGIRO 1K
Aggiornato: NO; ContoLavoro: 0
footprint TRIMMER_T93YB (Footprint not found)
pins: 1 A, 2 B, 3 C

## TRIMMER_MULTIGIRO_10K
designator POT?, comment TRIMMER MULTIGIRO 10K
Detail: (RS per >5pz); Costo: 1,248; Aggiornato: NO; ContoLavoro: 0
footprint TRIMMER_T93YB (Footprint not found)
pins: 1 A, 2 B, 3 C

## TRIMMER_MULTIGIRO_10K_1
designator POT?, comment TRIMMER MULTIGIRO 10K
TRIMMER MULTIGIRO 10K pin in linea; Detail: (RS per >5pz); Costo: 1,248; Aggiornato: NO; ContoLavoro: 0
footprint TRIMMER_3296W (TRIMMER 3296W)
pins: 1 A, 2 B, 3 C

## TRIMMER_MULTIGIRO_100K
designator POT?, comment TRIMMER MULTIGIRO 100K
Detail: (RS per >50pz); Costo: 1,45; Aggiornato: NO; ContoLavoro: 0
footprint TRIMMER_3296W (TRIMMER 3296W)
pins: 1 A, 2 B, 3 C

## TRIMMER_N6S25T0N503
designator POT?, comment PIHER N6-S 50K
PIHER N6S25T0N-503 TRIMMER 50K; Costo: 0; Aggiornato: NO
footprint TRIMMER PIHER N6S
pins: 1 A, 2 B, 3 C

## TRIMMER_POT_1_1
designator POT?, comment POT 470K
TRIMMER 470K BOURS ALT:RS473-574; Costo: 0; Aggiornato: NO
footprint TRIMMER ORIZ
pins: 1 A, 2 B, 3 C

## TSOP4838
designator U?
Ricevitore IR TSOP4838; Aggiornato: no; Costo: 0,66; Detail: controllare footprint e 3d; ContoLavoro: 0
footprint TSOP4838
pins: 1, 2, 3

## TSOP38436
designator U?
Ricevitore IR TSOP38436; Aggiornato: no; Costo: 0,338; Detail: € RS Pz>50; ContoLavoro: 0
footprint TSOP38436 (Footprint not found)
footprint TSOP38436_SMD_FLAT_MOUNT
footprint TSOP38436_SMD_FLAT_MOUNT_ALT
pins: 1 OUT, 2 GND, 3 Vs

## TSOP75536TR
designator U?
Ricevitore IR TSOP75536TR; Aggiornato: no; Costo: 0,43; Detail: € RS pz>20; ContoLavoro: 0
footprint TSOP75536TR (Footprint not found)
pins: 1 GND, 2 Vs, 3 OUT, 4 GND


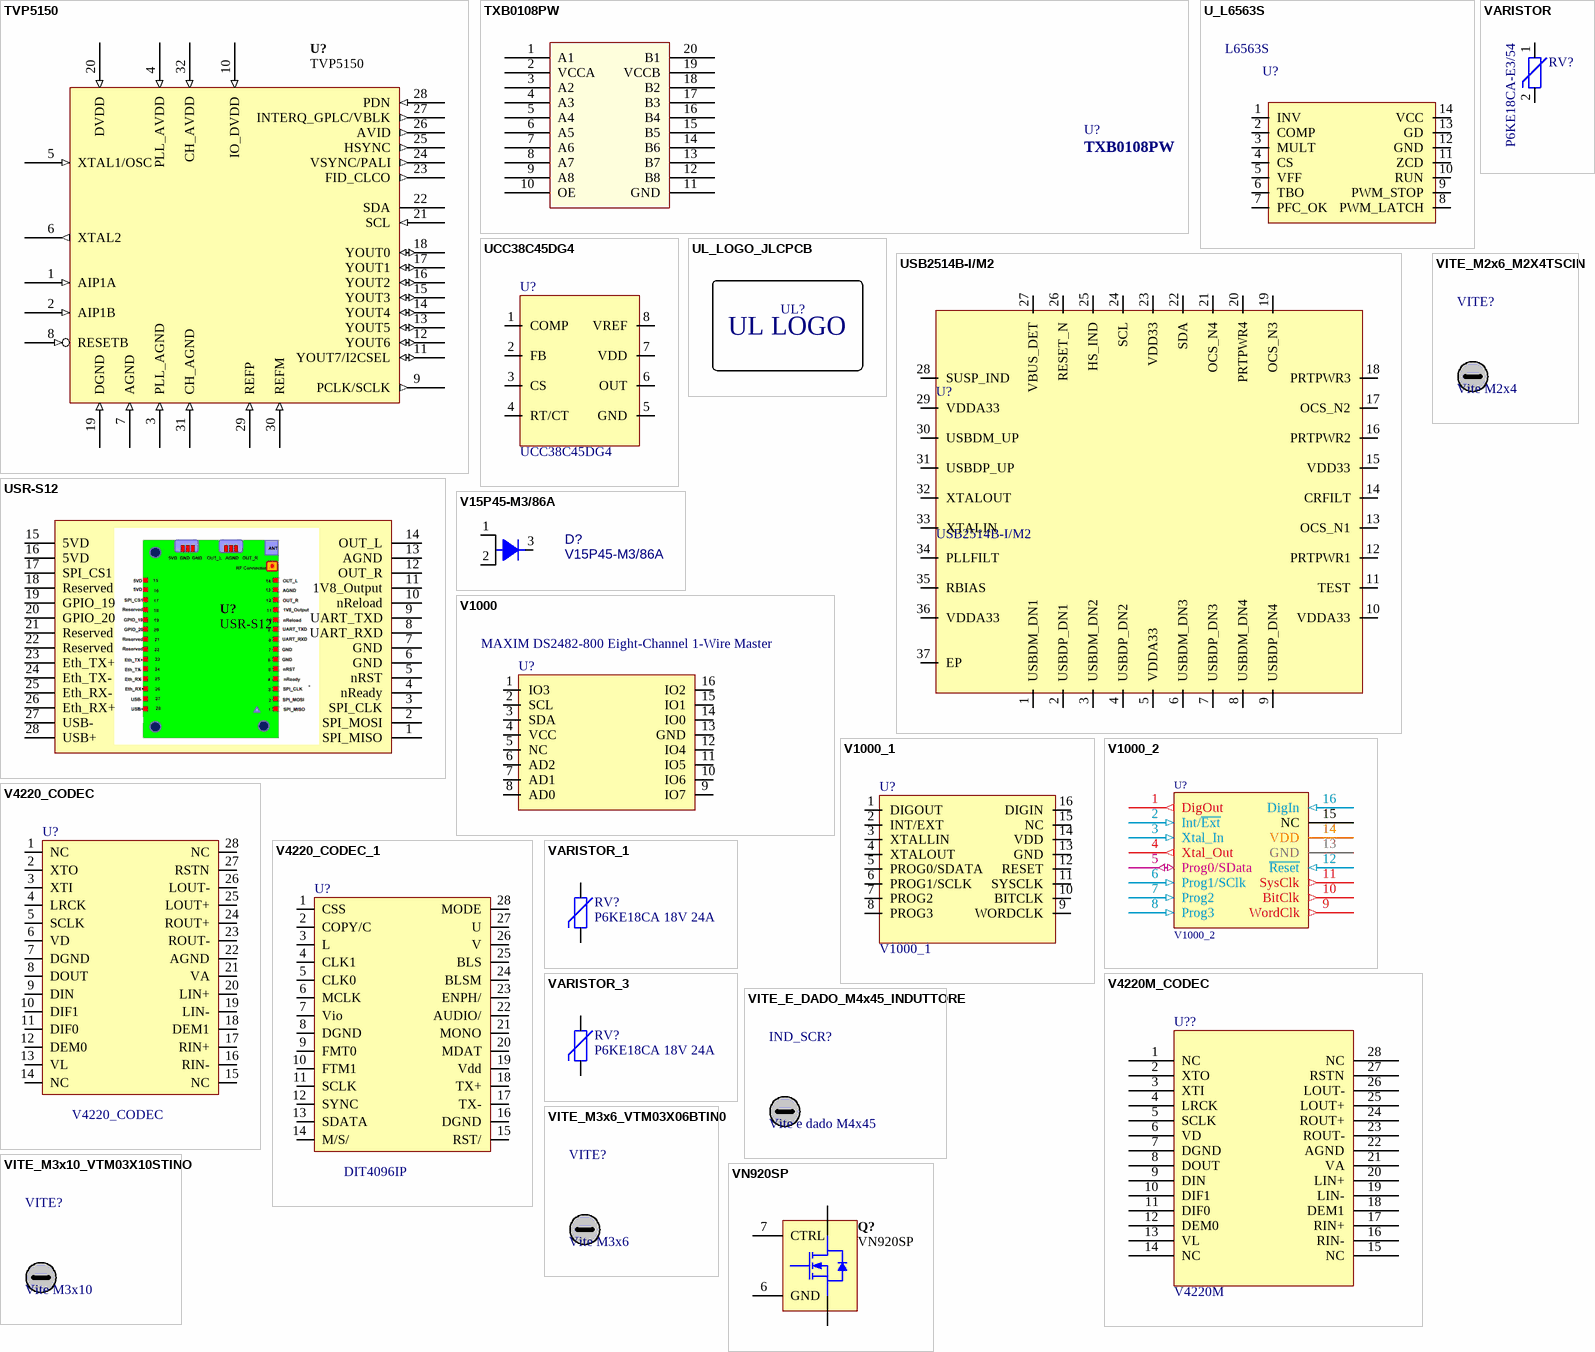
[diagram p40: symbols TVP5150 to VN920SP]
## TVP5150
designator U?
TVP5150AM1PBS, Ultralow Power NTSC/PAL/SECAM Video Decoder With Robust Sync Detector; Aggiornato: NO; Costo: 0
footprint TSQFP50P700X700-32
pins: 1 AIP1A (in), 2 AIP1B (in), 3 PLL_AGND (in), 4 PLL_AVDD (in), 5 XTAL1/OSC (in), 6 XTAL2 (out), 7 AGND (in), 8 RESETB (in), 9 PCLK/SCLK (out), 10 IO_DVDD (in), 11 YOUT7/I2CSEL (io), 12 YOUT6 (io), 13 YOUT5 (io), 14 YOUT4 (io), 15 YOUT3 (io), 16 YOUT2 (io), 17 YOUT1 (io), 18 YOUT0 (io), 19 DGND (in), 20 DVDD (in), 21 SCL (in), 22 SDA (oc), 23 FID_CLCO (out), 24 VSYNC/PALI (out), 25 HSYNC (out), 26 AVID (out), 27 INTERQ_GPLC/VBLK (out), 28 PDN (in), 29 REFP (in), 30 REFM (in), 31 CH_AGND (in), 32 CH_AVDD (in)

## TXB0108PW
designator U?
Detail: 1,12€ RS pz>100; Costo: 1,12; Aggiornato: NO; ContoLavoro: 0
footprint TSSOP20
pins: 1 A1, 2 VCCA, 3 A2, 4 A3, 5 A4, 6 A5, 7 A6, 8 A7, 9 A8, 10 OE, 11 GND, 12 B8, 13 B7, 14 B6, 15 B5, 16 B4, 17 B3, 18 B2, 19 VCCB, 20 B1
2 alternate drawings of the same symbol

## U_L6563S
designator U?, comment L6563S
L6563S TRANSITION-MODE PFC CONTROLLER ST; Costo: 0; Aggiornato: NO
footprint SO14
pins: 1 INV, 2 COMP, 3 MULT, 4 CS, 5 VFF, 6 TBO, 7 PFC_OK, 8 PWM_LATCH, 9 PWM_STOP, 10 RUN, 11 ZCD, 12 GND, 13 GD, 14 VCC

## UCC38C45DG4
designator U?
Costo: 1,534; Aggiornato: NO; ContoLavoro: 0
footprint SO8
pins: 1 COMP, 2 FB, 3 CS, 4 RT/CT, 5 GND, 6 OUT, 7 VDD, 8 VREF

## UL_LOGO_JLCPCB
designator UL?  (value not drawn)
footprint UL_JLCPCB_Multilayer_5mmx2mm (UL_LOGO_JLCPCB_Multilayer)
footprint UL_JLCPCB_Multilayer_10mmx5mm (UL_LOGO_JLCPCB_Multilayer)
footprint UL_JLCPCB_Multilayer_15mmx7mm (UL_LOGO_JLCPCB_Multilayer)
footprint UL_JLCPCB_Multilayer_20mmx10mm (UL_LOGO_JLCPCB_Multilayer)
footprint UL_JLCPCB_Multilayer_25mmx12mm (UL_LOGO_JLCPCB_Multilayer)

## USB2514B-I/M2
designator U?
USB 2.0 Hi-Speed Hub Controlle; Costo: 0,4; Aggiornato: s; ContoLavoro: 0
footprint SQFN36_EP (Footprint not found)
footprint SQFN36_EP_VIAS
pins: 1 USBDM_DN1, 2 USBDP_DN1, 3 USBDM_DN2, 4 USBDP_DN2, 5 VDDA33, 6 USBDM_DN3, 7 USBDP_DN3, 8 USBDM_DN4, 9 USBDP_DN4, 10 VDDA33, 11 TEST, 12 PRTPWR1, 13 OCS_N1, 14 CRFILT, 15 VDD33, 16 PRTPWR2, 17 OCS_N2, 18 PRTPWR3, 19 OCS_N3, 20 PRTPWR4, 21 OCS_N4, 22 SDA, 23 VDD33, 24 SCL, 25 HS_IND, 26 RESET_N, 27 VBUS_DET, 28 SUSP_IND, 29 VDDA33, 30 USBDM_UP, 31 USBDP_UP, 32 XTALOUT, 33 XTALIN, 34 PLLFILT, 35 RBIAS, 36 VDDA33, 37 EP

## USR-S12
designator U?
USR-S12 WI-FI Audio Module; Aggiornato: NO; Costo: 0
pins: 1 SPI_MISO, 2 SPI_MOSI, 3 SPI_CLK, 4 nReady, 5 nRST, 6 GND, 7 GND, 8 UART_RXD, 9 UART_TXD, 10 nReload, 11 1V8_Output, 12 OUT_R, 13 AGND, 14 OUT_L, 15 5VD, 16 5VD, 17 SPI_CS1, 18 Reserved, 19 GPIO_19, 20 GPIO_20, 21 Reserved, 22 Reserved, 23 Eth_TX+, 24 Eth_TX-, 25 Eth_RX-, 26 Eth_RX+, 27 USB-, 28 USB+

## V15P45-M3/86A
designator D?
V15P45-M3/86A Diodo e raddrizzatore Schottky 15 Amp 45 Volt; Detail: € pz. 1.00; Aggiornato: S; Costo: 0,772; ContoLavoro: 0
footprint V15P45-M3/86A
pins: 1, 2, 3

## V1000
designator U?, comment MAXIM DS2482-800 Eight-Channel 1-Wire Master
Aggiornato: NO; Costo: 0
footprint SO16
pins: 1 IO3, 2 SCL, 3 SDA, 4 VCC, 5 NC, 6 AD2, 7 AD1, 8 AD0, 9 IO7, 10 IO6, 11 IO5, 12 IO4, 13 GND, 14 IO0, 15 IO1, 16 IO2

## V1000_1
designator U?
Aggiornato: NO; Costo: 0
footprint SOIC127P1030-16N (SOIC, 16-Leads, Body 10.3x7.5mm, Pitch 1.27mm, IPC Medium Density)
pins: 1 DIGOUT, 2 INT/EXT, 3 XTALLIN, 4 XTALOUT, 5 PROG0/SDATA, 6 PROG1/SCLK, 7 PROG2, 8 PROG3, 9 WORDCLK, 10 BITCLK, 11 SYSCLK, 12 RESET, 13 GND, 14 VDD, 15 NC, 16 DIGIN

## V1000_2
designator U?
Low-Cost One-Chip Multi-Effects DSP; Part Field 1: COOLAUDIO V1000; Aggiornato: NO; Costo: 0
footprint SOIC300-16N (SOIC, 16-Leads, Body 10.3x7.5mm, Pitch 1.27mm, IPC Medium Density)
pins: 1 DigOut (out), 2 Int/~{Ext} (in), 3 Xtal_In (in), 4 Xtal_Out (out), 5 Prog0/SData (io), 6 Prog1/SClk (in), 7 Prog2 (in), 8 Prog3 (in), 9 WordClk (out), 10 BitClk (out), 11 SysClk (out), 12 ~{Reset} (in), 13 GND (power), 14 VDD (power), 15 NC, 16 DigIn (in)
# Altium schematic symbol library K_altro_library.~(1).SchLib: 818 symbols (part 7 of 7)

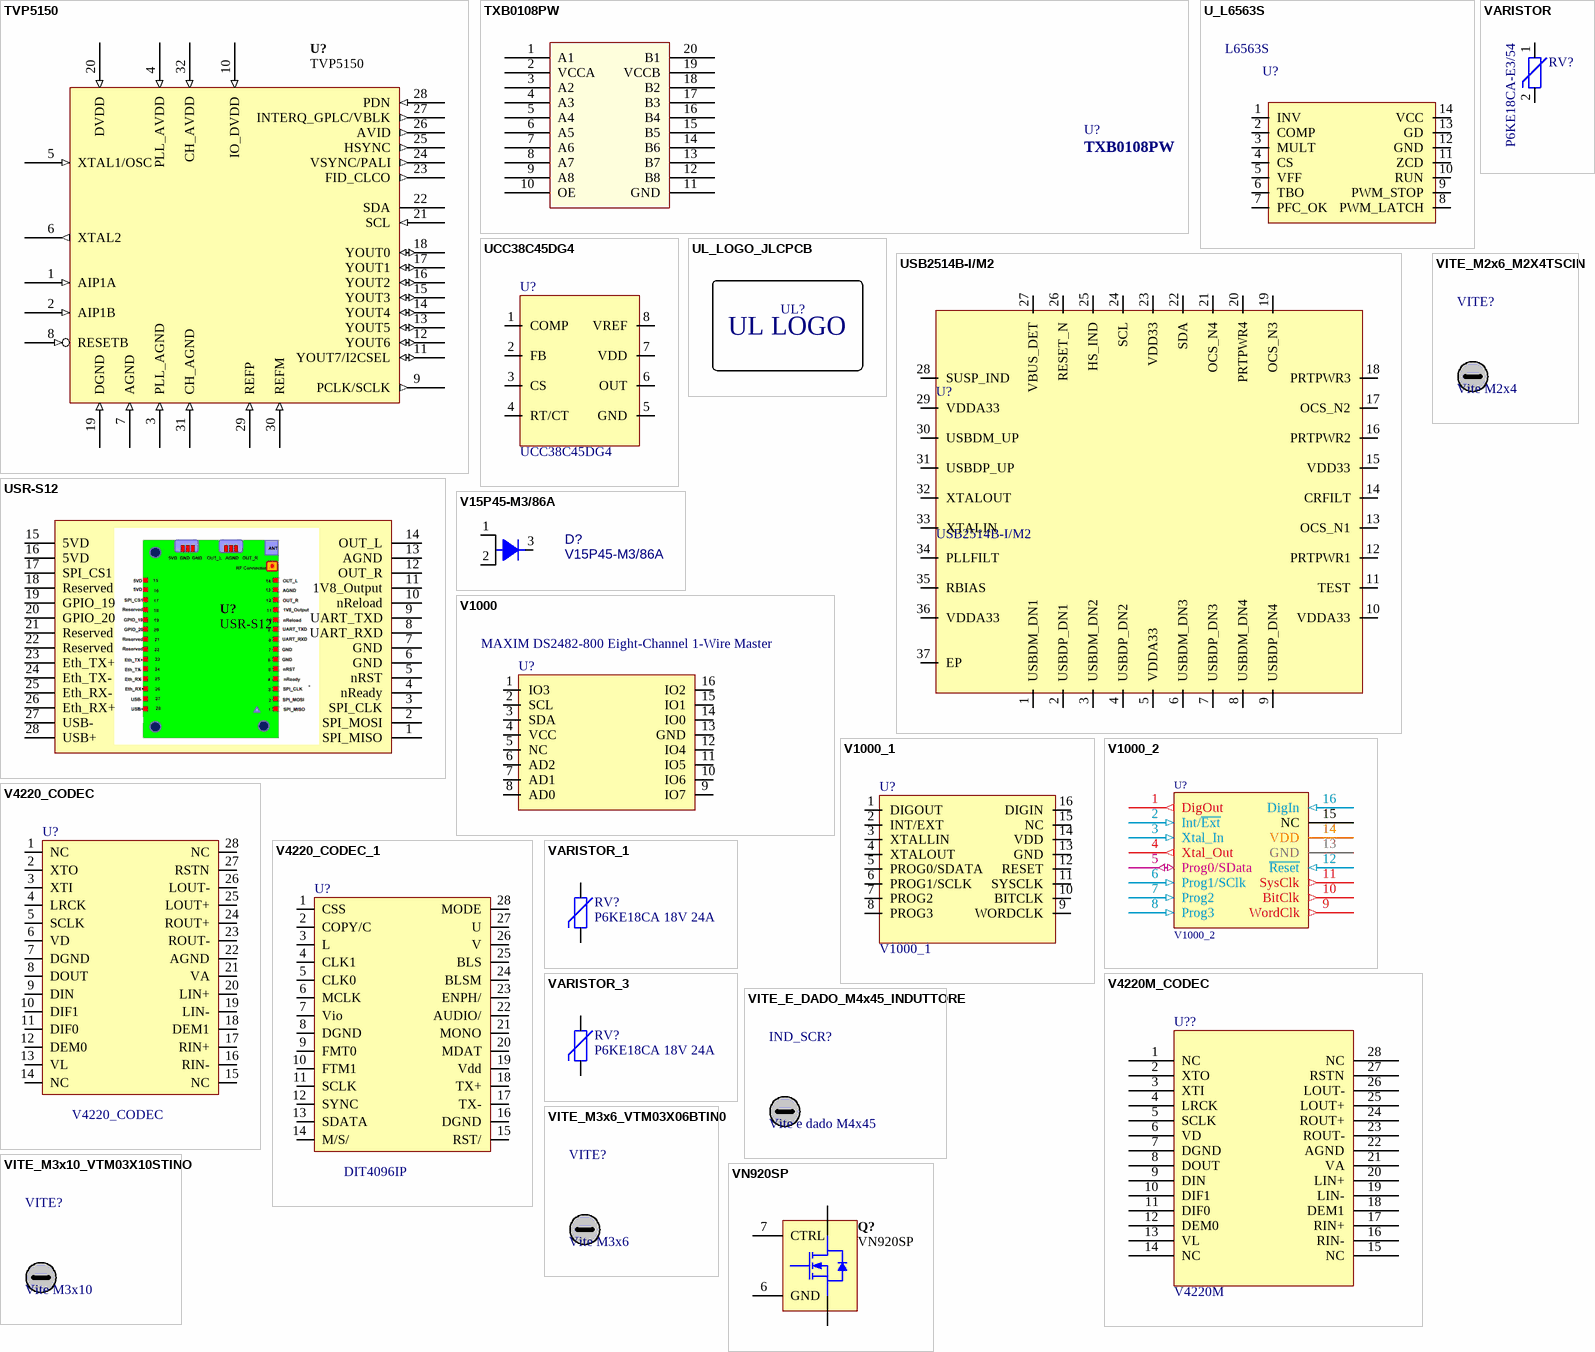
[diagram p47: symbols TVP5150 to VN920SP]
## V4220_CODEC
designator U?
Aggiornato: NO; Costo: 0
footprint SSOP-28 (SOP, 28-Leads, Body 10,5x5,6mm (max), Pitch 0,65mm, IPC Medium Density)
pins: 1 NC, 2 XTO, 3 XTI, 4 LRCK, 5 SCLK, 6 VD, 7 DGND, 8 DOUT, 9 DIN, 10 DIF1, 11 DIF0, 12 DEM0, 13 VL, 14 NC, 15 NC, 16 RIN-, 17 RIN+, 18 DEM1, 19 LIN-, 20 LIN+, 21 VA, 22 AGND, 23 ROUT-, 24 ROUT+, 25 LOUT+, 26 LOUT-, 27 RSTN, 28 NC

## V4220_CODEC_1
designator U?, comment DIT4096IP
Aggiornato: NO; Costo: 0
footprint SSOP-28 (SOP, 28-Leads, Body 10,5x5,6mm (max), Pitch 0,65mm, IPC Medium Density)
pins: 1 CSS, 2 COPY/C, 3 L, 4 CLK1, 5 CLK0, 6 MCLK, 7 Vio, 8 DGND, 9 FMT0, 10 FTM1, 11 SCLK, 12 SYNC, 13 SDATA, 14 M/S/, 15 RST/, 16 DGND, 17 TX-, 18 TX+, 19 Vdd, 20 MDAT, 21 MONO, 22 AUDIO/, 23 ENPH/, 24 BLSM, 25 BLS, 26 V, 27 U, 28 MODE

## V4220M_CODEC
designator U??, comment V4220M
24-Bit Stereo Codec with 110dB SNR; Aggiornato: NO; Costo: 0
footprint SSOP-28 (SOP, 28-Leads, Body 10,5x5,6mm (max), Pitch 0,65mm, IPC Medium Density)
pins: 1 NC, 2 XTO, 3 XTI, 4 LRCK, 5 SCLK, 6 VD, 7 DGND, 8 DOUT, 9 DIN, 10 DIF1, 11 DIF0, 12 DEM0, 13 VL, 14 NC, 15 NC, 16 RIN-, 17 RIN+, 18 DEM1, 19 LIN-, 20 LIN+, 21 VA, 22 AGND, 23 ROUT-, 24 ROUT+, 25 LOUT+, 26 LOUT-, 27 RSTN, 28 NC

## VARISTOR
designator RV?, comment P6KE18CA-E3/54
VARISTORE VISHAY P6KE18CA-E3/54 ALT:RS 699-7972; Costo: 0,155; Aggiornato: NO; ContoLavoro: 0
footprint DO15
pins: 1, 2

## VARISTOR_1
designator RV?, comment P6KE18CA 18V 24A
P6KE18CA 18V 24A MOD. ST REEL(1000); Costo: 0; Aggiornato: NO
footprint VAR-W3.18-L20.83-P7.62X2.54/10.16X2.54-DR1.25
footprint DO15
footprint DO214AA_1
pins: 1, 2

## VARISTOR_3
designator RV?, comment P6KE18CA 18V 24A
Costo: 0; Aggiornato: NO
footprint VAR-W3.18-L20.83-P7.62X2.54/10.16X2.54-DR1.25
footprint P6KE-LF_1
footprint DO214AA_1
pins: 1, 2

## VITE_E_DADO_M4x45_INDUTTORE
designator IND_SCR?, comment Vite e dado M4x45  (mechanical)
Costo: 0; Aggiornato: NO
pins: 1 hidden
1 alternate drawing of the same symbol

## VITE_M2x6_M2X4TSCIN
designator VITE?, comment Vite M2x4  (mechanical)
Costo: 0,0070; Hpcode: M2X4TSCIN; Aggiornato: s; ContoLavoro: 1
pins: 1 hidden
1 alternate drawing of the same symbol

## VITE_M3x6_VTM03X06BTIN0
designator VITE?, comment Vite M3x6  (mechanical)
Costo: 0,0070; Hpcode: VTM03X06BTIN0; Aggiornato: s; ContoLavoro: 1
pins: 1 hidden
1 alternate drawing of the same symbol

## VITE_M3x10_VTM03X10STINO
designator VITE?, comment Vite M3x10  (mechanical)
Costo: 0,02; Hpcode: VTM03X10STINO; Aggiornato: s; ContoLavoro: 1
pins: 1 hidden
1 alternate drawing of the same symbol

## VN920SP
designator Q?
Single Channel High Side SSR; Rated Voltage: mV; Switch Type: SPDT; Aggiornato: NO; Costo: 0
footprint PowerSO-10_M
pins: 1 OUTPUT, 2 OUTPUT, 4 OUTPUT, 5 OUTPUT, 6 GND, 7 CTRL, 11 VCC


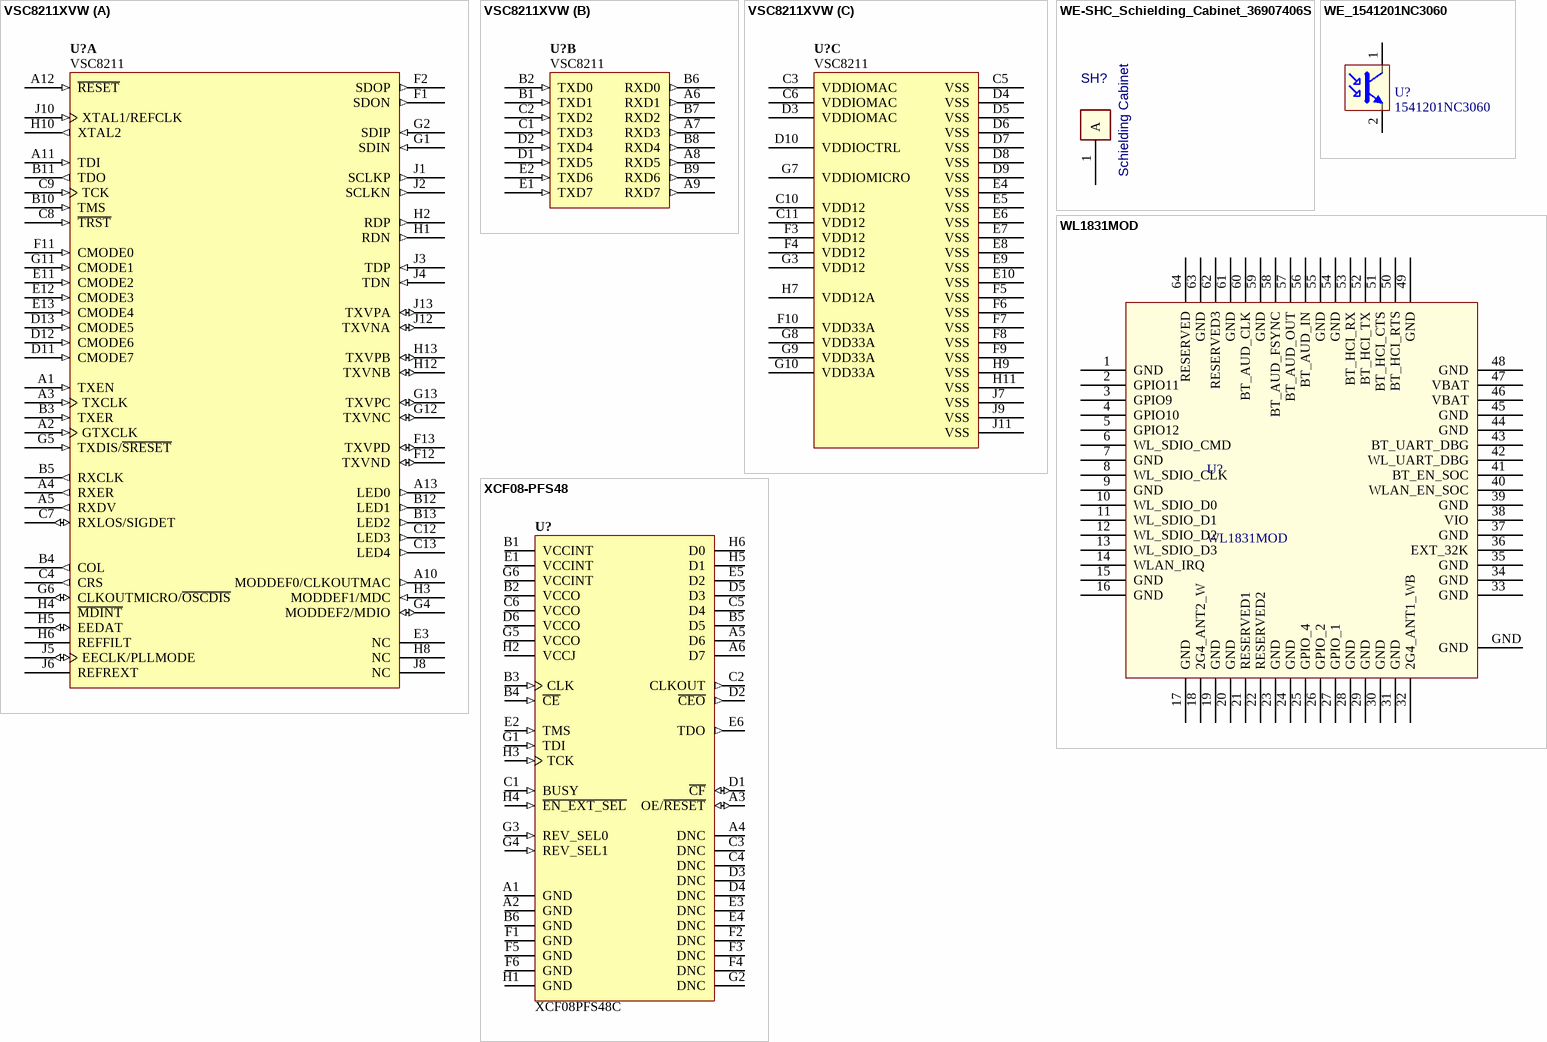
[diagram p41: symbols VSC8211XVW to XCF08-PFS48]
## VSC8211XVW
designator U?, comment VSC8211
Ethernet PHY, Gigabit, Vitesse, VSC8211; Aggiornato: NO; Costo: 0
footprint BGA117C100P9X13_1000X1400X170
part A pins: A1 TXEN (in), A2 GTXCLK (in), A3 TXCLK (in), A4 RXER (out), A5 RXDV (out), A10 MODDEF0/CLKOUTMAC (out), A11 TDI (in), A12 ~{RESET} (in), A13 LED0 (out), B3 TXER (in), B4 COL (out), B5 RXCLK (out), B10 TMS (in), B11 TDO (out), B12 LED1 (out), B13 LED2 (out), C4 CRS (out), C7 RXLOS/SIGDET (io), C8 ~{TRST} (in), C9 TCK (in), C12 LED3 (out), C13 LED4 (out), D11 CMODE7 (in), D12 CMODE6 (in), D13 CMODE5 (in), E3 NC, E11 CMODE2 (in), E12 CMODE3 (in), E13 CMODE4 (in), F1 SDON (out), F2 SDOP (out), F11 CMODE0 (in), F12 TXVND (io), F13 TXVPD (io), G1 SDIN (in), G2 SDIP (in), G4 MODDEF2/MDIO (io), G5 TXDIS/~{SRESET} (in), G6 CLKOUTMICRO/~{OSCDIS} (io), G11 CMODE1 (in), G12 TXVNC (io), G13 TXVPC (io), H1 RDN (out), H2 RDP (out), H3 MODDEF1/MDC (in), H4 ~{MDINT} (oc), H5 EEDAT (io), H6 REFFILT, H8 NC, H10 XTAL2 (out), H12 TXVNB (io), H13 TXVPB (io), J1 SCLKP (out), J2 SCLKN (out), J3 TDP (in), J4 TDN (in), J5 EECLK/PLLMODE (io), J6 REFREXT, J8 NC, J10 XTAL1/REFCLK (in), J12 TXVNA (io), J13 TXVPA (io)
part B pins: A6 RXD1 (out), A7 RXD3 (out), A8 RXD5 (out), A9 RXD7 (out), B1 TXD1 (in), B2 TXD0 (in), B6 RXD0 (out), B7 RXD2 (out), B8 RXD4 (out), B9 RXD6 (out), C1 TXD3 (in), C2 TXD2 (in), D1 TXD5 (in), D2 TXD4 (in), E1 TXD7 (in), E2 TXD6 (in)
part C pins: C3 VDDIOMAC (power), C5 VSS (power), C6 VDDIOMAC (power), C10 VDD12 (power), C11 VDD12 (power), D3 VDDIOMAC (power), D4 VSS (power), D5 VSS (power), D6 VSS (power), D7 VSS (power), D8 VSS (power), D9 VSS (power), D10 VDDIOCTRL (power), E4 VSS (power), E5 VSS (power), E6 VSS (power), E7 VSS (power), E8 VSS (power), E9 VSS (power), E10 VSS (power), F3 VDD12 (power), F4 VDD12 (power), F5 VSS (power), F6 VSS (power), F7 VSS (power), F8 VSS (power), F9 VSS (power), F10 VDD33A (power), G3 VDD12 (power), G7 VDDIOMICRO (power), G8 VDD33A (power), G9 VDD33A (power), G10 VDD33A (power), H7 VDD12A (power), H9 VSS (power), H11 VSS (power), J7 VSS (power), J9 VSS (power), J11 VSS (power)

## WE-SHC_Schielding_Cabinet_36907406S
designator SH?, comment Schielding Cabinet
Detail: 0,85€ pz Offerta A19IT015981; Aggiornato: S; Costo: 0,85; ContoLavoro: 0
footprint WE_36907406S (WurthElektronik 36907406S WE-SHC Shielding Cabinet)
pins: 1 A

## WE_1541201NC3060
designator U?, comment 1541201NC3060
IR Phototransistor WE 1541201NC3060; Aggiornato: no; Costo: 0
footprint 1206_REVERSE_IRLED_WE_1541201NC3060
pins: 1 c, 2 e

## WL1831MOD
designator U?
Costo: 16,5; Aggiornato: NO; Detail: 16,5€ Farnell Pz>100; ContoLavoro: 0
footprint WL18XX_E-13.4X13.3-N100_0.75
pins: 1 GND, 2 GPIO11, 3 GPIO9, 4 GPIO10, 5 GPIO12, 6 WL_SDIO_CMD, 7 GND, 8 WL_SDIO_CLK, 9 GND, 10 WL_SDIO_D0, 11 WL_SDIO_D1, 12 WL_SDIO_D2, 13 WL_SDIO_D3, 14 WLAN_IRQ, 15 GND, 16 GND, 17 GND, 18 2G4_ANT2_W, 19 GND, 20 GND, 21 RESERVED1, 22 RESERVED2, 23 GND, 24 GND, 25 GPIO_4, 26 GPIO_2, 27 GPIO_1, 28 GND, 29 GND, 30 GND, 31 GND, 32 2G4_ANT1_WB, 33 GND, 34 GND, 35 GND, 36 EXT_32K, 37 GND, 38 VIO, 39 GND, 40 WLAN_EN_SOC, 41 BT_EN_SOC, 42 WL_UART_DBG, 43 BT_UART_DBG, 44 GND, 45 GND, 46 VBAT, 47 VBAT, 48 GND, 49 GND, 50 BT_HCI_RTS, 51 BT_HCI_CTS, 52 BT_HCI_TX, 53 BT_HCI_RX, 54 GND, 55 GND, 56 BT_AUD_IN, 57 BT_AUD_OUT, 58 BT_AUD_FSYNC, 59 GND, 60 BT_AUD_CLK, 61 GND, 62 RESERVED3, 63 GND, 64 RESERVED, GND

## XCF08-PFS48
designator U?, comment XCF08PFS48C
XCF00P Series, Platform Flash In-System Programmable Configuration 1.8V PROM, 48 Ball BGA, 8-Megabit, Commercial Grade; Aggiornato: NO; Costo: 0
footprint BGA80P8X6-48
pins: A1 GND (power), A2 GND (power), A3 OE/~{RESET} (io), A4 DNC, A5 D6 (hiz), A6 D7 (hiz), B1 VCCINT (power), B2 VCCO (power), B3 CLK (in), B4 ~{CE} (in), B5 D5 (hiz), B6 GND (power), C1 BUSY (in), C2 CLKOUT (out), C3 DNC, C4 DNC, C5 D4 (hiz), C6 VCCO (power), D1 ~{CF} (io), D2 ~{CEO} (out), D3 DNC, D4 DNC, D5 D3 (hiz), D6 VCCO (power), E1 VCCINT (power), E2 TMS (in), E3 DNC, E4 DNC, E5 D2 (hiz), E6 TDO (out), F1 GND (power), F2 DNC, F3 DNC, F4 DNC, F5 GND (power), F6 GND (power), G1 TDI (in), G2 DNC, G3 REV_SEL0 (in), G4 REV_SEL1 (in), G5 VCCO (power), G6 VCCINT (power), H1 GND (power), H2 VCCJ (power), H3 TCK (in), H4 ~{EN_EXT_SEL} (in), H5 D1 (hiz), H6 D0 (hiz)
